VERSION 5.7 ;
BUSBITCHARS "[]" ;
DIVIDERCHAR "/" ;

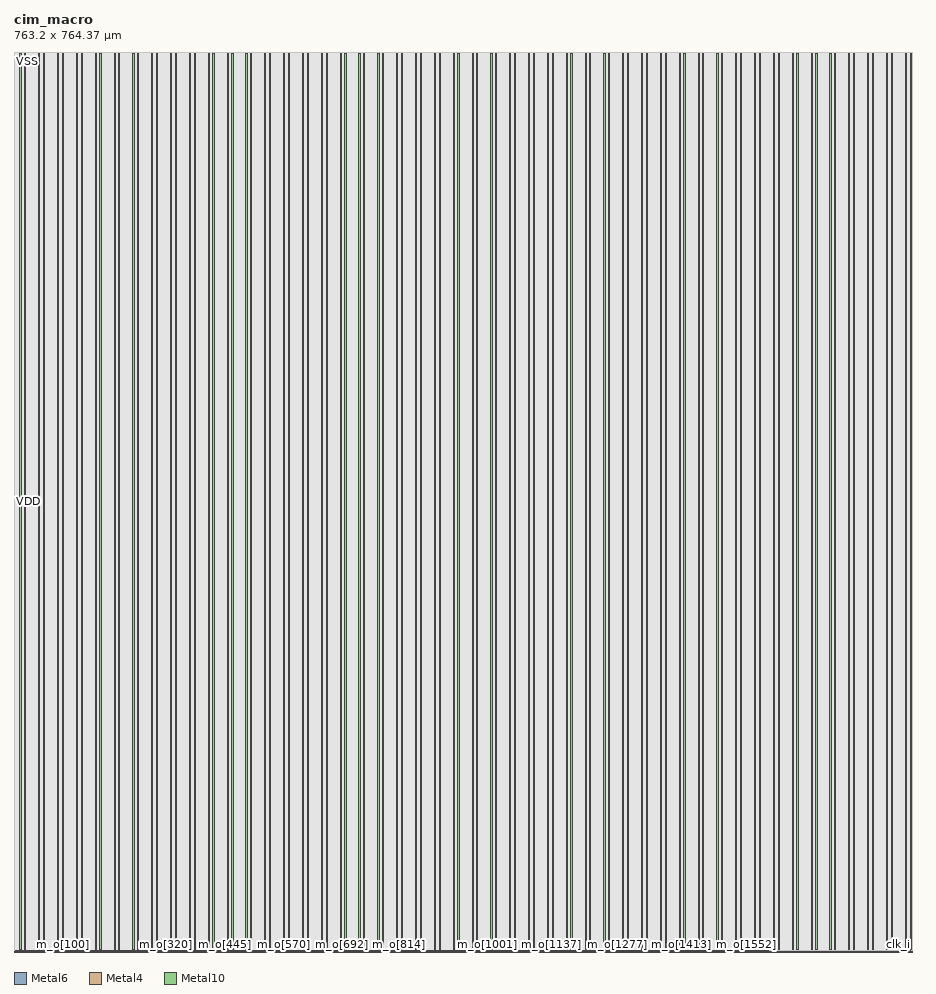
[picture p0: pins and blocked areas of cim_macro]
MACRO cim_macro
  CLASS BLOCK ;
  ORIGIN 0 0 ;
  FOREIGN cim_macro 0 0 ;
  SIZE 763.2 BY 764.37 ;
  SYMMETRY X Y R90 ;
  PIN clk_i
    DIRECTION INPUT ;
    USE CLOCK ;
    PORT
      LAYER Metal6 ;
        RECT 761.200 0 761.280 1.0 ;
    END
  END clk_i
  PIN m_valid_o
    DIRECTION OUTPUT ;
    USE SIGNAL ;
    PORT
      LAYER Metal4 ;
        RECT 1.000 0.000 1.080 1.000 ;
    END
  END m_valid_o
  PIN m_o[0]
    DIRECTION OUTPUT ;
    USE SIGNAL ;
    PORT
      LAYER Metal4 ;
        RECT 1.400 0.000 1.480 1.000 ;
    END
  END m_o[0]
  PIN m_o[1]
    DIRECTION OUTPUT ;
    USE SIGNAL ;
    PORT
      LAYER Metal4 ;
        RECT 1.800 0.000 1.880 1.000 ;
    END
  END m_o[1]
  PIN m_o[2]
    DIRECTION OUTPUT ;
    USE SIGNAL ;
    PORT
      LAYER Metal4 ;
        RECT 2.200 0.000 2.280 1.000 ;
    END
  END m_o[2]
  PIN m_o[3]
    DIRECTION OUTPUT ;
    USE SIGNAL ;
    PORT
      LAYER Metal4 ;
        RECT 2.600 0.000 2.680 1.000 ;
    END
  END m_o[3]
  PIN m_o[4]
    DIRECTION OUTPUT ;
    USE SIGNAL ;
    PORT
      LAYER Metal4 ;
        RECT 3.000 0.000 3.080 1.000 ;
    END
  END m_o[4]
  PIN m_o[5]
    DIRECTION OUTPUT ;
    USE SIGNAL ;
    PORT
      LAYER Metal4 ;
        RECT 3.400 0.000 3.480 1.000 ;
    END
  END m_o[5]
  PIN m_o[6]
    DIRECTION OUTPUT ;
    USE SIGNAL ;
    PORT
      LAYER Metal4 ;
        RECT 3.800 0.000 3.880 1.000 ;
    END
  END m_o[6]
  PIN m_o[7]
    DIRECTION OUTPUT ;
    USE SIGNAL ;
    PORT
      LAYER Metal4 ;
        RECT 4.200 0.000 4.280 1.000 ;
    END
  END m_o[7]
  PIN m_o[8]
    DIRECTION OUTPUT ;
    USE SIGNAL ;
    PORT
      LAYER Metal4 ;
        RECT 4.600 0.000 4.680 1.000 ;
    END
  END m_o[8]
  PIN m_o[9]
    DIRECTION OUTPUT ;
    USE SIGNAL ;
    PORT
      LAYER Metal4 ;
        RECT 5.000 0.000 5.080 1.000 ;
    END
  END m_o[9]
  PIN m_o[10]
    DIRECTION OUTPUT ;
    USE SIGNAL ;
    PORT
      LAYER Metal4 ;
        RECT 5.400 0.000 5.480 1.000 ;
    END
  END m_o[10]
  PIN m_o[11]
    DIRECTION OUTPUT ;
    USE SIGNAL ;
    PORT
      LAYER Metal4 ;
        RECT 5.800 0.000 5.880 1.000 ;
    END
  END m_o[11]
  PIN m_o[12]
    DIRECTION OUTPUT ;
    USE SIGNAL ;
    PORT
      LAYER Metal4 ;
        RECT 6.200 0.000 6.280 1.000 ;
    END
  END m_o[12]
  PIN m_o[13]
    DIRECTION OUTPUT ;
    USE SIGNAL ;
    PORT
      LAYER Metal4 ;
        RECT 6.600 0.000 6.680 1.000 ;
    END
  END m_o[13]
  PIN m_o[14]
    DIRECTION OUTPUT ;
    USE SIGNAL ;
    PORT
      LAYER Metal4 ;
        RECT 7.000 0.000 7.080 1.000 ;
    END
  END m_o[14]
  PIN m_o[15]
    DIRECTION OUTPUT ;
    USE SIGNAL ;
    PORT
      LAYER Metal4 ;
        RECT 7.400 0.000 7.480 1.000 ;
    END
  END m_o[15]
  PIN m_o[16]
    DIRECTION OUTPUT ;
    USE SIGNAL ;
    PORT
      LAYER Metal4 ;
        RECT 7.800 0.000 7.880 1.000 ;
    END
  END m_o[16]
  PIN m_o[17]
    DIRECTION OUTPUT ;
    USE SIGNAL ;
    PORT
      LAYER Metal4 ;
        RECT 8.200 0.000 8.280 1.000 ;
    END
  END m_o[17]
  PIN m_o[18]
    DIRECTION OUTPUT ;
    USE SIGNAL ;
    PORT
      LAYER Metal4 ;
        RECT 8.600 0.000 8.680 1.000 ;
    END
  END m_o[18]
  PIN m_o[19]
    DIRECTION OUTPUT ;
    USE SIGNAL ;
    PORT
      LAYER Metal4 ;
        RECT 9.000 0.000 9.080 1.000 ;
    END
  END m_o[19]
  PIN m_o[20]
    DIRECTION OUTPUT ;
    USE SIGNAL ;
    PORT
      LAYER Metal4 ;
        RECT 9.400 0.000 9.480 1.000 ;
    END
  END m_o[20]
  PIN m_o[21]
    DIRECTION OUTPUT ;
    USE SIGNAL ;
    PORT
      LAYER Metal4 ;
        RECT 9.800 0.000 9.880 1.000 ;
    END
  END m_o[21]
  PIN m_o[22]
    DIRECTION OUTPUT ;
    USE SIGNAL ;
    PORT
      LAYER Metal4 ;
        RECT 10.200 0.000 10.280 1.000 ;
    END
  END m_o[22]
  PIN m_o[23]
    DIRECTION OUTPUT ;
    USE SIGNAL ;
    PORT
      LAYER Metal4 ;
        RECT 10.600 0.000 10.680 1.000 ;
    END
  END m_o[23]
  PIN m_o[24]
    DIRECTION OUTPUT ;
    USE SIGNAL ;
    PORT
      LAYER Metal4 ;
        RECT 11.000 0.000 11.080 1.000 ;
    END
  END m_o[24]
  PIN m_o[25]
    DIRECTION OUTPUT ;
    USE SIGNAL ;
    PORT
      LAYER Metal4 ;
        RECT 11.400 0.000 11.480 1.000 ;
    END
  END m_o[25]
  PIN m_o[26]
    DIRECTION OUTPUT ;
    USE SIGNAL ;
    PORT
      LAYER Metal4 ;
        RECT 11.800 0.000 11.880 1.000 ;
    END
  END m_o[26]
  PIN m_o[27]
    DIRECTION OUTPUT ;
    USE SIGNAL ;
    PORT
      LAYER Metal4 ;
        RECT 12.200 0.000 12.280 1.000 ;
    END
  END m_o[27]
  PIN m_o[28]
    DIRECTION OUTPUT ;
    USE SIGNAL ;
    PORT
      LAYER Metal4 ;
        RECT 12.600 0.000 12.680 1.000 ;
    END
  END m_o[28]
  PIN m_o[29]
    DIRECTION OUTPUT ;
    USE SIGNAL ;
    PORT
      LAYER Metal4 ;
        RECT 13.000 0.000 13.080 1.000 ;
    END
  END m_o[29]
  PIN m_o[30]
    DIRECTION OUTPUT ;
    USE SIGNAL ;
    PORT
      LAYER Metal4 ;
        RECT 13.400 0.000 13.480 1.000 ;
    END
  END m_o[30]
  PIN m_o[31]
    DIRECTION OUTPUT ;
    USE SIGNAL ;
    PORT
      LAYER Metal4 ;
        RECT 13.800 0.000 13.880 1.000 ;
    END
  END m_o[31]
  PIN m_o[32]
    DIRECTION OUTPUT ;
    USE SIGNAL ;
    PORT
      LAYER Metal4 ;
        RECT 14.200 0.000 14.280 1.000 ;
    END
  END m_o[32]
  PIN m_o[33]
    DIRECTION OUTPUT ;
    USE SIGNAL ;
    PORT
      LAYER Metal4 ;
        RECT 14.600 0.000 14.680 1.000 ;
    END
  END m_o[33]
  PIN m_o[34]
    DIRECTION OUTPUT ;
    USE SIGNAL ;
    PORT
      LAYER Metal4 ;
        RECT 15.000 0.000 15.080 1.000 ;
    END
  END m_o[34]
  PIN m_o[35]
    DIRECTION OUTPUT ;
    USE SIGNAL ;
    PORT
      LAYER Metal4 ;
        RECT 15.400 0.000 15.480 1.000 ;
    END
  END m_o[35]
  PIN m_o[36]
    DIRECTION OUTPUT ;
    USE SIGNAL ;
    PORT
      LAYER Metal4 ;
        RECT 15.800 0.000 15.880 1.000 ;
    END
  END m_o[36]
  PIN m_o[37]
    DIRECTION OUTPUT ;
    USE SIGNAL ;
    PORT
      LAYER Metal4 ;
        RECT 16.200 0.000 16.280 1.000 ;
    END
  END m_o[37]
  PIN m_o[38]
    DIRECTION OUTPUT ;
    USE SIGNAL ;
    PORT
      LAYER Metal4 ;
        RECT 16.600 0.000 16.680 1.000 ;
    END
  END m_o[38]
  PIN m_o[39]
    DIRECTION OUTPUT ;
    USE SIGNAL ;
    PORT
      LAYER Metal4 ;
        RECT 17.000 0.000 17.080 1.000 ;
    END
  END m_o[39]
  PIN m_o[40]
    DIRECTION OUTPUT ;
    USE SIGNAL ;
    PORT
      LAYER Metal4 ;
        RECT 17.400 0.000 17.480 1.000 ;
    END
  END m_o[40]
  PIN m_o[41]
    DIRECTION OUTPUT ;
    USE SIGNAL ;
    PORT
      LAYER Metal4 ;
        RECT 17.800 0.000 17.880 1.000 ;
    END
  END m_o[41]
  PIN m_o[42]
    DIRECTION OUTPUT ;
    USE SIGNAL ;
    PORT
      LAYER Metal4 ;
        RECT 18.200 0.000 18.280 1.000 ;
    END
  END m_o[42]
  PIN m_o[43]
    DIRECTION OUTPUT ;
    USE SIGNAL ;
    PORT
      LAYER Metal4 ;
        RECT 18.600 0.000 18.680 1.000 ;
    END
  END m_o[43]
  PIN m_o[44]
    DIRECTION OUTPUT ;
    USE SIGNAL ;
    PORT
      LAYER Metal4 ;
        RECT 19.000 0.000 19.080 1.000 ;
    END
  END m_o[44]
  PIN m_o[45]
    DIRECTION OUTPUT ;
    USE SIGNAL ;
    PORT
      LAYER Metal4 ;
        RECT 19.400 0.000 19.480 1.000 ;
    END
  END m_o[45]
  PIN m_o[46]
    DIRECTION OUTPUT ;
    USE SIGNAL ;
    PORT
      LAYER Metal4 ;
        RECT 19.800 0.000 19.880 1.000 ;
    END
  END m_o[46]
  PIN m_o[47]
    DIRECTION OUTPUT ;
    USE SIGNAL ;
    PORT
      LAYER Metal4 ;
        RECT 20.200 0.000 20.280 1.000 ;
    END
  END m_o[47]
  PIN m_o[48]
    DIRECTION OUTPUT ;
    USE SIGNAL ;
    PORT
      LAYER Metal4 ;
        RECT 20.600 0.000 20.680 1.000 ;
    END
  END m_o[48]
  PIN m_o[49]
    DIRECTION OUTPUT ;
    USE SIGNAL ;
    PORT
      LAYER Metal4 ;
        RECT 21.000 0.000 21.080 1.000 ;
    END
  END m_o[49]
  PIN m_o[50]
    DIRECTION OUTPUT ;
    USE SIGNAL ;
    PORT
      LAYER Metal4 ;
        RECT 21.400 0.000 21.480 1.000 ;
    END
  END m_o[50]
  PIN m_o[51]
    DIRECTION OUTPUT ;
    USE SIGNAL ;
    PORT
      LAYER Metal4 ;
        RECT 21.800 0.000 21.880 1.000 ;
    END
  END m_o[51]
  PIN m_o[52]
    DIRECTION OUTPUT ;
    USE SIGNAL ;
    PORT
      LAYER Metal4 ;
        RECT 22.200 0.000 22.280 1.000 ;
    END
  END m_o[52]
  PIN m_o[53]
    DIRECTION OUTPUT ;
    USE SIGNAL ;
    PORT
      LAYER Metal4 ;
        RECT 22.600 0.000 22.680 1.000 ;
    END
  END m_o[53]
  PIN m_o[54]
    DIRECTION OUTPUT ;
    USE SIGNAL ;
    PORT
      LAYER Metal4 ;
        RECT 23.000 0.000 23.080 1.000 ;
    END
  END m_o[54]
  PIN m_o[55]
    DIRECTION OUTPUT ;
    USE SIGNAL ;
    PORT
      LAYER Metal4 ;
        RECT 23.400 0.000 23.480 1.000 ;
    END
  END m_o[55]
  PIN m_o[56]
    DIRECTION OUTPUT ;
    USE SIGNAL ;
    PORT
      LAYER Metal4 ;
        RECT 23.800 0.000 23.880 1.000 ;
    END
  END m_o[56]
  PIN m_o[57]
    DIRECTION OUTPUT ;
    USE SIGNAL ;
    PORT
      LAYER Metal4 ;
        RECT 24.200 0.000 24.280 1.000 ;
    END
  END m_o[57]
  PIN m_o[58]
    DIRECTION OUTPUT ;
    USE SIGNAL ;
    PORT
      LAYER Metal4 ;
        RECT 24.600 0.000 24.680 1.000 ;
    END
  END m_o[58]
  PIN m_o[59]
    DIRECTION OUTPUT ;
    USE SIGNAL ;
    PORT
      LAYER Metal4 ;
        RECT 25.000 0.000 25.080 1.000 ;
    END
  END m_o[59]
  PIN m_o[60]
    DIRECTION OUTPUT ;
    USE SIGNAL ;
    PORT
      LAYER Metal4 ;
        RECT 25.400 0.000 25.480 1.000 ;
    END
  END m_o[60]
  PIN m_o[61]
    DIRECTION OUTPUT ;
    USE SIGNAL ;
    PORT
      LAYER Metal4 ;
        RECT 25.800 0.000 25.880 1.000 ;
    END
  END m_o[61]
  PIN m_o[62]
    DIRECTION OUTPUT ;
    USE SIGNAL ;
    PORT
      LAYER Metal4 ;
        RECT 26.200 0.000 26.280 1.000 ;
    END
  END m_o[62]
  PIN m_o[63]
    DIRECTION OUTPUT ;
    USE SIGNAL ;
    PORT
      LAYER Metal4 ;
        RECT 26.600 0.000 26.680 1.000 ;
    END
  END m_o[63]
  PIN m_o[64]
    DIRECTION OUTPUT ;
    USE SIGNAL ;
    PORT
      LAYER Metal4 ;
        RECT 27.000 0.000 27.080 1.000 ;
    END
  END m_o[64]
  PIN m_o[65]
    DIRECTION OUTPUT ;
    USE SIGNAL ;
    PORT
      LAYER Metal4 ;
        RECT 27.400 0.000 27.480 1.000 ;
    END
  END m_o[65]
  PIN m_o[66]
    DIRECTION OUTPUT ;
    USE SIGNAL ;
    PORT
      LAYER Metal4 ;
        RECT 27.800 0.000 27.880 1.000 ;
    END
  END m_o[66]
  PIN m_o[67]
    DIRECTION OUTPUT ;
    USE SIGNAL ;
    PORT
      LAYER Metal4 ;
        RECT 28.200 0.000 28.280 1.000 ;
    END
  END m_o[67]
  PIN m_o[68]
    DIRECTION OUTPUT ;
    USE SIGNAL ;
    PORT
      LAYER Metal4 ;
        RECT 28.600 0.000 28.680 1.000 ;
    END
  END m_o[68]
  PIN m_o[69]
    DIRECTION OUTPUT ;
    USE SIGNAL ;
    PORT
      LAYER Metal4 ;
        RECT 29.000 0.000 29.080 1.000 ;
    END
  END m_o[69]
  PIN m_o[70]
    DIRECTION OUTPUT ;
    USE SIGNAL ;
    PORT
      LAYER Metal4 ;
        RECT 29.400 0.000 29.480 1.000 ;
    END
  END m_o[70]
  PIN m_o[71]
    DIRECTION OUTPUT ;
    USE SIGNAL ;
    PORT
      LAYER Metal4 ;
        RECT 29.800 0.000 29.880 1.000 ;
    END
  END m_o[71]
  PIN m_o[72]
    DIRECTION OUTPUT ;
    USE SIGNAL ;
    PORT
      LAYER Metal4 ;
        RECT 30.200 0.000 30.280 1.000 ;
    END
  END m_o[72]
  PIN m_o[73]
    DIRECTION OUTPUT ;
    USE SIGNAL ;
    PORT
      LAYER Metal4 ;
        RECT 30.600 0.000 30.680 1.000 ;
    END
  END m_o[73]
  PIN m_o[74]
    DIRECTION OUTPUT ;
    USE SIGNAL ;
    PORT
      LAYER Metal4 ;
        RECT 31.000 0.000 31.080 1.000 ;
    END
  END m_o[74]
  PIN m_o[75]
    DIRECTION OUTPUT ;
    USE SIGNAL ;
    PORT
      LAYER Metal4 ;
        RECT 31.400 0.000 31.480 1.000 ;
    END
  END m_o[75]
  PIN m_o[76]
    DIRECTION OUTPUT ;
    USE SIGNAL ;
    PORT
      LAYER Metal4 ;
        RECT 31.800 0.000 31.880 1.000 ;
    END
  END m_o[76]
  PIN m_o[77]
    DIRECTION OUTPUT ;
    USE SIGNAL ;
    PORT
      LAYER Metal4 ;
        RECT 32.200 0.000 32.280 1.000 ;
    END
  END m_o[77]
  PIN m_o[78]
    DIRECTION OUTPUT ;
    USE SIGNAL ;
    PORT
      LAYER Metal4 ;
        RECT 32.600 0.000 32.680 1.000 ;
    END
  END m_o[78]
  PIN m_o[79]
    DIRECTION OUTPUT ;
    USE SIGNAL ;
    PORT
      LAYER Metal4 ;
        RECT 33.000 0.000 33.080 1.000 ;
    END
  END m_o[79]
  PIN m_o[80]
    DIRECTION OUTPUT ;
    USE SIGNAL ;
    PORT
      LAYER Metal4 ;
        RECT 33.400 0.000 33.480 1.000 ;
    END
  END m_o[80]
  PIN m_o[81]
    DIRECTION OUTPUT ;
    USE SIGNAL ;
    PORT
      LAYER Metal4 ;
        RECT 33.800 0.000 33.880 1.000 ;
    END
  END m_o[81]
  PIN m_o[82]
    DIRECTION OUTPUT ;
    USE SIGNAL ;
    PORT
      LAYER Metal4 ;
        RECT 34.200 0.000 34.280 1.000 ;
    END
  END m_o[82]
  PIN m_o[83]
    DIRECTION OUTPUT ;
    USE SIGNAL ;
    PORT
      LAYER Metal4 ;
        RECT 34.600 0.000 34.680 1.000 ;
    END
  END m_o[83]
  PIN m_o[84]
    DIRECTION OUTPUT ;
    USE SIGNAL ;
    PORT
      LAYER Metal4 ;
        RECT 35.000 0.000 35.080 1.000 ;
    END
  END m_o[84]
  PIN m_o[85]
    DIRECTION OUTPUT ;
    USE SIGNAL ;
    PORT
      LAYER Metal4 ;
        RECT 35.400 0.000 35.480 1.000 ;
    END
  END m_o[85]
  PIN m_o[86]
    DIRECTION OUTPUT ;
    USE SIGNAL ;
    PORT
      LAYER Metal4 ;
        RECT 35.800 0.000 35.880 1.000 ;
    END
  END m_o[86]
  PIN m_o[87]
    DIRECTION OUTPUT ;
    USE SIGNAL ;
    PORT
      LAYER Metal4 ;
        RECT 36.200 0.000 36.280 1.000 ;
    END
  END m_o[87]
  PIN m_o[88]
    DIRECTION OUTPUT ;
    USE SIGNAL ;
    PORT
      LAYER Metal4 ;
        RECT 36.600 0.000 36.680 1.000 ;
    END
  END m_o[88]
  PIN m_o[89]
    DIRECTION OUTPUT ;
    USE SIGNAL ;
    PORT
      LAYER Metal4 ;
        RECT 37.000 0.000 37.080 1.000 ;
    END
  END m_o[89]
  PIN m_o[90]
    DIRECTION OUTPUT ;
    USE SIGNAL ;
    PORT
      LAYER Metal4 ;
        RECT 37.400 0.000 37.480 1.000 ;
    END
  END m_o[90]
  PIN m_o[91]
    DIRECTION OUTPUT ;
    USE SIGNAL ;
    PORT
      LAYER Metal4 ;
        RECT 37.800 0.000 37.880 1.000 ;
    END
  END m_o[91]
  PIN m_o[92]
    DIRECTION OUTPUT ;
    USE SIGNAL ;
    PORT
      LAYER Metal4 ;
        RECT 38.200 0.000 38.280 1.000 ;
    END
  END m_o[92]
  PIN m_o[93]
    DIRECTION OUTPUT ;
    USE SIGNAL ;
    PORT
      LAYER Metal4 ;
        RECT 38.600 0.000 38.680 1.000 ;
    END
  END m_o[93]
  PIN m_o[94]
    DIRECTION OUTPUT ;
    USE SIGNAL ;
    PORT
      LAYER Metal4 ;
        RECT 39.000 0.000 39.080 1.000 ;
    END
  END m_o[94]
  PIN m_o[95]
    DIRECTION OUTPUT ;
    USE SIGNAL ;
    PORT
      LAYER Metal4 ;
        RECT 39.400 0.000 39.480 1.000 ;
    END
  END m_o[95]
  PIN m_o[96]
    DIRECTION OUTPUT ;
    USE SIGNAL ;
    PORT
      LAYER Metal4 ;
        RECT 39.800 0.000 39.880 1.000 ;
    END
  END m_o[96]
  PIN m_o[97]
    DIRECTION OUTPUT ;
    USE SIGNAL ;
    PORT
      LAYER Metal4 ;
        RECT 40.200 0.000 40.280 1.000 ;
    END
  END m_o[97]
  PIN m_o[98]
    DIRECTION OUTPUT ;
    USE SIGNAL ;
    PORT
      LAYER Metal4 ;
        RECT 40.600 0.000 40.680 1.000 ;
    END
  END m_o[98]
  PIN m_o[99]
    DIRECTION OUTPUT ;
    USE SIGNAL ;
    PORT
      LAYER Metal4 ;
        RECT 41.000 0.000 41.080 1.000 ;
    END
  END m_o[99]
  PIN m_o[100]
    DIRECTION OUTPUT ;
    USE SIGNAL ;
    PORT
      LAYER Metal4 ;
        RECT 41.400 0.000 41.480 1.000 ;
    END
  END m_o[100]
  PIN m_o[101]
    DIRECTION OUTPUT ;
    USE SIGNAL ;
    PORT
      LAYER Metal4 ;
        RECT 41.800 0.000 41.880 1.000 ;
    END
  END m_o[101]
  PIN m_o[102]
    DIRECTION OUTPUT ;
    USE SIGNAL ;
    PORT
      LAYER Metal4 ;
        RECT 42.200 0.000 42.280 1.000 ;
    END
  END m_o[102]
  PIN m_o[103]
    DIRECTION OUTPUT ;
    USE SIGNAL ;
    PORT
      LAYER Metal4 ;
        RECT 42.600 0.000 42.680 1.000 ;
    END
  END m_o[103]
  PIN m_o[104]
    DIRECTION OUTPUT ;
    USE SIGNAL ;
    PORT
      LAYER Metal4 ;
        RECT 43.000 0.000 43.080 1.000 ;
    END
  END m_o[104]
  PIN m_o[105]
    DIRECTION OUTPUT ;
    USE SIGNAL ;
    PORT
      LAYER Metal4 ;
        RECT 43.400 0.000 43.480 1.000 ;
    END
  END m_o[105]
  PIN m_o[106]
    DIRECTION OUTPUT ;
    USE SIGNAL ;
    PORT
      LAYER Metal4 ;
        RECT 43.800 0.000 43.880 1.000 ;
    END
  END m_o[106]
  PIN m_o[107]
    DIRECTION OUTPUT ;
    USE SIGNAL ;
    PORT
      LAYER Metal4 ;
        RECT 44.200 0.000 44.280 1.000 ;
    END
  END m_o[107]
  PIN m_o[108]
    DIRECTION OUTPUT ;
    USE SIGNAL ;
    PORT
      LAYER Metal4 ;
        RECT 44.600 0.000 44.680 1.000 ;
    END
  END m_o[108]
  PIN m_o[109]
    DIRECTION OUTPUT ;
    USE SIGNAL ;
    PORT
      LAYER Metal4 ;
        RECT 45.000 0.000 45.080 1.000 ;
    END
  END m_o[109]
  PIN m_o[110]
    DIRECTION OUTPUT ;
    USE SIGNAL ;
    PORT
      LAYER Metal4 ;
        RECT 45.400 0.000 45.480 1.000 ;
    END
  END m_o[110]
  PIN m_o[111]
    DIRECTION OUTPUT ;
    USE SIGNAL ;
    PORT
      LAYER Metal4 ;
        RECT 45.800 0.000 45.880 1.000 ;
    END
  END m_o[111]
  PIN m_o[112]
    DIRECTION OUTPUT ;
    USE SIGNAL ;
    PORT
      LAYER Metal4 ;
        RECT 46.200 0.000 46.280 1.000 ;
    END
  END m_o[112]
  PIN m_o[113]
    DIRECTION OUTPUT ;
    USE SIGNAL ;
    PORT
      LAYER Metal4 ;
        RECT 46.600 0.000 46.680 1.000 ;
    END
  END m_o[113]
  PIN m_o[114]
    DIRECTION OUTPUT ;
    USE SIGNAL ;
    PORT
      LAYER Metal4 ;
        RECT 47.000 0.000 47.080 1.000 ;
    END
  END m_o[114]
  PIN m_o[115]
    DIRECTION OUTPUT ;
    USE SIGNAL ;
    PORT
      LAYER Metal4 ;
        RECT 47.400 0.000 47.480 1.000 ;
    END
  END m_o[115]
  PIN m_o[116]
    DIRECTION OUTPUT ;
    USE SIGNAL ;
    PORT
      LAYER Metal4 ;
        RECT 47.800 0.000 47.880 1.000 ;
    END
  END m_o[116]
  PIN m_o[117]
    DIRECTION OUTPUT ;
    USE SIGNAL ;
    PORT
      LAYER Metal4 ;
        RECT 48.200 0.000 48.280 1.000 ;
    END
  END m_o[117]
  PIN m_o[118]
    DIRECTION OUTPUT ;
    USE SIGNAL ;
    PORT
      LAYER Metal4 ;
        RECT 48.600 0.000 48.680 1.000 ;
    END
  END m_o[118]
  PIN m_o[119]
    DIRECTION OUTPUT ;
    USE SIGNAL ;
    PORT
      LAYER Metal4 ;
        RECT 49.000 0.000 49.080 1.000 ;
    END
  END m_o[119]
  PIN m_o[120]
    DIRECTION OUTPUT ;
    USE SIGNAL ;
    PORT
      LAYER Metal4 ;
        RECT 49.400 0.000 49.480 1.000 ;
    END
  END m_o[120]
  PIN m_o[121]
    DIRECTION OUTPUT ;
    USE SIGNAL ;
    PORT
      LAYER Metal4 ;
        RECT 49.800 0.000 49.880 1.000 ;
    END
  END m_o[121]
  PIN m_o[122]
    DIRECTION OUTPUT ;
    USE SIGNAL ;
    PORT
      LAYER Metal4 ;
        RECT 50.200 0.000 50.280 1.000 ;
    END
  END m_o[122]
  PIN m_o[123]
    DIRECTION OUTPUT ;
    USE SIGNAL ;
    PORT
      LAYER Metal4 ;
        RECT 50.600 0.000 50.680 1.000 ;
    END
  END m_o[123]
  PIN m_o[124]
    DIRECTION OUTPUT ;
    USE SIGNAL ;
    PORT
      LAYER Metal4 ;
        RECT 51.000 0.000 51.080 1.000 ;
    END
  END m_o[124]
  PIN m_o[125]
    DIRECTION OUTPUT ;
    USE SIGNAL ;
    PORT
      LAYER Metal4 ;
        RECT 51.400 0.000 51.480 1.000 ;
    END
  END m_o[125]
  PIN m_o[126]
    DIRECTION OUTPUT ;
    USE SIGNAL ;
    PORT
      LAYER Metal4 ;
        RECT 51.800 0.000 51.880 1.000 ;
    END
  END m_o[126]
  PIN m_o[127]
    DIRECTION OUTPUT ;
    USE SIGNAL ;
    PORT
      LAYER Metal4 ;
        RECT 52.200 0.000 52.280 1.000 ;
    END
  END m_o[127]
  PIN m_o[128]
    DIRECTION OUTPUT ;
    USE SIGNAL ;
    PORT
      LAYER Metal4 ;
        RECT 52.600 0.000 52.680 1.000 ;
    END
  END m_o[128]
  PIN m_o[129]
    DIRECTION OUTPUT ;
    USE SIGNAL ;
    PORT
      LAYER Metal4 ;
        RECT 53.000 0.000 53.080 1.000 ;
    END
  END m_o[129]
  PIN m_o[130]
    DIRECTION OUTPUT ;
    USE SIGNAL ;
    PORT
      LAYER Metal4 ;
        RECT 53.400 0.000 53.480 1.000 ;
    END
  END m_o[130]
  PIN m_o[131]
    DIRECTION OUTPUT ;
    USE SIGNAL ;
    PORT
      LAYER Metal4 ;
        RECT 53.800 0.000 53.880 1.000 ;
    END
  END m_o[131]
  PIN m_o[132]
    DIRECTION OUTPUT ;
    USE SIGNAL ;
    PORT
      LAYER Metal4 ;
        RECT 54.200 0.000 54.280 1.000 ;
    END
  END m_o[132]
  PIN m_o[133]
    DIRECTION OUTPUT ;
    USE SIGNAL ;
    PORT
      LAYER Metal4 ;
        RECT 54.600 0.000 54.680 1.000 ;
    END
  END m_o[133]
  PIN m_o[134]
    DIRECTION OUTPUT ;
    USE SIGNAL ;
    PORT
      LAYER Metal4 ;
        RECT 55.000 0.000 55.080 1.000 ;
    END
  END m_o[134]
  PIN m_o[135]
    DIRECTION OUTPUT ;
    USE SIGNAL ;
    PORT
      LAYER Metal4 ;
        RECT 55.400 0.000 55.480 1.000 ;
    END
  END m_o[135]
  PIN m_o[136]
    DIRECTION OUTPUT ;
    USE SIGNAL ;
    PORT
      LAYER Metal4 ;
        RECT 55.800 0.000 55.880 1.000 ;
    END
  END m_o[136]
  PIN m_o[137]
    DIRECTION OUTPUT ;
    USE SIGNAL ;
    PORT
      LAYER Metal4 ;
        RECT 56.200 0.000 56.280 1.000 ;
    END
  END m_o[137]
  PIN m_o[138]
    DIRECTION OUTPUT ;
    USE SIGNAL ;
    PORT
      LAYER Metal4 ;
        RECT 56.600 0.000 56.680 1.000 ;
    END
  END m_o[138]
  PIN m_o[139]
    DIRECTION OUTPUT ;
    USE SIGNAL ;
    PORT
      LAYER Metal4 ;
        RECT 57.000 0.000 57.080 1.000 ;
    END
  END m_o[139]
  PIN m_o[140]
    DIRECTION OUTPUT ;
    USE SIGNAL ;
    PORT
      LAYER Metal4 ;
        RECT 57.400 0.000 57.480 1.000 ;
    END
  END m_o[140]
  PIN m_o[141]
    DIRECTION OUTPUT ;
    USE SIGNAL ;
    PORT
      LAYER Metal4 ;
        RECT 57.800 0.000 57.880 1.000 ;
    END
  END m_o[141]
  PIN m_o[142]
    DIRECTION OUTPUT ;
    USE SIGNAL ;
    PORT
      LAYER Metal4 ;
        RECT 58.200 0.000 58.280 1.000 ;
    END
  END m_o[142]
  PIN m_o[143]
    DIRECTION OUTPUT ;
    USE SIGNAL ;
    PORT
      LAYER Metal4 ;
        RECT 58.600 0.000 58.680 1.000 ;
    END
  END m_o[143]
  PIN m_o[144]
    DIRECTION OUTPUT ;
    USE SIGNAL ;
    PORT
      LAYER Metal4 ;
        RECT 59.000 0.000 59.080 1.000 ;
    END
  END m_o[144]
  PIN m_o[145]
    DIRECTION OUTPUT ;
    USE SIGNAL ;
    PORT
      LAYER Metal4 ;
        RECT 59.400 0.000 59.480 1.000 ;
    END
  END m_o[145]
  PIN m_o[146]
    DIRECTION OUTPUT ;
    USE SIGNAL ;
    PORT
      LAYER Metal4 ;
        RECT 59.800 0.000 59.880 1.000 ;
    END
  END m_o[146]
  PIN m_o[147]
    DIRECTION OUTPUT ;
    USE SIGNAL ;
    PORT
      LAYER Metal4 ;
        RECT 60.200 0.000 60.280 1.000 ;
    END
  END m_o[147]
  PIN m_o[148]
    DIRECTION OUTPUT ;
    USE SIGNAL ;
    PORT
      LAYER Metal4 ;
        RECT 60.600 0.000 60.680 1.000 ;
    END
  END m_o[148]
  PIN m_o[149]
    DIRECTION OUTPUT ;
    USE SIGNAL ;
    PORT
      LAYER Metal4 ;
        RECT 61.000 0.000 61.080 1.000 ;
    END
  END m_o[149]
  PIN m_o[150]
    DIRECTION OUTPUT ;
    USE SIGNAL ;
    PORT
      LAYER Metal4 ;
        RECT 61.400 0.000 61.480 1.000 ;
    END
  END m_o[150]
  PIN m_o[151]
    DIRECTION OUTPUT ;
    USE SIGNAL ;
    PORT
      LAYER Metal4 ;
        RECT 61.800 0.000 61.880 1.000 ;
    END
  END m_o[151]
  PIN m_o[152]
    DIRECTION OUTPUT ;
    USE SIGNAL ;
    PORT
      LAYER Metal4 ;
        RECT 62.200 0.000 62.280 1.000 ;
    END
  END m_o[152]
  PIN m_o[153]
    DIRECTION OUTPUT ;
    USE SIGNAL ;
    PORT
      LAYER Metal4 ;
        RECT 62.600 0.000 62.680 1.000 ;
    END
  END m_o[153]
  PIN m_o[154]
    DIRECTION OUTPUT ;
    USE SIGNAL ;
    PORT
      LAYER Metal4 ;
        RECT 63.000 0.000 63.080 1.000 ;
    END
  END m_o[154]
  PIN m_o[155]
    DIRECTION OUTPUT ;
    USE SIGNAL ;
    PORT
      LAYER Metal4 ;
        RECT 63.400 0.000 63.480 1.000 ;
    END
  END m_o[155]
  PIN m_o[156]
    DIRECTION OUTPUT ;
    USE SIGNAL ;
    PORT
      LAYER Metal4 ;
        RECT 63.800 0.000 63.880 1.000 ;
    END
  END m_o[156]
  PIN m_o[157]
    DIRECTION OUTPUT ;
    USE SIGNAL ;
    PORT
      LAYER Metal4 ;
        RECT 64.200 0.000 64.280 1.000 ;
    END
  END m_o[157]
  PIN m_o[158]
    DIRECTION OUTPUT ;
    USE SIGNAL ;
    PORT
      LAYER Metal4 ;
        RECT 64.600 0.000 64.680 1.000 ;
    END
  END m_o[158]
  PIN m_o[159]
    DIRECTION OUTPUT ;
    USE SIGNAL ;
    PORT
      LAYER Metal4 ;
        RECT 65.000 0.000 65.080 1.000 ;
    END
  END m_o[159]
  PIN m_o[160]
    DIRECTION OUTPUT ;
    USE SIGNAL ;
    PORT
      LAYER Metal4 ;
        RECT 65.400 0.000 65.480 1.000 ;
    END
  END m_o[160]
  PIN m_o[161]
    DIRECTION OUTPUT ;
    USE SIGNAL ;
    PORT
      LAYER Metal4 ;
        RECT 65.800 0.000 65.880 1.000 ;
    END
  END m_o[161]
  PIN m_o[162]
    DIRECTION OUTPUT ;
    USE SIGNAL ;
    PORT
      LAYER Metal4 ;
        RECT 66.200 0.000 66.280 1.000 ;
    END
  END m_o[162]
  PIN m_o[163]
    DIRECTION OUTPUT ;
    USE SIGNAL ;
    PORT
      LAYER Metal4 ;
        RECT 66.600 0.000 66.680 1.000 ;
    END
  END m_o[163]
  PIN m_o[164]
    DIRECTION OUTPUT ;
    USE SIGNAL ;
    PORT
      LAYER Metal4 ;
        RECT 67.000 0.000 67.080 1.000 ;
    END
  END m_o[164]
  PIN m_o[165]
    DIRECTION OUTPUT ;
    USE SIGNAL ;
    PORT
      LAYER Metal4 ;
        RECT 67.400 0.000 67.480 1.000 ;
    END
  END m_o[165]
  PIN m_o[166]
    DIRECTION OUTPUT ;
    USE SIGNAL ;
    PORT
      LAYER Metal4 ;
        RECT 67.800 0.000 67.880 1.000 ;
    END
  END m_o[166]
  PIN m_o[167]
    DIRECTION OUTPUT ;
    USE SIGNAL ;
    PORT
      LAYER Metal4 ;
        RECT 68.200 0.000 68.280 1.000 ;
    END
  END m_o[167]
  PIN m_o[168]
    DIRECTION OUTPUT ;
    USE SIGNAL ;
    PORT
      LAYER Metal4 ;
        RECT 68.600 0.000 68.680 1.000 ;
    END
  END m_o[168]
  PIN m_o[169]
    DIRECTION OUTPUT ;
    USE SIGNAL ;
    PORT
      LAYER Metal4 ;
        RECT 69.000 0.000 69.080 1.000 ;
    END
  END m_o[169]
  PIN m_o[170]
    DIRECTION OUTPUT ;
    USE SIGNAL ;
    PORT
      LAYER Metal4 ;
        RECT 69.400 0.000 69.480 1.000 ;
    END
  END m_o[170]
  PIN m_o[171]
    DIRECTION OUTPUT ;
    USE SIGNAL ;
    PORT
      LAYER Metal4 ;
        RECT 69.800 0.000 69.880 1.000 ;
    END
  END m_o[171]
  PIN m_o[172]
    DIRECTION OUTPUT ;
    USE SIGNAL ;
    PORT
      LAYER Metal4 ;
        RECT 70.200 0.000 70.280 1.000 ;
    END
  END m_o[172]
  PIN m_o[173]
    DIRECTION OUTPUT ;
    USE SIGNAL ;
    PORT
      LAYER Metal4 ;
        RECT 70.600 0.000 70.680 1.000 ;
    END
  END m_o[173]
  PIN m_o[174]
    DIRECTION OUTPUT ;
    USE SIGNAL ;
    PORT
      LAYER Metal4 ;
        RECT 71.000 0.000 71.080 1.000 ;
    END
  END m_o[174]
  PIN m_o[175]
    DIRECTION OUTPUT ;
    USE SIGNAL ;
    PORT
      LAYER Metal4 ;
        RECT 71.400 0.000 71.480 1.000 ;
    END
  END m_o[175]
  PIN m_o[176]
    DIRECTION OUTPUT ;
    USE SIGNAL ;
    PORT
      LAYER Metal4 ;
        RECT 71.800 0.000 71.880 1.000 ;
    END
  END m_o[176]
  PIN m_o[177]
    DIRECTION OUTPUT ;
    USE SIGNAL ;
    PORT
      LAYER Metal4 ;
        RECT 72.200 0.000 72.280 1.000 ;
    END
  END m_o[177]
  PIN m_o[178]
    DIRECTION OUTPUT ;
    USE SIGNAL ;
    PORT
      LAYER Metal4 ;
        RECT 72.600 0.000 72.680 1.000 ;
    END
  END m_o[178]
  PIN m_o[179]
    DIRECTION OUTPUT ;
    USE SIGNAL ;
    PORT
      LAYER Metal4 ;
        RECT 73.000 0.000 73.080 1.000 ;
    END
  END m_o[179]
  PIN m_o[180]
    DIRECTION OUTPUT ;
    USE SIGNAL ;
    PORT
      LAYER Metal4 ;
        RECT 73.400 0.000 73.480 1.000 ;
    END
  END m_o[180]
  PIN m_o[181]
    DIRECTION OUTPUT ;
    USE SIGNAL ;
    PORT
      LAYER Metal4 ;
        RECT 73.800 0.000 73.880 1.000 ;
    END
  END m_o[181]
  PIN m_o[182]
    DIRECTION OUTPUT ;
    USE SIGNAL ;
    PORT
      LAYER Metal4 ;
        RECT 74.200 0.000 74.280 1.000 ;
    END
  END m_o[182]
  PIN m_o[183]
    DIRECTION OUTPUT ;
    USE SIGNAL ;
    PORT
      LAYER Metal4 ;
        RECT 74.600 0.000 74.680 1.000 ;
    END
  END m_o[183]
  PIN m_o[184]
    DIRECTION OUTPUT ;
    USE SIGNAL ;
    PORT
      LAYER Metal4 ;
        RECT 75.000 0.000 75.080 1.000 ;
    END
  END m_o[184]
  PIN m_o[185]
    DIRECTION OUTPUT ;
    USE SIGNAL ;
    PORT
      LAYER Metal4 ;
        RECT 75.400 0.000 75.480 1.000 ;
    END
  END m_o[185]
  PIN m_o[186]
    DIRECTION OUTPUT ;
    USE SIGNAL ;
    PORT
      LAYER Metal4 ;
        RECT 75.800 0.000 75.880 1.000 ;
    END
  END m_o[186]
  PIN m_o[187]
    DIRECTION OUTPUT ;
    USE SIGNAL ;
    PORT
      LAYER Metal4 ;
        RECT 76.200 0.000 76.280 1.000 ;
    END
  END m_o[187]
  PIN m_o[188]
    DIRECTION OUTPUT ;
    USE SIGNAL ;
    PORT
      LAYER Metal4 ;
        RECT 76.600 0.000 76.680 1.000 ;
    END
  END m_o[188]
  PIN m_o[189]
    DIRECTION OUTPUT ;
    USE SIGNAL ;
    PORT
      LAYER Metal4 ;
        RECT 77.000 0.000 77.080 1.000 ;
    END
  END m_o[189]
  PIN m_o[190]
    DIRECTION OUTPUT ;
    USE SIGNAL ;
    PORT
      LAYER Metal4 ;
        RECT 77.400 0.000 77.480 1.000 ;
    END
  END m_o[190]
  PIN m_o[191]
    DIRECTION OUTPUT ;
    USE SIGNAL ;
    PORT
      LAYER Metal4 ;
        RECT 77.800 0.000 77.880 1.000 ;
    END
  END m_o[191]
  PIN m_o[192]
    DIRECTION OUTPUT ;
    USE SIGNAL ;
    PORT
      LAYER Metal4 ;
        RECT 78.200 0.000 78.280 1.000 ;
    END
  END m_o[192]
  PIN m_o[193]
    DIRECTION OUTPUT ;
    USE SIGNAL ;
    PORT
      LAYER Metal4 ;
        RECT 78.600 0.000 78.680 1.000 ;
    END
  END m_o[193]
  PIN m_o[194]
    DIRECTION OUTPUT ;
    USE SIGNAL ;
    PORT
      LAYER Metal4 ;
        RECT 79.000 0.000 79.080 1.000 ;
    END
  END m_o[194]
  PIN m_o[195]
    DIRECTION OUTPUT ;
    USE SIGNAL ;
    PORT
      LAYER Metal4 ;
        RECT 79.400 0.000 79.480 1.000 ;
    END
  END m_o[195]
  PIN m_o[196]
    DIRECTION OUTPUT ;
    USE SIGNAL ;
    PORT
      LAYER Metal4 ;
        RECT 79.800 0.000 79.880 1.000 ;
    END
  END m_o[196]
  PIN m_o[197]
    DIRECTION OUTPUT ;
    USE SIGNAL ;
    PORT
      LAYER Metal4 ;
        RECT 80.200 0.000 80.280 1.000 ;
    END
  END m_o[197]
  PIN m_o[198]
    DIRECTION OUTPUT ;
    USE SIGNAL ;
    PORT
      LAYER Metal4 ;
        RECT 80.600 0.000 80.680 1.000 ;
    END
  END m_o[198]
  PIN m_o[199]
    DIRECTION OUTPUT ;
    USE SIGNAL ;
    PORT
      LAYER Metal4 ;
        RECT 81.000 0.000 81.080 1.000 ;
    END
  END m_o[199]
  PIN m_o[200]
    DIRECTION OUTPUT ;
    USE SIGNAL ;
    PORT
      LAYER Metal4 ;
        RECT 81.400 0.000 81.480 1.000 ;
    END
  END m_o[200]
  PIN m_o[201]
    DIRECTION OUTPUT ;
    USE SIGNAL ;
    PORT
      LAYER Metal4 ;
        RECT 81.800 0.000 81.880 1.000 ;
    END
  END m_o[201]
  PIN m_o[202]
    DIRECTION OUTPUT ;
    USE SIGNAL ;
    PORT
      LAYER Metal4 ;
        RECT 82.200 0.000 82.280 1.000 ;
    END
  END m_o[202]
  PIN m_o[203]
    DIRECTION OUTPUT ;
    USE SIGNAL ;
    PORT
      LAYER Metal4 ;
        RECT 82.600 0.000 82.680 1.000 ;
    END
  END m_o[203]
  PIN m_o[204]
    DIRECTION OUTPUT ;
    USE SIGNAL ;
    PORT
      LAYER Metal4 ;
        RECT 83.000 0.000 83.080 1.000 ;
    END
  END m_o[204]
  PIN m_o[205]
    DIRECTION OUTPUT ;
    USE SIGNAL ;
    PORT
      LAYER Metal4 ;
        RECT 83.400 0.000 83.480 1.000 ;
    END
  END m_o[205]
  PIN m_o[206]
    DIRECTION OUTPUT ;
    USE SIGNAL ;
    PORT
      LAYER Metal4 ;
        RECT 83.800 0.000 83.880 1.000 ;
    END
  END m_o[206]
  PIN m_o[207]
    DIRECTION OUTPUT ;
    USE SIGNAL ;
    PORT
      LAYER Metal4 ;
        RECT 84.200 0.000 84.280 1.000 ;
    END
  END m_o[207]
  PIN m_o[208]
    DIRECTION OUTPUT ;
    USE SIGNAL ;
    PORT
      LAYER Metal4 ;
        RECT 84.600 0.000 84.680 1.000 ;
    END
  END m_o[208]
  PIN m_o[209]
    DIRECTION OUTPUT ;
    USE SIGNAL ;
    PORT
      LAYER Metal4 ;
        RECT 85.000 0.000 85.080 1.000 ;
    END
  END m_o[209]
  PIN m_o[210]
    DIRECTION OUTPUT ;
    USE SIGNAL ;
    PORT
      LAYER Metal4 ;
        RECT 85.400 0.000 85.480 1.000 ;
    END
  END m_o[210]
  PIN m_o[211]
    DIRECTION OUTPUT ;
    USE SIGNAL ;
    PORT
      LAYER Metal4 ;
        RECT 85.800 0.000 85.880 1.000 ;
    END
  END m_o[211]
  PIN m_o[212]
    DIRECTION OUTPUT ;
    USE SIGNAL ;
    PORT
      LAYER Metal4 ;
        RECT 86.200 0.000 86.280 1.000 ;
    END
  END m_o[212]
  PIN m_o[213]
    DIRECTION OUTPUT ;
    USE SIGNAL ;
    PORT
      LAYER Metal4 ;
        RECT 86.600 0.000 86.680 1.000 ;
    END
  END m_o[213]
  PIN m_o[214]
    DIRECTION OUTPUT ;
    USE SIGNAL ;
    PORT
      LAYER Metal4 ;
        RECT 87.000 0.000 87.080 1.000 ;
    END
  END m_o[214]
  PIN m_o[215]
    DIRECTION OUTPUT ;
    USE SIGNAL ;
    PORT
      LAYER Metal4 ;
        RECT 87.400 0.000 87.480 1.000 ;
    END
  END m_o[215]
  PIN m_o[216]
    DIRECTION OUTPUT ;
    USE SIGNAL ;
    PORT
      LAYER Metal4 ;
        RECT 87.800 0.000 87.880 1.000 ;
    END
  END m_o[216]
  PIN m_o[217]
    DIRECTION OUTPUT ;
    USE SIGNAL ;
    PORT
      LAYER Metal4 ;
        RECT 88.200 0.000 88.280 1.000 ;
    END
  END m_o[217]
  PIN m_o[218]
    DIRECTION OUTPUT ;
    USE SIGNAL ;
    PORT
      LAYER Metal4 ;
        RECT 88.600 0.000 88.680 1.000 ;
    END
  END m_o[218]
  PIN m_o[219]
    DIRECTION OUTPUT ;
    USE SIGNAL ;
    PORT
      LAYER Metal4 ;
        RECT 89.000 0.000 89.080 1.000 ;
    END
  END m_o[219]
  PIN m_o[220]
    DIRECTION OUTPUT ;
    USE SIGNAL ;
    PORT
      LAYER Metal4 ;
        RECT 89.400 0.000 89.480 1.000 ;
    END
  END m_o[220]
  PIN m_o[221]
    DIRECTION OUTPUT ;
    USE SIGNAL ;
    PORT
      LAYER Metal4 ;
        RECT 89.800 0.000 89.880 1.000 ;
    END
  END m_o[221]
  PIN m_o[222]
    DIRECTION OUTPUT ;
    USE SIGNAL ;
    PORT
      LAYER Metal4 ;
        RECT 90.200 0.000 90.280 1.000 ;
    END
  END m_o[222]
  PIN m_o[223]
    DIRECTION OUTPUT ;
    USE SIGNAL ;
    PORT
      LAYER Metal4 ;
        RECT 90.600 0.000 90.680 1.000 ;
    END
  END m_o[223]
  PIN m_o[224]
    DIRECTION OUTPUT ;
    USE SIGNAL ;
    PORT
      LAYER Metal4 ;
        RECT 91.000 0.000 91.080 1.000 ;
    END
  END m_o[224]
  PIN m_o[225]
    DIRECTION OUTPUT ;
    USE SIGNAL ;
    PORT
      LAYER Metal4 ;
        RECT 91.400 0.000 91.480 1.000 ;
    END
  END m_o[225]
  PIN m_o[226]
    DIRECTION OUTPUT ;
    USE SIGNAL ;
    PORT
      LAYER Metal4 ;
        RECT 91.800 0.000 91.880 1.000 ;
    END
  END m_o[226]
  PIN m_o[227]
    DIRECTION OUTPUT ;
    USE SIGNAL ;
    PORT
      LAYER Metal4 ;
        RECT 92.200 0.000 92.280 1.000 ;
    END
  END m_o[227]
  PIN m_o[228]
    DIRECTION OUTPUT ;
    USE SIGNAL ;
    PORT
      LAYER Metal4 ;
        RECT 92.600 0.000 92.680 1.000 ;
    END
  END m_o[228]
  PIN m_o[229]
    DIRECTION OUTPUT ;
    USE SIGNAL ;
    PORT
      LAYER Metal4 ;
        RECT 93.000 0.000 93.080 1.000 ;
    END
  END m_o[229]
  PIN m_o[230]
    DIRECTION OUTPUT ;
    USE SIGNAL ;
    PORT
      LAYER Metal4 ;
        RECT 93.400 0.000 93.480 1.000 ;
    END
  END m_o[230]
  PIN m_o[231]
    DIRECTION OUTPUT ;
    USE SIGNAL ;
    PORT
      LAYER Metal4 ;
        RECT 93.800 0.000 93.880 1.000 ;
    END
  END m_o[231]
  PIN m_o[232]
    DIRECTION OUTPUT ;
    USE SIGNAL ;
    PORT
      LAYER Metal4 ;
        RECT 94.200 0.000 94.280 1.000 ;
    END
  END m_o[232]
  PIN m_o[233]
    DIRECTION OUTPUT ;
    USE SIGNAL ;
    PORT
      LAYER Metal4 ;
        RECT 94.600 0.000 94.680 1.000 ;
    END
  END m_o[233]
  PIN m_o[234]
    DIRECTION OUTPUT ;
    USE SIGNAL ;
    PORT
      LAYER Metal4 ;
        RECT 95.000 0.000 95.080 1.000 ;
    END
  END m_o[234]
  PIN m_o[235]
    DIRECTION OUTPUT ;
    USE SIGNAL ;
    PORT
      LAYER Metal4 ;
        RECT 95.400 0.000 95.480 1.000 ;
    END
  END m_o[235]
  PIN m_o[236]
    DIRECTION OUTPUT ;
    USE SIGNAL ;
    PORT
      LAYER Metal4 ;
        RECT 95.800 0.000 95.880 1.000 ;
    END
  END m_o[236]
  PIN m_o[237]
    DIRECTION OUTPUT ;
    USE SIGNAL ;
    PORT
      LAYER Metal4 ;
        RECT 96.200 0.000 96.280 1.000 ;
    END
  END m_o[237]
  PIN m_o[238]
    DIRECTION OUTPUT ;
    USE SIGNAL ;
    PORT
      LAYER Metal4 ;
        RECT 96.600 0.000 96.680 1.000 ;
    END
  END m_o[238]
  PIN m_o[239]
    DIRECTION OUTPUT ;
    USE SIGNAL ;
    PORT
      LAYER Metal4 ;
        RECT 97.000 0.000 97.080 1.000 ;
    END
  END m_o[239]
  PIN m_o[240]
    DIRECTION OUTPUT ;
    USE SIGNAL ;
    PORT
      LAYER Metal4 ;
        RECT 97.400 0.000 97.480 1.000 ;
    END
  END m_o[240]
  PIN m_o[241]
    DIRECTION OUTPUT ;
    USE SIGNAL ;
    PORT
      LAYER Metal4 ;
        RECT 97.800 0.000 97.880 1.000 ;
    END
  END m_o[241]
  PIN m_o[242]
    DIRECTION OUTPUT ;
    USE SIGNAL ;
    PORT
      LAYER Metal4 ;
        RECT 98.200 0.000 98.280 1.000 ;
    END
  END m_o[242]
  PIN m_o[243]
    DIRECTION OUTPUT ;
    USE SIGNAL ;
    PORT
      LAYER Metal4 ;
        RECT 98.600 0.000 98.680 1.000 ;
    END
  END m_o[243]
  PIN m_o[244]
    DIRECTION OUTPUT ;
    USE SIGNAL ;
    PORT
      LAYER Metal4 ;
        RECT 99.000 0.000 99.080 1.000 ;
    END
  END m_o[244]
  PIN m_o[245]
    DIRECTION OUTPUT ;
    USE SIGNAL ;
    PORT
      LAYER Metal4 ;
        RECT 99.400 0.000 99.480 1.000 ;
    END
  END m_o[245]
  PIN m_o[246]
    DIRECTION OUTPUT ;
    USE SIGNAL ;
    PORT
      LAYER Metal4 ;
        RECT 99.800 0.000 99.880 1.000 ;
    END
  END m_o[246]
  PIN m_o[247]
    DIRECTION OUTPUT ;
    USE SIGNAL ;
    PORT
      LAYER Metal4 ;
        RECT 100.200 0.000 100.280 1.000 ;
    END
  END m_o[247]
  PIN m_o[248]
    DIRECTION OUTPUT ;
    USE SIGNAL ;
    PORT
      LAYER Metal4 ;
        RECT 100.600 0.000 100.680 1.000 ;
    END
  END m_o[248]
  PIN m_o[249]
    DIRECTION OUTPUT ;
    USE SIGNAL ;
    PORT
      LAYER Metal4 ;
        RECT 101.000 0.000 101.080 1.000 ;
    END
  END m_o[249]
  PIN m_o[250]
    DIRECTION OUTPUT ;
    USE SIGNAL ;
    PORT
      LAYER Metal4 ;
        RECT 101.400 0.000 101.480 1.000 ;
    END
  END m_o[250]
  PIN m_o[251]
    DIRECTION OUTPUT ;
    USE SIGNAL ;
    PORT
      LAYER Metal4 ;
        RECT 101.800 0.000 101.880 1.000 ;
    END
  END m_o[251]
  PIN m_o[252]
    DIRECTION OUTPUT ;
    USE SIGNAL ;
    PORT
      LAYER Metal4 ;
        RECT 102.200 0.000 102.280 1.000 ;
    END
  END m_o[252]
  PIN m_o[253]
    DIRECTION OUTPUT ;
    USE SIGNAL ;
    PORT
      LAYER Metal4 ;
        RECT 102.600 0.000 102.680 1.000 ;
    END
  END m_o[253]
  PIN m_o[254]
    DIRECTION OUTPUT ;
    USE SIGNAL ;
    PORT
      LAYER Metal4 ;
        RECT 103.000 0.000 103.080 1.000 ;
    END
  END m_o[254]
  PIN m_o[255]
    DIRECTION OUTPUT ;
    USE SIGNAL ;
    PORT
      LAYER Metal4 ;
        RECT 103.400 0.000 103.480 1.000 ;
    END
  END m_o[255]
  PIN m_o[256]
    DIRECTION OUTPUT ;
    USE SIGNAL ;
    PORT
      LAYER Metal4 ;
        RECT 103.800 0.000 103.880 1.000 ;
    END
  END m_o[256]
  PIN m_o[257]
    DIRECTION OUTPUT ;
    USE SIGNAL ;
    PORT
      LAYER Metal4 ;
        RECT 104.200 0.000 104.280 1.000 ;
    END
  END m_o[257]
  PIN m_o[258]
    DIRECTION OUTPUT ;
    USE SIGNAL ;
    PORT
      LAYER Metal4 ;
        RECT 104.600 0.000 104.680 1.000 ;
    END
  END m_o[258]
  PIN m_o[259]
    DIRECTION OUTPUT ;
    USE SIGNAL ;
    PORT
      LAYER Metal4 ;
        RECT 105.000 0.000 105.080 1.000 ;
    END
  END m_o[259]
  PIN m_o[260]
    DIRECTION OUTPUT ;
    USE SIGNAL ;
    PORT
      LAYER Metal4 ;
        RECT 105.400 0.000 105.480 1.000 ;
    END
  END m_o[260]
  PIN m_o[261]
    DIRECTION OUTPUT ;
    USE SIGNAL ;
    PORT
      LAYER Metal4 ;
        RECT 105.800 0.000 105.880 1.000 ;
    END
  END m_o[261]
  PIN m_o[262]
    DIRECTION OUTPUT ;
    USE SIGNAL ;
    PORT
      LAYER Metal4 ;
        RECT 106.200 0.000 106.280 1.000 ;
    END
  END m_o[262]
  PIN m_o[263]
    DIRECTION OUTPUT ;
    USE SIGNAL ;
    PORT
      LAYER Metal4 ;
        RECT 106.600 0.000 106.680 1.000 ;
    END
  END m_o[263]
  PIN m_o[264]
    DIRECTION OUTPUT ;
    USE SIGNAL ;
    PORT
      LAYER Metal4 ;
        RECT 107.000 0.000 107.080 1.000 ;
    END
  END m_o[264]
  PIN m_o[265]
    DIRECTION OUTPUT ;
    USE SIGNAL ;
    PORT
      LAYER Metal4 ;
        RECT 107.400 0.000 107.480 1.000 ;
    END
  END m_o[265]
  PIN m_o[266]
    DIRECTION OUTPUT ;
    USE SIGNAL ;
    PORT
      LAYER Metal4 ;
        RECT 107.800 0.000 107.880 1.000 ;
    END
  END m_o[266]
  PIN m_o[267]
    DIRECTION OUTPUT ;
    USE SIGNAL ;
    PORT
      LAYER Metal4 ;
        RECT 108.200 0.000 108.280 1.000 ;
    END
  END m_o[267]
  PIN m_o[268]
    DIRECTION OUTPUT ;
    USE SIGNAL ;
    PORT
      LAYER Metal4 ;
        RECT 108.600 0.000 108.680 1.000 ;
    END
  END m_o[268]
  PIN m_o[269]
    DIRECTION OUTPUT ;
    USE SIGNAL ;
    PORT
      LAYER Metal4 ;
        RECT 109.000 0.000 109.080 1.000 ;
    END
  END m_o[269]
  PIN m_o[270]
    DIRECTION OUTPUT ;
    USE SIGNAL ;
    PORT
      LAYER Metal4 ;
        RECT 109.400 0.000 109.480 1.000 ;
    END
  END m_o[270]
  PIN m_o[271]
    DIRECTION OUTPUT ;
    USE SIGNAL ;
    PORT
      LAYER Metal4 ;
        RECT 109.800 0.000 109.880 1.000 ;
    END
  END m_o[271]
  PIN m_o[272]
    DIRECTION OUTPUT ;
    USE SIGNAL ;
    PORT
      LAYER Metal4 ;
        RECT 110.200 0.000 110.280 1.000 ;
    END
  END m_o[272]
  PIN m_o[273]
    DIRECTION OUTPUT ;
    USE SIGNAL ;
    PORT
      LAYER Metal4 ;
        RECT 110.600 0.000 110.680 1.000 ;
    END
  END m_o[273]
  PIN m_o[274]
    DIRECTION OUTPUT ;
    USE SIGNAL ;
    PORT
      LAYER Metal4 ;
        RECT 111.000 0.000 111.080 1.000 ;
    END
  END m_o[274]
  PIN m_o[275]
    DIRECTION OUTPUT ;
    USE SIGNAL ;
    PORT
      LAYER Metal4 ;
        RECT 111.400 0.000 111.480 1.000 ;
    END
  END m_o[275]
  PIN m_o[276]
    DIRECTION OUTPUT ;
    USE SIGNAL ;
    PORT
      LAYER Metal4 ;
        RECT 111.800 0.000 111.880 1.000 ;
    END
  END m_o[276]
  PIN m_o[277]
    DIRECTION OUTPUT ;
    USE SIGNAL ;
    PORT
      LAYER Metal4 ;
        RECT 112.200 0.000 112.280 1.000 ;
    END
  END m_o[277]
  PIN m_o[278]
    DIRECTION OUTPUT ;
    USE SIGNAL ;
    PORT
      LAYER Metal4 ;
        RECT 112.600 0.000 112.680 1.000 ;
    END
  END m_o[278]
  PIN m_o[279]
    DIRECTION OUTPUT ;
    USE SIGNAL ;
    PORT
      LAYER Metal4 ;
        RECT 113.000 0.000 113.080 1.000 ;
    END
  END m_o[279]
  PIN m_o[280]
    DIRECTION OUTPUT ;
    USE SIGNAL ;
    PORT
      LAYER Metal4 ;
        RECT 113.400 0.000 113.480 1.000 ;
    END
  END m_o[280]
  PIN m_o[281]
    DIRECTION OUTPUT ;
    USE SIGNAL ;
    PORT
      LAYER Metal4 ;
        RECT 113.800 0.000 113.880 1.000 ;
    END
  END m_o[281]
  PIN m_o[282]
    DIRECTION OUTPUT ;
    USE SIGNAL ;
    PORT
      LAYER Metal4 ;
        RECT 114.200 0.000 114.280 1.000 ;
    END
  END m_o[282]
  PIN m_o[283]
    DIRECTION OUTPUT ;
    USE SIGNAL ;
    PORT
      LAYER Metal4 ;
        RECT 114.600 0.000 114.680 1.000 ;
    END
  END m_o[283]
  PIN m_o[284]
    DIRECTION OUTPUT ;
    USE SIGNAL ;
    PORT
      LAYER Metal4 ;
        RECT 115.000 0.000 115.080 1.000 ;
    END
  END m_o[284]
  PIN m_o[285]
    DIRECTION OUTPUT ;
    USE SIGNAL ;
    PORT
      LAYER Metal4 ;
        RECT 115.400 0.000 115.480 1.000 ;
    END
  END m_o[285]
  PIN m_o[286]
    DIRECTION OUTPUT ;
    USE SIGNAL ;
    PORT
      LAYER Metal4 ;
        RECT 115.800 0.000 115.880 1.000 ;
    END
  END m_o[286]
  PIN m_o[287]
    DIRECTION OUTPUT ;
    USE SIGNAL ;
    PORT
      LAYER Metal4 ;
        RECT 116.200 0.000 116.280 1.000 ;
    END
  END m_o[287]
  PIN m_o[288]
    DIRECTION OUTPUT ;
    USE SIGNAL ;
    PORT
      LAYER Metal4 ;
        RECT 116.600 0.000 116.680 1.000 ;
    END
  END m_o[288]
  PIN m_o[289]
    DIRECTION OUTPUT ;
    USE SIGNAL ;
    PORT
      LAYER Metal4 ;
        RECT 117.000 0.000 117.080 1.000 ;
    END
  END m_o[289]
  PIN m_o[290]
    DIRECTION OUTPUT ;
    USE SIGNAL ;
    PORT
      LAYER Metal4 ;
        RECT 117.400 0.000 117.480 1.000 ;
    END
  END m_o[290]
  PIN m_o[291]
    DIRECTION OUTPUT ;
    USE SIGNAL ;
    PORT
      LAYER Metal4 ;
        RECT 117.800 0.000 117.880 1.000 ;
    END
  END m_o[291]
  PIN m_o[292]
    DIRECTION OUTPUT ;
    USE SIGNAL ;
    PORT
      LAYER Metal4 ;
        RECT 118.200 0.000 118.280 1.000 ;
    END
  END m_o[292]
  PIN m_o[293]
    DIRECTION OUTPUT ;
    USE SIGNAL ;
    PORT
      LAYER Metal4 ;
        RECT 118.600 0.000 118.680 1.000 ;
    END
  END m_o[293]
  PIN m_o[294]
    DIRECTION OUTPUT ;
    USE SIGNAL ;
    PORT
      LAYER Metal4 ;
        RECT 119.000 0.000 119.080 1.000 ;
    END
  END m_o[294]
  PIN m_o[295]
    DIRECTION OUTPUT ;
    USE SIGNAL ;
    PORT
      LAYER Metal4 ;
        RECT 119.400 0.000 119.480 1.000 ;
    END
  END m_o[295]
  PIN m_o[296]
    DIRECTION OUTPUT ;
    USE SIGNAL ;
    PORT
      LAYER Metal4 ;
        RECT 119.800 0.000 119.880 1.000 ;
    END
  END m_o[296]
  PIN m_o[297]
    DIRECTION OUTPUT ;
    USE SIGNAL ;
    PORT
      LAYER Metal4 ;
        RECT 120.200 0.000 120.280 1.000 ;
    END
  END m_o[297]
  PIN m_o[298]
    DIRECTION OUTPUT ;
    USE SIGNAL ;
    PORT
      LAYER Metal4 ;
        RECT 120.600 0.000 120.680 1.000 ;
    END
  END m_o[298]
  PIN m_o[299]
    DIRECTION OUTPUT ;
    USE SIGNAL ;
    PORT
      LAYER Metal4 ;
        RECT 121.000 0.000 121.080 1.000 ;
    END
  END m_o[299]
  PIN m_o[300]
    DIRECTION OUTPUT ;
    USE SIGNAL ;
    PORT
      LAYER Metal4 ;
        RECT 121.400 0.000 121.480 1.000 ;
    END
  END m_o[300]
  PIN m_o[301]
    DIRECTION OUTPUT ;
    USE SIGNAL ;
    PORT
      LAYER Metal4 ;
        RECT 121.800 0.000 121.880 1.000 ;
    END
  END m_o[301]
  PIN m_o[302]
    DIRECTION OUTPUT ;
    USE SIGNAL ;
    PORT
      LAYER Metal4 ;
        RECT 122.200 0.000 122.280 1.000 ;
    END
  END m_o[302]
  PIN m_o[303]
    DIRECTION OUTPUT ;
    USE SIGNAL ;
    PORT
      LAYER Metal4 ;
        RECT 122.600 0.000 122.680 1.000 ;
    END
  END m_o[303]
  PIN m_o[304]
    DIRECTION OUTPUT ;
    USE SIGNAL ;
    PORT
      LAYER Metal4 ;
        RECT 123.000 0.000 123.080 1.000 ;
    END
  END m_o[304]
  PIN m_o[305]
    DIRECTION OUTPUT ;
    USE SIGNAL ;
    PORT
      LAYER Metal4 ;
        RECT 123.400 0.000 123.480 1.000 ;
    END
  END m_o[305]
  PIN m_o[306]
    DIRECTION OUTPUT ;
    USE SIGNAL ;
    PORT
      LAYER Metal4 ;
        RECT 123.800 0.000 123.880 1.000 ;
    END
  END m_o[306]
  PIN m_o[307]
    DIRECTION OUTPUT ;
    USE SIGNAL ;
    PORT
      LAYER Metal4 ;
        RECT 124.200 0.000 124.280 1.000 ;
    END
  END m_o[307]
  PIN m_o[308]
    DIRECTION OUTPUT ;
    USE SIGNAL ;
    PORT
      LAYER Metal4 ;
        RECT 124.600 0.000 124.680 1.000 ;
    END
  END m_o[308]
  PIN m_o[309]
    DIRECTION OUTPUT ;
    USE SIGNAL ;
    PORT
      LAYER Metal4 ;
        RECT 125.000 0.000 125.080 1.000 ;
    END
  END m_o[309]
  PIN m_o[310]
    DIRECTION OUTPUT ;
    USE SIGNAL ;
    PORT
      LAYER Metal4 ;
        RECT 125.400 0.000 125.480 1.000 ;
    END
  END m_o[310]
  PIN m_o[311]
    DIRECTION OUTPUT ;
    USE SIGNAL ;
    PORT
      LAYER Metal4 ;
        RECT 125.800 0.000 125.880 1.000 ;
    END
  END m_o[311]
  PIN m_o[312]
    DIRECTION OUTPUT ;
    USE SIGNAL ;
    PORT
      LAYER Metal4 ;
        RECT 126.200 0.000 126.280 1.000 ;
    END
  END m_o[312]
  PIN m_o[313]
    DIRECTION OUTPUT ;
    USE SIGNAL ;
    PORT
      LAYER Metal4 ;
        RECT 126.600 0.000 126.680 1.000 ;
    END
  END m_o[313]
  PIN m_o[314]
    DIRECTION OUTPUT ;
    USE SIGNAL ;
    PORT
      LAYER Metal4 ;
        RECT 127.000 0.000 127.080 1.000 ;
    END
  END m_o[314]
  PIN m_o[315]
    DIRECTION OUTPUT ;
    USE SIGNAL ;
    PORT
      LAYER Metal4 ;
        RECT 127.400 0.000 127.480 1.000 ;
    END
  END m_o[315]
  PIN m_o[316]
    DIRECTION OUTPUT ;
    USE SIGNAL ;
    PORT
      LAYER Metal4 ;
        RECT 127.800 0.000 127.880 1.000 ;
    END
  END m_o[316]
  PIN m_o[317]
    DIRECTION OUTPUT ;
    USE SIGNAL ;
    PORT
      LAYER Metal4 ;
        RECT 128.200 0.000 128.280 1.000 ;
    END
  END m_o[317]
  PIN m_o[318]
    DIRECTION OUTPUT ;
    USE SIGNAL ;
    PORT
      LAYER Metal4 ;
        RECT 128.600 0.000 128.680 1.000 ;
    END
  END m_o[318]
  PIN m_o[319]
    DIRECTION OUTPUT ;
    USE SIGNAL ;
    PORT
      LAYER Metal4 ;
        RECT 129.000 0.000 129.080 1.000 ;
    END
  END m_o[319]
  PIN m_o[320]
    DIRECTION OUTPUT ;
    USE SIGNAL ;
    PORT
      LAYER Metal4 ;
        RECT 129.400 0.000 129.480 1.000 ;
    END
  END m_o[320]
  PIN m_o[321]
    DIRECTION OUTPUT ;
    USE SIGNAL ;
    PORT
      LAYER Metal4 ;
        RECT 129.800 0.000 129.880 1.000 ;
    END
  END m_o[321]
  PIN m_o[322]
    DIRECTION OUTPUT ;
    USE SIGNAL ;
    PORT
      LAYER Metal4 ;
        RECT 130.200 0.000 130.280 1.000 ;
    END
  END m_o[322]
  PIN m_o[323]
    DIRECTION OUTPUT ;
    USE SIGNAL ;
    PORT
      LAYER Metal4 ;
        RECT 130.600 0.000 130.680 1.000 ;
    END
  END m_o[323]
  PIN m_o[324]
    DIRECTION OUTPUT ;
    USE SIGNAL ;
    PORT
      LAYER Metal4 ;
        RECT 131.000 0.000 131.080 1.000 ;
    END
  END m_o[324]
  PIN m_o[325]
    DIRECTION OUTPUT ;
    USE SIGNAL ;
    PORT
      LAYER Metal4 ;
        RECT 131.400 0.000 131.480 1.000 ;
    END
  END m_o[325]
  PIN m_o[326]
    DIRECTION OUTPUT ;
    USE SIGNAL ;
    PORT
      LAYER Metal4 ;
        RECT 131.800 0.000 131.880 1.000 ;
    END
  END m_o[326]
  PIN m_o[327]
    DIRECTION OUTPUT ;
    USE SIGNAL ;
    PORT
      LAYER Metal4 ;
        RECT 132.200 0.000 132.280 1.000 ;
    END
  END m_o[327]
  PIN m_o[328]
    DIRECTION OUTPUT ;
    USE SIGNAL ;
    PORT
      LAYER Metal4 ;
        RECT 132.600 0.000 132.680 1.000 ;
    END
  END m_o[328]
  PIN m_o[329]
    DIRECTION OUTPUT ;
    USE SIGNAL ;
    PORT
      LAYER Metal4 ;
        RECT 133.000 0.000 133.080 1.000 ;
    END
  END m_o[329]
  PIN m_o[330]
    DIRECTION OUTPUT ;
    USE SIGNAL ;
    PORT
      LAYER Metal4 ;
        RECT 133.400 0.000 133.480 1.000 ;
    END
  END m_o[330]
  PIN m_o[331]
    DIRECTION OUTPUT ;
    USE SIGNAL ;
    PORT
      LAYER Metal4 ;
        RECT 133.800 0.000 133.880 1.000 ;
    END
  END m_o[331]
  PIN m_o[332]
    DIRECTION OUTPUT ;
    USE SIGNAL ;
    PORT
      LAYER Metal4 ;
        RECT 134.200 0.000 134.280 1.000 ;
    END
  END m_o[332]
  PIN m_o[333]
    DIRECTION OUTPUT ;
    USE SIGNAL ;
    PORT
      LAYER Metal4 ;
        RECT 134.600 0.000 134.680 1.000 ;
    END
  END m_o[333]
  PIN m_o[334]
    DIRECTION OUTPUT ;
    USE SIGNAL ;
    PORT
      LAYER Metal4 ;
        RECT 135.000 0.000 135.080 1.000 ;
    END
  END m_o[334]
  PIN m_o[335]
    DIRECTION OUTPUT ;
    USE SIGNAL ;
    PORT
      LAYER Metal4 ;
        RECT 135.400 0.000 135.480 1.000 ;
    END
  END m_o[335]
  PIN m_o[336]
    DIRECTION OUTPUT ;
    USE SIGNAL ;
    PORT
      LAYER Metal4 ;
        RECT 135.800 0.000 135.880 1.000 ;
    END
  END m_o[336]
  PIN m_o[337]
    DIRECTION OUTPUT ;
    USE SIGNAL ;
    PORT
      LAYER Metal4 ;
        RECT 136.200 0.000 136.280 1.000 ;
    END
  END m_o[337]
  PIN m_o[338]
    DIRECTION OUTPUT ;
    USE SIGNAL ;
    PORT
      LAYER Metal4 ;
        RECT 136.600 0.000 136.680 1.000 ;
    END
  END m_o[338]
  PIN m_o[339]
    DIRECTION OUTPUT ;
    USE SIGNAL ;
    PORT
      LAYER Metal4 ;
        RECT 137.000 0.000 137.080 1.000 ;
    END
  END m_o[339]
  PIN m_o[340]
    DIRECTION OUTPUT ;
    USE SIGNAL ;
    PORT
      LAYER Metal4 ;
        RECT 137.400 0.000 137.480 1.000 ;
    END
  END m_o[340]
  PIN m_o[341]
    DIRECTION OUTPUT ;
    USE SIGNAL ;
    PORT
      LAYER Metal4 ;
        RECT 137.800 0.000 137.880 1.000 ;
    END
  END m_o[341]
  PIN m_o[342]
    DIRECTION OUTPUT ;
    USE SIGNAL ;
    PORT
      LAYER Metal4 ;
        RECT 138.200 0.000 138.280 1.000 ;
    END
  END m_o[342]
  PIN m_o[343]
    DIRECTION OUTPUT ;
    USE SIGNAL ;
    PORT
      LAYER Metal4 ;
        RECT 138.600 0.000 138.680 1.000 ;
    END
  END m_o[343]
  PIN m_o[344]
    DIRECTION OUTPUT ;
    USE SIGNAL ;
    PORT
      LAYER Metal4 ;
        RECT 139.000 0.000 139.080 1.000 ;
    END
  END m_o[344]
  PIN m_o[345]
    DIRECTION OUTPUT ;
    USE SIGNAL ;
    PORT
      LAYER Metal4 ;
        RECT 139.400 0.000 139.480 1.000 ;
    END
  END m_o[345]
  PIN m_o[346]
    DIRECTION OUTPUT ;
    USE SIGNAL ;
    PORT
      LAYER Metal4 ;
        RECT 139.800 0.000 139.880 1.000 ;
    END
  END m_o[346]
  PIN m_o[347]
    DIRECTION OUTPUT ;
    USE SIGNAL ;
    PORT
      LAYER Metal4 ;
        RECT 140.200 0.000 140.280 1.000 ;
    END
  END m_o[347]
  PIN m_o[348]
    DIRECTION OUTPUT ;
    USE SIGNAL ;
    PORT
      LAYER Metal4 ;
        RECT 140.600 0.000 140.680 1.000 ;
    END
  END m_o[348]
  PIN m_o[349]
    DIRECTION OUTPUT ;
    USE SIGNAL ;
    PORT
      LAYER Metal4 ;
        RECT 141.000 0.000 141.080 1.000 ;
    END
  END m_o[349]
  PIN m_o[350]
    DIRECTION OUTPUT ;
    USE SIGNAL ;
    PORT
      LAYER Metal4 ;
        RECT 141.400 0.000 141.480 1.000 ;
    END
  END m_o[350]
  PIN m_o[351]
    DIRECTION OUTPUT ;
    USE SIGNAL ;
    PORT
      LAYER Metal4 ;
        RECT 141.800 0.000 141.880 1.000 ;
    END
  END m_o[351]
  PIN m_o[352]
    DIRECTION OUTPUT ;
    USE SIGNAL ;
    PORT
      LAYER Metal4 ;
        RECT 142.200 0.000 142.280 1.000 ;
    END
  END m_o[352]
  PIN m_o[353]
    DIRECTION OUTPUT ;
    USE SIGNAL ;
    PORT
      LAYER Metal4 ;
        RECT 142.600 0.000 142.680 1.000 ;
    END
  END m_o[353]
  PIN m_o[354]
    DIRECTION OUTPUT ;
    USE SIGNAL ;
    PORT
      LAYER Metal4 ;
        RECT 143.000 0.000 143.080 1.000 ;
    END
  END m_o[354]
  PIN m_o[355]
    DIRECTION OUTPUT ;
    USE SIGNAL ;
    PORT
      LAYER Metal4 ;
        RECT 143.400 0.000 143.480 1.000 ;
    END
  END m_o[355]
  PIN m_o[356]
    DIRECTION OUTPUT ;
    USE SIGNAL ;
    PORT
      LAYER Metal4 ;
        RECT 143.800 0.000 143.880 1.000 ;
    END
  END m_o[356]
  PIN m_o[357]
    DIRECTION OUTPUT ;
    USE SIGNAL ;
    PORT
      LAYER Metal4 ;
        RECT 144.200 0.000 144.280 1.000 ;
    END
  END m_o[357]
  PIN m_o[358]
    DIRECTION OUTPUT ;
    USE SIGNAL ;
    PORT
      LAYER Metal4 ;
        RECT 144.600 0.000 144.680 1.000 ;
    END
  END m_o[358]
  PIN m_o[359]
    DIRECTION OUTPUT ;
    USE SIGNAL ;
    PORT
      LAYER Metal4 ;
        RECT 145.000 0.000 145.080 1.000 ;
    END
  END m_o[359]
  PIN m_o[360]
    DIRECTION OUTPUT ;
    USE SIGNAL ;
    PORT
      LAYER Metal4 ;
        RECT 145.400 0.000 145.480 1.000 ;
    END
  END m_o[360]
  PIN m_o[361]
    DIRECTION OUTPUT ;
    USE SIGNAL ;
    PORT
      LAYER Metal4 ;
        RECT 145.800 0.000 145.880 1.000 ;
    END
  END m_o[361]
  PIN m_o[362]
    DIRECTION OUTPUT ;
    USE SIGNAL ;
    PORT
      LAYER Metal4 ;
        RECT 146.200 0.000 146.280 1.000 ;
    END
  END m_o[362]
  PIN m_o[363]
    DIRECTION OUTPUT ;
    USE SIGNAL ;
    PORT
      LAYER Metal4 ;
        RECT 146.600 0.000 146.680 1.000 ;
    END
  END m_o[363]
  PIN m_o[364]
    DIRECTION OUTPUT ;
    USE SIGNAL ;
    PORT
      LAYER Metal4 ;
        RECT 147.000 0.000 147.080 1.000 ;
    END
  END m_o[364]
  PIN m_o[365]
    DIRECTION OUTPUT ;
    USE SIGNAL ;
    PORT
      LAYER Metal4 ;
        RECT 147.400 0.000 147.480 1.000 ;
    END
  END m_o[365]
  PIN m_o[366]
    DIRECTION OUTPUT ;
    USE SIGNAL ;
    PORT
      LAYER Metal4 ;
        RECT 147.800 0.000 147.880 1.000 ;
    END
  END m_o[366]
  PIN m_o[367]
    DIRECTION OUTPUT ;
    USE SIGNAL ;
    PORT
      LAYER Metal4 ;
        RECT 148.200 0.000 148.280 1.000 ;
    END
  END m_o[367]
  PIN m_o[368]
    DIRECTION OUTPUT ;
    USE SIGNAL ;
    PORT
      LAYER Metal4 ;
        RECT 148.600 0.000 148.680 1.000 ;
    END
  END m_o[368]
  PIN m_o[369]
    DIRECTION OUTPUT ;
    USE SIGNAL ;
    PORT
      LAYER Metal4 ;
        RECT 149.000 0.000 149.080 1.000 ;
    END
  END m_o[369]
  PIN m_o[370]
    DIRECTION OUTPUT ;
    USE SIGNAL ;
    PORT
      LAYER Metal4 ;
        RECT 149.400 0.000 149.480 1.000 ;
    END
  END m_o[370]
  PIN m_o[371]
    DIRECTION OUTPUT ;
    USE SIGNAL ;
    PORT
      LAYER Metal4 ;
        RECT 149.800 0.000 149.880 1.000 ;
    END
  END m_o[371]
  PIN m_o[372]
    DIRECTION OUTPUT ;
    USE SIGNAL ;
    PORT
      LAYER Metal4 ;
        RECT 150.200 0.000 150.280 1.000 ;
    END
  END m_o[372]
  PIN m_o[373]
    DIRECTION OUTPUT ;
    USE SIGNAL ;
    PORT
      LAYER Metal4 ;
        RECT 150.600 0.000 150.680 1.000 ;
    END
  END m_o[373]
  PIN m_o[374]
    DIRECTION OUTPUT ;
    USE SIGNAL ;
    PORT
      LAYER Metal4 ;
        RECT 151.000 0.000 151.080 1.000 ;
    END
  END m_o[374]
  PIN m_o[375]
    DIRECTION OUTPUT ;
    USE SIGNAL ;
    PORT
      LAYER Metal4 ;
        RECT 151.400 0.000 151.480 1.000 ;
    END
  END m_o[375]
  PIN m_o[376]
    DIRECTION OUTPUT ;
    USE SIGNAL ;
    PORT
      LAYER Metal4 ;
        RECT 151.800 0.000 151.880 1.000 ;
    END
  END m_o[376]
  PIN m_o[377]
    DIRECTION OUTPUT ;
    USE SIGNAL ;
    PORT
      LAYER Metal4 ;
        RECT 152.200 0.000 152.280 1.000 ;
    END
  END m_o[377]
  PIN m_o[378]
    DIRECTION OUTPUT ;
    USE SIGNAL ;
    PORT
      LAYER Metal4 ;
        RECT 152.600 0.000 152.680 1.000 ;
    END
  END m_o[378]
  PIN m_o[379]
    DIRECTION OUTPUT ;
    USE SIGNAL ;
    PORT
      LAYER Metal4 ;
        RECT 153.000 0.000 153.080 1.000 ;
    END
  END m_o[379]
  PIN m_o[380]
    DIRECTION OUTPUT ;
    USE SIGNAL ;
    PORT
      LAYER Metal4 ;
        RECT 153.400 0.000 153.480 1.000 ;
    END
  END m_o[380]
  PIN m_o[381]
    DIRECTION OUTPUT ;
    USE SIGNAL ;
    PORT
      LAYER Metal4 ;
        RECT 153.800 0.000 153.880 1.000 ;
    END
  END m_o[381]
  PIN m_o[382]
    DIRECTION OUTPUT ;
    USE SIGNAL ;
    PORT
      LAYER Metal4 ;
        RECT 154.200 0.000 154.280 1.000 ;
    END
  END m_o[382]
  PIN m_o[383]
    DIRECTION OUTPUT ;
    USE SIGNAL ;
    PORT
      LAYER Metal4 ;
        RECT 154.600 0.000 154.680 1.000 ;
    END
  END m_o[383]
  PIN m_o[384]
    DIRECTION OUTPUT ;
    USE SIGNAL ;
    PORT
      LAYER Metal4 ;
        RECT 155.000 0.000 155.080 1.000 ;
    END
  END m_o[384]
  PIN m_o[385]
    DIRECTION OUTPUT ;
    USE SIGNAL ;
    PORT
      LAYER Metal4 ;
        RECT 155.400 0.000 155.480 1.000 ;
    END
  END m_o[385]
  PIN m_o[386]
    DIRECTION OUTPUT ;
    USE SIGNAL ;
    PORT
      LAYER Metal4 ;
        RECT 155.800 0.000 155.880 1.000 ;
    END
  END m_o[386]
  PIN m_o[387]
    DIRECTION OUTPUT ;
    USE SIGNAL ;
    PORT
      LAYER Metal4 ;
        RECT 156.200 0.000 156.280 1.000 ;
    END
  END m_o[387]
  PIN m_o[388]
    DIRECTION OUTPUT ;
    USE SIGNAL ;
    PORT
      LAYER Metal4 ;
        RECT 156.600 0.000 156.680 1.000 ;
    END
  END m_o[388]
  PIN m_o[389]
    DIRECTION OUTPUT ;
    USE SIGNAL ;
    PORT
      LAYER Metal4 ;
        RECT 157.000 0.000 157.080 1.000 ;
    END
  END m_o[389]
  PIN m_o[390]
    DIRECTION OUTPUT ;
    USE SIGNAL ;
    PORT
      LAYER Metal4 ;
        RECT 157.400 0.000 157.480 1.000 ;
    END
  END m_o[390]
  PIN m_o[391]
    DIRECTION OUTPUT ;
    USE SIGNAL ;
    PORT
      LAYER Metal4 ;
        RECT 157.800 0.000 157.880 1.000 ;
    END
  END m_o[391]
  PIN m_o[392]
    DIRECTION OUTPUT ;
    USE SIGNAL ;
    PORT
      LAYER Metal4 ;
        RECT 158.200 0.000 158.280 1.000 ;
    END
  END m_o[392]
  PIN m_o[393]
    DIRECTION OUTPUT ;
    USE SIGNAL ;
    PORT
      LAYER Metal4 ;
        RECT 158.600 0.000 158.680 1.000 ;
    END
  END m_o[393]
  PIN m_o[394]
    DIRECTION OUTPUT ;
    USE SIGNAL ;
    PORT
      LAYER Metal4 ;
        RECT 159.000 0.000 159.080 1.000 ;
    END
  END m_o[394]
  PIN m_o[395]
    DIRECTION OUTPUT ;
    USE SIGNAL ;
    PORT
      LAYER Metal4 ;
        RECT 159.400 0.000 159.480 1.000 ;
    END
  END m_o[395]
  PIN m_o[396]
    DIRECTION OUTPUT ;
    USE SIGNAL ;
    PORT
      LAYER Metal4 ;
        RECT 159.800 0.000 159.880 1.000 ;
    END
  END m_o[396]
  PIN m_o[397]
    DIRECTION OUTPUT ;
    USE SIGNAL ;
    PORT
      LAYER Metal4 ;
        RECT 160.200 0.000 160.280 1.000 ;
    END
  END m_o[397]
  PIN m_o[398]
    DIRECTION OUTPUT ;
    USE SIGNAL ;
    PORT
      LAYER Metal4 ;
        RECT 160.600 0.000 160.680 1.000 ;
    END
  END m_o[398]
  PIN m_o[399]
    DIRECTION OUTPUT ;
    USE SIGNAL ;
    PORT
      LAYER Metal4 ;
        RECT 161.000 0.000 161.080 1.000 ;
    END
  END m_o[399]
  PIN m_o[400]
    DIRECTION OUTPUT ;
    USE SIGNAL ;
    PORT
      LAYER Metal4 ;
        RECT 161.400 0.000 161.480 1.000 ;
    END
  END m_o[400]
  PIN m_o[401]
    DIRECTION OUTPUT ;
    USE SIGNAL ;
    PORT
      LAYER Metal4 ;
        RECT 161.800 0.000 161.880 1.000 ;
    END
  END m_o[401]
  PIN m_o[402]
    DIRECTION OUTPUT ;
    USE SIGNAL ;
    PORT
      LAYER Metal4 ;
        RECT 162.200 0.000 162.280 1.000 ;
    END
  END m_o[402]
  PIN m_o[403]
    DIRECTION OUTPUT ;
    USE SIGNAL ;
    PORT
      LAYER Metal4 ;
        RECT 162.600 0.000 162.680 1.000 ;
    END
  END m_o[403]
  PIN m_o[404]
    DIRECTION OUTPUT ;
    USE SIGNAL ;
    PORT
      LAYER Metal4 ;
        RECT 163.000 0.000 163.080 1.000 ;
    END
  END m_o[404]
  PIN m_o[405]
    DIRECTION OUTPUT ;
    USE SIGNAL ;
    PORT
      LAYER Metal4 ;
        RECT 163.400 0.000 163.480 1.000 ;
    END
  END m_o[405]
  PIN m_o[406]
    DIRECTION OUTPUT ;
    USE SIGNAL ;
    PORT
      LAYER Metal4 ;
        RECT 163.800 0.000 163.880 1.000 ;
    END
  END m_o[406]
  PIN m_o[407]
    DIRECTION OUTPUT ;
    USE SIGNAL ;
    PORT
      LAYER Metal4 ;
        RECT 164.200 0.000 164.280 1.000 ;
    END
  END m_o[407]
  PIN m_o[408]
    DIRECTION OUTPUT ;
    USE SIGNAL ;
    PORT
      LAYER Metal4 ;
        RECT 164.600 0.000 164.680 1.000 ;
    END
  END m_o[408]
  PIN m_o[409]
    DIRECTION OUTPUT ;
    USE SIGNAL ;
    PORT
      LAYER Metal4 ;
        RECT 165.000 0.000 165.080 1.000 ;
    END
  END m_o[409]
  PIN m_o[410]
    DIRECTION OUTPUT ;
    USE SIGNAL ;
    PORT
      LAYER Metal4 ;
        RECT 165.400 0.000 165.480 1.000 ;
    END
  END m_o[410]
  PIN m_o[411]
    DIRECTION OUTPUT ;
    USE SIGNAL ;
    PORT
      LAYER Metal4 ;
        RECT 165.800 0.000 165.880 1.000 ;
    END
  END m_o[411]
  PIN m_o[412]
    DIRECTION OUTPUT ;
    USE SIGNAL ;
    PORT
      LAYER Metal4 ;
        RECT 166.200 0.000 166.280 1.000 ;
    END
  END m_o[412]
  PIN m_o[413]
    DIRECTION OUTPUT ;
    USE SIGNAL ;
    PORT
      LAYER Metal4 ;
        RECT 166.600 0.000 166.680 1.000 ;
    END
  END m_o[413]
  PIN m_o[414]
    DIRECTION OUTPUT ;
    USE SIGNAL ;
    PORT
      LAYER Metal4 ;
        RECT 167.000 0.000 167.080 1.000 ;
    END
  END m_o[414]
  PIN m_o[415]
    DIRECTION OUTPUT ;
    USE SIGNAL ;
    PORT
      LAYER Metal4 ;
        RECT 167.400 0.000 167.480 1.000 ;
    END
  END m_o[415]
  PIN m_o[416]
    DIRECTION OUTPUT ;
    USE SIGNAL ;
    PORT
      LAYER Metal4 ;
        RECT 167.800 0.000 167.880 1.000 ;
    END
  END m_o[416]
  PIN m_o[417]
    DIRECTION OUTPUT ;
    USE SIGNAL ;
    PORT
      LAYER Metal4 ;
        RECT 168.200 0.000 168.280 1.000 ;
    END
  END m_o[417]
  PIN m_o[418]
    DIRECTION OUTPUT ;
    USE SIGNAL ;
    PORT
      LAYER Metal4 ;
        RECT 168.600 0.000 168.680 1.000 ;
    END
  END m_o[418]
  PIN m_o[419]
    DIRECTION OUTPUT ;
    USE SIGNAL ;
    PORT
      LAYER Metal4 ;
        RECT 169.000 0.000 169.080 1.000 ;
    END
  END m_o[419]
  PIN m_o[420]
    DIRECTION OUTPUT ;
    USE SIGNAL ;
    PORT
      LAYER Metal4 ;
        RECT 169.400 0.000 169.480 1.000 ;
    END
  END m_o[420]
  PIN m_o[421]
    DIRECTION OUTPUT ;
    USE SIGNAL ;
    PORT
      LAYER Metal4 ;
        RECT 169.800 0.000 169.880 1.000 ;
    END
  END m_o[421]
  PIN m_o[422]
    DIRECTION OUTPUT ;
    USE SIGNAL ;
    PORT
      LAYER Metal4 ;
        RECT 170.200 0.000 170.280 1.000 ;
    END
  END m_o[422]
  PIN m_o[423]
    DIRECTION OUTPUT ;
    USE SIGNAL ;
    PORT
      LAYER Metal4 ;
        RECT 170.600 0.000 170.680 1.000 ;
    END
  END m_o[423]
  PIN m_o[424]
    DIRECTION OUTPUT ;
    USE SIGNAL ;
    PORT
      LAYER Metal4 ;
        RECT 171.000 0.000 171.080 1.000 ;
    END
  END m_o[424]
  PIN m_o[425]
    DIRECTION OUTPUT ;
    USE SIGNAL ;
    PORT
      LAYER Metal4 ;
        RECT 171.400 0.000 171.480 1.000 ;
    END
  END m_o[425]
  PIN m_o[426]
    DIRECTION OUTPUT ;
    USE SIGNAL ;
    PORT
      LAYER Metal4 ;
        RECT 171.800 0.000 171.880 1.000 ;
    END
  END m_o[426]
  PIN m_o[427]
    DIRECTION OUTPUT ;
    USE SIGNAL ;
    PORT
      LAYER Metal4 ;
        RECT 172.200 0.000 172.280 1.000 ;
    END
  END m_o[427]
  PIN m_o[428]
    DIRECTION OUTPUT ;
    USE SIGNAL ;
    PORT
      LAYER Metal4 ;
        RECT 172.600 0.000 172.680 1.000 ;
    END
  END m_o[428]
  PIN m_o[429]
    DIRECTION OUTPUT ;
    USE SIGNAL ;
    PORT
      LAYER Metal4 ;
        RECT 173.000 0.000 173.080 1.000 ;
    END
  END m_o[429]
  PIN m_o[430]
    DIRECTION OUTPUT ;
    USE SIGNAL ;
    PORT
      LAYER Metal4 ;
        RECT 173.400 0.000 173.480 1.000 ;
    END
  END m_o[430]
  PIN m_o[431]
    DIRECTION OUTPUT ;
    USE SIGNAL ;
    PORT
      LAYER Metal4 ;
        RECT 173.800 0.000 173.880 1.000 ;
    END
  END m_o[431]
  PIN m_o[432]
    DIRECTION OUTPUT ;
    USE SIGNAL ;
    PORT
      LAYER Metal4 ;
        RECT 174.200 0.000 174.280 1.000 ;
    END
  END m_o[432]
  PIN m_o[433]
    DIRECTION OUTPUT ;
    USE SIGNAL ;
    PORT
      LAYER Metal4 ;
        RECT 174.600 0.000 174.680 1.000 ;
    END
  END m_o[433]
  PIN m_o[434]
    DIRECTION OUTPUT ;
    USE SIGNAL ;
    PORT
      LAYER Metal4 ;
        RECT 175.000 0.000 175.080 1.000 ;
    END
  END m_o[434]
  PIN m_o[435]
    DIRECTION OUTPUT ;
    USE SIGNAL ;
    PORT
      LAYER Metal4 ;
        RECT 175.400 0.000 175.480 1.000 ;
    END
  END m_o[435]
  PIN m_o[436]
    DIRECTION OUTPUT ;
    USE SIGNAL ;
    PORT
      LAYER Metal4 ;
        RECT 175.800 0.000 175.880 1.000 ;
    END
  END m_o[436]
  PIN m_o[437]
    DIRECTION OUTPUT ;
    USE SIGNAL ;
    PORT
      LAYER Metal4 ;
        RECT 176.200 0.000 176.280 1.000 ;
    END
  END m_o[437]
  PIN m_o[438]
    DIRECTION OUTPUT ;
    USE SIGNAL ;
    PORT
      LAYER Metal4 ;
        RECT 176.600 0.000 176.680 1.000 ;
    END
  END m_o[438]
  PIN m_o[439]
    DIRECTION OUTPUT ;
    USE SIGNAL ;
    PORT
      LAYER Metal4 ;
        RECT 177.000 0.000 177.080 1.000 ;
    END
  END m_o[439]
  PIN m_o[440]
    DIRECTION OUTPUT ;
    USE SIGNAL ;
    PORT
      LAYER Metal4 ;
        RECT 177.400 0.000 177.480 1.000 ;
    END
  END m_o[440]
  PIN m_o[441]
    DIRECTION OUTPUT ;
    USE SIGNAL ;
    PORT
      LAYER Metal4 ;
        RECT 177.800 0.000 177.880 1.000 ;
    END
  END m_o[441]
  PIN m_o[442]
    DIRECTION OUTPUT ;
    USE SIGNAL ;
    PORT
      LAYER Metal4 ;
        RECT 178.200 0.000 178.280 1.000 ;
    END
  END m_o[442]
  PIN m_o[443]
    DIRECTION OUTPUT ;
    USE SIGNAL ;
    PORT
      LAYER Metal4 ;
        RECT 178.600 0.000 178.680 1.000 ;
    END
  END m_o[443]
  PIN m_o[444]
    DIRECTION OUTPUT ;
    USE SIGNAL ;
    PORT
      LAYER Metal4 ;
        RECT 179.000 0.000 179.080 1.000 ;
    END
  END m_o[444]
  PIN m_o[445]
    DIRECTION OUTPUT ;
    USE SIGNAL ;
    PORT
      LAYER Metal4 ;
        RECT 179.400 0.000 179.480 1.000 ;
    END
  END m_o[445]
  PIN m_o[446]
    DIRECTION OUTPUT ;
    USE SIGNAL ;
    PORT
      LAYER Metal4 ;
        RECT 179.800 0.000 179.880 1.000 ;
    END
  END m_o[446]
  PIN m_o[447]
    DIRECTION OUTPUT ;
    USE SIGNAL ;
    PORT
      LAYER Metal4 ;
        RECT 180.200 0.000 180.280 1.000 ;
    END
  END m_o[447]
  PIN m_o[448]
    DIRECTION OUTPUT ;
    USE SIGNAL ;
    PORT
      LAYER Metal4 ;
        RECT 180.600 0.000 180.680 1.000 ;
    END
  END m_o[448]
  PIN m_o[449]
    DIRECTION OUTPUT ;
    USE SIGNAL ;
    PORT
      LAYER Metal4 ;
        RECT 181.000 0.000 181.080 1.000 ;
    END
  END m_o[449]
  PIN m_o[450]
    DIRECTION OUTPUT ;
    USE SIGNAL ;
    PORT
      LAYER Metal4 ;
        RECT 181.400 0.000 181.480 1.000 ;
    END
  END m_o[450]
  PIN m_o[451]
    DIRECTION OUTPUT ;
    USE SIGNAL ;
    PORT
      LAYER Metal4 ;
        RECT 181.800 0.000 181.880 1.000 ;
    END
  END m_o[451]
  PIN m_o[452]
    DIRECTION OUTPUT ;
    USE SIGNAL ;
    PORT
      LAYER Metal4 ;
        RECT 182.200 0.000 182.280 1.000 ;
    END
  END m_o[452]
  PIN m_o[453]
    DIRECTION OUTPUT ;
    USE SIGNAL ;
    PORT
      LAYER Metal4 ;
        RECT 182.600 0.000 182.680 1.000 ;
    END
  END m_o[453]
  PIN m_o[454]
    DIRECTION OUTPUT ;
    USE SIGNAL ;
    PORT
      LAYER Metal4 ;
        RECT 183.000 0.000 183.080 1.000 ;
    END
  END m_o[454]
  PIN m_o[455]
    DIRECTION OUTPUT ;
    USE SIGNAL ;
    PORT
      LAYER Metal4 ;
        RECT 183.400 0.000 183.480 1.000 ;
    END
  END m_o[455]
  PIN m_o[456]
    DIRECTION OUTPUT ;
    USE SIGNAL ;
    PORT
      LAYER Metal4 ;
        RECT 183.800 0.000 183.880 1.000 ;
    END
  END m_o[456]
  PIN m_o[457]
    DIRECTION OUTPUT ;
    USE SIGNAL ;
    PORT
      LAYER Metal4 ;
        RECT 184.200 0.000 184.280 1.000 ;
    END
  END m_o[457]
  PIN m_o[458]
    DIRECTION OUTPUT ;
    USE SIGNAL ;
    PORT
      LAYER Metal4 ;
        RECT 184.600 0.000 184.680 1.000 ;
    END
  END m_o[458]
  PIN m_o[459]
    DIRECTION OUTPUT ;
    USE SIGNAL ;
    PORT
      LAYER Metal4 ;
        RECT 185.000 0.000 185.080 1.000 ;
    END
  END m_o[459]
  PIN m_o[460]
    DIRECTION OUTPUT ;
    USE SIGNAL ;
    PORT
      LAYER Metal4 ;
        RECT 185.400 0.000 185.480 1.000 ;
    END
  END m_o[460]
  PIN m_o[461]
    DIRECTION OUTPUT ;
    USE SIGNAL ;
    PORT
      LAYER Metal4 ;
        RECT 185.800 0.000 185.880 1.000 ;
    END
  END m_o[461]
  PIN m_o[462]
    DIRECTION OUTPUT ;
    USE SIGNAL ;
    PORT
      LAYER Metal4 ;
        RECT 186.200 0.000 186.280 1.000 ;
    END
  END m_o[462]
  PIN m_o[463]
    DIRECTION OUTPUT ;
    USE SIGNAL ;
    PORT
      LAYER Metal4 ;
        RECT 186.600 0.000 186.680 1.000 ;
    END
  END m_o[463]
  PIN m_o[464]
    DIRECTION OUTPUT ;
    USE SIGNAL ;
    PORT
      LAYER Metal4 ;
        RECT 187.000 0.000 187.080 1.000 ;
    END
  END m_o[464]
  PIN m_o[465]
    DIRECTION OUTPUT ;
    USE SIGNAL ;
    PORT
      LAYER Metal4 ;
        RECT 187.400 0.000 187.480 1.000 ;
    END
  END m_o[465]
  PIN m_o[466]
    DIRECTION OUTPUT ;
    USE SIGNAL ;
    PORT
      LAYER Metal4 ;
        RECT 187.800 0.000 187.880 1.000 ;
    END
  END m_o[466]
  PIN m_o[467]
    DIRECTION OUTPUT ;
    USE SIGNAL ;
    PORT
      LAYER Metal4 ;
        RECT 188.200 0.000 188.280 1.000 ;
    END
  END m_o[467]
  PIN m_o[468]
    DIRECTION OUTPUT ;
    USE SIGNAL ;
    PORT
      LAYER Metal4 ;
        RECT 188.600 0.000 188.680 1.000 ;
    END
  END m_o[468]
  PIN m_o[469]
    DIRECTION OUTPUT ;
    USE SIGNAL ;
    PORT
      LAYER Metal4 ;
        RECT 189.000 0.000 189.080 1.000 ;
    END
  END m_o[469]
  PIN m_o[470]
    DIRECTION OUTPUT ;
    USE SIGNAL ;
    PORT
      LAYER Metal4 ;
        RECT 189.400 0.000 189.480 1.000 ;
    END
  END m_o[470]
  PIN m_o[471]
    DIRECTION OUTPUT ;
    USE SIGNAL ;
    PORT
      LAYER Metal4 ;
        RECT 189.800 0.000 189.880 1.000 ;
    END
  END m_o[471]
  PIN m_o[472]
    DIRECTION OUTPUT ;
    USE SIGNAL ;
    PORT
      LAYER Metal4 ;
        RECT 190.200 0.000 190.280 1.000 ;
    END
  END m_o[472]
  PIN m_o[473]
    DIRECTION OUTPUT ;
    USE SIGNAL ;
    PORT
      LAYER Metal4 ;
        RECT 190.600 0.000 190.680 1.000 ;
    END
  END m_o[473]
  PIN m_o[474]
    DIRECTION OUTPUT ;
    USE SIGNAL ;
    PORT
      LAYER Metal4 ;
        RECT 191.000 0.000 191.080 1.000 ;
    END
  END m_o[474]
  PIN m_o[475]
    DIRECTION OUTPUT ;
    USE SIGNAL ;
    PORT
      LAYER Metal4 ;
        RECT 191.400 0.000 191.480 1.000 ;
    END
  END m_o[475]
  PIN m_o[476]
    DIRECTION OUTPUT ;
    USE SIGNAL ;
    PORT
      LAYER Metal4 ;
        RECT 191.800 0.000 191.880 1.000 ;
    END
  END m_o[476]
  PIN m_o[477]
    DIRECTION OUTPUT ;
    USE SIGNAL ;
    PORT
      LAYER Metal4 ;
        RECT 192.200 0.000 192.280 1.000 ;
    END
  END m_o[477]
  PIN m_o[478]
    DIRECTION OUTPUT ;
    USE SIGNAL ;
    PORT
      LAYER Metal4 ;
        RECT 192.600 0.000 192.680 1.000 ;
    END
  END m_o[478]
  PIN m_o[479]
    DIRECTION OUTPUT ;
    USE SIGNAL ;
    PORT
      LAYER Metal4 ;
        RECT 193.000 0.000 193.080 1.000 ;
    END
  END m_o[479]
  PIN m_o[480]
    DIRECTION OUTPUT ;
    USE SIGNAL ;
    PORT
      LAYER Metal4 ;
        RECT 193.400 0.000 193.480 1.000 ;
    END
  END m_o[480]
  PIN m_o[481]
    DIRECTION OUTPUT ;
    USE SIGNAL ;
    PORT
      LAYER Metal4 ;
        RECT 193.800 0.000 193.880 1.000 ;
    END
  END m_o[481]
  PIN m_o[482]
    DIRECTION OUTPUT ;
    USE SIGNAL ;
    PORT
      LAYER Metal4 ;
        RECT 194.200 0.000 194.280 1.000 ;
    END
  END m_o[482]
  PIN m_o[483]
    DIRECTION OUTPUT ;
    USE SIGNAL ;
    PORT
      LAYER Metal4 ;
        RECT 194.600 0.000 194.680 1.000 ;
    END
  END m_o[483]
  PIN m_o[484]
    DIRECTION OUTPUT ;
    USE SIGNAL ;
    PORT
      LAYER Metal4 ;
        RECT 195.000 0.000 195.080 1.000 ;
    END
  END m_o[484]
  PIN m_o[485]
    DIRECTION OUTPUT ;
    USE SIGNAL ;
    PORT
      LAYER Metal4 ;
        RECT 195.400 0.000 195.480 1.000 ;
    END
  END m_o[485]
  PIN m_o[486]
    DIRECTION OUTPUT ;
    USE SIGNAL ;
    PORT
      LAYER Metal4 ;
        RECT 195.800 0.000 195.880 1.000 ;
    END
  END m_o[486]
  PIN m_o[487]
    DIRECTION OUTPUT ;
    USE SIGNAL ;
    PORT
      LAYER Metal4 ;
        RECT 196.200 0.000 196.280 1.000 ;
    END
  END m_o[487]
  PIN m_o[488]
    DIRECTION OUTPUT ;
    USE SIGNAL ;
    PORT
      LAYER Metal4 ;
        RECT 196.600 0.000 196.680 1.000 ;
    END
  END m_o[488]
  PIN m_o[489]
    DIRECTION OUTPUT ;
    USE SIGNAL ;
    PORT
      LAYER Metal4 ;
        RECT 197.000 0.000 197.080 1.000 ;
    END
  END m_o[489]
  PIN m_o[490]
    DIRECTION OUTPUT ;
    USE SIGNAL ;
    PORT
      LAYER Metal4 ;
        RECT 197.400 0.000 197.480 1.000 ;
    END
  END m_o[490]
  PIN m_o[491]
    DIRECTION OUTPUT ;
    USE SIGNAL ;
    PORT
      LAYER Metal4 ;
        RECT 197.800 0.000 197.880 1.000 ;
    END
  END m_o[491]
  PIN m_o[492]
    DIRECTION OUTPUT ;
    USE SIGNAL ;
    PORT
      LAYER Metal4 ;
        RECT 198.200 0.000 198.280 1.000 ;
    END
  END m_o[492]
  PIN m_o[493]
    DIRECTION OUTPUT ;
    USE SIGNAL ;
    PORT
      LAYER Metal4 ;
        RECT 198.600 0.000 198.680 1.000 ;
    END
  END m_o[493]
  PIN m_o[494]
    DIRECTION OUTPUT ;
    USE SIGNAL ;
    PORT
      LAYER Metal4 ;
        RECT 199.000 0.000 199.080 1.000 ;
    END
  END m_o[494]
  PIN m_o[495]
    DIRECTION OUTPUT ;
    USE SIGNAL ;
    PORT
      LAYER Metal4 ;
        RECT 199.400 0.000 199.480 1.000 ;
    END
  END m_o[495]
  PIN m_o[496]
    DIRECTION OUTPUT ;
    USE SIGNAL ;
    PORT
      LAYER Metal4 ;
        RECT 199.800 0.000 199.880 1.000 ;
    END
  END m_o[496]
  PIN m_o[497]
    DIRECTION OUTPUT ;
    USE SIGNAL ;
    PORT
      LAYER Metal4 ;
        RECT 200.200 0.000 200.280 1.000 ;
    END
  END m_o[497]
  PIN m_o[498]
    DIRECTION OUTPUT ;
    USE SIGNAL ;
    PORT
      LAYER Metal4 ;
        RECT 200.600 0.000 200.680 1.000 ;
    END
  END m_o[498]
  PIN m_o[499]
    DIRECTION OUTPUT ;
    USE SIGNAL ;
    PORT
      LAYER Metal4 ;
        RECT 201.000 0.000 201.080 1.000 ;
    END
  END m_o[499]
  PIN m_o[500]
    DIRECTION OUTPUT ;
    USE SIGNAL ;
    PORT
      LAYER Metal4 ;
        RECT 201.400 0.000 201.480 1.000 ;
    END
  END m_o[500]
  PIN m_o[501]
    DIRECTION OUTPUT ;
    USE SIGNAL ;
    PORT
      LAYER Metal4 ;
        RECT 201.800 0.000 201.880 1.000 ;
    END
  END m_o[501]
  PIN m_o[502]
    DIRECTION OUTPUT ;
    USE SIGNAL ;
    PORT
      LAYER Metal4 ;
        RECT 202.200 0.000 202.280 1.000 ;
    END
  END m_o[502]
  PIN m_o[503]
    DIRECTION OUTPUT ;
    USE SIGNAL ;
    PORT
      LAYER Metal4 ;
        RECT 202.600 0.000 202.680 1.000 ;
    END
  END m_o[503]
  PIN m_o[504]
    DIRECTION OUTPUT ;
    USE SIGNAL ;
    PORT
      LAYER Metal4 ;
        RECT 203.000 0.000 203.080 1.000 ;
    END
  END m_o[504]
  PIN m_o[505]
    DIRECTION OUTPUT ;
    USE SIGNAL ;
    PORT
      LAYER Metal4 ;
        RECT 203.400 0.000 203.480 1.000 ;
    END
  END m_o[505]
  PIN m_o[506]
    DIRECTION OUTPUT ;
    USE SIGNAL ;
    PORT
      LAYER Metal4 ;
        RECT 203.800 0.000 203.880 1.000 ;
    END
  END m_o[506]
  PIN m_o[507]
    DIRECTION OUTPUT ;
    USE SIGNAL ;
    PORT
      LAYER Metal4 ;
        RECT 204.200 0.000 204.280 1.000 ;
    END
  END m_o[507]
  PIN m_o[508]
    DIRECTION OUTPUT ;
    USE SIGNAL ;
    PORT
      LAYER Metal4 ;
        RECT 204.600 0.000 204.680 1.000 ;
    END
  END m_o[508]
  PIN m_o[509]
    DIRECTION OUTPUT ;
    USE SIGNAL ;
    PORT
      LAYER Metal4 ;
        RECT 205.000 0.000 205.080 1.000 ;
    END
  END m_o[509]
  PIN m_o[510]
    DIRECTION OUTPUT ;
    USE SIGNAL ;
    PORT
      LAYER Metal4 ;
        RECT 205.400 0.000 205.480 1.000 ;
    END
  END m_o[510]
  PIN m_o[511]
    DIRECTION OUTPUT ;
    USE SIGNAL ;
    PORT
      LAYER Metal4 ;
        RECT 205.800 0.000 205.880 1.000 ;
    END
  END m_o[511]
  PIN m_o[512]
    DIRECTION OUTPUT ;
    USE SIGNAL ;
    PORT
      LAYER Metal4 ;
        RECT 206.200 0.000 206.280 1.000 ;
    END
  END m_o[512]
  PIN m_o[513]
    DIRECTION OUTPUT ;
    USE SIGNAL ;
    PORT
      LAYER Metal4 ;
        RECT 206.600 0.000 206.680 1.000 ;
    END
  END m_o[513]
  PIN m_o[514]
    DIRECTION OUTPUT ;
    USE SIGNAL ;
    PORT
      LAYER Metal4 ;
        RECT 207.000 0.000 207.080 1.000 ;
    END
  END m_o[514]
  PIN m_o[515]
    DIRECTION OUTPUT ;
    USE SIGNAL ;
    PORT
      LAYER Metal4 ;
        RECT 207.400 0.000 207.480 1.000 ;
    END
  END m_o[515]
  PIN m_o[516]
    DIRECTION OUTPUT ;
    USE SIGNAL ;
    PORT
      LAYER Metal4 ;
        RECT 207.800 0.000 207.880 1.000 ;
    END
  END m_o[516]
  PIN m_o[517]
    DIRECTION OUTPUT ;
    USE SIGNAL ;
    PORT
      LAYER Metal4 ;
        RECT 208.200 0.000 208.280 1.000 ;
    END
  END m_o[517]
  PIN m_o[518]
    DIRECTION OUTPUT ;
    USE SIGNAL ;
    PORT
      LAYER Metal4 ;
        RECT 208.600 0.000 208.680 1.000 ;
    END
  END m_o[518]
  PIN m_o[519]
    DIRECTION OUTPUT ;
    USE SIGNAL ;
    PORT
      LAYER Metal4 ;
        RECT 209.000 0.000 209.080 1.000 ;
    END
  END m_o[519]
  PIN m_o[520]
    DIRECTION OUTPUT ;
    USE SIGNAL ;
    PORT
      LAYER Metal4 ;
        RECT 209.400 0.000 209.480 1.000 ;
    END
  END m_o[520]
  PIN m_o[521]
    DIRECTION OUTPUT ;
    USE SIGNAL ;
    PORT
      LAYER Metal4 ;
        RECT 209.800 0.000 209.880 1.000 ;
    END
  END m_o[521]
  PIN m_o[522]
    DIRECTION OUTPUT ;
    USE SIGNAL ;
    PORT
      LAYER Metal4 ;
        RECT 210.200 0.000 210.280 1.000 ;
    END
  END m_o[522]
  PIN m_o[523]
    DIRECTION OUTPUT ;
    USE SIGNAL ;
    PORT
      LAYER Metal4 ;
        RECT 210.600 0.000 210.680 1.000 ;
    END
  END m_o[523]
  PIN m_o[524]
    DIRECTION OUTPUT ;
    USE SIGNAL ;
    PORT
      LAYER Metal4 ;
        RECT 211.000 0.000 211.080 1.000 ;
    END
  END m_o[524]
  PIN m_o[525]
    DIRECTION OUTPUT ;
    USE SIGNAL ;
    PORT
      LAYER Metal4 ;
        RECT 211.400 0.000 211.480 1.000 ;
    END
  END m_o[525]
  PIN m_o[526]
    DIRECTION OUTPUT ;
    USE SIGNAL ;
    PORT
      LAYER Metal4 ;
        RECT 211.800 0.000 211.880 1.000 ;
    END
  END m_o[526]
  PIN m_o[527]
    DIRECTION OUTPUT ;
    USE SIGNAL ;
    PORT
      LAYER Metal4 ;
        RECT 212.200 0.000 212.280 1.000 ;
    END
  END m_o[527]
  PIN m_o[528]
    DIRECTION OUTPUT ;
    USE SIGNAL ;
    PORT
      LAYER Metal4 ;
        RECT 212.600 0.000 212.680 1.000 ;
    END
  END m_o[528]
  PIN m_o[529]
    DIRECTION OUTPUT ;
    USE SIGNAL ;
    PORT
      LAYER Metal4 ;
        RECT 213.000 0.000 213.080 1.000 ;
    END
  END m_o[529]
  PIN m_o[530]
    DIRECTION OUTPUT ;
    USE SIGNAL ;
    PORT
      LAYER Metal4 ;
        RECT 213.400 0.000 213.480 1.000 ;
    END
  END m_o[530]
  PIN m_o[531]
    DIRECTION OUTPUT ;
    USE SIGNAL ;
    PORT
      LAYER Metal4 ;
        RECT 213.800 0.000 213.880 1.000 ;
    END
  END m_o[531]
  PIN m_o[532]
    DIRECTION OUTPUT ;
    USE SIGNAL ;
    PORT
      LAYER Metal4 ;
        RECT 214.200 0.000 214.280 1.000 ;
    END
  END m_o[532]
  PIN m_o[533]
    DIRECTION OUTPUT ;
    USE SIGNAL ;
    PORT
      LAYER Metal4 ;
        RECT 214.600 0.000 214.680 1.000 ;
    END
  END m_o[533]
  PIN m_o[534]
    DIRECTION OUTPUT ;
    USE SIGNAL ;
    PORT
      LAYER Metal4 ;
        RECT 215.000 0.000 215.080 1.000 ;
    END
  END m_o[534]
  PIN m_o[535]
    DIRECTION OUTPUT ;
    USE SIGNAL ;
    PORT
      LAYER Metal4 ;
        RECT 215.400 0.000 215.480 1.000 ;
    END
  END m_o[535]
  PIN m_o[536]
    DIRECTION OUTPUT ;
    USE SIGNAL ;
    PORT
      LAYER Metal4 ;
        RECT 215.800 0.000 215.880 1.000 ;
    END
  END m_o[536]
  PIN m_o[537]
    DIRECTION OUTPUT ;
    USE SIGNAL ;
    PORT
      LAYER Metal4 ;
        RECT 216.200 0.000 216.280 1.000 ;
    END
  END m_o[537]
  PIN m_o[538]
    DIRECTION OUTPUT ;
    USE SIGNAL ;
    PORT
      LAYER Metal4 ;
        RECT 216.600 0.000 216.680 1.000 ;
    END
  END m_o[538]
  PIN m_o[539]
    DIRECTION OUTPUT ;
    USE SIGNAL ;
    PORT
      LAYER Metal4 ;
        RECT 217.000 0.000 217.080 1.000 ;
    END
  END m_o[539]
  PIN m_o[540]
    DIRECTION OUTPUT ;
    USE SIGNAL ;
    PORT
      LAYER Metal4 ;
        RECT 217.400 0.000 217.480 1.000 ;
    END
  END m_o[540]
  PIN m_o[541]
    DIRECTION OUTPUT ;
    USE SIGNAL ;
    PORT
      LAYER Metal4 ;
        RECT 217.800 0.000 217.880 1.000 ;
    END
  END m_o[541]
  PIN m_o[542]
    DIRECTION OUTPUT ;
    USE SIGNAL ;
    PORT
      LAYER Metal4 ;
        RECT 218.200 0.000 218.280 1.000 ;
    END
  END m_o[542]
  PIN m_o[543]
    DIRECTION OUTPUT ;
    USE SIGNAL ;
    PORT
      LAYER Metal4 ;
        RECT 218.600 0.000 218.680 1.000 ;
    END
  END m_o[543]
  PIN m_o[544]
    DIRECTION OUTPUT ;
    USE SIGNAL ;
    PORT
      LAYER Metal4 ;
        RECT 219.000 0.000 219.080 1.000 ;
    END
  END m_o[544]
  PIN m_o[545]
    DIRECTION OUTPUT ;
    USE SIGNAL ;
    PORT
      LAYER Metal4 ;
        RECT 219.400 0.000 219.480 1.000 ;
    END
  END m_o[545]
  PIN m_o[546]
    DIRECTION OUTPUT ;
    USE SIGNAL ;
    PORT
      LAYER Metal4 ;
        RECT 219.800 0.000 219.880 1.000 ;
    END
  END m_o[546]
  PIN m_o[547]
    DIRECTION OUTPUT ;
    USE SIGNAL ;
    PORT
      LAYER Metal4 ;
        RECT 220.200 0.000 220.280 1.000 ;
    END
  END m_o[547]
  PIN m_o[548]
    DIRECTION OUTPUT ;
    USE SIGNAL ;
    PORT
      LAYER Metal4 ;
        RECT 220.600 0.000 220.680 1.000 ;
    END
  END m_o[548]
  PIN m_o[549]
    DIRECTION OUTPUT ;
    USE SIGNAL ;
    PORT
      LAYER Metal4 ;
        RECT 221.000 0.000 221.080 1.000 ;
    END
  END m_o[549]
  PIN m_o[550]
    DIRECTION OUTPUT ;
    USE SIGNAL ;
    PORT
      LAYER Metal4 ;
        RECT 221.400 0.000 221.480 1.000 ;
    END
  END m_o[550]
  PIN m_o[551]
    DIRECTION OUTPUT ;
    USE SIGNAL ;
    PORT
      LAYER Metal4 ;
        RECT 221.800 0.000 221.880 1.000 ;
    END
  END m_o[551]
  PIN m_o[552]
    DIRECTION OUTPUT ;
    USE SIGNAL ;
    PORT
      LAYER Metal4 ;
        RECT 222.200 0.000 222.280 1.000 ;
    END
  END m_o[552]
  PIN m_o[553]
    DIRECTION OUTPUT ;
    USE SIGNAL ;
    PORT
      LAYER Metal4 ;
        RECT 222.600 0.000 222.680 1.000 ;
    END
  END m_o[553]
  PIN m_o[554]
    DIRECTION OUTPUT ;
    USE SIGNAL ;
    PORT
      LAYER Metal4 ;
        RECT 223.000 0.000 223.080 1.000 ;
    END
  END m_o[554]
  PIN m_o[555]
    DIRECTION OUTPUT ;
    USE SIGNAL ;
    PORT
      LAYER Metal4 ;
        RECT 223.400 0.000 223.480 1.000 ;
    END
  END m_o[555]
  PIN m_o[556]
    DIRECTION OUTPUT ;
    USE SIGNAL ;
    PORT
      LAYER Metal4 ;
        RECT 223.800 0.000 223.880 1.000 ;
    END
  END m_o[556]
  PIN m_o[557]
    DIRECTION OUTPUT ;
    USE SIGNAL ;
    PORT
      LAYER Metal4 ;
        RECT 224.200 0.000 224.280 1.000 ;
    END
  END m_o[557]
  PIN m_o[558]
    DIRECTION OUTPUT ;
    USE SIGNAL ;
    PORT
      LAYER Metal4 ;
        RECT 224.600 0.000 224.680 1.000 ;
    END
  END m_o[558]
  PIN m_o[559]
    DIRECTION OUTPUT ;
    USE SIGNAL ;
    PORT
      LAYER Metal4 ;
        RECT 225.000 0.000 225.080 1.000 ;
    END
  END m_o[559]
  PIN m_o[560]
    DIRECTION OUTPUT ;
    USE SIGNAL ;
    PORT
      LAYER Metal4 ;
        RECT 225.400 0.000 225.480 1.000 ;
    END
  END m_o[560]
  PIN m_o[561]
    DIRECTION OUTPUT ;
    USE SIGNAL ;
    PORT
      LAYER Metal4 ;
        RECT 225.800 0.000 225.880 1.000 ;
    END
  END m_o[561]
  PIN m_o[562]
    DIRECTION OUTPUT ;
    USE SIGNAL ;
    PORT
      LAYER Metal4 ;
        RECT 226.200 0.000 226.280 1.000 ;
    END
  END m_o[562]
  PIN m_o[563]
    DIRECTION OUTPUT ;
    USE SIGNAL ;
    PORT
      LAYER Metal4 ;
        RECT 226.600 0.000 226.680 1.000 ;
    END
  END m_o[563]
  PIN m_o[564]
    DIRECTION OUTPUT ;
    USE SIGNAL ;
    PORT
      LAYER Metal4 ;
        RECT 227.000 0.000 227.080 1.000 ;
    END
  END m_o[564]
  PIN m_o[565]
    DIRECTION OUTPUT ;
    USE SIGNAL ;
    PORT
      LAYER Metal4 ;
        RECT 227.400 0.000 227.480 1.000 ;
    END
  END m_o[565]
  PIN m_o[566]
    DIRECTION OUTPUT ;
    USE SIGNAL ;
    PORT
      LAYER Metal4 ;
        RECT 227.800 0.000 227.880 1.000 ;
    END
  END m_o[566]
  PIN m_o[567]
    DIRECTION OUTPUT ;
    USE SIGNAL ;
    PORT
      LAYER Metal4 ;
        RECT 228.200 0.000 228.280 1.000 ;
    END
  END m_o[567]
  PIN m_o[568]
    DIRECTION OUTPUT ;
    USE SIGNAL ;
    PORT
      LAYER Metal4 ;
        RECT 228.600 0.000 228.680 1.000 ;
    END
  END m_o[568]
  PIN m_o[569]
    DIRECTION OUTPUT ;
    USE SIGNAL ;
    PORT
      LAYER Metal4 ;
        RECT 229.000 0.000 229.080 1.000 ;
    END
  END m_o[569]
  PIN m_o[570]
    DIRECTION OUTPUT ;
    USE SIGNAL ;
    PORT
      LAYER Metal4 ;
        RECT 229.400 0.000 229.480 1.000 ;
    END
  END m_o[570]
  PIN m_o[571]
    DIRECTION OUTPUT ;
    USE SIGNAL ;
    PORT
      LAYER Metal4 ;
        RECT 229.800 0.000 229.880 1.000 ;
    END
  END m_o[571]
  PIN m_o[572]
    DIRECTION OUTPUT ;
    USE SIGNAL ;
    PORT
      LAYER Metal4 ;
        RECT 230.200 0.000 230.280 1.000 ;
    END
  END m_o[572]
  PIN m_o[573]
    DIRECTION OUTPUT ;
    USE SIGNAL ;
    PORT
      LAYER Metal4 ;
        RECT 230.600 0.000 230.680 1.000 ;
    END
  END m_o[573]
  PIN m_o[574]
    DIRECTION OUTPUT ;
    USE SIGNAL ;
    PORT
      LAYER Metal4 ;
        RECT 231.000 0.000 231.080 1.000 ;
    END
  END m_o[574]
  PIN m_o[575]
    DIRECTION OUTPUT ;
    USE SIGNAL ;
    PORT
      LAYER Metal4 ;
        RECT 231.400 0.000 231.480 1.000 ;
    END
  END m_o[575]
  PIN m_o[576]
    DIRECTION OUTPUT ;
    USE SIGNAL ;
    PORT
      LAYER Metal4 ;
        RECT 231.800 0.000 231.880 1.000 ;
    END
  END m_o[576]
  PIN m_o[577]
    DIRECTION OUTPUT ;
    USE SIGNAL ;
    PORT
      LAYER Metal4 ;
        RECT 232.200 0.000 232.280 1.000 ;
    END
  END m_o[577]
  PIN m_o[578]
    DIRECTION OUTPUT ;
    USE SIGNAL ;
    PORT
      LAYER Metal4 ;
        RECT 232.600 0.000 232.680 1.000 ;
    END
  END m_o[578]
  PIN m_o[579]
    DIRECTION OUTPUT ;
    USE SIGNAL ;
    PORT
      LAYER Metal4 ;
        RECT 233.000 0.000 233.080 1.000 ;
    END
  END m_o[579]
  PIN m_o[580]
    DIRECTION OUTPUT ;
    USE SIGNAL ;
    PORT
      LAYER Metal4 ;
        RECT 233.400 0.000 233.480 1.000 ;
    END
  END m_o[580]
  PIN m_o[581]
    DIRECTION OUTPUT ;
    USE SIGNAL ;
    PORT
      LAYER Metal4 ;
        RECT 233.800 0.000 233.880 1.000 ;
    END
  END m_o[581]
  PIN m_o[582]
    DIRECTION OUTPUT ;
    USE SIGNAL ;
    PORT
      LAYER Metal4 ;
        RECT 234.200 0.000 234.280 1.000 ;
    END
  END m_o[582]
  PIN m_o[583]
    DIRECTION OUTPUT ;
    USE SIGNAL ;
    PORT
      LAYER Metal4 ;
        RECT 234.600 0.000 234.680 1.000 ;
    END
  END m_o[583]
  PIN m_o[584]
    DIRECTION OUTPUT ;
    USE SIGNAL ;
    PORT
      LAYER Metal4 ;
        RECT 235.000 0.000 235.080 1.000 ;
    END
  END m_o[584]
  PIN m_o[585]
    DIRECTION OUTPUT ;
    USE SIGNAL ;
    PORT
      LAYER Metal4 ;
        RECT 235.400 0.000 235.480 1.000 ;
    END
  END m_o[585]
  PIN m_o[586]
    DIRECTION OUTPUT ;
    USE SIGNAL ;
    PORT
      LAYER Metal4 ;
        RECT 235.800 0.000 235.880 1.000 ;
    END
  END m_o[586]
  PIN m_o[587]
    DIRECTION OUTPUT ;
    USE SIGNAL ;
    PORT
      LAYER Metal4 ;
        RECT 236.200 0.000 236.280 1.000 ;
    END
  END m_o[587]
  PIN m_o[588]
    DIRECTION OUTPUT ;
    USE SIGNAL ;
    PORT
      LAYER Metal4 ;
        RECT 236.600 0.000 236.680 1.000 ;
    END
  END m_o[588]
  PIN m_o[589]
    DIRECTION OUTPUT ;
    USE SIGNAL ;
    PORT
      LAYER Metal4 ;
        RECT 237.000 0.000 237.080 1.000 ;
    END
  END m_o[589]
  PIN m_o[590]
    DIRECTION OUTPUT ;
    USE SIGNAL ;
    PORT
      LAYER Metal4 ;
        RECT 237.400 0.000 237.480 1.000 ;
    END
  END m_o[590]
  PIN m_o[591]
    DIRECTION OUTPUT ;
    USE SIGNAL ;
    PORT
      LAYER Metal4 ;
        RECT 237.800 0.000 237.880 1.000 ;
    END
  END m_o[591]
  PIN m_o[592]
    DIRECTION OUTPUT ;
    USE SIGNAL ;
    PORT
      LAYER Metal4 ;
        RECT 238.200 0.000 238.280 1.000 ;
    END
  END m_o[592]
  PIN m_o[593]
    DIRECTION OUTPUT ;
    USE SIGNAL ;
    PORT
      LAYER Metal4 ;
        RECT 238.600 0.000 238.680 1.000 ;
    END
  END m_o[593]
  PIN m_o[594]
    DIRECTION OUTPUT ;
    USE SIGNAL ;
    PORT
      LAYER Metal4 ;
        RECT 239.000 0.000 239.080 1.000 ;
    END
  END m_o[594]
  PIN m_o[595]
    DIRECTION OUTPUT ;
    USE SIGNAL ;
    PORT
      LAYER Metal4 ;
        RECT 239.400 0.000 239.480 1.000 ;
    END
  END m_o[595]
  PIN m_o[596]
    DIRECTION OUTPUT ;
    USE SIGNAL ;
    PORT
      LAYER Metal4 ;
        RECT 239.800 0.000 239.880 1.000 ;
    END
  END m_o[596]
  PIN m_o[597]
    DIRECTION OUTPUT ;
    USE SIGNAL ;
    PORT
      LAYER Metal4 ;
        RECT 240.200 0.000 240.280 1.000 ;
    END
  END m_o[597]
  PIN m_o[598]
    DIRECTION OUTPUT ;
    USE SIGNAL ;
    PORT
      LAYER Metal4 ;
        RECT 240.600 0.000 240.680 1.000 ;
    END
  END m_o[598]
  PIN m_o[599]
    DIRECTION OUTPUT ;
    USE SIGNAL ;
    PORT
      LAYER Metal4 ;
        RECT 241.000 0.000 241.080 1.000 ;
    END
  END m_o[599]
  PIN m_o[600]
    DIRECTION OUTPUT ;
    USE SIGNAL ;
    PORT
      LAYER Metal4 ;
        RECT 241.400 0.000 241.480 1.000 ;
    END
  END m_o[600]
  PIN m_o[601]
    DIRECTION OUTPUT ;
    USE SIGNAL ;
    PORT
      LAYER Metal4 ;
        RECT 241.800 0.000 241.880 1.000 ;
    END
  END m_o[601]
  PIN m_o[602]
    DIRECTION OUTPUT ;
    USE SIGNAL ;
    PORT
      LAYER Metal4 ;
        RECT 242.200 0.000 242.280 1.000 ;
    END
  END m_o[602]
  PIN m_o[603]
    DIRECTION OUTPUT ;
    USE SIGNAL ;
    PORT
      LAYER Metal4 ;
        RECT 242.600 0.000 242.680 1.000 ;
    END
  END m_o[603]
  PIN m_o[604]
    DIRECTION OUTPUT ;
    USE SIGNAL ;
    PORT
      LAYER Metal4 ;
        RECT 243.000 0.000 243.080 1.000 ;
    END
  END m_o[604]
  PIN m_o[605]
    DIRECTION OUTPUT ;
    USE SIGNAL ;
    PORT
      LAYER Metal4 ;
        RECT 243.400 0.000 243.480 1.000 ;
    END
  END m_o[605]
  PIN m_o[606]
    DIRECTION OUTPUT ;
    USE SIGNAL ;
    PORT
      LAYER Metal4 ;
        RECT 243.800 0.000 243.880 1.000 ;
    END
  END m_o[606]
  PIN m_o[607]
    DIRECTION OUTPUT ;
    USE SIGNAL ;
    PORT
      LAYER Metal4 ;
        RECT 244.200 0.000 244.280 1.000 ;
    END
  END m_o[607]
  PIN m_o[608]
    DIRECTION OUTPUT ;
    USE SIGNAL ;
    PORT
      LAYER Metal4 ;
        RECT 244.600 0.000 244.680 1.000 ;
    END
  END m_o[608]
  PIN m_o[609]
    DIRECTION OUTPUT ;
    USE SIGNAL ;
    PORT
      LAYER Metal4 ;
        RECT 245.000 0.000 245.080 1.000 ;
    END
  END m_o[609]
  PIN m_o[610]
    DIRECTION OUTPUT ;
    USE SIGNAL ;
    PORT
      LAYER Metal4 ;
        RECT 245.400 0.000 245.480 1.000 ;
    END
  END m_o[610]
  PIN m_o[611]
    DIRECTION OUTPUT ;
    USE SIGNAL ;
    PORT
      LAYER Metal4 ;
        RECT 245.800 0.000 245.880 1.000 ;
    END
  END m_o[611]
  PIN m_o[612]
    DIRECTION OUTPUT ;
    USE SIGNAL ;
    PORT
      LAYER Metal4 ;
        RECT 246.200 0.000 246.280 1.000 ;
    END
  END m_o[612]
  PIN m_o[613]
    DIRECTION OUTPUT ;
    USE SIGNAL ;
    PORT
      LAYER Metal4 ;
        RECT 246.600 0.000 246.680 1.000 ;
    END
  END m_o[613]
  PIN m_o[614]
    DIRECTION OUTPUT ;
    USE SIGNAL ;
    PORT
      LAYER Metal4 ;
        RECT 247.000 0.000 247.080 1.000 ;
    END
  END m_o[614]
  PIN m_o[615]
    DIRECTION OUTPUT ;
    USE SIGNAL ;
    PORT
      LAYER Metal4 ;
        RECT 247.400 0.000 247.480 1.000 ;
    END
  END m_o[615]
  PIN m_o[616]
    DIRECTION OUTPUT ;
    USE SIGNAL ;
    PORT
      LAYER Metal4 ;
        RECT 247.800 0.000 247.880 1.000 ;
    END
  END m_o[616]
  PIN m_o[617]
    DIRECTION OUTPUT ;
    USE SIGNAL ;
    PORT
      LAYER Metal4 ;
        RECT 248.200 0.000 248.280 1.000 ;
    END
  END m_o[617]
  PIN m_o[618]
    DIRECTION OUTPUT ;
    USE SIGNAL ;
    PORT
      LAYER Metal4 ;
        RECT 248.600 0.000 248.680 1.000 ;
    END
  END m_o[618]
  PIN m_o[619]
    DIRECTION OUTPUT ;
    USE SIGNAL ;
    PORT
      LAYER Metal4 ;
        RECT 249.000 0.000 249.080 1.000 ;
    END
  END m_o[619]
  PIN m_o[620]
    DIRECTION OUTPUT ;
    USE SIGNAL ;
    PORT
      LAYER Metal4 ;
        RECT 249.400 0.000 249.480 1.000 ;
    END
  END m_o[620]
  PIN m_o[621]
    DIRECTION OUTPUT ;
    USE SIGNAL ;
    PORT
      LAYER Metal4 ;
        RECT 249.800 0.000 249.880 1.000 ;
    END
  END m_o[621]
  PIN m_o[622]
    DIRECTION OUTPUT ;
    USE SIGNAL ;
    PORT
      LAYER Metal4 ;
        RECT 250.200 0.000 250.280 1.000 ;
    END
  END m_o[622]
  PIN m_o[623]
    DIRECTION OUTPUT ;
    USE SIGNAL ;
    PORT
      LAYER Metal4 ;
        RECT 250.600 0.000 250.680 1.000 ;
    END
  END m_o[623]
  PIN m_o[624]
    DIRECTION OUTPUT ;
    USE SIGNAL ;
    PORT
      LAYER Metal4 ;
        RECT 251.000 0.000 251.080 1.000 ;
    END
  END m_o[624]
  PIN m_o[625]
    DIRECTION OUTPUT ;
    USE SIGNAL ;
    PORT
      LAYER Metal4 ;
        RECT 251.400 0.000 251.480 1.000 ;
    END
  END m_o[625]
  PIN m_o[626]
    DIRECTION OUTPUT ;
    USE SIGNAL ;
    PORT
      LAYER Metal4 ;
        RECT 251.800 0.000 251.880 1.000 ;
    END
  END m_o[626]
  PIN m_o[627]
    DIRECTION OUTPUT ;
    USE SIGNAL ;
    PORT
      LAYER Metal4 ;
        RECT 252.200 0.000 252.280 1.000 ;
    END
  END m_o[627]
  PIN m_o[628]
    DIRECTION OUTPUT ;
    USE SIGNAL ;
    PORT
      LAYER Metal4 ;
        RECT 252.600 0.000 252.680 1.000 ;
    END
  END m_o[628]
  PIN m_o[629]
    DIRECTION OUTPUT ;
    USE SIGNAL ;
    PORT
      LAYER Metal4 ;
        RECT 253.000 0.000 253.080 1.000 ;
    END
  END m_o[629]
  PIN m_o[630]
    DIRECTION OUTPUT ;
    USE SIGNAL ;
    PORT
      LAYER Metal4 ;
        RECT 253.400 0.000 253.480 1.000 ;
    END
  END m_o[630]
  PIN m_o[631]
    DIRECTION OUTPUT ;
    USE SIGNAL ;
    PORT
      LAYER Metal4 ;
        RECT 253.800 0.000 253.880 1.000 ;
    END
  END m_o[631]
  PIN m_o[632]
    DIRECTION OUTPUT ;
    USE SIGNAL ;
    PORT
      LAYER Metal4 ;
        RECT 254.200 0.000 254.280 1.000 ;
    END
  END m_o[632]
  PIN m_o[633]
    DIRECTION OUTPUT ;
    USE SIGNAL ;
    PORT
      LAYER Metal4 ;
        RECT 254.600 0.000 254.680 1.000 ;
    END
  END m_o[633]
  PIN m_o[634]
    DIRECTION OUTPUT ;
    USE SIGNAL ;
    PORT
      LAYER Metal4 ;
        RECT 255.000 0.000 255.080 1.000 ;
    END
  END m_o[634]
  PIN m_o[635]
    DIRECTION OUTPUT ;
    USE SIGNAL ;
    PORT
      LAYER Metal4 ;
        RECT 255.400 0.000 255.480 1.000 ;
    END
  END m_o[635]
  PIN m_o[636]
    DIRECTION OUTPUT ;
    USE SIGNAL ;
    PORT
      LAYER Metal4 ;
        RECT 255.800 0.000 255.880 1.000 ;
    END
  END m_o[636]
  PIN m_o[637]
    DIRECTION OUTPUT ;
    USE SIGNAL ;
    PORT
      LAYER Metal4 ;
        RECT 256.200 0.000 256.280 1.000 ;
    END
  END m_o[637]
  PIN m_o[638]
    DIRECTION OUTPUT ;
    USE SIGNAL ;
    PORT
      LAYER Metal4 ;
        RECT 256.600 0.000 256.680 1.000 ;
    END
  END m_o[638]
  PIN m_o[639]
    DIRECTION OUTPUT ;
    USE SIGNAL ;
    PORT
      LAYER Metal4 ;
        RECT 257.000 0.000 257.080 1.000 ;
    END
  END m_o[639]
  PIN m_o[640]
    DIRECTION OUTPUT ;
    USE SIGNAL ;
    PORT
      LAYER Metal4 ;
        RECT 257.400 0.000 257.480 1.000 ;
    END
  END m_o[640]
  PIN m_o[641]
    DIRECTION OUTPUT ;
    USE SIGNAL ;
    PORT
      LAYER Metal4 ;
        RECT 257.800 0.000 257.880 1.000 ;
    END
  END m_o[641]
  PIN m_o[642]
    DIRECTION OUTPUT ;
    USE SIGNAL ;
    PORT
      LAYER Metal4 ;
        RECT 258.200 0.000 258.280 1.000 ;
    END
  END m_o[642]
  PIN m_o[643]
    DIRECTION OUTPUT ;
    USE SIGNAL ;
    PORT
      LAYER Metal4 ;
        RECT 258.600 0.000 258.680 1.000 ;
    END
  END m_o[643]
  PIN m_o[644]
    DIRECTION OUTPUT ;
    USE SIGNAL ;
    PORT
      LAYER Metal4 ;
        RECT 259.000 0.000 259.080 1.000 ;
    END
  END m_o[644]
  PIN m_o[645]
    DIRECTION OUTPUT ;
    USE SIGNAL ;
    PORT
      LAYER Metal4 ;
        RECT 259.400 0.000 259.480 1.000 ;
    END
  END m_o[645]
  PIN m_o[646]
    DIRECTION OUTPUT ;
    USE SIGNAL ;
    PORT
      LAYER Metal4 ;
        RECT 259.800 0.000 259.880 1.000 ;
    END
  END m_o[646]
  PIN m_o[647]
    DIRECTION OUTPUT ;
    USE SIGNAL ;
    PORT
      LAYER Metal4 ;
        RECT 260.200 0.000 260.280 1.000 ;
    END
  END m_o[647]
  PIN m_o[648]
    DIRECTION OUTPUT ;
    USE SIGNAL ;
    PORT
      LAYER Metal4 ;
        RECT 260.600 0.000 260.680 1.000 ;
    END
  END m_o[648]
  PIN m_o[649]
    DIRECTION OUTPUT ;
    USE SIGNAL ;
    PORT
      LAYER Metal4 ;
        RECT 261.000 0.000 261.080 1.000 ;
    END
  END m_o[649]
  PIN m_o[650]
    DIRECTION OUTPUT ;
    USE SIGNAL ;
    PORT
      LAYER Metal4 ;
        RECT 261.400 0.000 261.480 1.000 ;
    END
  END m_o[650]
  PIN m_o[651]
    DIRECTION OUTPUT ;
    USE SIGNAL ;
    PORT
      LAYER Metal4 ;
        RECT 261.800 0.000 261.880 1.000 ;
    END
  END m_o[651]
  PIN m_o[652]
    DIRECTION OUTPUT ;
    USE SIGNAL ;
    PORT
      LAYER Metal4 ;
        RECT 262.200 0.000 262.280 1.000 ;
    END
  END m_o[652]
  PIN m_o[653]
    DIRECTION OUTPUT ;
    USE SIGNAL ;
    PORT
      LAYER Metal4 ;
        RECT 262.600 0.000 262.680 1.000 ;
    END
  END m_o[653]
  PIN m_o[654]
    DIRECTION OUTPUT ;
    USE SIGNAL ;
    PORT
      LAYER Metal4 ;
        RECT 263.000 0.000 263.080 1.000 ;
    END
  END m_o[654]
  PIN m_o[655]
    DIRECTION OUTPUT ;
    USE SIGNAL ;
    PORT
      LAYER Metal4 ;
        RECT 263.400 0.000 263.480 1.000 ;
    END
  END m_o[655]
  PIN m_o[656]
    DIRECTION OUTPUT ;
    USE SIGNAL ;
    PORT
      LAYER Metal4 ;
        RECT 263.800 0.000 263.880 1.000 ;
    END
  END m_o[656]
  PIN m_o[657]
    DIRECTION OUTPUT ;
    USE SIGNAL ;
    PORT
      LAYER Metal4 ;
        RECT 264.200 0.000 264.280 1.000 ;
    END
  END m_o[657]
  PIN m_o[658]
    DIRECTION OUTPUT ;
    USE SIGNAL ;
    PORT
      LAYER Metal4 ;
        RECT 264.600 0.000 264.680 1.000 ;
    END
  END m_o[658]
  PIN m_o[659]
    DIRECTION OUTPUT ;
    USE SIGNAL ;
    PORT
      LAYER Metal4 ;
        RECT 265.000 0.000 265.080 1.000 ;
    END
  END m_o[659]
  PIN m_o[660]
    DIRECTION OUTPUT ;
    USE SIGNAL ;
    PORT
      LAYER Metal4 ;
        RECT 265.400 0.000 265.480 1.000 ;
    END
  END m_o[660]
  PIN m_o[661]
    DIRECTION OUTPUT ;
    USE SIGNAL ;
    PORT
      LAYER Metal4 ;
        RECT 265.800 0.000 265.880 1.000 ;
    END
  END m_o[661]
  PIN m_o[662]
    DIRECTION OUTPUT ;
    USE SIGNAL ;
    PORT
      LAYER Metal4 ;
        RECT 266.200 0.000 266.280 1.000 ;
    END
  END m_o[662]
  PIN m_o[663]
    DIRECTION OUTPUT ;
    USE SIGNAL ;
    PORT
      LAYER Metal4 ;
        RECT 266.600 0.000 266.680 1.000 ;
    END
  END m_o[663]
  PIN m_o[664]
    DIRECTION OUTPUT ;
    USE SIGNAL ;
    PORT
      LAYER Metal4 ;
        RECT 267.000 0.000 267.080 1.000 ;
    END
  END m_o[664]
  PIN m_o[665]
    DIRECTION OUTPUT ;
    USE SIGNAL ;
    PORT
      LAYER Metal4 ;
        RECT 267.400 0.000 267.480 1.000 ;
    END
  END m_o[665]
  PIN m_o[666]
    DIRECTION OUTPUT ;
    USE SIGNAL ;
    PORT
      LAYER Metal4 ;
        RECT 267.800 0.000 267.880 1.000 ;
    END
  END m_o[666]
  PIN m_o[667]
    DIRECTION OUTPUT ;
    USE SIGNAL ;
    PORT
      LAYER Metal4 ;
        RECT 268.200 0.000 268.280 1.000 ;
    END
  END m_o[667]
  PIN m_o[668]
    DIRECTION OUTPUT ;
    USE SIGNAL ;
    PORT
      LAYER Metal4 ;
        RECT 268.600 0.000 268.680 1.000 ;
    END
  END m_o[668]
  PIN m_o[669]
    DIRECTION OUTPUT ;
    USE SIGNAL ;
    PORT
      LAYER Metal4 ;
        RECT 269.000 0.000 269.080 1.000 ;
    END
  END m_o[669]
  PIN m_o[670]
    DIRECTION OUTPUT ;
    USE SIGNAL ;
    PORT
      LAYER Metal4 ;
        RECT 269.400 0.000 269.480 1.000 ;
    END
  END m_o[670]
  PIN m_o[671]
    DIRECTION OUTPUT ;
    USE SIGNAL ;
    PORT
      LAYER Metal4 ;
        RECT 269.800 0.000 269.880 1.000 ;
    END
  END m_o[671]
  PIN m_o[672]
    DIRECTION OUTPUT ;
    USE SIGNAL ;
    PORT
      LAYER Metal4 ;
        RECT 270.200 0.000 270.280 1.000 ;
    END
  END m_o[672]
  PIN m_o[673]
    DIRECTION OUTPUT ;
    USE SIGNAL ;
    PORT
      LAYER Metal4 ;
        RECT 270.600 0.000 270.680 1.000 ;
    END
  END m_o[673]
  PIN m_o[674]
    DIRECTION OUTPUT ;
    USE SIGNAL ;
    PORT
      LAYER Metal4 ;
        RECT 271.000 0.000 271.080 1.000 ;
    END
  END m_o[674]
  PIN m_o[675]
    DIRECTION OUTPUT ;
    USE SIGNAL ;
    PORT
      LAYER Metal4 ;
        RECT 271.400 0.000 271.480 1.000 ;
    END
  END m_o[675]
  PIN m_o[676]
    DIRECTION OUTPUT ;
    USE SIGNAL ;
    PORT
      LAYER Metal4 ;
        RECT 271.800 0.000 271.880 1.000 ;
    END
  END m_o[676]
  PIN m_o[677]
    DIRECTION OUTPUT ;
    USE SIGNAL ;
    PORT
      LAYER Metal4 ;
        RECT 272.200 0.000 272.280 1.000 ;
    END
  END m_o[677]
  PIN m_o[678]
    DIRECTION OUTPUT ;
    USE SIGNAL ;
    PORT
      LAYER Metal4 ;
        RECT 272.600 0.000 272.680 1.000 ;
    END
  END m_o[678]
  PIN m_o[679]
    DIRECTION OUTPUT ;
    USE SIGNAL ;
    PORT
      LAYER Metal4 ;
        RECT 273.000 0.000 273.080 1.000 ;
    END
  END m_o[679]
  PIN m_o[680]
    DIRECTION OUTPUT ;
    USE SIGNAL ;
    PORT
      LAYER Metal4 ;
        RECT 273.400 0.000 273.480 1.000 ;
    END
  END m_o[680]
  PIN m_o[681]
    DIRECTION OUTPUT ;
    USE SIGNAL ;
    PORT
      LAYER Metal4 ;
        RECT 273.800 0.000 273.880 1.000 ;
    END
  END m_o[681]
  PIN m_o[682]
    DIRECTION OUTPUT ;
    USE SIGNAL ;
    PORT
      LAYER Metal4 ;
        RECT 274.200 0.000 274.280 1.000 ;
    END
  END m_o[682]
  PIN m_o[683]
    DIRECTION OUTPUT ;
    USE SIGNAL ;
    PORT
      LAYER Metal4 ;
        RECT 274.600 0.000 274.680 1.000 ;
    END
  END m_o[683]
  PIN m_o[684]
    DIRECTION OUTPUT ;
    USE SIGNAL ;
    PORT
      LAYER Metal4 ;
        RECT 275.000 0.000 275.080 1.000 ;
    END
  END m_o[684]
  PIN m_o[685]
    DIRECTION OUTPUT ;
    USE SIGNAL ;
    PORT
      LAYER Metal4 ;
        RECT 275.400 0.000 275.480 1.000 ;
    END
  END m_o[685]
  PIN m_o[686]
    DIRECTION OUTPUT ;
    USE SIGNAL ;
    PORT
      LAYER Metal4 ;
        RECT 275.800 0.000 275.880 1.000 ;
    END
  END m_o[686]
  PIN m_o[687]
    DIRECTION OUTPUT ;
    USE SIGNAL ;
    PORT
      LAYER Metal4 ;
        RECT 276.200 0.000 276.280 1.000 ;
    END
  END m_o[687]
  PIN m_o[688]
    DIRECTION OUTPUT ;
    USE SIGNAL ;
    PORT
      LAYER Metal4 ;
        RECT 276.600 0.000 276.680 1.000 ;
    END
  END m_o[688]
  PIN m_o[689]
    DIRECTION OUTPUT ;
    USE SIGNAL ;
    PORT
      LAYER Metal4 ;
        RECT 277.000 0.000 277.080 1.000 ;
    END
  END m_o[689]
  PIN m_o[690]
    DIRECTION OUTPUT ;
    USE SIGNAL ;
    PORT
      LAYER Metal4 ;
        RECT 277.400 0.000 277.480 1.000 ;
    END
  END m_o[690]
  PIN m_o[691]
    DIRECTION OUTPUT ;
    USE SIGNAL ;
    PORT
      LAYER Metal4 ;
        RECT 277.800 0.000 277.880 1.000 ;
    END
  END m_o[691]
  PIN m_o[692]
    DIRECTION OUTPUT ;
    USE SIGNAL ;
    PORT
      LAYER Metal4 ;
        RECT 278.200 0.000 278.280 1.000 ;
    END
  END m_o[692]
  PIN m_o[693]
    DIRECTION OUTPUT ;
    USE SIGNAL ;
    PORT
      LAYER Metal4 ;
        RECT 278.600 0.000 278.680 1.000 ;
    END
  END m_o[693]
  PIN m_o[694]
    DIRECTION OUTPUT ;
    USE SIGNAL ;
    PORT
      LAYER Metal4 ;
        RECT 279.000 0.000 279.080 1.000 ;
    END
  END m_o[694]
  PIN m_o[695]
    DIRECTION OUTPUT ;
    USE SIGNAL ;
    PORT
      LAYER Metal4 ;
        RECT 279.400 0.000 279.480 1.000 ;
    END
  END m_o[695]
  PIN m_o[696]
    DIRECTION OUTPUT ;
    USE SIGNAL ;
    PORT
      LAYER Metal4 ;
        RECT 279.800 0.000 279.880 1.000 ;
    END
  END m_o[696]
  PIN m_o[697]
    DIRECTION OUTPUT ;
    USE SIGNAL ;
    PORT
      LAYER Metal4 ;
        RECT 280.200 0.000 280.280 1.000 ;
    END
  END m_o[697]
  PIN m_o[698]
    DIRECTION OUTPUT ;
    USE SIGNAL ;
    PORT
      LAYER Metal4 ;
        RECT 280.600 0.000 280.680 1.000 ;
    END
  END m_o[698]
  PIN m_o[699]
    DIRECTION OUTPUT ;
    USE SIGNAL ;
    PORT
      LAYER Metal4 ;
        RECT 281.000 0.000 281.080 1.000 ;
    END
  END m_o[699]
  PIN m_o[700]
    DIRECTION OUTPUT ;
    USE SIGNAL ;
    PORT
      LAYER Metal4 ;
        RECT 281.400 0.000 281.480 1.000 ;
    END
  END m_o[700]
  PIN m_o[701]
    DIRECTION OUTPUT ;
    USE SIGNAL ;
    PORT
      LAYER Metal4 ;
        RECT 281.800 0.000 281.880 1.000 ;
    END
  END m_o[701]
  PIN m_o[702]
    DIRECTION OUTPUT ;
    USE SIGNAL ;
    PORT
      LAYER Metal4 ;
        RECT 282.200 0.000 282.280 1.000 ;
    END
  END m_o[702]
  PIN m_o[703]
    DIRECTION OUTPUT ;
    USE SIGNAL ;
    PORT
      LAYER Metal4 ;
        RECT 282.600 0.000 282.680 1.000 ;
    END
  END m_o[703]
  PIN m_o[704]
    DIRECTION OUTPUT ;
    USE SIGNAL ;
    PORT
      LAYER Metal4 ;
        RECT 283.000 0.000 283.080 1.000 ;
    END
  END m_o[704]
  PIN m_o[705]
    DIRECTION OUTPUT ;
    USE SIGNAL ;
    PORT
      LAYER Metal4 ;
        RECT 283.400 0.000 283.480 1.000 ;
    END
  END m_o[705]
  PIN m_o[706]
    DIRECTION OUTPUT ;
    USE SIGNAL ;
    PORT
      LAYER Metal4 ;
        RECT 283.800 0.000 283.880 1.000 ;
    END
  END m_o[706]
  PIN m_o[707]
    DIRECTION OUTPUT ;
    USE SIGNAL ;
    PORT
      LAYER Metal4 ;
        RECT 284.200 0.000 284.280 1.000 ;
    END
  END m_o[707]
  PIN m_o[708]
    DIRECTION OUTPUT ;
    USE SIGNAL ;
    PORT
      LAYER Metal4 ;
        RECT 284.600 0.000 284.680 1.000 ;
    END
  END m_o[708]
  PIN m_o[709]
    DIRECTION OUTPUT ;
    USE SIGNAL ;
    PORT
      LAYER Metal4 ;
        RECT 285.000 0.000 285.080 1.000 ;
    END
  END m_o[709]
  PIN m_o[710]
    DIRECTION OUTPUT ;
    USE SIGNAL ;
    PORT
      LAYER Metal4 ;
        RECT 285.400 0.000 285.480 1.000 ;
    END
  END m_o[710]
  PIN m_o[711]
    DIRECTION OUTPUT ;
    USE SIGNAL ;
    PORT
      LAYER Metal4 ;
        RECT 285.800 0.000 285.880 1.000 ;
    END
  END m_o[711]
  PIN m_o[712]
    DIRECTION OUTPUT ;
    USE SIGNAL ;
    PORT
      LAYER Metal4 ;
        RECT 286.200 0.000 286.280 1.000 ;
    END
  END m_o[712]
  PIN m_o[713]
    DIRECTION OUTPUT ;
    USE SIGNAL ;
    PORT
      LAYER Metal4 ;
        RECT 286.600 0.000 286.680 1.000 ;
    END
  END m_o[713]
  PIN m_o[714]
    DIRECTION OUTPUT ;
    USE SIGNAL ;
    PORT
      LAYER Metal4 ;
        RECT 287.000 0.000 287.080 1.000 ;
    END
  END m_o[714]
  PIN m_o[715]
    DIRECTION OUTPUT ;
    USE SIGNAL ;
    PORT
      LAYER Metal4 ;
        RECT 287.400 0.000 287.480 1.000 ;
    END
  END m_o[715]
  PIN m_o[716]
    DIRECTION OUTPUT ;
    USE SIGNAL ;
    PORT
      LAYER Metal4 ;
        RECT 287.800 0.000 287.880 1.000 ;
    END
  END m_o[716]
  PIN m_o[717]
    DIRECTION OUTPUT ;
    USE SIGNAL ;
    PORT
      LAYER Metal4 ;
        RECT 288.200 0.000 288.280 1.000 ;
    END
  END m_o[717]
  PIN m_o[718]
    DIRECTION OUTPUT ;
    USE SIGNAL ;
    PORT
      LAYER Metal4 ;
        RECT 288.600 0.000 288.680 1.000 ;
    END
  END m_o[718]
  PIN m_o[719]
    DIRECTION OUTPUT ;
    USE SIGNAL ;
    PORT
      LAYER Metal4 ;
        RECT 289.000 0.000 289.080 1.000 ;
    END
  END m_o[719]
  PIN m_o[720]
    DIRECTION OUTPUT ;
    USE SIGNAL ;
    PORT
      LAYER Metal4 ;
        RECT 289.400 0.000 289.480 1.000 ;
    END
  END m_o[720]
  PIN m_o[721]
    DIRECTION OUTPUT ;
    USE SIGNAL ;
    PORT
      LAYER Metal4 ;
        RECT 289.800 0.000 289.880 1.000 ;
    END
  END m_o[721]
  PIN m_o[722]
    DIRECTION OUTPUT ;
    USE SIGNAL ;
    PORT
      LAYER Metal4 ;
        RECT 290.200 0.000 290.280 1.000 ;
    END
  END m_o[722]
  PIN m_o[723]
    DIRECTION OUTPUT ;
    USE SIGNAL ;
    PORT
      LAYER Metal4 ;
        RECT 290.600 0.000 290.680 1.000 ;
    END
  END m_o[723]
  PIN m_o[724]
    DIRECTION OUTPUT ;
    USE SIGNAL ;
    PORT
      LAYER Metal4 ;
        RECT 291.000 0.000 291.080 1.000 ;
    END
  END m_o[724]
  PIN m_o[725]
    DIRECTION OUTPUT ;
    USE SIGNAL ;
    PORT
      LAYER Metal4 ;
        RECT 291.400 0.000 291.480 1.000 ;
    END
  END m_o[725]
  PIN m_o[726]
    DIRECTION OUTPUT ;
    USE SIGNAL ;
    PORT
      LAYER Metal4 ;
        RECT 291.800 0.000 291.880 1.000 ;
    END
  END m_o[726]
  PIN m_o[727]
    DIRECTION OUTPUT ;
    USE SIGNAL ;
    PORT
      LAYER Metal4 ;
        RECT 292.200 0.000 292.280 1.000 ;
    END
  END m_o[727]
  PIN m_o[728]
    DIRECTION OUTPUT ;
    USE SIGNAL ;
    PORT
      LAYER Metal4 ;
        RECT 292.600 0.000 292.680 1.000 ;
    END
  END m_o[728]
  PIN m_o[729]
    DIRECTION OUTPUT ;
    USE SIGNAL ;
    PORT
      LAYER Metal4 ;
        RECT 293.000 0.000 293.080 1.000 ;
    END
  END m_o[729]
  PIN m_o[730]
    DIRECTION OUTPUT ;
    USE SIGNAL ;
    PORT
      LAYER Metal4 ;
        RECT 293.400 0.000 293.480 1.000 ;
    END
  END m_o[730]
  PIN m_o[731]
    DIRECTION OUTPUT ;
    USE SIGNAL ;
    PORT
      LAYER Metal4 ;
        RECT 293.800 0.000 293.880 1.000 ;
    END
  END m_o[731]
  PIN m_o[732]
    DIRECTION OUTPUT ;
    USE SIGNAL ;
    PORT
      LAYER Metal4 ;
        RECT 294.200 0.000 294.280 1.000 ;
    END
  END m_o[732]
  PIN m_o[733]
    DIRECTION OUTPUT ;
    USE SIGNAL ;
    PORT
      LAYER Metal4 ;
        RECT 294.600 0.000 294.680 1.000 ;
    END
  END m_o[733]
  PIN m_o[734]
    DIRECTION OUTPUT ;
    USE SIGNAL ;
    PORT
      LAYER Metal4 ;
        RECT 295.000 0.000 295.080 1.000 ;
    END
  END m_o[734]
  PIN m_o[735]
    DIRECTION OUTPUT ;
    USE SIGNAL ;
    PORT
      LAYER Metal4 ;
        RECT 295.400 0.000 295.480 1.000 ;
    END
  END m_o[735]
  PIN m_o[736]
    DIRECTION OUTPUT ;
    USE SIGNAL ;
    PORT
      LAYER Metal4 ;
        RECT 295.800 0.000 295.880 1.000 ;
    END
  END m_o[736]
  PIN m_o[737]
    DIRECTION OUTPUT ;
    USE SIGNAL ;
    PORT
      LAYER Metal4 ;
        RECT 296.200 0.000 296.280 1.000 ;
    END
  END m_o[737]
  PIN m_o[738]
    DIRECTION OUTPUT ;
    USE SIGNAL ;
    PORT
      LAYER Metal4 ;
        RECT 296.600 0.000 296.680 1.000 ;
    END
  END m_o[738]
  PIN m_o[739]
    DIRECTION OUTPUT ;
    USE SIGNAL ;
    PORT
      LAYER Metal4 ;
        RECT 297.000 0.000 297.080 1.000 ;
    END
  END m_o[739]
  PIN m_o[740]
    DIRECTION OUTPUT ;
    USE SIGNAL ;
    PORT
      LAYER Metal4 ;
        RECT 297.400 0.000 297.480 1.000 ;
    END
  END m_o[740]
  PIN m_o[741]
    DIRECTION OUTPUT ;
    USE SIGNAL ;
    PORT
      LAYER Metal4 ;
        RECT 297.800 0.000 297.880 1.000 ;
    END
  END m_o[741]
  PIN m_o[742]
    DIRECTION OUTPUT ;
    USE SIGNAL ;
    PORT
      LAYER Metal4 ;
        RECT 298.200 0.000 298.280 1.000 ;
    END
  END m_o[742]
  PIN m_o[743]
    DIRECTION OUTPUT ;
    USE SIGNAL ;
    PORT
      LAYER Metal4 ;
        RECT 298.600 0.000 298.680 1.000 ;
    END
  END m_o[743]
  PIN m_o[744]
    DIRECTION OUTPUT ;
    USE SIGNAL ;
    PORT
      LAYER Metal4 ;
        RECT 299.000 0.000 299.080 1.000 ;
    END
  END m_o[744]
  PIN m_o[745]
    DIRECTION OUTPUT ;
    USE SIGNAL ;
    PORT
      LAYER Metal4 ;
        RECT 299.400 0.000 299.480 1.000 ;
    END
  END m_o[745]
  PIN m_o[746]
    DIRECTION OUTPUT ;
    USE SIGNAL ;
    PORT
      LAYER Metal4 ;
        RECT 299.800 0.000 299.880 1.000 ;
    END
  END m_o[746]
  PIN m_o[747]
    DIRECTION OUTPUT ;
    USE SIGNAL ;
    PORT
      LAYER Metal4 ;
        RECT 300.200 0.000 300.280 1.000 ;
    END
  END m_o[747]
  PIN m_o[748]
    DIRECTION OUTPUT ;
    USE SIGNAL ;
    PORT
      LAYER Metal4 ;
        RECT 300.600 0.000 300.680 1.000 ;
    END
  END m_o[748]
  PIN m_o[749]
    DIRECTION OUTPUT ;
    USE SIGNAL ;
    PORT
      LAYER Metal4 ;
        RECT 301.000 0.000 301.080 1.000 ;
    END
  END m_o[749]
  PIN m_o[750]
    DIRECTION OUTPUT ;
    USE SIGNAL ;
    PORT
      LAYER Metal4 ;
        RECT 301.400 0.000 301.480 1.000 ;
    END
  END m_o[750]
  PIN m_o[751]
    DIRECTION OUTPUT ;
    USE SIGNAL ;
    PORT
      LAYER Metal4 ;
        RECT 301.800 0.000 301.880 1.000 ;
    END
  END m_o[751]
  PIN m_o[752]
    DIRECTION OUTPUT ;
    USE SIGNAL ;
    PORT
      LAYER Metal4 ;
        RECT 302.200 0.000 302.280 1.000 ;
    END
  END m_o[752]
  PIN m_o[753]
    DIRECTION OUTPUT ;
    USE SIGNAL ;
    PORT
      LAYER Metal4 ;
        RECT 302.600 0.000 302.680 1.000 ;
    END
  END m_o[753]
  PIN m_o[754]
    DIRECTION OUTPUT ;
    USE SIGNAL ;
    PORT
      LAYER Metal4 ;
        RECT 303.000 0.000 303.080 1.000 ;
    END
  END m_o[754]
  PIN m_o[755]
    DIRECTION OUTPUT ;
    USE SIGNAL ;
    PORT
      LAYER Metal4 ;
        RECT 303.400 0.000 303.480 1.000 ;
    END
  END m_o[755]
  PIN m_o[756]
    DIRECTION OUTPUT ;
    USE SIGNAL ;
    PORT
      LAYER Metal4 ;
        RECT 303.800 0.000 303.880 1.000 ;
    END
  END m_o[756]
  PIN m_o[757]
    DIRECTION OUTPUT ;
    USE SIGNAL ;
    PORT
      LAYER Metal4 ;
        RECT 304.200 0.000 304.280 1.000 ;
    END
  END m_o[757]
  PIN m_o[758]
    DIRECTION OUTPUT ;
    USE SIGNAL ;
    PORT
      LAYER Metal4 ;
        RECT 304.600 0.000 304.680 1.000 ;
    END
  END m_o[758]
  PIN m_o[759]
    DIRECTION OUTPUT ;
    USE SIGNAL ;
    PORT
      LAYER Metal4 ;
        RECT 305.000 0.000 305.080 1.000 ;
    END
  END m_o[759]
  PIN m_o[760]
    DIRECTION OUTPUT ;
    USE SIGNAL ;
    PORT
      LAYER Metal4 ;
        RECT 305.400 0.000 305.480 1.000 ;
    END
  END m_o[760]
  PIN m_o[761]
    DIRECTION OUTPUT ;
    USE SIGNAL ;
    PORT
      LAYER Metal4 ;
        RECT 305.800 0.000 305.880 1.000 ;
    END
  END m_o[761]
  PIN m_o[762]
    DIRECTION OUTPUT ;
    USE SIGNAL ;
    PORT
      LAYER Metal4 ;
        RECT 306.200 0.000 306.280 1.000 ;
    END
  END m_o[762]
  PIN m_o[763]
    DIRECTION OUTPUT ;
    USE SIGNAL ;
    PORT
      LAYER Metal4 ;
        RECT 306.600 0.000 306.680 1.000 ;
    END
  END m_o[763]
  PIN m_o[764]
    DIRECTION OUTPUT ;
    USE SIGNAL ;
    PORT
      LAYER Metal4 ;
        RECT 307.000 0.000 307.080 1.000 ;
    END
  END m_o[764]
  PIN m_o[765]
    DIRECTION OUTPUT ;
    USE SIGNAL ;
    PORT
      LAYER Metal4 ;
        RECT 307.400 0.000 307.480 1.000 ;
    END
  END m_o[765]
  PIN m_o[766]
    DIRECTION OUTPUT ;
    USE SIGNAL ;
    PORT
      LAYER Metal4 ;
        RECT 307.800 0.000 307.880 1.000 ;
    END
  END m_o[766]
  PIN m_o[767]
    DIRECTION OUTPUT ;
    USE SIGNAL ;
    PORT
      LAYER Metal4 ;
        RECT 308.200 0.000 308.280 1.000 ;
    END
  END m_o[767]
  PIN m_o[768]
    DIRECTION OUTPUT ;
    USE SIGNAL ;
    PORT
      LAYER Metal4 ;
        RECT 308.600 0.000 308.680 1.000 ;
    END
  END m_o[768]
  PIN m_o[769]
    DIRECTION OUTPUT ;
    USE SIGNAL ;
    PORT
      LAYER Metal4 ;
        RECT 309.000 0.000 309.080 1.000 ;
    END
  END m_o[769]
  PIN m_o[770]
    DIRECTION OUTPUT ;
    USE SIGNAL ;
    PORT
      LAYER Metal4 ;
        RECT 309.400 0.000 309.480 1.000 ;
    END
  END m_o[770]
  PIN m_o[771]
    DIRECTION OUTPUT ;
    USE SIGNAL ;
    PORT
      LAYER Metal4 ;
        RECT 309.800 0.000 309.880 1.000 ;
    END
  END m_o[771]
  PIN m_o[772]
    DIRECTION OUTPUT ;
    USE SIGNAL ;
    PORT
      LAYER Metal4 ;
        RECT 310.200 0.000 310.280 1.000 ;
    END
  END m_o[772]
  PIN m_o[773]
    DIRECTION OUTPUT ;
    USE SIGNAL ;
    PORT
      LAYER Metal4 ;
        RECT 310.600 0.000 310.680 1.000 ;
    END
  END m_o[773]
  PIN m_o[774]
    DIRECTION OUTPUT ;
    USE SIGNAL ;
    PORT
      LAYER Metal4 ;
        RECT 311.000 0.000 311.080 1.000 ;
    END
  END m_o[774]
  PIN m_o[775]
    DIRECTION OUTPUT ;
    USE SIGNAL ;
    PORT
      LAYER Metal4 ;
        RECT 311.400 0.000 311.480 1.000 ;
    END
  END m_o[775]
  PIN m_o[776]
    DIRECTION OUTPUT ;
    USE SIGNAL ;
    PORT
      LAYER Metal4 ;
        RECT 311.800 0.000 311.880 1.000 ;
    END
  END m_o[776]
  PIN m_o[777]
    DIRECTION OUTPUT ;
    USE SIGNAL ;
    PORT
      LAYER Metal4 ;
        RECT 312.200 0.000 312.280 1.000 ;
    END
  END m_o[777]
  PIN m_o[778]
    DIRECTION OUTPUT ;
    USE SIGNAL ;
    PORT
      LAYER Metal4 ;
        RECT 312.600 0.000 312.680 1.000 ;
    END
  END m_o[778]
  PIN m_o[779]
    DIRECTION OUTPUT ;
    USE SIGNAL ;
    PORT
      LAYER Metal4 ;
        RECT 313.000 0.000 313.080 1.000 ;
    END
  END m_o[779]
  PIN m_o[780]
    DIRECTION OUTPUT ;
    USE SIGNAL ;
    PORT
      LAYER Metal4 ;
        RECT 313.400 0.000 313.480 1.000 ;
    END
  END m_o[780]
  PIN m_o[781]
    DIRECTION OUTPUT ;
    USE SIGNAL ;
    PORT
      LAYER Metal4 ;
        RECT 313.800 0.000 313.880 1.000 ;
    END
  END m_o[781]
  PIN m_o[782]
    DIRECTION OUTPUT ;
    USE SIGNAL ;
    PORT
      LAYER Metal4 ;
        RECT 314.200 0.000 314.280 1.000 ;
    END
  END m_o[782]
  PIN m_o[783]
    DIRECTION OUTPUT ;
    USE SIGNAL ;
    PORT
      LAYER Metal4 ;
        RECT 314.600 0.000 314.680 1.000 ;
    END
  END m_o[783]
  PIN m_o[784]
    DIRECTION OUTPUT ;
    USE SIGNAL ;
    PORT
      LAYER Metal4 ;
        RECT 315.000 0.000 315.080 1.000 ;
    END
  END m_o[784]
  PIN m_o[785]
    DIRECTION OUTPUT ;
    USE SIGNAL ;
    PORT
      LAYER Metal4 ;
        RECT 315.400 0.000 315.480 1.000 ;
    END
  END m_o[785]
  PIN m_o[786]
    DIRECTION OUTPUT ;
    USE SIGNAL ;
    PORT
      LAYER Metal4 ;
        RECT 315.800 0.000 315.880 1.000 ;
    END
  END m_o[786]
  PIN m_o[787]
    DIRECTION OUTPUT ;
    USE SIGNAL ;
    PORT
      LAYER Metal4 ;
        RECT 316.200 0.000 316.280 1.000 ;
    END
  END m_o[787]
  PIN m_o[788]
    DIRECTION OUTPUT ;
    USE SIGNAL ;
    PORT
      LAYER Metal4 ;
        RECT 316.600 0.000 316.680 1.000 ;
    END
  END m_o[788]
  PIN m_o[789]
    DIRECTION OUTPUT ;
    USE SIGNAL ;
    PORT
      LAYER Metal4 ;
        RECT 317.000 0.000 317.080 1.000 ;
    END
  END m_o[789]
  PIN m_o[790]
    DIRECTION OUTPUT ;
    USE SIGNAL ;
    PORT
      LAYER Metal4 ;
        RECT 317.400 0.000 317.480 1.000 ;
    END
  END m_o[790]
  PIN m_o[791]
    DIRECTION OUTPUT ;
    USE SIGNAL ;
    PORT
      LAYER Metal4 ;
        RECT 317.800 0.000 317.880 1.000 ;
    END
  END m_o[791]
  PIN m_o[792]
    DIRECTION OUTPUT ;
    USE SIGNAL ;
    PORT
      LAYER Metal4 ;
        RECT 318.200 0.000 318.280 1.000 ;
    END
  END m_o[792]
  PIN m_o[793]
    DIRECTION OUTPUT ;
    USE SIGNAL ;
    PORT
      LAYER Metal4 ;
        RECT 318.600 0.000 318.680 1.000 ;
    END
  END m_o[793]
  PIN m_o[794]
    DIRECTION OUTPUT ;
    USE SIGNAL ;
    PORT
      LAYER Metal4 ;
        RECT 319.000 0.000 319.080 1.000 ;
    END
  END m_o[794]
  PIN m_o[795]
    DIRECTION OUTPUT ;
    USE SIGNAL ;
    PORT
      LAYER Metal4 ;
        RECT 319.400 0.000 319.480 1.000 ;
    END
  END m_o[795]
  PIN m_o[796]
    DIRECTION OUTPUT ;
    USE SIGNAL ;
    PORT
      LAYER Metal4 ;
        RECT 319.800 0.000 319.880 1.000 ;
    END
  END m_o[796]
  PIN m_o[797]
    DIRECTION OUTPUT ;
    USE SIGNAL ;
    PORT
      LAYER Metal4 ;
        RECT 320.200 0.000 320.280 1.000 ;
    END
  END m_o[797]
  PIN m_o[798]
    DIRECTION OUTPUT ;
    USE SIGNAL ;
    PORT
      LAYER Metal4 ;
        RECT 320.600 0.000 320.680 1.000 ;
    END
  END m_o[798]
  PIN m_o[799]
    DIRECTION OUTPUT ;
    USE SIGNAL ;
    PORT
      LAYER Metal4 ;
        RECT 321.000 0.000 321.080 1.000 ;
    END
  END m_o[799]
  PIN m_o[800]
    DIRECTION OUTPUT ;
    USE SIGNAL ;
    PORT
      LAYER Metal4 ;
        RECT 321.400 0.000 321.480 1.000 ;
    END
  END m_o[800]
  PIN m_o[801]
    DIRECTION OUTPUT ;
    USE SIGNAL ;
    PORT
      LAYER Metal4 ;
        RECT 321.800 0.000 321.880 1.000 ;
    END
  END m_o[801]
  PIN m_o[802]
    DIRECTION OUTPUT ;
    USE SIGNAL ;
    PORT
      LAYER Metal4 ;
        RECT 322.200 0.000 322.280 1.000 ;
    END
  END m_o[802]
  PIN m_o[803]
    DIRECTION OUTPUT ;
    USE SIGNAL ;
    PORT
      LAYER Metal4 ;
        RECT 322.600 0.000 322.680 1.000 ;
    END
  END m_o[803]
  PIN m_o[804]
    DIRECTION OUTPUT ;
    USE SIGNAL ;
    PORT
      LAYER Metal4 ;
        RECT 323.000 0.000 323.080 1.000 ;
    END
  END m_o[804]
  PIN m_o[805]
    DIRECTION OUTPUT ;
    USE SIGNAL ;
    PORT
      LAYER Metal4 ;
        RECT 323.400 0.000 323.480 1.000 ;
    END
  END m_o[805]
  PIN m_o[806]
    DIRECTION OUTPUT ;
    USE SIGNAL ;
    PORT
      LAYER Metal4 ;
        RECT 323.800 0.000 323.880 1.000 ;
    END
  END m_o[806]
  PIN m_o[807]
    DIRECTION OUTPUT ;
    USE SIGNAL ;
    PORT
      LAYER Metal4 ;
        RECT 324.200 0.000 324.280 1.000 ;
    END
  END m_o[807]
  PIN m_o[808]
    DIRECTION OUTPUT ;
    USE SIGNAL ;
    PORT
      LAYER Metal4 ;
        RECT 324.600 0.000 324.680 1.000 ;
    END
  END m_o[808]
  PIN m_o[809]
    DIRECTION OUTPUT ;
    USE SIGNAL ;
    PORT
      LAYER Metal4 ;
        RECT 325.000 0.000 325.080 1.000 ;
    END
  END m_o[809]
  PIN m_o[810]
    DIRECTION OUTPUT ;
    USE SIGNAL ;
    PORT
      LAYER Metal4 ;
        RECT 325.400 0.000 325.480 1.000 ;
    END
  END m_o[810]
  PIN m_o[811]
    DIRECTION OUTPUT ;
    USE SIGNAL ;
    PORT
      LAYER Metal4 ;
        RECT 325.800 0.000 325.880 1.000 ;
    END
  END m_o[811]
  PIN m_o[812]
    DIRECTION OUTPUT ;
    USE SIGNAL ;
    PORT
      LAYER Metal4 ;
        RECT 326.200 0.000 326.280 1.000 ;
    END
  END m_o[812]
  PIN m_o[813]
    DIRECTION OUTPUT ;
    USE SIGNAL ;
    PORT
      LAYER Metal4 ;
        RECT 326.600 0.000 326.680 1.000 ;
    END
  END m_o[813]
  PIN m_o[814]
    DIRECTION OUTPUT ;
    USE SIGNAL ;
    PORT
      LAYER Metal4 ;
        RECT 327.000 0.000 327.080 1.000 ;
    END
  END m_o[814]
  PIN m_o[815]
    DIRECTION OUTPUT ;
    USE SIGNAL ;
    PORT
      LAYER Metal4 ;
        RECT 327.400 0.000 327.480 1.000 ;
    END
  END m_o[815]
  PIN m_o[816]
    DIRECTION OUTPUT ;
    USE SIGNAL ;
    PORT
      LAYER Metal4 ;
        RECT 327.800 0.000 327.880 1.000 ;
    END
  END m_o[816]
  PIN m_o[817]
    DIRECTION OUTPUT ;
    USE SIGNAL ;
    PORT
      LAYER Metal4 ;
        RECT 328.200 0.000 328.280 1.000 ;
    END
  END m_o[817]
  PIN m_o[818]
    DIRECTION OUTPUT ;
    USE SIGNAL ;
    PORT
      LAYER Metal4 ;
        RECT 328.600 0.000 328.680 1.000 ;
    END
  END m_o[818]
  PIN m_o[819]
    DIRECTION OUTPUT ;
    USE SIGNAL ;
    PORT
      LAYER Metal4 ;
        RECT 329.000 0.000 329.080 1.000 ;
    END
  END m_o[819]
  PIN m_o[820]
    DIRECTION OUTPUT ;
    USE SIGNAL ;
    PORT
      LAYER Metal4 ;
        RECT 329.400 0.000 329.480 1.000 ;
    END
  END m_o[820]
  PIN m_o[821]
    DIRECTION OUTPUT ;
    USE SIGNAL ;
    PORT
      LAYER Metal4 ;
        RECT 329.800 0.000 329.880 1.000 ;
    END
  END m_o[821]
  PIN m_o[822]
    DIRECTION OUTPUT ;
    USE SIGNAL ;
    PORT
      LAYER Metal4 ;
        RECT 330.200 0.000 330.280 1.000 ;
    END
  END m_o[822]
  PIN m_o[823]
    DIRECTION OUTPUT ;
    USE SIGNAL ;
    PORT
      LAYER Metal4 ;
        RECT 330.600 0.000 330.680 1.000 ;
    END
  END m_o[823]
  PIN m_o[824]
    DIRECTION OUTPUT ;
    USE SIGNAL ;
    PORT
      LAYER Metal4 ;
        RECT 331.000 0.000 331.080 1.000 ;
    END
  END m_o[824]
  PIN m_o[825]
    DIRECTION OUTPUT ;
    USE SIGNAL ;
    PORT
      LAYER Metal4 ;
        RECT 331.400 0.000 331.480 1.000 ;
    END
  END m_o[825]
  PIN m_o[826]
    DIRECTION OUTPUT ;
    USE SIGNAL ;
    PORT
      LAYER Metal4 ;
        RECT 331.800 0.000 331.880 1.000 ;
    END
  END m_o[826]
  PIN m_o[827]
    DIRECTION OUTPUT ;
    USE SIGNAL ;
    PORT
      LAYER Metal4 ;
        RECT 332.200 0.000 332.280 1.000 ;
    END
  END m_o[827]
  PIN m_o[828]
    DIRECTION OUTPUT ;
    USE SIGNAL ;
    PORT
      LAYER Metal4 ;
        RECT 332.600 0.000 332.680 1.000 ;
    END
  END m_o[828]
  PIN m_o[829]
    DIRECTION OUTPUT ;
    USE SIGNAL ;
    PORT
      LAYER Metal4 ;
        RECT 333.000 0.000 333.080 1.000 ;
    END
  END m_o[829]
  PIN m_o[830]
    DIRECTION OUTPUT ;
    USE SIGNAL ;
    PORT
      LAYER Metal4 ;
        RECT 333.400 0.000 333.480 1.000 ;
    END
  END m_o[830]
  PIN m_o[831]
    DIRECTION OUTPUT ;
    USE SIGNAL ;
    PORT
      LAYER Metal4 ;
        RECT 333.800 0.000 333.880 1.000 ;
    END
  END m_o[831]
  PIN m_o[832]
    DIRECTION OUTPUT ;
    USE SIGNAL ;
    PORT
      LAYER Metal4 ;
        RECT 334.200 0.000 334.280 1.000 ;
    END
  END m_o[832]
  PIN m_o[833]
    DIRECTION OUTPUT ;
    USE SIGNAL ;
    PORT
      LAYER Metal4 ;
        RECT 334.600 0.000 334.680 1.000 ;
    END
  END m_o[833]
  PIN m_o[834]
    DIRECTION OUTPUT ;
    USE SIGNAL ;
    PORT
      LAYER Metal4 ;
        RECT 335.000 0.000 335.080 1.000 ;
    END
  END m_o[834]
  PIN m_o[835]
    DIRECTION OUTPUT ;
    USE SIGNAL ;
    PORT
      LAYER Metal4 ;
        RECT 335.400 0.000 335.480 1.000 ;
    END
  END m_o[835]
  PIN m_o[836]
    DIRECTION OUTPUT ;
    USE SIGNAL ;
    PORT
      LAYER Metal4 ;
        RECT 335.800 0.000 335.880 1.000 ;
    END
  END m_o[836]
  PIN m_o[837]
    DIRECTION OUTPUT ;
    USE SIGNAL ;
    PORT
      LAYER Metal4 ;
        RECT 336.200 0.000 336.280 1.000 ;
    END
  END m_o[837]
  PIN m_o[838]
    DIRECTION OUTPUT ;
    USE SIGNAL ;
    PORT
      LAYER Metal4 ;
        RECT 336.600 0.000 336.680 1.000 ;
    END
  END m_o[838]
  PIN m_o[839]
    DIRECTION OUTPUT ;
    USE SIGNAL ;
    PORT
      LAYER Metal4 ;
        RECT 337.000 0.000 337.080 1.000 ;
    END
  END m_o[839]
  PIN m_o[840]
    DIRECTION OUTPUT ;
    USE SIGNAL ;
    PORT
      LAYER Metal4 ;
        RECT 337.400 0.000 337.480 1.000 ;
    END
  END m_o[840]
  PIN m_o[841]
    DIRECTION OUTPUT ;
    USE SIGNAL ;
    PORT
      LAYER Metal4 ;
        RECT 337.800 0.000 337.880 1.000 ;
    END
  END m_o[841]
  PIN m_o[842]
    DIRECTION OUTPUT ;
    USE SIGNAL ;
    PORT
      LAYER Metal4 ;
        RECT 338.200 0.000 338.280 1.000 ;
    END
  END m_o[842]
  PIN m_o[843]
    DIRECTION OUTPUT ;
    USE SIGNAL ;
    PORT
      LAYER Metal4 ;
        RECT 338.600 0.000 338.680 1.000 ;
    END
  END m_o[843]
  PIN m_o[844]
    DIRECTION OUTPUT ;
    USE SIGNAL ;
    PORT
      LAYER Metal4 ;
        RECT 339.000 0.000 339.080 1.000 ;
    END
  END m_o[844]
  PIN m_o[845]
    DIRECTION OUTPUT ;
    USE SIGNAL ;
    PORT
      LAYER Metal4 ;
        RECT 339.400 0.000 339.480 1.000 ;
    END
  END m_o[845]
  PIN m_o[846]
    DIRECTION OUTPUT ;
    USE SIGNAL ;
    PORT
      LAYER Metal4 ;
        RECT 339.800 0.000 339.880 1.000 ;
    END
  END m_o[846]
  PIN m_o[847]
    DIRECTION OUTPUT ;
    USE SIGNAL ;
    PORT
      LAYER Metal4 ;
        RECT 340.200 0.000 340.280 1.000 ;
    END
  END m_o[847]
  PIN m_o[848]
    DIRECTION OUTPUT ;
    USE SIGNAL ;
    PORT
      LAYER Metal4 ;
        RECT 340.600 0.000 340.680 1.000 ;
    END
  END m_o[848]
  PIN m_o[849]
    DIRECTION OUTPUT ;
    USE SIGNAL ;
    PORT
      LAYER Metal4 ;
        RECT 341.000 0.000 341.080 1.000 ;
    END
  END m_o[849]
  PIN m_o[850]
    DIRECTION OUTPUT ;
    USE SIGNAL ;
    PORT
      LAYER Metal4 ;
        RECT 341.400 0.000 341.480 1.000 ;
    END
  END m_o[850]
  PIN m_o[851]
    DIRECTION OUTPUT ;
    USE SIGNAL ;
    PORT
      LAYER Metal4 ;
        RECT 341.800 0.000 341.880 1.000 ;
    END
  END m_o[851]
  PIN m_o[852]
    DIRECTION OUTPUT ;
    USE SIGNAL ;
    PORT
      LAYER Metal4 ;
        RECT 342.200 0.000 342.280 1.000 ;
    END
  END m_o[852]
  PIN m_o[853]
    DIRECTION OUTPUT ;
    USE SIGNAL ;
    PORT
      LAYER Metal4 ;
        RECT 342.600 0.000 342.680 1.000 ;
    END
  END m_o[853]
  PIN m_o[854]
    DIRECTION OUTPUT ;
    USE SIGNAL ;
    PORT
      LAYER Metal4 ;
        RECT 343.000 0.000 343.080 1.000 ;
    END
  END m_o[854]
  PIN m_o[855]
    DIRECTION OUTPUT ;
    USE SIGNAL ;
    PORT
      LAYER Metal4 ;
        RECT 343.400 0.000 343.480 1.000 ;
    END
  END m_o[855]
  PIN m_o[856]
    DIRECTION OUTPUT ;
    USE SIGNAL ;
    PORT
      LAYER Metal4 ;
        RECT 343.800 0.000 343.880 1.000 ;
    END
  END m_o[856]
  PIN m_o[857]
    DIRECTION OUTPUT ;
    USE SIGNAL ;
    PORT
      LAYER Metal4 ;
        RECT 344.200 0.000 344.280 1.000 ;
    END
  END m_o[857]
  PIN m_o[858]
    DIRECTION OUTPUT ;
    USE SIGNAL ;
    PORT
      LAYER Metal4 ;
        RECT 344.600 0.000 344.680 1.000 ;
    END
  END m_o[858]
  PIN m_o[859]
    DIRECTION OUTPUT ;
    USE SIGNAL ;
    PORT
      LAYER Metal4 ;
        RECT 345.000 0.000 345.080 1.000 ;
    END
  END m_o[859]
  PIN m_o[860]
    DIRECTION OUTPUT ;
    USE SIGNAL ;
    PORT
      LAYER Metal4 ;
        RECT 345.400 0.000 345.480 1.000 ;
    END
  END m_o[860]
  PIN m_o[861]
    DIRECTION OUTPUT ;
    USE SIGNAL ;
    PORT
      LAYER Metal4 ;
        RECT 345.800 0.000 345.880 1.000 ;
    END
  END m_o[861]
  PIN m_o[862]
    DIRECTION OUTPUT ;
    USE SIGNAL ;
    PORT
      LAYER Metal4 ;
        RECT 346.200 0.000 346.280 1.000 ;
    END
  END m_o[862]
  PIN m_o[863]
    DIRECTION OUTPUT ;
    USE SIGNAL ;
    PORT
      LAYER Metal4 ;
        RECT 346.600 0.000 346.680 1.000 ;
    END
  END m_o[863]
  PIN m_o[864]
    DIRECTION OUTPUT ;
    USE SIGNAL ;
    PORT
      LAYER Metal4 ;
        RECT 347.000 0.000 347.080 1.000 ;
    END
  END m_o[864]
  PIN m_o[865]
    DIRECTION OUTPUT ;
    USE SIGNAL ;
    PORT
      LAYER Metal4 ;
        RECT 347.400 0.000 347.480 1.000 ;
    END
  END m_o[865]
  PIN m_o[866]
    DIRECTION OUTPUT ;
    USE SIGNAL ;
    PORT
      LAYER Metal4 ;
        RECT 347.800 0.000 347.880 1.000 ;
    END
  END m_o[866]
  PIN m_o[867]
    DIRECTION OUTPUT ;
    USE SIGNAL ;
    PORT
      LAYER Metal4 ;
        RECT 348.200 0.000 348.280 1.000 ;
    END
  END m_o[867]
  PIN m_o[868]
    DIRECTION OUTPUT ;
    USE SIGNAL ;
    PORT
      LAYER Metal4 ;
        RECT 348.600 0.000 348.680 1.000 ;
    END
  END m_o[868]
  PIN m_o[869]
    DIRECTION OUTPUT ;
    USE SIGNAL ;
    PORT
      LAYER Metal4 ;
        RECT 349.000 0.000 349.080 1.000 ;
    END
  END m_o[869]
  PIN m_o[870]
    DIRECTION OUTPUT ;
    USE SIGNAL ;
    PORT
      LAYER Metal4 ;
        RECT 349.400 0.000 349.480 1.000 ;
    END
  END m_o[870]
  PIN m_o[871]
    DIRECTION OUTPUT ;
    USE SIGNAL ;
    PORT
      LAYER Metal4 ;
        RECT 349.800 0.000 349.880 1.000 ;
    END
  END m_o[871]
  PIN m_o[872]
    DIRECTION OUTPUT ;
    USE SIGNAL ;
    PORT
      LAYER Metal4 ;
        RECT 350.200 0.000 350.280 1.000 ;
    END
  END m_o[872]
  PIN m_o[873]
    DIRECTION OUTPUT ;
    USE SIGNAL ;
    PORT
      LAYER Metal4 ;
        RECT 350.600 0.000 350.680 1.000 ;
    END
  END m_o[873]
  PIN m_o[874]
    DIRECTION OUTPUT ;
    USE SIGNAL ;
    PORT
      LAYER Metal4 ;
        RECT 351.000 0.000 351.080 1.000 ;
    END
  END m_o[874]
  PIN m_o[875]
    DIRECTION OUTPUT ;
    USE SIGNAL ;
    PORT
      LAYER Metal4 ;
        RECT 351.400 0.000 351.480 1.000 ;
    END
  END m_o[875]
  PIN m_o[876]
    DIRECTION OUTPUT ;
    USE SIGNAL ;
    PORT
      LAYER Metal4 ;
        RECT 351.800 0.000 351.880 1.000 ;
    END
  END m_o[876]
  PIN m_o[877]
    DIRECTION OUTPUT ;
    USE SIGNAL ;
    PORT
      LAYER Metal4 ;
        RECT 352.200 0.000 352.280 1.000 ;
    END
  END m_o[877]
  PIN m_o[878]
    DIRECTION OUTPUT ;
    USE SIGNAL ;
    PORT
      LAYER Metal4 ;
        RECT 352.600 0.000 352.680 1.000 ;
    END
  END m_o[878]
  PIN m_o[879]
    DIRECTION OUTPUT ;
    USE SIGNAL ;
    PORT
      LAYER Metal4 ;
        RECT 353.000 0.000 353.080 1.000 ;
    END
  END m_o[879]
  PIN m_o[880]
    DIRECTION OUTPUT ;
    USE SIGNAL ;
    PORT
      LAYER Metal4 ;
        RECT 353.400 0.000 353.480 1.000 ;
    END
  END m_o[880]
  PIN m_o[881]
    DIRECTION OUTPUT ;
    USE SIGNAL ;
    PORT
      LAYER Metal4 ;
        RECT 353.800 0.000 353.880 1.000 ;
    END
  END m_o[881]
  PIN m_o[882]
    DIRECTION OUTPUT ;
    USE SIGNAL ;
    PORT
      LAYER Metal4 ;
        RECT 354.200 0.000 354.280 1.000 ;
    END
  END m_o[882]
  PIN m_o[883]
    DIRECTION OUTPUT ;
    USE SIGNAL ;
    PORT
      LAYER Metal4 ;
        RECT 354.600 0.000 354.680 1.000 ;
    END
  END m_o[883]
  PIN m_o[884]
    DIRECTION OUTPUT ;
    USE SIGNAL ;
    PORT
      LAYER Metal4 ;
        RECT 355.000 0.000 355.080 1.000 ;
    END
  END m_o[884]
  PIN m_o[885]
    DIRECTION OUTPUT ;
    USE SIGNAL ;
    PORT
      LAYER Metal4 ;
        RECT 355.400 0.000 355.480 1.000 ;
    END
  END m_o[885]
  PIN m_o[886]
    DIRECTION OUTPUT ;
    USE SIGNAL ;
    PORT
      LAYER Metal4 ;
        RECT 355.800 0.000 355.880 1.000 ;
    END
  END m_o[886]
  PIN m_o[887]
    DIRECTION OUTPUT ;
    USE SIGNAL ;
    PORT
      LAYER Metal4 ;
        RECT 356.200 0.000 356.280 1.000 ;
    END
  END m_o[887]
  PIN m_o[888]
    DIRECTION OUTPUT ;
    USE SIGNAL ;
    PORT
      LAYER Metal4 ;
        RECT 356.600 0.000 356.680 1.000 ;
    END
  END m_o[888]
  PIN m_o[889]
    DIRECTION OUTPUT ;
    USE SIGNAL ;
    PORT
      LAYER Metal4 ;
        RECT 357.000 0.000 357.080 1.000 ;
    END
  END m_o[889]
  PIN m_o[890]
    DIRECTION OUTPUT ;
    USE SIGNAL ;
    PORT
      LAYER Metal4 ;
        RECT 357.400 0.000 357.480 1.000 ;
    END
  END m_o[890]
  PIN m_o[891]
    DIRECTION OUTPUT ;
    USE SIGNAL ;
    PORT
      LAYER Metal4 ;
        RECT 357.800 0.000 357.880 1.000 ;
    END
  END m_o[891]
  PIN m_o[892]
    DIRECTION OUTPUT ;
    USE SIGNAL ;
    PORT
      LAYER Metal4 ;
        RECT 358.200 0.000 358.280 1.000 ;
    END
  END m_o[892]
  PIN m_o[893]
    DIRECTION OUTPUT ;
    USE SIGNAL ;
    PORT
      LAYER Metal4 ;
        RECT 358.600 0.000 358.680 1.000 ;
    END
  END m_o[893]
  PIN m_o[894]
    DIRECTION OUTPUT ;
    USE SIGNAL ;
    PORT
      LAYER Metal4 ;
        RECT 359.000 0.000 359.080 1.000 ;
    END
  END m_o[894]
  PIN m_o[895]
    DIRECTION OUTPUT ;
    USE SIGNAL ;
    PORT
      LAYER Metal4 ;
        RECT 359.400 0.000 359.480 1.000 ;
    END
  END m_o[895]
  PIN m_o[896]
    DIRECTION OUTPUT ;
    USE SIGNAL ;
    PORT
      LAYER Metal4 ;
        RECT 359.800 0.000 359.880 1.000 ;
    END
  END m_o[896]
  PIN m_o[897]
    DIRECTION OUTPUT ;
    USE SIGNAL ;
    PORT
      LAYER Metal4 ;
        RECT 360.200 0.000 360.280 1.000 ;
    END
  END m_o[897]
  PIN m_o[898]
    DIRECTION OUTPUT ;
    USE SIGNAL ;
    PORT
      LAYER Metal4 ;
        RECT 360.600 0.000 360.680 1.000 ;
    END
  END m_o[898]
  PIN m_o[899]
    DIRECTION OUTPUT ;
    USE SIGNAL ;
    PORT
      LAYER Metal4 ;
        RECT 361.000 0.000 361.080 1.000 ;
    END
  END m_o[899]
  PIN m_o[900]
    DIRECTION OUTPUT ;
    USE SIGNAL ;
    PORT
      LAYER Metal4 ;
        RECT 361.400 0.000 361.480 1.000 ;
    END
  END m_o[900]
  PIN m_o[901]
    DIRECTION OUTPUT ;
    USE SIGNAL ;
    PORT
      LAYER Metal4 ;
        RECT 361.800 0.000 361.880 1.000 ;
    END
  END m_o[901]
  PIN m_o[902]
    DIRECTION OUTPUT ;
    USE SIGNAL ;
    PORT
      LAYER Metal4 ;
        RECT 362.200 0.000 362.280 1.000 ;
    END
  END m_o[902]
  PIN m_o[903]
    DIRECTION OUTPUT ;
    USE SIGNAL ;
    PORT
      LAYER Metal4 ;
        RECT 362.600 0.000 362.680 1.000 ;
    END
  END m_o[903]
  PIN m_o[904]
    DIRECTION OUTPUT ;
    USE SIGNAL ;
    PORT
      LAYER Metal4 ;
        RECT 363.000 0.000 363.080 1.000 ;
    END
  END m_o[904]
  PIN m_o[905]
    DIRECTION OUTPUT ;
    USE SIGNAL ;
    PORT
      LAYER Metal4 ;
        RECT 363.400 0.000 363.480 1.000 ;
    END
  END m_o[905]
  PIN m_o[906]
    DIRECTION OUTPUT ;
    USE SIGNAL ;
    PORT
      LAYER Metal4 ;
        RECT 363.800 0.000 363.880 1.000 ;
    END
  END m_o[906]
  PIN m_o[907]
    DIRECTION OUTPUT ;
    USE SIGNAL ;
    PORT
      LAYER Metal4 ;
        RECT 364.200 0.000 364.280 1.000 ;
    END
  END m_o[907]
  PIN m_o[908]
    DIRECTION OUTPUT ;
    USE SIGNAL ;
    PORT
      LAYER Metal4 ;
        RECT 364.600 0.000 364.680 1.000 ;
    END
  END m_o[908]
  PIN m_o[909]
    DIRECTION OUTPUT ;
    USE SIGNAL ;
    PORT
      LAYER Metal4 ;
        RECT 365.000 0.000 365.080 1.000 ;
    END
  END m_o[909]
  PIN m_o[910]
    DIRECTION OUTPUT ;
    USE SIGNAL ;
    PORT
      LAYER Metal4 ;
        RECT 365.400 0.000 365.480 1.000 ;
    END
  END m_o[910]
  PIN m_o[911]
    DIRECTION OUTPUT ;
    USE SIGNAL ;
    PORT
      LAYER Metal4 ;
        RECT 365.800 0.000 365.880 1.000 ;
    END
  END m_o[911]
  PIN m_o[912]
    DIRECTION OUTPUT ;
    USE SIGNAL ;
    PORT
      LAYER Metal4 ;
        RECT 366.200 0.000 366.280 1.000 ;
    END
  END m_o[912]
  PIN m_o[913]
    DIRECTION OUTPUT ;
    USE SIGNAL ;
    PORT
      LAYER Metal4 ;
        RECT 366.600 0.000 366.680 1.000 ;
    END
  END m_o[913]
  PIN m_o[914]
    DIRECTION OUTPUT ;
    USE SIGNAL ;
    PORT
      LAYER Metal4 ;
        RECT 367.000 0.000 367.080 1.000 ;
    END
  END m_o[914]
  PIN m_o[915]
    DIRECTION OUTPUT ;
    USE SIGNAL ;
    PORT
      LAYER Metal4 ;
        RECT 367.400 0.000 367.480 1.000 ;
    END
  END m_o[915]
  PIN m_o[916]
    DIRECTION OUTPUT ;
    USE SIGNAL ;
    PORT
      LAYER Metal4 ;
        RECT 367.800 0.000 367.880 1.000 ;
    END
  END m_o[916]
  PIN m_o[917]
    DIRECTION OUTPUT ;
    USE SIGNAL ;
    PORT
      LAYER Metal4 ;
        RECT 368.200 0.000 368.280 1.000 ;
    END
  END m_o[917]
  PIN m_o[918]
    DIRECTION OUTPUT ;
    USE SIGNAL ;
    PORT
      LAYER Metal4 ;
        RECT 368.600 0.000 368.680 1.000 ;
    END
  END m_o[918]
  PIN m_o[919]
    DIRECTION OUTPUT ;
    USE SIGNAL ;
    PORT
      LAYER Metal4 ;
        RECT 369.000 0.000 369.080 1.000 ;
    END
  END m_o[919]
  PIN m_o[920]
    DIRECTION OUTPUT ;
    USE SIGNAL ;
    PORT
      LAYER Metal4 ;
        RECT 369.400 0.000 369.480 1.000 ;
    END
  END m_o[920]
  PIN m_o[921]
    DIRECTION OUTPUT ;
    USE SIGNAL ;
    PORT
      LAYER Metal4 ;
        RECT 369.800 0.000 369.880 1.000 ;
    END
  END m_o[921]
  PIN m_o[922]
    DIRECTION OUTPUT ;
    USE SIGNAL ;
    PORT
      LAYER Metal4 ;
        RECT 370.200 0.000 370.280 1.000 ;
    END
  END m_o[922]
  PIN m_o[923]
    DIRECTION OUTPUT ;
    USE SIGNAL ;
    PORT
      LAYER Metal4 ;
        RECT 370.600 0.000 370.680 1.000 ;
    END
  END m_o[923]
  PIN m_o[924]
    DIRECTION OUTPUT ;
    USE SIGNAL ;
    PORT
      LAYER Metal4 ;
        RECT 371.000 0.000 371.080 1.000 ;
    END
  END m_o[924]
  PIN m_o[925]
    DIRECTION OUTPUT ;
    USE SIGNAL ;
    PORT
      LAYER Metal4 ;
        RECT 371.400 0.000 371.480 1.000 ;
    END
  END m_o[925]
  PIN m_o[926]
    DIRECTION OUTPUT ;
    USE SIGNAL ;
    PORT
      LAYER Metal4 ;
        RECT 371.800 0.000 371.880 1.000 ;
    END
  END m_o[926]
  PIN m_o[927]
    DIRECTION OUTPUT ;
    USE SIGNAL ;
    PORT
      LAYER Metal4 ;
        RECT 372.200 0.000 372.280 1.000 ;
    END
  END m_o[927]
  PIN m_o[928]
    DIRECTION OUTPUT ;
    USE SIGNAL ;
    PORT
      LAYER Metal4 ;
        RECT 372.600 0.000 372.680 1.000 ;
    END
  END m_o[928]
  PIN m_o[929]
    DIRECTION OUTPUT ;
    USE SIGNAL ;
    PORT
      LAYER Metal4 ;
        RECT 373.000 0.000 373.080 1.000 ;
    END
  END m_o[929]
  PIN m_o[930]
    DIRECTION OUTPUT ;
    USE SIGNAL ;
    PORT
      LAYER Metal4 ;
        RECT 373.400 0.000 373.480 1.000 ;
    END
  END m_o[930]
  PIN m_o[931]
    DIRECTION OUTPUT ;
    USE SIGNAL ;
    PORT
      LAYER Metal4 ;
        RECT 373.800 0.000 373.880 1.000 ;
    END
  END m_o[931]
  PIN m_o[932]
    DIRECTION OUTPUT ;
    USE SIGNAL ;
    PORT
      LAYER Metal4 ;
        RECT 374.200 0.000 374.280 1.000 ;
    END
  END m_o[932]
  PIN m_o[933]
    DIRECTION OUTPUT ;
    USE SIGNAL ;
    PORT
      LAYER Metal4 ;
        RECT 374.600 0.000 374.680 1.000 ;
    END
  END m_o[933]
  PIN m_o[934]
    DIRECTION OUTPUT ;
    USE SIGNAL ;
    PORT
      LAYER Metal4 ;
        RECT 375.000 0.000 375.080 1.000 ;
    END
  END m_o[934]
  PIN m_o[935]
    DIRECTION OUTPUT ;
    USE SIGNAL ;
    PORT
      LAYER Metal4 ;
        RECT 375.400 0.000 375.480 1.000 ;
    END
  END m_o[935]
  PIN m_o[936]
    DIRECTION OUTPUT ;
    USE SIGNAL ;
    PORT
      LAYER Metal4 ;
        RECT 375.800 0.000 375.880 1.000 ;
    END
  END m_o[936]
  PIN m_o[937]
    DIRECTION OUTPUT ;
    USE SIGNAL ;
    PORT
      LAYER Metal4 ;
        RECT 376.200 0.000 376.280 1.000 ;
    END
  END m_o[937]
  PIN m_o[938]
    DIRECTION OUTPUT ;
    USE SIGNAL ;
    PORT
      LAYER Metal4 ;
        RECT 376.600 0.000 376.680 1.000 ;
    END
  END m_o[938]
  PIN m_o[939]
    DIRECTION OUTPUT ;
    USE SIGNAL ;
    PORT
      LAYER Metal4 ;
        RECT 377.000 0.000 377.080 1.000 ;
    END
  END m_o[939]
  PIN m_o[940]
    DIRECTION OUTPUT ;
    USE SIGNAL ;
    PORT
      LAYER Metal4 ;
        RECT 377.400 0.000 377.480 1.000 ;
    END
  END m_o[940]
  PIN m_o[941]
    DIRECTION OUTPUT ;
    USE SIGNAL ;
    PORT
      LAYER Metal4 ;
        RECT 377.800 0.000 377.880 1.000 ;
    END
  END m_o[941]
  PIN m_o[942]
    DIRECTION OUTPUT ;
    USE SIGNAL ;
    PORT
      LAYER Metal4 ;
        RECT 378.200 0.000 378.280 1.000 ;
    END
  END m_o[942]
  PIN m_o[943]
    DIRECTION OUTPUT ;
    USE SIGNAL ;
    PORT
      LAYER Metal4 ;
        RECT 378.600 0.000 378.680 1.000 ;
    END
  END m_o[943]
  PIN m_o[944]
    DIRECTION OUTPUT ;
    USE SIGNAL ;
    PORT
      LAYER Metal4 ;
        RECT 379.000 0.000 379.080 1.000 ;
    END
  END m_o[944]
  PIN m_o[945]
    DIRECTION OUTPUT ;
    USE SIGNAL ;
    PORT
      LAYER Metal4 ;
        RECT 379.400 0.000 379.480 1.000 ;
    END
  END m_o[945]
  PIN m_o[946]
    DIRECTION OUTPUT ;
    USE SIGNAL ;
    PORT
      LAYER Metal4 ;
        RECT 379.800 0.000 379.880 1.000 ;
    END
  END m_o[946]
  PIN m_o[947]
    DIRECTION OUTPUT ;
    USE SIGNAL ;
    PORT
      LAYER Metal4 ;
        RECT 380.200 0.000 380.280 1.000 ;
    END
  END m_o[947]
  PIN m_o[948]
    DIRECTION OUTPUT ;
    USE SIGNAL ;
    PORT
      LAYER Metal4 ;
        RECT 380.600 0.000 380.680 1.000 ;
    END
  END m_o[948]
  PIN m_o[949]
    DIRECTION OUTPUT ;
    USE SIGNAL ;
    PORT
      LAYER Metal4 ;
        RECT 381.000 0.000 381.080 1.000 ;
    END
  END m_o[949]
  PIN m_o[950]
    DIRECTION OUTPUT ;
    USE SIGNAL ;
    PORT
      LAYER Metal4 ;
        RECT 381.400 0.000 381.480 1.000 ;
    END
  END m_o[950]
  PIN m_o[951]
    DIRECTION OUTPUT ;
    USE SIGNAL ;
    PORT
      LAYER Metal4 ;
        RECT 381.800 0.000 381.880 1.000 ;
    END
  END m_o[951]
  PIN m_o[952]
    DIRECTION OUTPUT ;
    USE SIGNAL ;
    PORT
      LAYER Metal4 ;
        RECT 382.200 0.000 382.280 1.000 ;
    END
  END m_o[952]
  PIN m_o[953]
    DIRECTION OUTPUT ;
    USE SIGNAL ;
    PORT
      LAYER Metal4 ;
        RECT 382.600 0.000 382.680 1.000 ;
    END
  END m_o[953]
  PIN m_o[954]
    DIRECTION OUTPUT ;
    USE SIGNAL ;
    PORT
      LAYER Metal4 ;
        RECT 383.000 0.000 383.080 1.000 ;
    END
  END m_o[954]
  PIN m_o[955]
    DIRECTION OUTPUT ;
    USE SIGNAL ;
    PORT
      LAYER Metal4 ;
        RECT 383.400 0.000 383.480 1.000 ;
    END
  END m_o[955]
  PIN m_o[956]
    DIRECTION OUTPUT ;
    USE SIGNAL ;
    PORT
      LAYER Metal4 ;
        RECT 383.800 0.000 383.880 1.000 ;
    END
  END m_o[956]
  PIN m_o[957]
    DIRECTION OUTPUT ;
    USE SIGNAL ;
    PORT
      LAYER Metal4 ;
        RECT 384.200 0.000 384.280 1.000 ;
    END
  END m_o[957]
  PIN m_o[958]
    DIRECTION OUTPUT ;
    USE SIGNAL ;
    PORT
      LAYER Metal4 ;
        RECT 384.600 0.000 384.680 1.000 ;
    END
  END m_o[958]
  PIN m_o[959]
    DIRECTION OUTPUT ;
    USE SIGNAL ;
    PORT
      LAYER Metal4 ;
        RECT 385.000 0.000 385.080 1.000 ;
    END
  END m_o[959]
  PIN m_o[960]
    DIRECTION OUTPUT ;
    USE SIGNAL ;
    PORT
      LAYER Metal4 ;
        RECT 385.400 0.000 385.480 1.000 ;
    END
  END m_o[960]
  PIN m_o[961]
    DIRECTION OUTPUT ;
    USE SIGNAL ;
    PORT
      LAYER Metal4 ;
        RECT 385.800 0.000 385.880 1.000 ;
    END
  END m_o[961]
  PIN m_o[962]
    DIRECTION OUTPUT ;
    USE SIGNAL ;
    PORT
      LAYER Metal4 ;
        RECT 386.200 0.000 386.280 1.000 ;
    END
  END m_o[962]
  PIN m_o[963]
    DIRECTION OUTPUT ;
    USE SIGNAL ;
    PORT
      LAYER Metal4 ;
        RECT 386.600 0.000 386.680 1.000 ;
    END
  END m_o[963]
  PIN m_o[964]
    DIRECTION OUTPUT ;
    USE SIGNAL ;
    PORT
      LAYER Metal4 ;
        RECT 387.000 0.000 387.080 1.000 ;
    END
  END m_o[964]
  PIN m_o[965]
    DIRECTION OUTPUT ;
    USE SIGNAL ;
    PORT
      LAYER Metal4 ;
        RECT 387.400 0.000 387.480 1.000 ;
    END
  END m_o[965]
  PIN m_o[966]
    DIRECTION OUTPUT ;
    USE SIGNAL ;
    PORT
      LAYER Metal4 ;
        RECT 387.800 0.000 387.880 1.000 ;
    END
  END m_o[966]
  PIN m_o[967]
    DIRECTION OUTPUT ;
    USE SIGNAL ;
    PORT
      LAYER Metal4 ;
        RECT 388.200 0.000 388.280 1.000 ;
    END
  END m_o[967]
  PIN m_o[968]
    DIRECTION OUTPUT ;
    USE SIGNAL ;
    PORT
      LAYER Metal4 ;
        RECT 388.600 0.000 388.680 1.000 ;
    END
  END m_o[968]
  PIN m_o[969]
    DIRECTION OUTPUT ;
    USE SIGNAL ;
    PORT
      LAYER Metal4 ;
        RECT 389.000 0.000 389.080 1.000 ;
    END
  END m_o[969]
  PIN m_o[970]
    DIRECTION OUTPUT ;
    USE SIGNAL ;
    PORT
      LAYER Metal4 ;
        RECT 389.400 0.000 389.480 1.000 ;
    END
  END m_o[970]
  PIN m_o[971]
    DIRECTION OUTPUT ;
    USE SIGNAL ;
    PORT
      LAYER Metal4 ;
        RECT 389.800 0.000 389.880 1.000 ;
    END
  END m_o[971]
  PIN m_o[972]
    DIRECTION OUTPUT ;
    USE SIGNAL ;
    PORT
      LAYER Metal4 ;
        RECT 390.200 0.000 390.280 1.000 ;
    END
  END m_o[972]
  PIN m_o[973]
    DIRECTION OUTPUT ;
    USE SIGNAL ;
    PORT
      LAYER Metal4 ;
        RECT 390.600 0.000 390.680 1.000 ;
    END
  END m_o[973]
  PIN m_o[974]
    DIRECTION OUTPUT ;
    USE SIGNAL ;
    PORT
      LAYER Metal4 ;
        RECT 391.000 0.000 391.080 1.000 ;
    END
  END m_o[974]
  PIN m_o[975]
    DIRECTION OUTPUT ;
    USE SIGNAL ;
    PORT
      LAYER Metal4 ;
        RECT 391.400 0.000 391.480 1.000 ;
    END
  END m_o[975]
  PIN m_o[976]
    DIRECTION OUTPUT ;
    USE SIGNAL ;
    PORT
      LAYER Metal4 ;
        RECT 391.800 0.000 391.880 1.000 ;
    END
  END m_o[976]
  PIN m_o[977]
    DIRECTION OUTPUT ;
    USE SIGNAL ;
    PORT
      LAYER Metal4 ;
        RECT 392.200 0.000 392.280 1.000 ;
    END
  END m_o[977]
  PIN m_o[978]
    DIRECTION OUTPUT ;
    USE SIGNAL ;
    PORT
      LAYER Metal4 ;
        RECT 392.600 0.000 392.680 1.000 ;
    END
  END m_o[978]
  PIN m_o[979]
    DIRECTION OUTPUT ;
    USE SIGNAL ;
    PORT
      LAYER Metal4 ;
        RECT 393.000 0.000 393.080 1.000 ;
    END
  END m_o[979]
  PIN m_o[980]
    DIRECTION OUTPUT ;
    USE SIGNAL ;
    PORT
      LAYER Metal4 ;
        RECT 393.400 0.000 393.480 1.000 ;
    END
  END m_o[980]
  PIN m_o[981]
    DIRECTION OUTPUT ;
    USE SIGNAL ;
    PORT
      LAYER Metal4 ;
        RECT 393.800 0.000 393.880 1.000 ;
    END
  END m_o[981]
  PIN m_o[982]
    DIRECTION OUTPUT ;
    USE SIGNAL ;
    PORT
      LAYER Metal4 ;
        RECT 394.200 0.000 394.280 1.000 ;
    END
  END m_o[982]
  PIN m_o[983]
    DIRECTION OUTPUT ;
    USE SIGNAL ;
    PORT
      LAYER Metal4 ;
        RECT 394.600 0.000 394.680 1.000 ;
    END
  END m_o[983]
  PIN m_o[984]
    DIRECTION OUTPUT ;
    USE SIGNAL ;
    PORT
      LAYER Metal4 ;
        RECT 395.000 0.000 395.080 1.000 ;
    END
  END m_o[984]
  PIN m_o[985]
    DIRECTION OUTPUT ;
    USE SIGNAL ;
    PORT
      LAYER Metal4 ;
        RECT 395.400 0.000 395.480 1.000 ;
    END
  END m_o[985]
  PIN m_o[986]
    DIRECTION OUTPUT ;
    USE SIGNAL ;
    PORT
      LAYER Metal4 ;
        RECT 395.800 0.000 395.880 1.000 ;
    END
  END m_o[986]
  PIN m_o[987]
    DIRECTION OUTPUT ;
    USE SIGNAL ;
    PORT
      LAYER Metal4 ;
        RECT 396.200 0.000 396.280 1.000 ;
    END
  END m_o[987]
  PIN m_o[988]
    DIRECTION OUTPUT ;
    USE SIGNAL ;
    PORT
      LAYER Metal4 ;
        RECT 396.600 0.000 396.680 1.000 ;
    END
  END m_o[988]
  PIN m_o[989]
    DIRECTION OUTPUT ;
    USE SIGNAL ;
    PORT
      LAYER Metal4 ;
        RECT 397.000 0.000 397.080 1.000 ;
    END
  END m_o[989]
  PIN m_o[990]
    DIRECTION OUTPUT ;
    USE SIGNAL ;
    PORT
      LAYER Metal4 ;
        RECT 397.400 0.000 397.480 1.000 ;
    END
  END m_o[990]
  PIN m_o[991]
    DIRECTION OUTPUT ;
    USE SIGNAL ;
    PORT
      LAYER Metal4 ;
        RECT 397.800 0.000 397.880 1.000 ;
    END
  END m_o[991]
  PIN m_o[992]
    DIRECTION OUTPUT ;
    USE SIGNAL ;
    PORT
      LAYER Metal4 ;
        RECT 398.200 0.000 398.280 1.000 ;
    END
  END m_o[992]
  PIN m_o[993]
    DIRECTION OUTPUT ;
    USE SIGNAL ;
    PORT
      LAYER Metal4 ;
        RECT 398.600 0.000 398.680 1.000 ;
    END
  END m_o[993]
  PIN m_o[994]
    DIRECTION OUTPUT ;
    USE SIGNAL ;
    PORT
      LAYER Metal4 ;
        RECT 399.000 0.000 399.080 1.000 ;
    END
  END m_o[994]
  PIN m_o[995]
    DIRECTION OUTPUT ;
    USE SIGNAL ;
    PORT
      LAYER Metal4 ;
        RECT 399.400 0.000 399.480 1.000 ;
    END
  END m_o[995]
  PIN m_o[996]
    DIRECTION OUTPUT ;
    USE SIGNAL ;
    PORT
      LAYER Metal4 ;
        RECT 399.800 0.000 399.880 1.000 ;
    END
  END m_o[996]
  PIN m_o[997]
    DIRECTION OUTPUT ;
    USE SIGNAL ;
    PORT
      LAYER Metal4 ;
        RECT 400.200 0.000 400.280 1.000 ;
    END
  END m_o[997]
  PIN m_o[998]
    DIRECTION OUTPUT ;
    USE SIGNAL ;
    PORT
      LAYER Metal4 ;
        RECT 400.600 0.000 400.680 1.000 ;
    END
  END m_o[998]
  PIN m_o[999]
    DIRECTION OUTPUT ;
    USE SIGNAL ;
    PORT
      LAYER Metal4 ;
        RECT 401.000 0.000 401.080 1.000 ;
    END
  END m_o[999]
  PIN m_o[1000]
    DIRECTION OUTPUT ;
    USE SIGNAL ;
    PORT
      LAYER Metal4 ;
        RECT 401.400 0.000 401.480 1.000 ;
    END
  END m_o[1000]
  PIN m_o[1001]
    DIRECTION OUTPUT ;
    USE SIGNAL ;
    PORT
      LAYER Metal4 ;
        RECT 401.800 0.000 401.880 1.000 ;
    END
  END m_o[1001]
  PIN m_o[1002]
    DIRECTION OUTPUT ;
    USE SIGNAL ;
    PORT
      LAYER Metal4 ;
        RECT 402.200 0.000 402.280 1.000 ;
    END
  END m_o[1002]
  PIN m_o[1003]
    DIRECTION OUTPUT ;
    USE SIGNAL ;
    PORT
      LAYER Metal4 ;
        RECT 402.600 0.000 402.680 1.000 ;
    END
  END m_o[1003]
  PIN m_o[1004]
    DIRECTION OUTPUT ;
    USE SIGNAL ;
    PORT
      LAYER Metal4 ;
        RECT 403.000 0.000 403.080 1.000 ;
    END
  END m_o[1004]
  PIN m_o[1005]
    DIRECTION OUTPUT ;
    USE SIGNAL ;
    PORT
      LAYER Metal4 ;
        RECT 403.400 0.000 403.480 1.000 ;
    END
  END m_o[1005]
  PIN m_o[1006]
    DIRECTION OUTPUT ;
    USE SIGNAL ;
    PORT
      LAYER Metal4 ;
        RECT 403.800 0.000 403.880 1.000 ;
    END
  END m_o[1006]
  PIN m_o[1007]
    DIRECTION OUTPUT ;
    USE SIGNAL ;
    PORT
      LAYER Metal4 ;
        RECT 404.200 0.000 404.280 1.000 ;
    END
  END m_o[1007]
  PIN m_o[1008]
    DIRECTION OUTPUT ;
    USE SIGNAL ;
    PORT
      LAYER Metal4 ;
        RECT 404.600 0.000 404.680 1.000 ;
    END
  END m_o[1008]
  PIN m_o[1009]
    DIRECTION OUTPUT ;
    USE SIGNAL ;
    PORT
      LAYER Metal4 ;
        RECT 405.000 0.000 405.080 1.000 ;
    END
  END m_o[1009]
  PIN m_o[1010]
    DIRECTION OUTPUT ;
    USE SIGNAL ;
    PORT
      LAYER Metal4 ;
        RECT 405.400 0.000 405.480 1.000 ;
    END
  END m_o[1010]
  PIN m_o[1011]
    DIRECTION OUTPUT ;
    USE SIGNAL ;
    PORT
      LAYER Metal4 ;
        RECT 405.800 0.000 405.880 1.000 ;
    END
  END m_o[1011]
  PIN m_o[1012]
    DIRECTION OUTPUT ;
    USE SIGNAL ;
    PORT
      LAYER Metal4 ;
        RECT 406.200 0.000 406.280 1.000 ;
    END
  END m_o[1012]
  PIN m_o[1013]
    DIRECTION OUTPUT ;
    USE SIGNAL ;
    PORT
      LAYER Metal4 ;
        RECT 406.600 0.000 406.680 1.000 ;
    END
  END m_o[1013]
  PIN m_o[1014]
    DIRECTION OUTPUT ;
    USE SIGNAL ;
    PORT
      LAYER Metal4 ;
        RECT 407.000 0.000 407.080 1.000 ;
    END
  END m_o[1014]
  PIN m_o[1015]
    DIRECTION OUTPUT ;
    USE SIGNAL ;
    PORT
      LAYER Metal4 ;
        RECT 407.400 0.000 407.480 1.000 ;
    END
  END m_o[1015]
  PIN m_o[1016]
    DIRECTION OUTPUT ;
    USE SIGNAL ;
    PORT
      LAYER Metal4 ;
        RECT 407.800 0.000 407.880 1.000 ;
    END
  END m_o[1016]
  PIN m_o[1017]
    DIRECTION OUTPUT ;
    USE SIGNAL ;
    PORT
      LAYER Metal4 ;
        RECT 408.200 0.000 408.280 1.000 ;
    END
  END m_o[1017]
  PIN m_o[1018]
    DIRECTION OUTPUT ;
    USE SIGNAL ;
    PORT
      LAYER Metal4 ;
        RECT 408.600 0.000 408.680 1.000 ;
    END
  END m_o[1018]
  PIN m_o[1019]
    DIRECTION OUTPUT ;
    USE SIGNAL ;
    PORT
      LAYER Metal4 ;
        RECT 409.000 0.000 409.080 1.000 ;
    END
  END m_o[1019]
  PIN m_o[1020]
    DIRECTION OUTPUT ;
    USE SIGNAL ;
    PORT
      LAYER Metal4 ;
        RECT 409.400 0.000 409.480 1.000 ;
    END
  END m_o[1020]
  PIN m_o[1021]
    DIRECTION OUTPUT ;
    USE SIGNAL ;
    PORT
      LAYER Metal4 ;
        RECT 409.800 0.000 409.880 1.000 ;
    END
  END m_o[1021]
  PIN m_o[1022]
    DIRECTION OUTPUT ;
    USE SIGNAL ;
    PORT
      LAYER Metal4 ;
        RECT 410.200 0.000 410.280 1.000 ;
    END
  END m_o[1022]
  PIN m_o[1023]
    DIRECTION OUTPUT ;
    USE SIGNAL ;
    PORT
      LAYER Metal4 ;
        RECT 410.600 0.000 410.680 1.000 ;
    END
  END m_o[1023]
  PIN m_o[1024]
    DIRECTION OUTPUT ;
    USE SIGNAL ;
    PORT
      LAYER Metal4 ;
        RECT 411.000 0.000 411.080 1.000 ;
    END
  END m_o[1024]
  PIN m_o[1025]
    DIRECTION OUTPUT ;
    USE SIGNAL ;
    PORT
      LAYER Metal4 ;
        RECT 411.400 0.000 411.480 1.000 ;
    END
  END m_o[1025]
  PIN m_o[1026]
    DIRECTION OUTPUT ;
    USE SIGNAL ;
    PORT
      LAYER Metal4 ;
        RECT 411.800 0.000 411.880 1.000 ;
    END
  END m_o[1026]
  PIN m_o[1027]
    DIRECTION OUTPUT ;
    USE SIGNAL ;
    PORT
      LAYER Metal4 ;
        RECT 412.200 0.000 412.280 1.000 ;
    END
  END m_o[1027]
  PIN m_o[1028]
    DIRECTION OUTPUT ;
    USE SIGNAL ;
    PORT
      LAYER Metal4 ;
        RECT 412.600 0.000 412.680 1.000 ;
    END
  END m_o[1028]
  PIN m_o[1029]
    DIRECTION OUTPUT ;
    USE SIGNAL ;
    PORT
      LAYER Metal4 ;
        RECT 413.000 0.000 413.080 1.000 ;
    END
  END m_o[1029]
  PIN m_o[1030]
    DIRECTION OUTPUT ;
    USE SIGNAL ;
    PORT
      LAYER Metal4 ;
        RECT 413.400 0.000 413.480 1.000 ;
    END
  END m_o[1030]
  PIN m_o[1031]
    DIRECTION OUTPUT ;
    USE SIGNAL ;
    PORT
      LAYER Metal4 ;
        RECT 413.800 0.000 413.880 1.000 ;
    END
  END m_o[1031]
  PIN m_o[1032]
    DIRECTION OUTPUT ;
    USE SIGNAL ;
    PORT
      LAYER Metal4 ;
        RECT 414.200 0.000 414.280 1.000 ;
    END
  END m_o[1032]
  PIN m_o[1033]
    DIRECTION OUTPUT ;
    USE SIGNAL ;
    PORT
      LAYER Metal4 ;
        RECT 414.600 0.000 414.680 1.000 ;
    END
  END m_o[1033]
  PIN m_o[1034]
    DIRECTION OUTPUT ;
    USE SIGNAL ;
    PORT
      LAYER Metal4 ;
        RECT 415.000 0.000 415.080 1.000 ;
    END
  END m_o[1034]
  PIN m_o[1035]
    DIRECTION OUTPUT ;
    USE SIGNAL ;
    PORT
      LAYER Metal4 ;
        RECT 415.400 0.000 415.480 1.000 ;
    END
  END m_o[1035]
  PIN m_o[1036]
    DIRECTION OUTPUT ;
    USE SIGNAL ;
    PORT
      LAYER Metal4 ;
        RECT 415.800 0.000 415.880 1.000 ;
    END
  END m_o[1036]
  PIN m_o[1037]
    DIRECTION OUTPUT ;
    USE SIGNAL ;
    PORT
      LAYER Metal4 ;
        RECT 416.200 0.000 416.280 1.000 ;
    END
  END m_o[1037]
  PIN m_o[1038]
    DIRECTION OUTPUT ;
    USE SIGNAL ;
    PORT
      LAYER Metal4 ;
        RECT 416.600 0.000 416.680 1.000 ;
    END
  END m_o[1038]
  PIN m_o[1039]
    DIRECTION OUTPUT ;
    USE SIGNAL ;
    PORT
      LAYER Metal4 ;
        RECT 417.000 0.000 417.080 1.000 ;
    END
  END m_o[1039]
  PIN m_o[1040]
    DIRECTION OUTPUT ;
    USE SIGNAL ;
    PORT
      LAYER Metal4 ;
        RECT 417.400 0.000 417.480 1.000 ;
    END
  END m_o[1040]
  PIN m_o[1041]
    DIRECTION OUTPUT ;
    USE SIGNAL ;
    PORT
      LAYER Metal4 ;
        RECT 417.800 0.000 417.880 1.000 ;
    END
  END m_o[1041]
  PIN m_o[1042]
    DIRECTION OUTPUT ;
    USE SIGNAL ;
    PORT
      LAYER Metal4 ;
        RECT 418.200 0.000 418.280 1.000 ;
    END
  END m_o[1042]
  PIN m_o[1043]
    DIRECTION OUTPUT ;
    USE SIGNAL ;
    PORT
      LAYER Metal4 ;
        RECT 418.600 0.000 418.680 1.000 ;
    END
  END m_o[1043]
  PIN m_o[1044]
    DIRECTION OUTPUT ;
    USE SIGNAL ;
    PORT
      LAYER Metal4 ;
        RECT 419.000 0.000 419.080 1.000 ;
    END
  END m_o[1044]
  PIN m_o[1045]
    DIRECTION OUTPUT ;
    USE SIGNAL ;
    PORT
      LAYER Metal4 ;
        RECT 419.400 0.000 419.480 1.000 ;
    END
  END m_o[1045]
  PIN m_o[1046]
    DIRECTION OUTPUT ;
    USE SIGNAL ;
    PORT
      LAYER Metal4 ;
        RECT 419.800 0.000 419.880 1.000 ;
    END
  END m_o[1046]
  PIN m_o[1047]
    DIRECTION OUTPUT ;
    USE SIGNAL ;
    PORT
      LAYER Metal4 ;
        RECT 420.200 0.000 420.280 1.000 ;
    END
  END m_o[1047]
  PIN m_o[1048]
    DIRECTION OUTPUT ;
    USE SIGNAL ;
    PORT
      LAYER Metal4 ;
        RECT 420.600 0.000 420.680 1.000 ;
    END
  END m_o[1048]
  PIN m_o[1049]
    DIRECTION OUTPUT ;
    USE SIGNAL ;
    PORT
      LAYER Metal4 ;
        RECT 421.000 0.000 421.080 1.000 ;
    END
  END m_o[1049]
  PIN m_o[1050]
    DIRECTION OUTPUT ;
    USE SIGNAL ;
    PORT
      LAYER Metal4 ;
        RECT 421.400 0.000 421.480 1.000 ;
    END
  END m_o[1050]
  PIN m_o[1051]
    DIRECTION OUTPUT ;
    USE SIGNAL ;
    PORT
      LAYER Metal4 ;
        RECT 421.800 0.000 421.880 1.000 ;
    END
  END m_o[1051]
  PIN m_o[1052]
    DIRECTION OUTPUT ;
    USE SIGNAL ;
    PORT
      LAYER Metal4 ;
        RECT 422.200 0.000 422.280 1.000 ;
    END
  END m_o[1052]
  PIN m_o[1053]
    DIRECTION OUTPUT ;
    USE SIGNAL ;
    PORT
      LAYER Metal4 ;
        RECT 422.600 0.000 422.680 1.000 ;
    END
  END m_o[1053]
  PIN m_o[1054]
    DIRECTION OUTPUT ;
    USE SIGNAL ;
    PORT
      LAYER Metal4 ;
        RECT 423.000 0.000 423.080 1.000 ;
    END
  END m_o[1054]
  PIN m_o[1055]
    DIRECTION OUTPUT ;
    USE SIGNAL ;
    PORT
      LAYER Metal4 ;
        RECT 423.400 0.000 423.480 1.000 ;
    END
  END m_o[1055]
  PIN m_o[1056]
    DIRECTION OUTPUT ;
    USE SIGNAL ;
    PORT
      LAYER Metal4 ;
        RECT 423.800 0.000 423.880 1.000 ;
    END
  END m_o[1056]
  PIN m_o[1057]
    DIRECTION OUTPUT ;
    USE SIGNAL ;
    PORT
      LAYER Metal4 ;
        RECT 424.200 0.000 424.280 1.000 ;
    END
  END m_o[1057]
  PIN m_o[1058]
    DIRECTION OUTPUT ;
    USE SIGNAL ;
    PORT
      LAYER Metal4 ;
        RECT 424.600 0.000 424.680 1.000 ;
    END
  END m_o[1058]
  PIN m_o[1059]
    DIRECTION OUTPUT ;
    USE SIGNAL ;
    PORT
      LAYER Metal4 ;
        RECT 425.000 0.000 425.080 1.000 ;
    END
  END m_o[1059]
  PIN m_o[1060]
    DIRECTION OUTPUT ;
    USE SIGNAL ;
    PORT
      LAYER Metal4 ;
        RECT 425.400 0.000 425.480 1.000 ;
    END
  END m_o[1060]
  PIN m_o[1061]
    DIRECTION OUTPUT ;
    USE SIGNAL ;
    PORT
      LAYER Metal4 ;
        RECT 425.800 0.000 425.880 1.000 ;
    END
  END m_o[1061]
  PIN m_o[1062]
    DIRECTION OUTPUT ;
    USE SIGNAL ;
    PORT
      LAYER Metal4 ;
        RECT 426.200 0.000 426.280 1.000 ;
    END
  END m_o[1062]
  PIN m_o[1063]
    DIRECTION OUTPUT ;
    USE SIGNAL ;
    PORT
      LAYER Metal4 ;
        RECT 426.600 0.000 426.680 1.000 ;
    END
  END m_o[1063]
  PIN m_o[1064]
    DIRECTION OUTPUT ;
    USE SIGNAL ;
    PORT
      LAYER Metal4 ;
        RECT 427.000 0.000 427.080 1.000 ;
    END
  END m_o[1064]
  PIN m_o[1065]
    DIRECTION OUTPUT ;
    USE SIGNAL ;
    PORT
      LAYER Metal4 ;
        RECT 427.400 0.000 427.480 1.000 ;
    END
  END m_o[1065]
  PIN m_o[1066]
    DIRECTION OUTPUT ;
    USE SIGNAL ;
    PORT
      LAYER Metal4 ;
        RECT 427.800 0.000 427.880 1.000 ;
    END
  END m_o[1066]
  PIN m_o[1067]
    DIRECTION OUTPUT ;
    USE SIGNAL ;
    PORT
      LAYER Metal4 ;
        RECT 428.200 0.000 428.280 1.000 ;
    END
  END m_o[1067]
  PIN m_o[1068]
    DIRECTION OUTPUT ;
    USE SIGNAL ;
    PORT
      LAYER Metal4 ;
        RECT 428.600 0.000 428.680 1.000 ;
    END
  END m_o[1068]
  PIN m_o[1069]
    DIRECTION OUTPUT ;
    USE SIGNAL ;
    PORT
      LAYER Metal4 ;
        RECT 429.000 0.000 429.080 1.000 ;
    END
  END m_o[1069]
  PIN m_o[1070]
    DIRECTION OUTPUT ;
    USE SIGNAL ;
    PORT
      LAYER Metal4 ;
        RECT 429.400 0.000 429.480 1.000 ;
    END
  END m_o[1070]
  PIN m_o[1071]
    DIRECTION OUTPUT ;
    USE SIGNAL ;
    PORT
      LAYER Metal4 ;
        RECT 429.800 0.000 429.880 1.000 ;
    END
  END m_o[1071]
  PIN m_o[1072]
    DIRECTION OUTPUT ;
    USE SIGNAL ;
    PORT
      LAYER Metal4 ;
        RECT 430.200 0.000 430.280 1.000 ;
    END
  END m_o[1072]
  PIN m_o[1073]
    DIRECTION OUTPUT ;
    USE SIGNAL ;
    PORT
      LAYER Metal4 ;
        RECT 430.600 0.000 430.680 1.000 ;
    END
  END m_o[1073]
  PIN m_o[1074]
    DIRECTION OUTPUT ;
    USE SIGNAL ;
    PORT
      LAYER Metal4 ;
        RECT 431.000 0.000 431.080 1.000 ;
    END
  END m_o[1074]
  PIN m_o[1075]
    DIRECTION OUTPUT ;
    USE SIGNAL ;
    PORT
      LAYER Metal4 ;
        RECT 431.400 0.000 431.480 1.000 ;
    END
  END m_o[1075]
  PIN m_o[1076]
    DIRECTION OUTPUT ;
    USE SIGNAL ;
    PORT
      LAYER Metal4 ;
        RECT 431.800 0.000 431.880 1.000 ;
    END
  END m_o[1076]
  PIN m_o[1077]
    DIRECTION OUTPUT ;
    USE SIGNAL ;
    PORT
      LAYER Metal4 ;
        RECT 432.200 0.000 432.280 1.000 ;
    END
  END m_o[1077]
  PIN m_o[1078]
    DIRECTION OUTPUT ;
    USE SIGNAL ;
    PORT
      LAYER Metal4 ;
        RECT 432.600 0.000 432.680 1.000 ;
    END
  END m_o[1078]
  PIN m_o[1079]
    DIRECTION OUTPUT ;
    USE SIGNAL ;
    PORT
      LAYER Metal4 ;
        RECT 433.000 0.000 433.080 1.000 ;
    END
  END m_o[1079]
  PIN m_o[1080]
    DIRECTION OUTPUT ;
    USE SIGNAL ;
    PORT
      LAYER Metal4 ;
        RECT 433.400 0.000 433.480 1.000 ;
    END
  END m_o[1080]
  PIN m_o[1081]
    DIRECTION OUTPUT ;
    USE SIGNAL ;
    PORT
      LAYER Metal4 ;
        RECT 433.800 0.000 433.880 1.000 ;
    END
  END m_o[1081]
  PIN m_o[1082]
    DIRECTION OUTPUT ;
    USE SIGNAL ;
    PORT
      LAYER Metal4 ;
        RECT 434.200 0.000 434.280 1.000 ;
    END
  END m_o[1082]
  PIN m_o[1083]
    DIRECTION OUTPUT ;
    USE SIGNAL ;
    PORT
      LAYER Metal4 ;
        RECT 434.600 0.000 434.680 1.000 ;
    END
  END m_o[1083]
  PIN m_o[1084]
    DIRECTION OUTPUT ;
    USE SIGNAL ;
    PORT
      LAYER Metal4 ;
        RECT 435.000 0.000 435.080 1.000 ;
    END
  END m_o[1084]
  PIN m_o[1085]
    DIRECTION OUTPUT ;
    USE SIGNAL ;
    PORT
      LAYER Metal4 ;
        RECT 435.400 0.000 435.480 1.000 ;
    END
  END m_o[1085]
  PIN m_o[1086]
    DIRECTION OUTPUT ;
    USE SIGNAL ;
    PORT
      LAYER Metal4 ;
        RECT 435.800 0.000 435.880 1.000 ;
    END
  END m_o[1086]
  PIN m_o[1087]
    DIRECTION OUTPUT ;
    USE SIGNAL ;
    PORT
      LAYER Metal4 ;
        RECT 436.200 0.000 436.280 1.000 ;
    END
  END m_o[1087]
  PIN m_o[1088]
    DIRECTION OUTPUT ;
    USE SIGNAL ;
    PORT
      LAYER Metal4 ;
        RECT 436.600 0.000 436.680 1.000 ;
    END
  END m_o[1088]
  PIN m_o[1089]
    DIRECTION OUTPUT ;
    USE SIGNAL ;
    PORT
      LAYER Metal4 ;
        RECT 437.000 0.000 437.080 1.000 ;
    END
  END m_o[1089]
  PIN m_o[1090]
    DIRECTION OUTPUT ;
    USE SIGNAL ;
    PORT
      LAYER Metal4 ;
        RECT 437.400 0.000 437.480 1.000 ;
    END
  END m_o[1090]
  PIN m_o[1091]
    DIRECTION OUTPUT ;
    USE SIGNAL ;
    PORT
      LAYER Metal4 ;
        RECT 437.800 0.000 437.880 1.000 ;
    END
  END m_o[1091]
  PIN m_o[1092]
    DIRECTION OUTPUT ;
    USE SIGNAL ;
    PORT
      LAYER Metal4 ;
        RECT 438.200 0.000 438.280 1.000 ;
    END
  END m_o[1092]
  PIN m_o[1093]
    DIRECTION OUTPUT ;
    USE SIGNAL ;
    PORT
      LAYER Metal4 ;
        RECT 438.600 0.000 438.680 1.000 ;
    END
  END m_o[1093]
  PIN m_o[1094]
    DIRECTION OUTPUT ;
    USE SIGNAL ;
    PORT
      LAYER Metal4 ;
        RECT 439.000 0.000 439.080 1.000 ;
    END
  END m_o[1094]
  PIN m_o[1095]
    DIRECTION OUTPUT ;
    USE SIGNAL ;
    PORT
      LAYER Metal4 ;
        RECT 439.400 0.000 439.480 1.000 ;
    END
  END m_o[1095]
  PIN m_o[1096]
    DIRECTION OUTPUT ;
    USE SIGNAL ;
    PORT
      LAYER Metal4 ;
        RECT 439.800 0.000 439.880 1.000 ;
    END
  END m_o[1096]
  PIN m_o[1097]
    DIRECTION OUTPUT ;
    USE SIGNAL ;
    PORT
      LAYER Metal4 ;
        RECT 440.200 0.000 440.280 1.000 ;
    END
  END m_o[1097]
  PIN m_o[1098]
    DIRECTION OUTPUT ;
    USE SIGNAL ;
    PORT
      LAYER Metal4 ;
        RECT 440.600 0.000 440.680 1.000 ;
    END
  END m_o[1098]
  PIN m_o[1099]
    DIRECTION OUTPUT ;
    USE SIGNAL ;
    PORT
      LAYER Metal4 ;
        RECT 441.000 0.000 441.080 1.000 ;
    END
  END m_o[1099]
  PIN m_o[1100]
    DIRECTION OUTPUT ;
    USE SIGNAL ;
    PORT
      LAYER Metal4 ;
        RECT 441.400 0.000 441.480 1.000 ;
    END
  END m_o[1100]
  PIN m_o[1101]
    DIRECTION OUTPUT ;
    USE SIGNAL ;
    PORT
      LAYER Metal4 ;
        RECT 441.800 0.000 441.880 1.000 ;
    END
  END m_o[1101]
  PIN m_o[1102]
    DIRECTION OUTPUT ;
    USE SIGNAL ;
    PORT
      LAYER Metal4 ;
        RECT 442.200 0.000 442.280 1.000 ;
    END
  END m_o[1102]
  PIN m_o[1103]
    DIRECTION OUTPUT ;
    USE SIGNAL ;
    PORT
      LAYER Metal4 ;
        RECT 442.600 0.000 442.680 1.000 ;
    END
  END m_o[1103]
  PIN m_o[1104]
    DIRECTION OUTPUT ;
    USE SIGNAL ;
    PORT
      LAYER Metal4 ;
        RECT 443.000 0.000 443.080 1.000 ;
    END
  END m_o[1104]
  PIN m_o[1105]
    DIRECTION OUTPUT ;
    USE SIGNAL ;
    PORT
      LAYER Metal4 ;
        RECT 443.400 0.000 443.480 1.000 ;
    END
  END m_o[1105]
  PIN m_o[1106]
    DIRECTION OUTPUT ;
    USE SIGNAL ;
    PORT
      LAYER Metal4 ;
        RECT 443.800 0.000 443.880 1.000 ;
    END
  END m_o[1106]
  PIN m_o[1107]
    DIRECTION OUTPUT ;
    USE SIGNAL ;
    PORT
      LAYER Metal4 ;
        RECT 444.200 0.000 444.280 1.000 ;
    END
  END m_o[1107]
  PIN m_o[1108]
    DIRECTION OUTPUT ;
    USE SIGNAL ;
    PORT
      LAYER Metal4 ;
        RECT 444.600 0.000 444.680 1.000 ;
    END
  END m_o[1108]
  PIN m_o[1109]
    DIRECTION OUTPUT ;
    USE SIGNAL ;
    PORT
      LAYER Metal4 ;
        RECT 445.000 0.000 445.080 1.000 ;
    END
  END m_o[1109]
  PIN m_o[1110]
    DIRECTION OUTPUT ;
    USE SIGNAL ;
    PORT
      LAYER Metal4 ;
        RECT 445.400 0.000 445.480 1.000 ;
    END
  END m_o[1110]
  PIN m_o[1111]
    DIRECTION OUTPUT ;
    USE SIGNAL ;
    PORT
      LAYER Metal4 ;
        RECT 445.800 0.000 445.880 1.000 ;
    END
  END m_o[1111]
  PIN m_o[1112]
    DIRECTION OUTPUT ;
    USE SIGNAL ;
    PORT
      LAYER Metal4 ;
        RECT 446.200 0.000 446.280 1.000 ;
    END
  END m_o[1112]
  PIN m_o[1113]
    DIRECTION OUTPUT ;
    USE SIGNAL ;
    PORT
      LAYER Metal4 ;
        RECT 446.600 0.000 446.680 1.000 ;
    END
  END m_o[1113]
  PIN m_o[1114]
    DIRECTION OUTPUT ;
    USE SIGNAL ;
    PORT
      LAYER Metal4 ;
        RECT 447.000 0.000 447.080 1.000 ;
    END
  END m_o[1114]
  PIN m_o[1115]
    DIRECTION OUTPUT ;
    USE SIGNAL ;
    PORT
      LAYER Metal4 ;
        RECT 447.400 0.000 447.480 1.000 ;
    END
  END m_o[1115]
  PIN m_o[1116]
    DIRECTION OUTPUT ;
    USE SIGNAL ;
    PORT
      LAYER Metal4 ;
        RECT 447.800 0.000 447.880 1.000 ;
    END
  END m_o[1116]
  PIN m_o[1117]
    DIRECTION OUTPUT ;
    USE SIGNAL ;
    PORT
      LAYER Metal4 ;
        RECT 448.200 0.000 448.280 1.000 ;
    END
  END m_o[1117]
  PIN m_o[1118]
    DIRECTION OUTPUT ;
    USE SIGNAL ;
    PORT
      LAYER Metal4 ;
        RECT 448.600 0.000 448.680 1.000 ;
    END
  END m_o[1118]
  PIN m_o[1119]
    DIRECTION OUTPUT ;
    USE SIGNAL ;
    PORT
      LAYER Metal4 ;
        RECT 449.000 0.000 449.080 1.000 ;
    END
  END m_o[1119]
  PIN m_o[1120]
    DIRECTION OUTPUT ;
    USE SIGNAL ;
    PORT
      LAYER Metal4 ;
        RECT 449.400 0.000 449.480 1.000 ;
    END
  END m_o[1120]
  PIN m_o[1121]
    DIRECTION OUTPUT ;
    USE SIGNAL ;
    PORT
      LAYER Metal4 ;
        RECT 449.800 0.000 449.880 1.000 ;
    END
  END m_o[1121]
  PIN m_o[1122]
    DIRECTION OUTPUT ;
    USE SIGNAL ;
    PORT
      LAYER Metal4 ;
        RECT 450.200 0.000 450.280 1.000 ;
    END
  END m_o[1122]
  PIN m_o[1123]
    DIRECTION OUTPUT ;
    USE SIGNAL ;
    PORT
      LAYER Metal4 ;
        RECT 450.600 0.000 450.680 1.000 ;
    END
  END m_o[1123]
  PIN m_o[1124]
    DIRECTION OUTPUT ;
    USE SIGNAL ;
    PORT
      LAYER Metal4 ;
        RECT 451.000 0.000 451.080 1.000 ;
    END
  END m_o[1124]
  PIN m_o[1125]
    DIRECTION OUTPUT ;
    USE SIGNAL ;
    PORT
      LAYER Metal4 ;
        RECT 451.400 0.000 451.480 1.000 ;
    END
  END m_o[1125]
  PIN m_o[1126]
    DIRECTION OUTPUT ;
    USE SIGNAL ;
    PORT
      LAYER Metal4 ;
        RECT 451.800 0.000 451.880 1.000 ;
    END
  END m_o[1126]
  PIN m_o[1127]
    DIRECTION OUTPUT ;
    USE SIGNAL ;
    PORT
      LAYER Metal4 ;
        RECT 452.200 0.000 452.280 1.000 ;
    END
  END m_o[1127]
  PIN m_o[1128]
    DIRECTION OUTPUT ;
    USE SIGNAL ;
    PORT
      LAYER Metal4 ;
        RECT 452.600 0.000 452.680 1.000 ;
    END
  END m_o[1128]
  PIN m_o[1129]
    DIRECTION OUTPUT ;
    USE SIGNAL ;
    PORT
      LAYER Metal4 ;
        RECT 453.000 0.000 453.080 1.000 ;
    END
  END m_o[1129]
  PIN m_o[1130]
    DIRECTION OUTPUT ;
    USE SIGNAL ;
    PORT
      LAYER Metal4 ;
        RECT 453.400 0.000 453.480 1.000 ;
    END
  END m_o[1130]
  PIN m_o[1131]
    DIRECTION OUTPUT ;
    USE SIGNAL ;
    PORT
      LAYER Metal4 ;
        RECT 453.800 0.000 453.880 1.000 ;
    END
  END m_o[1131]
  PIN m_o[1132]
    DIRECTION OUTPUT ;
    USE SIGNAL ;
    PORT
      LAYER Metal4 ;
        RECT 454.200 0.000 454.280 1.000 ;
    END
  END m_o[1132]
  PIN m_o[1133]
    DIRECTION OUTPUT ;
    USE SIGNAL ;
    PORT
      LAYER Metal4 ;
        RECT 454.600 0.000 454.680 1.000 ;
    END
  END m_o[1133]
  PIN m_o[1134]
    DIRECTION OUTPUT ;
    USE SIGNAL ;
    PORT
      LAYER Metal4 ;
        RECT 455.000 0.000 455.080 1.000 ;
    END
  END m_o[1134]
  PIN m_o[1135]
    DIRECTION OUTPUT ;
    USE SIGNAL ;
    PORT
      LAYER Metal4 ;
        RECT 455.400 0.000 455.480 1.000 ;
    END
  END m_o[1135]
  PIN m_o[1136]
    DIRECTION OUTPUT ;
    USE SIGNAL ;
    PORT
      LAYER Metal4 ;
        RECT 455.800 0.000 455.880 1.000 ;
    END
  END m_o[1136]
  PIN m_o[1137]
    DIRECTION OUTPUT ;
    USE SIGNAL ;
    PORT
      LAYER Metal4 ;
        RECT 456.200 0.000 456.280 1.000 ;
    END
  END m_o[1137]
  PIN m_o[1138]
    DIRECTION OUTPUT ;
    USE SIGNAL ;
    PORT
      LAYER Metal4 ;
        RECT 456.600 0.000 456.680 1.000 ;
    END
  END m_o[1138]
  PIN m_o[1139]
    DIRECTION OUTPUT ;
    USE SIGNAL ;
    PORT
      LAYER Metal4 ;
        RECT 457.000 0.000 457.080 1.000 ;
    END
  END m_o[1139]
  PIN m_o[1140]
    DIRECTION OUTPUT ;
    USE SIGNAL ;
    PORT
      LAYER Metal4 ;
        RECT 457.400 0.000 457.480 1.000 ;
    END
  END m_o[1140]
  PIN m_o[1141]
    DIRECTION OUTPUT ;
    USE SIGNAL ;
    PORT
      LAYER Metal4 ;
        RECT 457.800 0.000 457.880 1.000 ;
    END
  END m_o[1141]
  PIN m_o[1142]
    DIRECTION OUTPUT ;
    USE SIGNAL ;
    PORT
      LAYER Metal4 ;
        RECT 458.200 0.000 458.280 1.000 ;
    END
  END m_o[1142]
  PIN m_o[1143]
    DIRECTION OUTPUT ;
    USE SIGNAL ;
    PORT
      LAYER Metal4 ;
        RECT 458.600 0.000 458.680 1.000 ;
    END
  END m_o[1143]
  PIN m_o[1144]
    DIRECTION OUTPUT ;
    USE SIGNAL ;
    PORT
      LAYER Metal4 ;
        RECT 459.000 0.000 459.080 1.000 ;
    END
  END m_o[1144]
  PIN m_o[1145]
    DIRECTION OUTPUT ;
    USE SIGNAL ;
    PORT
      LAYER Metal4 ;
        RECT 459.400 0.000 459.480 1.000 ;
    END
  END m_o[1145]
  PIN m_o[1146]
    DIRECTION OUTPUT ;
    USE SIGNAL ;
    PORT
      LAYER Metal4 ;
        RECT 459.800 0.000 459.880 1.000 ;
    END
  END m_o[1146]
  PIN m_o[1147]
    DIRECTION OUTPUT ;
    USE SIGNAL ;
    PORT
      LAYER Metal4 ;
        RECT 460.200 0.000 460.280 1.000 ;
    END
  END m_o[1147]
  PIN m_o[1148]
    DIRECTION OUTPUT ;
    USE SIGNAL ;
    PORT
      LAYER Metal4 ;
        RECT 460.600 0.000 460.680 1.000 ;
    END
  END m_o[1148]
  PIN m_o[1149]
    DIRECTION OUTPUT ;
    USE SIGNAL ;
    PORT
      LAYER Metal4 ;
        RECT 461.000 0.000 461.080 1.000 ;
    END
  END m_o[1149]
  PIN m_o[1150]
    DIRECTION OUTPUT ;
    USE SIGNAL ;
    PORT
      LAYER Metal4 ;
        RECT 461.400 0.000 461.480 1.000 ;
    END
  END m_o[1150]
  PIN m_o[1151]
    DIRECTION OUTPUT ;
    USE SIGNAL ;
    PORT
      LAYER Metal4 ;
        RECT 461.800 0.000 461.880 1.000 ;
    END
  END m_o[1151]
  PIN m_o[1152]
    DIRECTION OUTPUT ;
    USE SIGNAL ;
    PORT
      LAYER Metal4 ;
        RECT 462.200 0.000 462.280 1.000 ;
    END
  END m_o[1152]
  PIN m_o[1153]
    DIRECTION OUTPUT ;
    USE SIGNAL ;
    PORT
      LAYER Metal4 ;
        RECT 462.600 0.000 462.680 1.000 ;
    END
  END m_o[1153]
  PIN m_o[1154]
    DIRECTION OUTPUT ;
    USE SIGNAL ;
    PORT
      LAYER Metal4 ;
        RECT 463.000 0.000 463.080 1.000 ;
    END
  END m_o[1154]
  PIN m_o[1155]
    DIRECTION OUTPUT ;
    USE SIGNAL ;
    PORT
      LAYER Metal4 ;
        RECT 463.400 0.000 463.480 1.000 ;
    END
  END m_o[1155]
  PIN m_o[1156]
    DIRECTION OUTPUT ;
    USE SIGNAL ;
    PORT
      LAYER Metal4 ;
        RECT 463.800 0.000 463.880 1.000 ;
    END
  END m_o[1156]
  PIN m_o[1157]
    DIRECTION OUTPUT ;
    USE SIGNAL ;
    PORT
      LAYER Metal4 ;
        RECT 464.200 0.000 464.280 1.000 ;
    END
  END m_o[1157]
  PIN m_o[1158]
    DIRECTION OUTPUT ;
    USE SIGNAL ;
    PORT
      LAYER Metal4 ;
        RECT 464.600 0.000 464.680 1.000 ;
    END
  END m_o[1158]
  PIN m_o[1159]
    DIRECTION OUTPUT ;
    USE SIGNAL ;
    PORT
      LAYER Metal4 ;
        RECT 465.000 0.000 465.080 1.000 ;
    END
  END m_o[1159]
  PIN m_o[1160]
    DIRECTION OUTPUT ;
    USE SIGNAL ;
    PORT
      LAYER Metal4 ;
        RECT 465.400 0.000 465.480 1.000 ;
    END
  END m_o[1160]
  PIN m_o[1161]
    DIRECTION OUTPUT ;
    USE SIGNAL ;
    PORT
      LAYER Metal4 ;
        RECT 465.800 0.000 465.880 1.000 ;
    END
  END m_o[1161]
  PIN m_o[1162]
    DIRECTION OUTPUT ;
    USE SIGNAL ;
    PORT
      LAYER Metal4 ;
        RECT 466.200 0.000 466.280 1.000 ;
    END
  END m_o[1162]
  PIN m_o[1163]
    DIRECTION OUTPUT ;
    USE SIGNAL ;
    PORT
      LAYER Metal4 ;
        RECT 466.600 0.000 466.680 1.000 ;
    END
  END m_o[1163]
  PIN m_o[1164]
    DIRECTION OUTPUT ;
    USE SIGNAL ;
    PORT
      LAYER Metal4 ;
        RECT 467.000 0.000 467.080 1.000 ;
    END
  END m_o[1164]
  PIN m_o[1165]
    DIRECTION OUTPUT ;
    USE SIGNAL ;
    PORT
      LAYER Metal4 ;
        RECT 467.400 0.000 467.480 1.000 ;
    END
  END m_o[1165]
  PIN m_o[1166]
    DIRECTION OUTPUT ;
    USE SIGNAL ;
    PORT
      LAYER Metal4 ;
        RECT 467.800 0.000 467.880 1.000 ;
    END
  END m_o[1166]
  PIN m_o[1167]
    DIRECTION OUTPUT ;
    USE SIGNAL ;
    PORT
      LAYER Metal4 ;
        RECT 468.200 0.000 468.280 1.000 ;
    END
  END m_o[1167]
  PIN m_o[1168]
    DIRECTION OUTPUT ;
    USE SIGNAL ;
    PORT
      LAYER Metal4 ;
        RECT 468.600 0.000 468.680 1.000 ;
    END
  END m_o[1168]
  PIN m_o[1169]
    DIRECTION OUTPUT ;
    USE SIGNAL ;
    PORT
      LAYER Metal4 ;
        RECT 469.000 0.000 469.080 1.000 ;
    END
  END m_o[1169]
  PIN m_o[1170]
    DIRECTION OUTPUT ;
    USE SIGNAL ;
    PORT
      LAYER Metal4 ;
        RECT 469.400 0.000 469.480 1.000 ;
    END
  END m_o[1170]
  PIN m_o[1171]
    DIRECTION OUTPUT ;
    USE SIGNAL ;
    PORT
      LAYER Metal4 ;
        RECT 469.800 0.000 469.880 1.000 ;
    END
  END m_o[1171]
  PIN m_o[1172]
    DIRECTION OUTPUT ;
    USE SIGNAL ;
    PORT
      LAYER Metal4 ;
        RECT 470.200 0.000 470.280 1.000 ;
    END
  END m_o[1172]
  PIN m_o[1173]
    DIRECTION OUTPUT ;
    USE SIGNAL ;
    PORT
      LAYER Metal4 ;
        RECT 470.600 0.000 470.680 1.000 ;
    END
  END m_o[1173]
  PIN m_o[1174]
    DIRECTION OUTPUT ;
    USE SIGNAL ;
    PORT
      LAYER Metal4 ;
        RECT 471.000 0.000 471.080 1.000 ;
    END
  END m_o[1174]
  PIN m_o[1175]
    DIRECTION OUTPUT ;
    USE SIGNAL ;
    PORT
      LAYER Metal4 ;
        RECT 471.400 0.000 471.480 1.000 ;
    END
  END m_o[1175]
  PIN m_o[1176]
    DIRECTION OUTPUT ;
    USE SIGNAL ;
    PORT
      LAYER Metal4 ;
        RECT 471.800 0.000 471.880 1.000 ;
    END
  END m_o[1176]
  PIN m_o[1177]
    DIRECTION OUTPUT ;
    USE SIGNAL ;
    PORT
      LAYER Metal4 ;
        RECT 472.200 0.000 472.280 1.000 ;
    END
  END m_o[1177]
  PIN m_o[1178]
    DIRECTION OUTPUT ;
    USE SIGNAL ;
    PORT
      LAYER Metal4 ;
        RECT 472.600 0.000 472.680 1.000 ;
    END
  END m_o[1178]
  PIN m_o[1179]
    DIRECTION OUTPUT ;
    USE SIGNAL ;
    PORT
      LAYER Metal4 ;
        RECT 473.000 0.000 473.080 1.000 ;
    END
  END m_o[1179]
  PIN m_o[1180]
    DIRECTION OUTPUT ;
    USE SIGNAL ;
    PORT
      LAYER Metal4 ;
        RECT 473.400 0.000 473.480 1.000 ;
    END
  END m_o[1180]
  PIN m_o[1181]
    DIRECTION OUTPUT ;
    USE SIGNAL ;
    PORT
      LAYER Metal4 ;
        RECT 473.800 0.000 473.880 1.000 ;
    END
  END m_o[1181]
  PIN m_o[1182]
    DIRECTION OUTPUT ;
    USE SIGNAL ;
    PORT
      LAYER Metal4 ;
        RECT 474.200 0.000 474.280 1.000 ;
    END
  END m_o[1182]
  PIN m_o[1183]
    DIRECTION OUTPUT ;
    USE SIGNAL ;
    PORT
      LAYER Metal4 ;
        RECT 474.600 0.000 474.680 1.000 ;
    END
  END m_o[1183]
  PIN m_o[1184]
    DIRECTION OUTPUT ;
    USE SIGNAL ;
    PORT
      LAYER Metal4 ;
        RECT 475.000 0.000 475.080 1.000 ;
    END
  END m_o[1184]
  PIN m_o[1185]
    DIRECTION OUTPUT ;
    USE SIGNAL ;
    PORT
      LAYER Metal4 ;
        RECT 475.400 0.000 475.480 1.000 ;
    END
  END m_o[1185]
  PIN m_o[1186]
    DIRECTION OUTPUT ;
    USE SIGNAL ;
    PORT
      LAYER Metal4 ;
        RECT 475.800 0.000 475.880 1.000 ;
    END
  END m_o[1186]
  PIN m_o[1187]
    DIRECTION OUTPUT ;
    USE SIGNAL ;
    PORT
      LAYER Metal4 ;
        RECT 476.200 0.000 476.280 1.000 ;
    END
  END m_o[1187]
  PIN m_o[1188]
    DIRECTION OUTPUT ;
    USE SIGNAL ;
    PORT
      LAYER Metal4 ;
        RECT 476.600 0.000 476.680 1.000 ;
    END
  END m_o[1188]
  PIN m_o[1189]
    DIRECTION OUTPUT ;
    USE SIGNAL ;
    PORT
      LAYER Metal4 ;
        RECT 477.000 0.000 477.080 1.000 ;
    END
  END m_o[1189]
  PIN m_o[1190]
    DIRECTION OUTPUT ;
    USE SIGNAL ;
    PORT
      LAYER Metal4 ;
        RECT 477.400 0.000 477.480 1.000 ;
    END
  END m_o[1190]
  PIN m_o[1191]
    DIRECTION OUTPUT ;
    USE SIGNAL ;
    PORT
      LAYER Metal4 ;
        RECT 477.800 0.000 477.880 1.000 ;
    END
  END m_o[1191]
  PIN m_o[1192]
    DIRECTION OUTPUT ;
    USE SIGNAL ;
    PORT
      LAYER Metal4 ;
        RECT 478.200 0.000 478.280 1.000 ;
    END
  END m_o[1192]
  PIN m_o[1193]
    DIRECTION OUTPUT ;
    USE SIGNAL ;
    PORT
      LAYER Metal4 ;
        RECT 478.600 0.000 478.680 1.000 ;
    END
  END m_o[1193]
  PIN m_o[1194]
    DIRECTION OUTPUT ;
    USE SIGNAL ;
    PORT
      LAYER Metal4 ;
        RECT 479.000 0.000 479.080 1.000 ;
    END
  END m_o[1194]
  PIN m_o[1195]
    DIRECTION OUTPUT ;
    USE SIGNAL ;
    PORT
      LAYER Metal4 ;
        RECT 479.400 0.000 479.480 1.000 ;
    END
  END m_o[1195]
  PIN m_o[1196]
    DIRECTION OUTPUT ;
    USE SIGNAL ;
    PORT
      LAYER Metal4 ;
        RECT 479.800 0.000 479.880 1.000 ;
    END
  END m_o[1196]
  PIN m_o[1197]
    DIRECTION OUTPUT ;
    USE SIGNAL ;
    PORT
      LAYER Metal4 ;
        RECT 480.200 0.000 480.280 1.000 ;
    END
  END m_o[1197]
  PIN m_o[1198]
    DIRECTION OUTPUT ;
    USE SIGNAL ;
    PORT
      LAYER Metal4 ;
        RECT 480.600 0.000 480.680 1.000 ;
    END
  END m_o[1198]
  PIN m_o[1199]
    DIRECTION OUTPUT ;
    USE SIGNAL ;
    PORT
      LAYER Metal4 ;
        RECT 481.000 0.000 481.080 1.000 ;
    END
  END m_o[1199]
  PIN m_o[1200]
    DIRECTION OUTPUT ;
    USE SIGNAL ;
    PORT
      LAYER Metal4 ;
        RECT 481.400 0.000 481.480 1.000 ;
    END
  END m_o[1200]
  PIN m_o[1201]
    DIRECTION OUTPUT ;
    USE SIGNAL ;
    PORT
      LAYER Metal4 ;
        RECT 481.800 0.000 481.880 1.000 ;
    END
  END m_o[1201]
  PIN m_o[1202]
    DIRECTION OUTPUT ;
    USE SIGNAL ;
    PORT
      LAYER Metal4 ;
        RECT 482.200 0.000 482.280 1.000 ;
    END
  END m_o[1202]
  PIN m_o[1203]
    DIRECTION OUTPUT ;
    USE SIGNAL ;
    PORT
      LAYER Metal4 ;
        RECT 482.600 0.000 482.680 1.000 ;
    END
  END m_o[1203]
  PIN m_o[1204]
    DIRECTION OUTPUT ;
    USE SIGNAL ;
    PORT
      LAYER Metal4 ;
        RECT 483.000 0.000 483.080 1.000 ;
    END
  END m_o[1204]
  PIN m_o[1205]
    DIRECTION OUTPUT ;
    USE SIGNAL ;
    PORT
      LAYER Metal4 ;
        RECT 483.400 0.000 483.480 1.000 ;
    END
  END m_o[1205]
  PIN m_o[1206]
    DIRECTION OUTPUT ;
    USE SIGNAL ;
    PORT
      LAYER Metal4 ;
        RECT 483.800 0.000 483.880 1.000 ;
    END
  END m_o[1206]
  PIN m_o[1207]
    DIRECTION OUTPUT ;
    USE SIGNAL ;
    PORT
      LAYER Metal4 ;
        RECT 484.200 0.000 484.280 1.000 ;
    END
  END m_o[1207]
  PIN m_o[1208]
    DIRECTION OUTPUT ;
    USE SIGNAL ;
    PORT
      LAYER Metal4 ;
        RECT 484.600 0.000 484.680 1.000 ;
    END
  END m_o[1208]
  PIN m_o[1209]
    DIRECTION OUTPUT ;
    USE SIGNAL ;
    PORT
      LAYER Metal4 ;
        RECT 485.000 0.000 485.080 1.000 ;
    END
  END m_o[1209]
  PIN m_o[1210]
    DIRECTION OUTPUT ;
    USE SIGNAL ;
    PORT
      LAYER Metal4 ;
        RECT 485.400 0.000 485.480 1.000 ;
    END
  END m_o[1210]
  PIN m_o[1211]
    DIRECTION OUTPUT ;
    USE SIGNAL ;
    PORT
      LAYER Metal4 ;
        RECT 485.800 0.000 485.880 1.000 ;
    END
  END m_o[1211]
  PIN m_o[1212]
    DIRECTION OUTPUT ;
    USE SIGNAL ;
    PORT
      LAYER Metal4 ;
        RECT 486.200 0.000 486.280 1.000 ;
    END
  END m_o[1212]
  PIN m_o[1213]
    DIRECTION OUTPUT ;
    USE SIGNAL ;
    PORT
      LAYER Metal4 ;
        RECT 486.600 0.000 486.680 1.000 ;
    END
  END m_o[1213]
  PIN m_o[1214]
    DIRECTION OUTPUT ;
    USE SIGNAL ;
    PORT
      LAYER Metal4 ;
        RECT 487.000 0.000 487.080 1.000 ;
    END
  END m_o[1214]
  PIN m_o[1215]
    DIRECTION OUTPUT ;
    USE SIGNAL ;
    PORT
      LAYER Metal4 ;
        RECT 487.400 0.000 487.480 1.000 ;
    END
  END m_o[1215]
  PIN m_o[1216]
    DIRECTION OUTPUT ;
    USE SIGNAL ;
    PORT
      LAYER Metal4 ;
        RECT 487.800 0.000 487.880 1.000 ;
    END
  END m_o[1216]
  PIN m_o[1217]
    DIRECTION OUTPUT ;
    USE SIGNAL ;
    PORT
      LAYER Metal4 ;
        RECT 488.200 0.000 488.280 1.000 ;
    END
  END m_o[1217]
  PIN m_o[1218]
    DIRECTION OUTPUT ;
    USE SIGNAL ;
    PORT
      LAYER Metal4 ;
        RECT 488.600 0.000 488.680 1.000 ;
    END
  END m_o[1218]
  PIN m_o[1219]
    DIRECTION OUTPUT ;
    USE SIGNAL ;
    PORT
      LAYER Metal4 ;
        RECT 489.000 0.000 489.080 1.000 ;
    END
  END m_o[1219]
  PIN m_o[1220]
    DIRECTION OUTPUT ;
    USE SIGNAL ;
    PORT
      LAYER Metal4 ;
        RECT 489.400 0.000 489.480 1.000 ;
    END
  END m_o[1220]
  PIN m_o[1221]
    DIRECTION OUTPUT ;
    USE SIGNAL ;
    PORT
      LAYER Metal4 ;
        RECT 489.800 0.000 489.880 1.000 ;
    END
  END m_o[1221]
  PIN m_o[1222]
    DIRECTION OUTPUT ;
    USE SIGNAL ;
    PORT
      LAYER Metal4 ;
        RECT 490.200 0.000 490.280 1.000 ;
    END
  END m_o[1222]
  PIN m_o[1223]
    DIRECTION OUTPUT ;
    USE SIGNAL ;
    PORT
      LAYER Metal4 ;
        RECT 490.600 0.000 490.680 1.000 ;
    END
  END m_o[1223]
  PIN m_o[1224]
    DIRECTION OUTPUT ;
    USE SIGNAL ;
    PORT
      LAYER Metal4 ;
        RECT 491.000 0.000 491.080 1.000 ;
    END
  END m_o[1224]
  PIN m_o[1225]
    DIRECTION OUTPUT ;
    USE SIGNAL ;
    PORT
      LAYER Metal4 ;
        RECT 491.400 0.000 491.480 1.000 ;
    END
  END m_o[1225]
  PIN m_o[1226]
    DIRECTION OUTPUT ;
    USE SIGNAL ;
    PORT
      LAYER Metal4 ;
        RECT 491.800 0.000 491.880 1.000 ;
    END
  END m_o[1226]
  PIN m_o[1227]
    DIRECTION OUTPUT ;
    USE SIGNAL ;
    PORT
      LAYER Metal4 ;
        RECT 492.200 0.000 492.280 1.000 ;
    END
  END m_o[1227]
  PIN m_o[1228]
    DIRECTION OUTPUT ;
    USE SIGNAL ;
    PORT
      LAYER Metal4 ;
        RECT 492.600 0.000 492.680 1.000 ;
    END
  END m_o[1228]
  PIN m_o[1229]
    DIRECTION OUTPUT ;
    USE SIGNAL ;
    PORT
      LAYER Metal4 ;
        RECT 493.000 0.000 493.080 1.000 ;
    END
  END m_o[1229]
  PIN m_o[1230]
    DIRECTION OUTPUT ;
    USE SIGNAL ;
    PORT
      LAYER Metal4 ;
        RECT 493.400 0.000 493.480 1.000 ;
    END
  END m_o[1230]
  PIN m_o[1231]
    DIRECTION OUTPUT ;
    USE SIGNAL ;
    PORT
      LAYER Metal4 ;
        RECT 493.800 0.000 493.880 1.000 ;
    END
  END m_o[1231]
  PIN m_o[1232]
    DIRECTION OUTPUT ;
    USE SIGNAL ;
    PORT
      LAYER Metal4 ;
        RECT 494.200 0.000 494.280 1.000 ;
    END
  END m_o[1232]
  PIN m_o[1233]
    DIRECTION OUTPUT ;
    USE SIGNAL ;
    PORT
      LAYER Metal4 ;
        RECT 494.600 0.000 494.680 1.000 ;
    END
  END m_o[1233]
  PIN m_o[1234]
    DIRECTION OUTPUT ;
    USE SIGNAL ;
    PORT
      LAYER Metal4 ;
        RECT 495.000 0.000 495.080 1.000 ;
    END
  END m_o[1234]
  PIN m_o[1235]
    DIRECTION OUTPUT ;
    USE SIGNAL ;
    PORT
      LAYER Metal4 ;
        RECT 495.400 0.000 495.480 1.000 ;
    END
  END m_o[1235]
  PIN m_o[1236]
    DIRECTION OUTPUT ;
    USE SIGNAL ;
    PORT
      LAYER Metal4 ;
        RECT 495.800 0.000 495.880 1.000 ;
    END
  END m_o[1236]
  PIN m_o[1237]
    DIRECTION OUTPUT ;
    USE SIGNAL ;
    PORT
      LAYER Metal4 ;
        RECT 496.200 0.000 496.280 1.000 ;
    END
  END m_o[1237]
  PIN m_o[1238]
    DIRECTION OUTPUT ;
    USE SIGNAL ;
    PORT
      LAYER Metal4 ;
        RECT 496.600 0.000 496.680 1.000 ;
    END
  END m_o[1238]
  PIN m_o[1239]
    DIRECTION OUTPUT ;
    USE SIGNAL ;
    PORT
      LAYER Metal4 ;
        RECT 497.000 0.000 497.080 1.000 ;
    END
  END m_o[1239]
  PIN m_o[1240]
    DIRECTION OUTPUT ;
    USE SIGNAL ;
    PORT
      LAYER Metal4 ;
        RECT 497.400 0.000 497.480 1.000 ;
    END
  END m_o[1240]
  PIN m_o[1241]
    DIRECTION OUTPUT ;
    USE SIGNAL ;
    PORT
      LAYER Metal4 ;
        RECT 497.800 0.000 497.880 1.000 ;
    END
  END m_o[1241]
  PIN m_o[1242]
    DIRECTION OUTPUT ;
    USE SIGNAL ;
    PORT
      LAYER Metal4 ;
        RECT 498.200 0.000 498.280 1.000 ;
    END
  END m_o[1242]
  PIN m_o[1243]
    DIRECTION OUTPUT ;
    USE SIGNAL ;
    PORT
      LAYER Metal4 ;
        RECT 498.600 0.000 498.680 1.000 ;
    END
  END m_o[1243]
  PIN m_o[1244]
    DIRECTION OUTPUT ;
    USE SIGNAL ;
    PORT
      LAYER Metal4 ;
        RECT 499.000 0.000 499.080 1.000 ;
    END
  END m_o[1244]
  PIN m_o[1245]
    DIRECTION OUTPUT ;
    USE SIGNAL ;
    PORT
      LAYER Metal4 ;
        RECT 499.400 0.000 499.480 1.000 ;
    END
  END m_o[1245]
  PIN m_o[1246]
    DIRECTION OUTPUT ;
    USE SIGNAL ;
    PORT
      LAYER Metal4 ;
        RECT 499.800 0.000 499.880 1.000 ;
    END
  END m_o[1246]
  PIN m_o[1247]
    DIRECTION OUTPUT ;
    USE SIGNAL ;
    PORT
      LAYER Metal4 ;
        RECT 500.200 0.000 500.280 1.000 ;
    END
  END m_o[1247]
  PIN m_o[1248]
    DIRECTION OUTPUT ;
    USE SIGNAL ;
    PORT
      LAYER Metal4 ;
        RECT 500.600 0.000 500.680 1.000 ;
    END
  END m_o[1248]
  PIN m_o[1249]
    DIRECTION OUTPUT ;
    USE SIGNAL ;
    PORT
      LAYER Metal4 ;
        RECT 501.000 0.000 501.080 1.000 ;
    END
  END m_o[1249]
  PIN m_o[1250]
    DIRECTION OUTPUT ;
    USE SIGNAL ;
    PORT
      LAYER Metal4 ;
        RECT 501.400 0.000 501.480 1.000 ;
    END
  END m_o[1250]
  PIN m_o[1251]
    DIRECTION OUTPUT ;
    USE SIGNAL ;
    PORT
      LAYER Metal4 ;
        RECT 501.800 0.000 501.880 1.000 ;
    END
  END m_o[1251]
  PIN m_o[1252]
    DIRECTION OUTPUT ;
    USE SIGNAL ;
    PORT
      LAYER Metal4 ;
        RECT 502.200 0.000 502.280 1.000 ;
    END
  END m_o[1252]
  PIN m_o[1253]
    DIRECTION OUTPUT ;
    USE SIGNAL ;
    PORT
      LAYER Metal4 ;
        RECT 502.600 0.000 502.680 1.000 ;
    END
  END m_o[1253]
  PIN m_o[1254]
    DIRECTION OUTPUT ;
    USE SIGNAL ;
    PORT
      LAYER Metal4 ;
        RECT 503.000 0.000 503.080 1.000 ;
    END
  END m_o[1254]
  PIN m_o[1255]
    DIRECTION OUTPUT ;
    USE SIGNAL ;
    PORT
      LAYER Metal4 ;
        RECT 503.400 0.000 503.480 1.000 ;
    END
  END m_o[1255]
  PIN m_o[1256]
    DIRECTION OUTPUT ;
    USE SIGNAL ;
    PORT
      LAYER Metal4 ;
        RECT 503.800 0.000 503.880 1.000 ;
    END
  END m_o[1256]
  PIN m_o[1257]
    DIRECTION OUTPUT ;
    USE SIGNAL ;
    PORT
      LAYER Metal4 ;
        RECT 504.200 0.000 504.280 1.000 ;
    END
  END m_o[1257]
  PIN m_o[1258]
    DIRECTION OUTPUT ;
    USE SIGNAL ;
    PORT
      LAYER Metal4 ;
        RECT 504.600 0.000 504.680 1.000 ;
    END
  END m_o[1258]
  PIN m_o[1259]
    DIRECTION OUTPUT ;
    USE SIGNAL ;
    PORT
      LAYER Metal4 ;
        RECT 505.000 0.000 505.080 1.000 ;
    END
  END m_o[1259]
  PIN m_o[1260]
    DIRECTION OUTPUT ;
    USE SIGNAL ;
    PORT
      LAYER Metal4 ;
        RECT 505.400 0.000 505.480 1.000 ;
    END
  END m_o[1260]
  PIN m_o[1261]
    DIRECTION OUTPUT ;
    USE SIGNAL ;
    PORT
      LAYER Metal4 ;
        RECT 505.800 0.000 505.880 1.000 ;
    END
  END m_o[1261]
  PIN m_o[1262]
    DIRECTION OUTPUT ;
    USE SIGNAL ;
    PORT
      LAYER Metal4 ;
        RECT 506.200 0.000 506.280 1.000 ;
    END
  END m_o[1262]
  PIN m_o[1263]
    DIRECTION OUTPUT ;
    USE SIGNAL ;
    PORT
      LAYER Metal4 ;
        RECT 506.600 0.000 506.680 1.000 ;
    END
  END m_o[1263]
  PIN m_o[1264]
    DIRECTION OUTPUT ;
    USE SIGNAL ;
    PORT
      LAYER Metal4 ;
        RECT 507.000 0.000 507.080 1.000 ;
    END
  END m_o[1264]
  PIN m_o[1265]
    DIRECTION OUTPUT ;
    USE SIGNAL ;
    PORT
      LAYER Metal4 ;
        RECT 507.400 0.000 507.480 1.000 ;
    END
  END m_o[1265]
  PIN m_o[1266]
    DIRECTION OUTPUT ;
    USE SIGNAL ;
    PORT
      LAYER Metal4 ;
        RECT 507.800 0.000 507.880 1.000 ;
    END
  END m_o[1266]
  PIN m_o[1267]
    DIRECTION OUTPUT ;
    USE SIGNAL ;
    PORT
      LAYER Metal4 ;
        RECT 508.200 0.000 508.280 1.000 ;
    END
  END m_o[1267]
  PIN m_o[1268]
    DIRECTION OUTPUT ;
    USE SIGNAL ;
    PORT
      LAYER Metal4 ;
        RECT 508.600 0.000 508.680 1.000 ;
    END
  END m_o[1268]
  PIN m_o[1269]
    DIRECTION OUTPUT ;
    USE SIGNAL ;
    PORT
      LAYER Metal4 ;
        RECT 509.000 0.000 509.080 1.000 ;
    END
  END m_o[1269]
  PIN m_o[1270]
    DIRECTION OUTPUT ;
    USE SIGNAL ;
    PORT
      LAYER Metal4 ;
        RECT 509.400 0.000 509.480 1.000 ;
    END
  END m_o[1270]
  PIN m_o[1271]
    DIRECTION OUTPUT ;
    USE SIGNAL ;
    PORT
      LAYER Metal4 ;
        RECT 509.800 0.000 509.880 1.000 ;
    END
  END m_o[1271]
  PIN m_o[1272]
    DIRECTION OUTPUT ;
    USE SIGNAL ;
    PORT
      LAYER Metal4 ;
        RECT 510.200 0.000 510.280 1.000 ;
    END
  END m_o[1272]
  PIN m_o[1273]
    DIRECTION OUTPUT ;
    USE SIGNAL ;
    PORT
      LAYER Metal4 ;
        RECT 510.600 0.000 510.680 1.000 ;
    END
  END m_o[1273]
  PIN m_o[1274]
    DIRECTION OUTPUT ;
    USE SIGNAL ;
    PORT
      LAYER Metal4 ;
        RECT 511.000 0.000 511.080 1.000 ;
    END
  END m_o[1274]
  PIN m_o[1275]
    DIRECTION OUTPUT ;
    USE SIGNAL ;
    PORT
      LAYER Metal4 ;
        RECT 511.400 0.000 511.480 1.000 ;
    END
  END m_o[1275]
  PIN m_o[1276]
    DIRECTION OUTPUT ;
    USE SIGNAL ;
    PORT
      LAYER Metal4 ;
        RECT 511.800 0.000 511.880 1.000 ;
    END
  END m_o[1276]
  PIN m_o[1277]
    DIRECTION OUTPUT ;
    USE SIGNAL ;
    PORT
      LAYER Metal4 ;
        RECT 512.200 0.000 512.280 1.000 ;
    END
  END m_o[1277]
  PIN m_o[1278]
    DIRECTION OUTPUT ;
    USE SIGNAL ;
    PORT
      LAYER Metal4 ;
        RECT 512.600 0.000 512.680 1.000 ;
    END
  END m_o[1278]
  PIN m_o[1279]
    DIRECTION OUTPUT ;
    USE SIGNAL ;
    PORT
      LAYER Metal4 ;
        RECT 513.000 0.000 513.080 1.000 ;
    END
  END m_o[1279]
  PIN m_o[1280]
    DIRECTION OUTPUT ;
    USE SIGNAL ;
    PORT
      LAYER Metal4 ;
        RECT 513.400 0.000 513.480 1.000 ;
    END
  END m_o[1280]
  PIN m_o[1281]
    DIRECTION OUTPUT ;
    USE SIGNAL ;
    PORT
      LAYER Metal4 ;
        RECT 513.800 0.000 513.880 1.000 ;
    END
  END m_o[1281]
  PIN m_o[1282]
    DIRECTION OUTPUT ;
    USE SIGNAL ;
    PORT
      LAYER Metal4 ;
        RECT 514.200 0.000 514.280 1.000 ;
    END
  END m_o[1282]
  PIN m_o[1283]
    DIRECTION OUTPUT ;
    USE SIGNAL ;
    PORT
      LAYER Metal4 ;
        RECT 514.600 0.000 514.680 1.000 ;
    END
  END m_o[1283]
  PIN m_o[1284]
    DIRECTION OUTPUT ;
    USE SIGNAL ;
    PORT
      LAYER Metal4 ;
        RECT 515.000 0.000 515.080 1.000 ;
    END
  END m_o[1284]
  PIN m_o[1285]
    DIRECTION OUTPUT ;
    USE SIGNAL ;
    PORT
      LAYER Metal4 ;
        RECT 515.400 0.000 515.480 1.000 ;
    END
  END m_o[1285]
  PIN m_o[1286]
    DIRECTION OUTPUT ;
    USE SIGNAL ;
    PORT
      LAYER Metal4 ;
        RECT 515.800 0.000 515.880 1.000 ;
    END
  END m_o[1286]
  PIN m_o[1287]
    DIRECTION OUTPUT ;
    USE SIGNAL ;
    PORT
      LAYER Metal4 ;
        RECT 516.200 0.000 516.280 1.000 ;
    END
  END m_o[1287]
  PIN m_o[1288]
    DIRECTION OUTPUT ;
    USE SIGNAL ;
    PORT
      LAYER Metal4 ;
        RECT 516.600 0.000 516.680 1.000 ;
    END
  END m_o[1288]
  PIN m_o[1289]
    DIRECTION OUTPUT ;
    USE SIGNAL ;
    PORT
      LAYER Metal4 ;
        RECT 517.000 0.000 517.080 1.000 ;
    END
  END m_o[1289]
  PIN m_o[1290]
    DIRECTION OUTPUT ;
    USE SIGNAL ;
    PORT
      LAYER Metal4 ;
        RECT 517.400 0.000 517.480 1.000 ;
    END
  END m_o[1290]
  PIN m_o[1291]
    DIRECTION OUTPUT ;
    USE SIGNAL ;
    PORT
      LAYER Metal4 ;
        RECT 517.800 0.000 517.880 1.000 ;
    END
  END m_o[1291]
  PIN m_o[1292]
    DIRECTION OUTPUT ;
    USE SIGNAL ;
    PORT
      LAYER Metal4 ;
        RECT 518.200 0.000 518.280 1.000 ;
    END
  END m_o[1292]
  PIN m_o[1293]
    DIRECTION OUTPUT ;
    USE SIGNAL ;
    PORT
      LAYER Metal4 ;
        RECT 518.600 0.000 518.680 1.000 ;
    END
  END m_o[1293]
  PIN m_o[1294]
    DIRECTION OUTPUT ;
    USE SIGNAL ;
    PORT
      LAYER Metal4 ;
        RECT 519.000 0.000 519.080 1.000 ;
    END
  END m_o[1294]
  PIN m_o[1295]
    DIRECTION OUTPUT ;
    USE SIGNAL ;
    PORT
      LAYER Metal4 ;
        RECT 519.400 0.000 519.480 1.000 ;
    END
  END m_o[1295]
  PIN m_o[1296]
    DIRECTION OUTPUT ;
    USE SIGNAL ;
    PORT
      LAYER Metal4 ;
        RECT 519.800 0.000 519.880 1.000 ;
    END
  END m_o[1296]
  PIN m_o[1297]
    DIRECTION OUTPUT ;
    USE SIGNAL ;
    PORT
      LAYER Metal4 ;
        RECT 520.200 0.000 520.280 1.000 ;
    END
  END m_o[1297]
  PIN m_o[1298]
    DIRECTION OUTPUT ;
    USE SIGNAL ;
    PORT
      LAYER Metal4 ;
        RECT 520.600 0.000 520.680 1.000 ;
    END
  END m_o[1298]
  PIN m_o[1299]
    DIRECTION OUTPUT ;
    USE SIGNAL ;
    PORT
      LAYER Metal4 ;
        RECT 521.000 0.000 521.080 1.000 ;
    END
  END m_o[1299]
  PIN m_o[1300]
    DIRECTION OUTPUT ;
    USE SIGNAL ;
    PORT
      LAYER Metal4 ;
        RECT 521.400 0.000 521.480 1.000 ;
    END
  END m_o[1300]
  PIN m_o[1301]
    DIRECTION OUTPUT ;
    USE SIGNAL ;
    PORT
      LAYER Metal4 ;
        RECT 521.800 0.000 521.880 1.000 ;
    END
  END m_o[1301]
  PIN m_o[1302]
    DIRECTION OUTPUT ;
    USE SIGNAL ;
    PORT
      LAYER Metal4 ;
        RECT 522.200 0.000 522.280 1.000 ;
    END
  END m_o[1302]
  PIN m_o[1303]
    DIRECTION OUTPUT ;
    USE SIGNAL ;
    PORT
      LAYER Metal4 ;
        RECT 522.600 0.000 522.680 1.000 ;
    END
  END m_o[1303]
  PIN m_o[1304]
    DIRECTION OUTPUT ;
    USE SIGNAL ;
    PORT
      LAYER Metal4 ;
        RECT 523.000 0.000 523.080 1.000 ;
    END
  END m_o[1304]
  PIN m_o[1305]
    DIRECTION OUTPUT ;
    USE SIGNAL ;
    PORT
      LAYER Metal4 ;
        RECT 523.400 0.000 523.480 1.000 ;
    END
  END m_o[1305]
  PIN m_o[1306]
    DIRECTION OUTPUT ;
    USE SIGNAL ;
    PORT
      LAYER Metal4 ;
        RECT 523.800 0.000 523.880 1.000 ;
    END
  END m_o[1306]
  PIN m_o[1307]
    DIRECTION OUTPUT ;
    USE SIGNAL ;
    PORT
      LAYER Metal4 ;
        RECT 524.200 0.000 524.280 1.000 ;
    END
  END m_o[1307]
  PIN m_o[1308]
    DIRECTION OUTPUT ;
    USE SIGNAL ;
    PORT
      LAYER Metal4 ;
        RECT 524.600 0.000 524.680 1.000 ;
    END
  END m_o[1308]
  PIN m_o[1309]
    DIRECTION OUTPUT ;
    USE SIGNAL ;
    PORT
      LAYER Metal4 ;
        RECT 525.000 0.000 525.080 1.000 ;
    END
  END m_o[1309]
  PIN m_o[1310]
    DIRECTION OUTPUT ;
    USE SIGNAL ;
    PORT
      LAYER Metal4 ;
        RECT 525.400 0.000 525.480 1.000 ;
    END
  END m_o[1310]
  PIN m_o[1311]
    DIRECTION OUTPUT ;
    USE SIGNAL ;
    PORT
      LAYER Metal4 ;
        RECT 525.800 0.000 525.880 1.000 ;
    END
  END m_o[1311]
  PIN m_o[1312]
    DIRECTION OUTPUT ;
    USE SIGNAL ;
    PORT
      LAYER Metal4 ;
        RECT 526.200 0.000 526.280 1.000 ;
    END
  END m_o[1312]
  PIN m_o[1313]
    DIRECTION OUTPUT ;
    USE SIGNAL ;
    PORT
      LAYER Metal4 ;
        RECT 526.600 0.000 526.680 1.000 ;
    END
  END m_o[1313]
  PIN m_o[1314]
    DIRECTION OUTPUT ;
    USE SIGNAL ;
    PORT
      LAYER Metal4 ;
        RECT 527.000 0.000 527.080 1.000 ;
    END
  END m_o[1314]
  PIN m_o[1315]
    DIRECTION OUTPUT ;
    USE SIGNAL ;
    PORT
      LAYER Metal4 ;
        RECT 527.400 0.000 527.480 1.000 ;
    END
  END m_o[1315]
  PIN m_o[1316]
    DIRECTION OUTPUT ;
    USE SIGNAL ;
    PORT
      LAYER Metal4 ;
        RECT 527.800 0.000 527.880 1.000 ;
    END
  END m_o[1316]
  PIN m_o[1317]
    DIRECTION OUTPUT ;
    USE SIGNAL ;
    PORT
      LAYER Metal4 ;
        RECT 528.200 0.000 528.280 1.000 ;
    END
  END m_o[1317]
  PIN m_o[1318]
    DIRECTION OUTPUT ;
    USE SIGNAL ;
    PORT
      LAYER Metal4 ;
        RECT 528.600 0.000 528.680 1.000 ;
    END
  END m_o[1318]
  PIN m_o[1319]
    DIRECTION OUTPUT ;
    USE SIGNAL ;
    PORT
      LAYER Metal4 ;
        RECT 529.000 0.000 529.080 1.000 ;
    END
  END m_o[1319]
  PIN m_o[1320]
    DIRECTION OUTPUT ;
    USE SIGNAL ;
    PORT
      LAYER Metal4 ;
        RECT 529.400 0.000 529.480 1.000 ;
    END
  END m_o[1320]
  PIN m_o[1321]
    DIRECTION OUTPUT ;
    USE SIGNAL ;
    PORT
      LAYER Metal4 ;
        RECT 529.800 0.000 529.880 1.000 ;
    END
  END m_o[1321]
  PIN m_o[1322]
    DIRECTION OUTPUT ;
    USE SIGNAL ;
    PORT
      LAYER Metal4 ;
        RECT 530.200 0.000 530.280 1.000 ;
    END
  END m_o[1322]
  PIN m_o[1323]
    DIRECTION OUTPUT ;
    USE SIGNAL ;
    PORT
      LAYER Metal4 ;
        RECT 530.600 0.000 530.680 1.000 ;
    END
  END m_o[1323]
  PIN m_o[1324]
    DIRECTION OUTPUT ;
    USE SIGNAL ;
    PORT
      LAYER Metal4 ;
        RECT 531.000 0.000 531.080 1.000 ;
    END
  END m_o[1324]
  PIN m_o[1325]
    DIRECTION OUTPUT ;
    USE SIGNAL ;
    PORT
      LAYER Metal4 ;
        RECT 531.400 0.000 531.480 1.000 ;
    END
  END m_o[1325]
  PIN m_o[1326]
    DIRECTION OUTPUT ;
    USE SIGNAL ;
    PORT
      LAYER Metal4 ;
        RECT 531.800 0.000 531.880 1.000 ;
    END
  END m_o[1326]
  PIN m_o[1327]
    DIRECTION OUTPUT ;
    USE SIGNAL ;
    PORT
      LAYER Metal4 ;
        RECT 532.200 0.000 532.280 1.000 ;
    END
  END m_o[1327]
  PIN m_o[1328]
    DIRECTION OUTPUT ;
    USE SIGNAL ;
    PORT
      LAYER Metal4 ;
        RECT 532.600 0.000 532.680 1.000 ;
    END
  END m_o[1328]
  PIN m_o[1329]
    DIRECTION OUTPUT ;
    USE SIGNAL ;
    PORT
      LAYER Metal4 ;
        RECT 533.000 0.000 533.080 1.000 ;
    END
  END m_o[1329]
  PIN m_o[1330]
    DIRECTION OUTPUT ;
    USE SIGNAL ;
    PORT
      LAYER Metal4 ;
        RECT 533.400 0.000 533.480 1.000 ;
    END
  END m_o[1330]
  PIN m_o[1331]
    DIRECTION OUTPUT ;
    USE SIGNAL ;
    PORT
      LAYER Metal4 ;
        RECT 533.800 0.000 533.880 1.000 ;
    END
  END m_o[1331]
  PIN m_o[1332]
    DIRECTION OUTPUT ;
    USE SIGNAL ;
    PORT
      LAYER Metal4 ;
        RECT 534.200 0.000 534.280 1.000 ;
    END
  END m_o[1332]
  PIN m_o[1333]
    DIRECTION OUTPUT ;
    USE SIGNAL ;
    PORT
      LAYER Metal4 ;
        RECT 534.600 0.000 534.680 1.000 ;
    END
  END m_o[1333]
  PIN m_o[1334]
    DIRECTION OUTPUT ;
    USE SIGNAL ;
    PORT
      LAYER Metal4 ;
        RECT 535.000 0.000 535.080 1.000 ;
    END
  END m_o[1334]
  PIN m_o[1335]
    DIRECTION OUTPUT ;
    USE SIGNAL ;
    PORT
      LAYER Metal4 ;
        RECT 535.400 0.000 535.480 1.000 ;
    END
  END m_o[1335]
  PIN m_o[1336]
    DIRECTION OUTPUT ;
    USE SIGNAL ;
    PORT
      LAYER Metal4 ;
        RECT 535.800 0.000 535.880 1.000 ;
    END
  END m_o[1336]
  PIN m_o[1337]
    DIRECTION OUTPUT ;
    USE SIGNAL ;
    PORT
      LAYER Metal4 ;
        RECT 536.200 0.000 536.280 1.000 ;
    END
  END m_o[1337]
  PIN m_o[1338]
    DIRECTION OUTPUT ;
    USE SIGNAL ;
    PORT
      LAYER Metal4 ;
        RECT 536.600 0.000 536.680 1.000 ;
    END
  END m_o[1338]
  PIN m_o[1339]
    DIRECTION OUTPUT ;
    USE SIGNAL ;
    PORT
      LAYER Metal4 ;
        RECT 537.000 0.000 537.080 1.000 ;
    END
  END m_o[1339]
  PIN m_o[1340]
    DIRECTION OUTPUT ;
    USE SIGNAL ;
    PORT
      LAYER Metal4 ;
        RECT 537.400 0.000 537.480 1.000 ;
    END
  END m_o[1340]
  PIN m_o[1341]
    DIRECTION OUTPUT ;
    USE SIGNAL ;
    PORT
      LAYER Metal4 ;
        RECT 537.800 0.000 537.880 1.000 ;
    END
  END m_o[1341]
  PIN m_o[1342]
    DIRECTION OUTPUT ;
    USE SIGNAL ;
    PORT
      LAYER Metal4 ;
        RECT 538.200 0.000 538.280 1.000 ;
    END
  END m_o[1342]
  PIN m_o[1343]
    DIRECTION OUTPUT ;
    USE SIGNAL ;
    PORT
      LAYER Metal4 ;
        RECT 538.600 0.000 538.680 1.000 ;
    END
  END m_o[1343]
  PIN m_o[1344]
    DIRECTION OUTPUT ;
    USE SIGNAL ;
    PORT
      LAYER Metal4 ;
        RECT 539.000 0.000 539.080 1.000 ;
    END
  END m_o[1344]
  PIN m_o[1345]
    DIRECTION OUTPUT ;
    USE SIGNAL ;
    PORT
      LAYER Metal4 ;
        RECT 539.400 0.000 539.480 1.000 ;
    END
  END m_o[1345]
  PIN m_o[1346]
    DIRECTION OUTPUT ;
    USE SIGNAL ;
    PORT
      LAYER Metal4 ;
        RECT 539.800 0.000 539.880 1.000 ;
    END
  END m_o[1346]
  PIN m_o[1347]
    DIRECTION OUTPUT ;
    USE SIGNAL ;
    PORT
      LAYER Metal4 ;
        RECT 540.200 0.000 540.280 1.000 ;
    END
  END m_o[1347]
  PIN m_o[1348]
    DIRECTION OUTPUT ;
    USE SIGNAL ;
    PORT
      LAYER Metal4 ;
        RECT 540.600 0.000 540.680 1.000 ;
    END
  END m_o[1348]
  PIN m_o[1349]
    DIRECTION OUTPUT ;
    USE SIGNAL ;
    PORT
      LAYER Metal4 ;
        RECT 541.000 0.000 541.080 1.000 ;
    END
  END m_o[1349]
  PIN m_o[1350]
    DIRECTION OUTPUT ;
    USE SIGNAL ;
    PORT
      LAYER Metal4 ;
        RECT 541.400 0.000 541.480 1.000 ;
    END
  END m_o[1350]
  PIN m_o[1351]
    DIRECTION OUTPUT ;
    USE SIGNAL ;
    PORT
      LAYER Metal4 ;
        RECT 541.800 0.000 541.880 1.000 ;
    END
  END m_o[1351]
  PIN m_o[1352]
    DIRECTION OUTPUT ;
    USE SIGNAL ;
    PORT
      LAYER Metal4 ;
        RECT 542.200 0.000 542.280 1.000 ;
    END
  END m_o[1352]
  PIN m_o[1353]
    DIRECTION OUTPUT ;
    USE SIGNAL ;
    PORT
      LAYER Metal4 ;
        RECT 542.600 0.000 542.680 1.000 ;
    END
  END m_o[1353]
  PIN m_o[1354]
    DIRECTION OUTPUT ;
    USE SIGNAL ;
    PORT
      LAYER Metal4 ;
        RECT 543.000 0.000 543.080 1.000 ;
    END
  END m_o[1354]
  PIN m_o[1355]
    DIRECTION OUTPUT ;
    USE SIGNAL ;
    PORT
      LAYER Metal4 ;
        RECT 543.400 0.000 543.480 1.000 ;
    END
  END m_o[1355]
  PIN m_o[1356]
    DIRECTION OUTPUT ;
    USE SIGNAL ;
    PORT
      LAYER Metal4 ;
        RECT 543.800 0.000 543.880 1.000 ;
    END
  END m_o[1356]
  PIN m_o[1357]
    DIRECTION OUTPUT ;
    USE SIGNAL ;
    PORT
      LAYER Metal4 ;
        RECT 544.200 0.000 544.280 1.000 ;
    END
  END m_o[1357]
  PIN m_o[1358]
    DIRECTION OUTPUT ;
    USE SIGNAL ;
    PORT
      LAYER Metal4 ;
        RECT 544.600 0.000 544.680 1.000 ;
    END
  END m_o[1358]
  PIN m_o[1359]
    DIRECTION OUTPUT ;
    USE SIGNAL ;
    PORT
      LAYER Metal4 ;
        RECT 545.000 0.000 545.080 1.000 ;
    END
  END m_o[1359]
  PIN m_o[1360]
    DIRECTION OUTPUT ;
    USE SIGNAL ;
    PORT
      LAYER Metal4 ;
        RECT 545.400 0.000 545.480 1.000 ;
    END
  END m_o[1360]
  PIN m_o[1361]
    DIRECTION OUTPUT ;
    USE SIGNAL ;
    PORT
      LAYER Metal4 ;
        RECT 545.800 0.000 545.880 1.000 ;
    END
  END m_o[1361]
  PIN m_o[1362]
    DIRECTION OUTPUT ;
    USE SIGNAL ;
    PORT
      LAYER Metal4 ;
        RECT 546.200 0.000 546.280 1.000 ;
    END
  END m_o[1362]
  PIN m_o[1363]
    DIRECTION OUTPUT ;
    USE SIGNAL ;
    PORT
      LAYER Metal4 ;
        RECT 546.600 0.000 546.680 1.000 ;
    END
  END m_o[1363]
  PIN m_o[1364]
    DIRECTION OUTPUT ;
    USE SIGNAL ;
    PORT
      LAYER Metal4 ;
        RECT 547.000 0.000 547.080 1.000 ;
    END
  END m_o[1364]
  PIN m_o[1365]
    DIRECTION OUTPUT ;
    USE SIGNAL ;
    PORT
      LAYER Metal4 ;
        RECT 547.400 0.000 547.480 1.000 ;
    END
  END m_o[1365]
  PIN m_o[1366]
    DIRECTION OUTPUT ;
    USE SIGNAL ;
    PORT
      LAYER Metal4 ;
        RECT 547.800 0.000 547.880 1.000 ;
    END
  END m_o[1366]
  PIN m_o[1367]
    DIRECTION OUTPUT ;
    USE SIGNAL ;
    PORT
      LAYER Metal4 ;
        RECT 548.200 0.000 548.280 1.000 ;
    END
  END m_o[1367]
  PIN m_o[1368]
    DIRECTION OUTPUT ;
    USE SIGNAL ;
    PORT
      LAYER Metal4 ;
        RECT 548.600 0.000 548.680 1.000 ;
    END
  END m_o[1368]
  PIN m_o[1369]
    DIRECTION OUTPUT ;
    USE SIGNAL ;
    PORT
      LAYER Metal4 ;
        RECT 549.000 0.000 549.080 1.000 ;
    END
  END m_o[1369]
  PIN m_o[1370]
    DIRECTION OUTPUT ;
    USE SIGNAL ;
    PORT
      LAYER Metal4 ;
        RECT 549.400 0.000 549.480 1.000 ;
    END
  END m_o[1370]
  PIN m_o[1371]
    DIRECTION OUTPUT ;
    USE SIGNAL ;
    PORT
      LAYER Metal4 ;
        RECT 549.800 0.000 549.880 1.000 ;
    END
  END m_o[1371]
  PIN m_o[1372]
    DIRECTION OUTPUT ;
    USE SIGNAL ;
    PORT
      LAYER Metal4 ;
        RECT 550.200 0.000 550.280 1.000 ;
    END
  END m_o[1372]
  PIN m_o[1373]
    DIRECTION OUTPUT ;
    USE SIGNAL ;
    PORT
      LAYER Metal4 ;
        RECT 550.600 0.000 550.680 1.000 ;
    END
  END m_o[1373]
  PIN m_o[1374]
    DIRECTION OUTPUT ;
    USE SIGNAL ;
    PORT
      LAYER Metal4 ;
        RECT 551.000 0.000 551.080 1.000 ;
    END
  END m_o[1374]
  PIN m_o[1375]
    DIRECTION OUTPUT ;
    USE SIGNAL ;
    PORT
      LAYER Metal4 ;
        RECT 551.400 0.000 551.480 1.000 ;
    END
  END m_o[1375]
  PIN m_o[1376]
    DIRECTION OUTPUT ;
    USE SIGNAL ;
    PORT
      LAYER Metal4 ;
        RECT 551.800 0.000 551.880 1.000 ;
    END
  END m_o[1376]
  PIN m_o[1377]
    DIRECTION OUTPUT ;
    USE SIGNAL ;
    PORT
      LAYER Metal4 ;
        RECT 552.200 0.000 552.280 1.000 ;
    END
  END m_o[1377]
  PIN m_o[1378]
    DIRECTION OUTPUT ;
    USE SIGNAL ;
    PORT
      LAYER Metal4 ;
        RECT 552.600 0.000 552.680 1.000 ;
    END
  END m_o[1378]
  PIN m_o[1379]
    DIRECTION OUTPUT ;
    USE SIGNAL ;
    PORT
      LAYER Metal4 ;
        RECT 553.000 0.000 553.080 1.000 ;
    END
  END m_o[1379]
  PIN m_o[1380]
    DIRECTION OUTPUT ;
    USE SIGNAL ;
    PORT
      LAYER Metal4 ;
        RECT 553.400 0.000 553.480 1.000 ;
    END
  END m_o[1380]
  PIN m_o[1381]
    DIRECTION OUTPUT ;
    USE SIGNAL ;
    PORT
      LAYER Metal4 ;
        RECT 553.800 0.000 553.880 1.000 ;
    END
  END m_o[1381]
  PIN m_o[1382]
    DIRECTION OUTPUT ;
    USE SIGNAL ;
    PORT
      LAYER Metal4 ;
        RECT 554.200 0.000 554.280 1.000 ;
    END
  END m_o[1382]
  PIN m_o[1383]
    DIRECTION OUTPUT ;
    USE SIGNAL ;
    PORT
      LAYER Metal4 ;
        RECT 554.600 0.000 554.680 1.000 ;
    END
  END m_o[1383]
  PIN m_o[1384]
    DIRECTION OUTPUT ;
    USE SIGNAL ;
    PORT
      LAYER Metal4 ;
        RECT 555.000 0.000 555.080 1.000 ;
    END
  END m_o[1384]
  PIN m_o[1385]
    DIRECTION OUTPUT ;
    USE SIGNAL ;
    PORT
      LAYER Metal4 ;
        RECT 555.400 0.000 555.480 1.000 ;
    END
  END m_o[1385]
  PIN m_o[1386]
    DIRECTION OUTPUT ;
    USE SIGNAL ;
    PORT
      LAYER Metal4 ;
        RECT 555.800 0.000 555.880 1.000 ;
    END
  END m_o[1386]
  PIN m_o[1387]
    DIRECTION OUTPUT ;
    USE SIGNAL ;
    PORT
      LAYER Metal4 ;
        RECT 556.200 0.000 556.280 1.000 ;
    END
  END m_o[1387]
  PIN m_o[1388]
    DIRECTION OUTPUT ;
    USE SIGNAL ;
    PORT
      LAYER Metal4 ;
        RECT 556.600 0.000 556.680 1.000 ;
    END
  END m_o[1388]
  PIN m_o[1389]
    DIRECTION OUTPUT ;
    USE SIGNAL ;
    PORT
      LAYER Metal4 ;
        RECT 557.000 0.000 557.080 1.000 ;
    END
  END m_o[1389]
  PIN m_o[1390]
    DIRECTION OUTPUT ;
    USE SIGNAL ;
    PORT
      LAYER Metal4 ;
        RECT 557.400 0.000 557.480 1.000 ;
    END
  END m_o[1390]
  PIN m_o[1391]
    DIRECTION OUTPUT ;
    USE SIGNAL ;
    PORT
      LAYER Metal4 ;
        RECT 557.800 0.000 557.880 1.000 ;
    END
  END m_o[1391]
  PIN m_o[1392]
    DIRECTION OUTPUT ;
    USE SIGNAL ;
    PORT
      LAYER Metal4 ;
        RECT 558.200 0.000 558.280 1.000 ;
    END
  END m_o[1392]
  PIN m_o[1393]
    DIRECTION OUTPUT ;
    USE SIGNAL ;
    PORT
      LAYER Metal4 ;
        RECT 558.600 0.000 558.680 1.000 ;
    END
  END m_o[1393]
  PIN m_o[1394]
    DIRECTION OUTPUT ;
    USE SIGNAL ;
    PORT
      LAYER Metal4 ;
        RECT 559.000 0.000 559.080 1.000 ;
    END
  END m_o[1394]
  PIN m_o[1395]
    DIRECTION OUTPUT ;
    USE SIGNAL ;
    PORT
      LAYER Metal4 ;
        RECT 559.400 0.000 559.480 1.000 ;
    END
  END m_o[1395]
  PIN m_o[1396]
    DIRECTION OUTPUT ;
    USE SIGNAL ;
    PORT
      LAYER Metal4 ;
        RECT 559.800 0.000 559.880 1.000 ;
    END
  END m_o[1396]
  PIN m_o[1397]
    DIRECTION OUTPUT ;
    USE SIGNAL ;
    PORT
      LAYER Metal4 ;
        RECT 560.200 0.000 560.280 1.000 ;
    END
  END m_o[1397]
  PIN m_o[1398]
    DIRECTION OUTPUT ;
    USE SIGNAL ;
    PORT
      LAYER Metal4 ;
        RECT 560.600 0.000 560.680 1.000 ;
    END
  END m_o[1398]
  PIN m_o[1399]
    DIRECTION OUTPUT ;
    USE SIGNAL ;
    PORT
      LAYER Metal4 ;
        RECT 561.000 0.000 561.080 1.000 ;
    END
  END m_o[1399]
  PIN m_o[1400]
    DIRECTION OUTPUT ;
    USE SIGNAL ;
    PORT
      LAYER Metal4 ;
        RECT 561.400 0.000 561.480 1.000 ;
    END
  END m_o[1400]
  PIN m_o[1401]
    DIRECTION OUTPUT ;
    USE SIGNAL ;
    PORT
      LAYER Metal4 ;
        RECT 561.800 0.000 561.880 1.000 ;
    END
  END m_o[1401]
  PIN m_o[1402]
    DIRECTION OUTPUT ;
    USE SIGNAL ;
    PORT
      LAYER Metal4 ;
        RECT 562.200 0.000 562.280 1.000 ;
    END
  END m_o[1402]
  PIN m_o[1403]
    DIRECTION OUTPUT ;
    USE SIGNAL ;
    PORT
      LAYER Metal4 ;
        RECT 562.600 0.000 562.680 1.000 ;
    END
  END m_o[1403]
  PIN m_o[1404]
    DIRECTION OUTPUT ;
    USE SIGNAL ;
    PORT
      LAYER Metal4 ;
        RECT 563.000 0.000 563.080 1.000 ;
    END
  END m_o[1404]
  PIN m_o[1405]
    DIRECTION OUTPUT ;
    USE SIGNAL ;
    PORT
      LAYER Metal4 ;
        RECT 563.400 0.000 563.480 1.000 ;
    END
  END m_o[1405]
  PIN m_o[1406]
    DIRECTION OUTPUT ;
    USE SIGNAL ;
    PORT
      LAYER Metal4 ;
        RECT 563.800 0.000 563.880 1.000 ;
    END
  END m_o[1406]
  PIN m_o[1407]
    DIRECTION OUTPUT ;
    USE SIGNAL ;
    PORT
      LAYER Metal4 ;
        RECT 564.200 0.000 564.280 1.000 ;
    END
  END m_o[1407]
  PIN m_o[1408]
    DIRECTION OUTPUT ;
    USE SIGNAL ;
    PORT
      LAYER Metal4 ;
        RECT 564.600 0.000 564.680 1.000 ;
    END
  END m_o[1408]
  PIN m_o[1409]
    DIRECTION OUTPUT ;
    USE SIGNAL ;
    PORT
      LAYER Metal4 ;
        RECT 565.000 0.000 565.080 1.000 ;
    END
  END m_o[1409]
  PIN m_o[1410]
    DIRECTION OUTPUT ;
    USE SIGNAL ;
    PORT
      LAYER Metal4 ;
        RECT 565.400 0.000 565.480 1.000 ;
    END
  END m_o[1410]
  PIN m_o[1411]
    DIRECTION OUTPUT ;
    USE SIGNAL ;
    PORT
      LAYER Metal4 ;
        RECT 565.800 0.000 565.880 1.000 ;
    END
  END m_o[1411]
  PIN m_o[1412]
    DIRECTION OUTPUT ;
    USE SIGNAL ;
    PORT
      LAYER Metal4 ;
        RECT 566.200 0.000 566.280 1.000 ;
    END
  END m_o[1412]
  PIN m_o[1413]
    DIRECTION OUTPUT ;
    USE SIGNAL ;
    PORT
      LAYER Metal4 ;
        RECT 566.600 0.000 566.680 1.000 ;
    END
  END m_o[1413]
  PIN m_o[1414]
    DIRECTION OUTPUT ;
    USE SIGNAL ;
    PORT
      LAYER Metal4 ;
        RECT 567.000 0.000 567.080 1.000 ;
    END
  END m_o[1414]
  PIN m_o[1415]
    DIRECTION OUTPUT ;
    USE SIGNAL ;
    PORT
      LAYER Metal4 ;
        RECT 567.400 0.000 567.480 1.000 ;
    END
  END m_o[1415]
  PIN m_o[1416]
    DIRECTION OUTPUT ;
    USE SIGNAL ;
    PORT
      LAYER Metal4 ;
        RECT 567.800 0.000 567.880 1.000 ;
    END
  END m_o[1416]
  PIN m_o[1417]
    DIRECTION OUTPUT ;
    USE SIGNAL ;
    PORT
      LAYER Metal4 ;
        RECT 568.200 0.000 568.280 1.000 ;
    END
  END m_o[1417]
  PIN m_o[1418]
    DIRECTION OUTPUT ;
    USE SIGNAL ;
    PORT
      LAYER Metal4 ;
        RECT 568.600 0.000 568.680 1.000 ;
    END
  END m_o[1418]
  PIN m_o[1419]
    DIRECTION OUTPUT ;
    USE SIGNAL ;
    PORT
      LAYER Metal4 ;
        RECT 569.000 0.000 569.080 1.000 ;
    END
  END m_o[1419]
  PIN m_o[1420]
    DIRECTION OUTPUT ;
    USE SIGNAL ;
    PORT
      LAYER Metal4 ;
        RECT 569.400 0.000 569.480 1.000 ;
    END
  END m_o[1420]
  PIN m_o[1421]
    DIRECTION OUTPUT ;
    USE SIGNAL ;
    PORT
      LAYER Metal4 ;
        RECT 569.800 0.000 569.880 1.000 ;
    END
  END m_o[1421]
  PIN m_o[1422]
    DIRECTION OUTPUT ;
    USE SIGNAL ;
    PORT
      LAYER Metal4 ;
        RECT 570.200 0.000 570.280 1.000 ;
    END
  END m_o[1422]
  PIN m_o[1423]
    DIRECTION OUTPUT ;
    USE SIGNAL ;
    PORT
      LAYER Metal4 ;
        RECT 570.600 0.000 570.680 1.000 ;
    END
  END m_o[1423]
  PIN m_o[1424]
    DIRECTION OUTPUT ;
    USE SIGNAL ;
    PORT
      LAYER Metal4 ;
        RECT 571.000 0.000 571.080 1.000 ;
    END
  END m_o[1424]
  PIN m_o[1425]
    DIRECTION OUTPUT ;
    USE SIGNAL ;
    PORT
      LAYER Metal4 ;
        RECT 571.400 0.000 571.480 1.000 ;
    END
  END m_o[1425]
  PIN m_o[1426]
    DIRECTION OUTPUT ;
    USE SIGNAL ;
    PORT
      LAYER Metal4 ;
        RECT 571.800 0.000 571.880 1.000 ;
    END
  END m_o[1426]
  PIN m_o[1427]
    DIRECTION OUTPUT ;
    USE SIGNAL ;
    PORT
      LAYER Metal4 ;
        RECT 572.200 0.000 572.280 1.000 ;
    END
  END m_o[1427]
  PIN m_o[1428]
    DIRECTION OUTPUT ;
    USE SIGNAL ;
    PORT
      LAYER Metal4 ;
        RECT 572.600 0.000 572.680 1.000 ;
    END
  END m_o[1428]
  PIN m_o[1429]
    DIRECTION OUTPUT ;
    USE SIGNAL ;
    PORT
      LAYER Metal4 ;
        RECT 573.000 0.000 573.080 1.000 ;
    END
  END m_o[1429]
  PIN m_o[1430]
    DIRECTION OUTPUT ;
    USE SIGNAL ;
    PORT
      LAYER Metal4 ;
        RECT 573.400 0.000 573.480 1.000 ;
    END
  END m_o[1430]
  PIN m_o[1431]
    DIRECTION OUTPUT ;
    USE SIGNAL ;
    PORT
      LAYER Metal4 ;
        RECT 573.800 0.000 573.880 1.000 ;
    END
  END m_o[1431]
  PIN m_o[1432]
    DIRECTION OUTPUT ;
    USE SIGNAL ;
    PORT
      LAYER Metal4 ;
        RECT 574.200 0.000 574.280 1.000 ;
    END
  END m_o[1432]
  PIN m_o[1433]
    DIRECTION OUTPUT ;
    USE SIGNAL ;
    PORT
      LAYER Metal4 ;
        RECT 574.600 0.000 574.680 1.000 ;
    END
  END m_o[1433]
  PIN m_o[1434]
    DIRECTION OUTPUT ;
    USE SIGNAL ;
    PORT
      LAYER Metal4 ;
        RECT 575.000 0.000 575.080 1.000 ;
    END
  END m_o[1434]
  PIN m_o[1435]
    DIRECTION OUTPUT ;
    USE SIGNAL ;
    PORT
      LAYER Metal4 ;
        RECT 575.400 0.000 575.480 1.000 ;
    END
  END m_o[1435]
  PIN m_o[1436]
    DIRECTION OUTPUT ;
    USE SIGNAL ;
    PORT
      LAYER Metal4 ;
        RECT 575.800 0.000 575.880 1.000 ;
    END
  END m_o[1436]
  PIN m_o[1437]
    DIRECTION OUTPUT ;
    USE SIGNAL ;
    PORT
      LAYER Metal4 ;
        RECT 576.200 0.000 576.280 1.000 ;
    END
  END m_o[1437]
  PIN m_o[1438]
    DIRECTION OUTPUT ;
    USE SIGNAL ;
    PORT
      LAYER Metal4 ;
        RECT 576.600 0.000 576.680 1.000 ;
    END
  END m_o[1438]
  PIN m_o[1439]
    DIRECTION OUTPUT ;
    USE SIGNAL ;
    PORT
      LAYER Metal4 ;
        RECT 577.000 0.000 577.080 1.000 ;
    END
  END m_o[1439]
  PIN m_o[1440]
    DIRECTION OUTPUT ;
    USE SIGNAL ;
    PORT
      LAYER Metal4 ;
        RECT 577.400 0.000 577.480 1.000 ;
    END
  END m_o[1440]
  PIN m_o[1441]
    DIRECTION OUTPUT ;
    USE SIGNAL ;
    PORT
      LAYER Metal4 ;
        RECT 577.800 0.000 577.880 1.000 ;
    END
  END m_o[1441]
  PIN m_o[1442]
    DIRECTION OUTPUT ;
    USE SIGNAL ;
    PORT
      LAYER Metal4 ;
        RECT 578.200 0.000 578.280 1.000 ;
    END
  END m_o[1442]
  PIN m_o[1443]
    DIRECTION OUTPUT ;
    USE SIGNAL ;
    PORT
      LAYER Metal4 ;
        RECT 578.600 0.000 578.680 1.000 ;
    END
  END m_o[1443]
  PIN m_o[1444]
    DIRECTION OUTPUT ;
    USE SIGNAL ;
    PORT
      LAYER Metal4 ;
        RECT 579.000 0.000 579.080 1.000 ;
    END
  END m_o[1444]
  PIN m_o[1445]
    DIRECTION OUTPUT ;
    USE SIGNAL ;
    PORT
      LAYER Metal4 ;
        RECT 579.400 0.000 579.480 1.000 ;
    END
  END m_o[1445]
  PIN m_o[1446]
    DIRECTION OUTPUT ;
    USE SIGNAL ;
    PORT
      LAYER Metal4 ;
        RECT 579.800 0.000 579.880 1.000 ;
    END
  END m_o[1446]
  PIN m_o[1447]
    DIRECTION OUTPUT ;
    USE SIGNAL ;
    PORT
      LAYER Metal4 ;
        RECT 580.200 0.000 580.280 1.000 ;
    END
  END m_o[1447]
  PIN m_o[1448]
    DIRECTION OUTPUT ;
    USE SIGNAL ;
    PORT
      LAYER Metal4 ;
        RECT 580.600 0.000 580.680 1.000 ;
    END
  END m_o[1448]
  PIN m_o[1449]
    DIRECTION OUTPUT ;
    USE SIGNAL ;
    PORT
      LAYER Metal4 ;
        RECT 581.000 0.000 581.080 1.000 ;
    END
  END m_o[1449]
  PIN m_o[1450]
    DIRECTION OUTPUT ;
    USE SIGNAL ;
    PORT
      LAYER Metal4 ;
        RECT 581.400 0.000 581.480 1.000 ;
    END
  END m_o[1450]
  PIN m_o[1451]
    DIRECTION OUTPUT ;
    USE SIGNAL ;
    PORT
      LAYER Metal4 ;
        RECT 581.800 0.000 581.880 1.000 ;
    END
  END m_o[1451]
  PIN m_o[1452]
    DIRECTION OUTPUT ;
    USE SIGNAL ;
    PORT
      LAYER Metal4 ;
        RECT 582.200 0.000 582.280 1.000 ;
    END
  END m_o[1452]
  PIN m_o[1453]
    DIRECTION OUTPUT ;
    USE SIGNAL ;
    PORT
      LAYER Metal4 ;
        RECT 582.600 0.000 582.680 1.000 ;
    END
  END m_o[1453]
  PIN m_o[1454]
    DIRECTION OUTPUT ;
    USE SIGNAL ;
    PORT
      LAYER Metal4 ;
        RECT 583.000 0.000 583.080 1.000 ;
    END
  END m_o[1454]
  PIN m_o[1455]
    DIRECTION OUTPUT ;
    USE SIGNAL ;
    PORT
      LAYER Metal4 ;
        RECT 583.400 0.000 583.480 1.000 ;
    END
  END m_o[1455]
  PIN m_o[1456]
    DIRECTION OUTPUT ;
    USE SIGNAL ;
    PORT
      LAYER Metal4 ;
        RECT 583.800 0.000 583.880 1.000 ;
    END
  END m_o[1456]
  PIN m_o[1457]
    DIRECTION OUTPUT ;
    USE SIGNAL ;
    PORT
      LAYER Metal4 ;
        RECT 584.200 0.000 584.280 1.000 ;
    END
  END m_o[1457]
  PIN m_o[1458]
    DIRECTION OUTPUT ;
    USE SIGNAL ;
    PORT
      LAYER Metal4 ;
        RECT 584.600 0.000 584.680 1.000 ;
    END
  END m_o[1458]
  PIN m_o[1459]
    DIRECTION OUTPUT ;
    USE SIGNAL ;
    PORT
      LAYER Metal4 ;
        RECT 585.000 0.000 585.080 1.000 ;
    END
  END m_o[1459]
  PIN m_o[1460]
    DIRECTION OUTPUT ;
    USE SIGNAL ;
    PORT
      LAYER Metal4 ;
        RECT 585.400 0.000 585.480 1.000 ;
    END
  END m_o[1460]
  PIN m_o[1461]
    DIRECTION OUTPUT ;
    USE SIGNAL ;
    PORT
      LAYER Metal4 ;
        RECT 585.800 0.000 585.880 1.000 ;
    END
  END m_o[1461]
  PIN m_o[1462]
    DIRECTION OUTPUT ;
    USE SIGNAL ;
    PORT
      LAYER Metal4 ;
        RECT 586.200 0.000 586.280 1.000 ;
    END
  END m_o[1462]
  PIN m_o[1463]
    DIRECTION OUTPUT ;
    USE SIGNAL ;
    PORT
      LAYER Metal4 ;
        RECT 586.600 0.000 586.680 1.000 ;
    END
  END m_o[1463]
  PIN m_o[1464]
    DIRECTION OUTPUT ;
    USE SIGNAL ;
    PORT
      LAYER Metal4 ;
        RECT 587.000 0.000 587.080 1.000 ;
    END
  END m_o[1464]
  PIN m_o[1465]
    DIRECTION OUTPUT ;
    USE SIGNAL ;
    PORT
      LAYER Metal4 ;
        RECT 587.400 0.000 587.480 1.000 ;
    END
  END m_o[1465]
  PIN m_o[1466]
    DIRECTION OUTPUT ;
    USE SIGNAL ;
    PORT
      LAYER Metal4 ;
        RECT 587.800 0.000 587.880 1.000 ;
    END
  END m_o[1466]
  PIN m_o[1467]
    DIRECTION OUTPUT ;
    USE SIGNAL ;
    PORT
      LAYER Metal4 ;
        RECT 588.200 0.000 588.280 1.000 ;
    END
  END m_o[1467]
  PIN m_o[1468]
    DIRECTION OUTPUT ;
    USE SIGNAL ;
    PORT
      LAYER Metal4 ;
        RECT 588.600 0.000 588.680 1.000 ;
    END
  END m_o[1468]
  PIN m_o[1469]
    DIRECTION OUTPUT ;
    USE SIGNAL ;
    PORT
      LAYER Metal4 ;
        RECT 589.000 0.000 589.080 1.000 ;
    END
  END m_o[1469]
  PIN m_o[1470]
    DIRECTION OUTPUT ;
    USE SIGNAL ;
    PORT
      LAYER Metal4 ;
        RECT 589.400 0.000 589.480 1.000 ;
    END
  END m_o[1470]
  PIN m_o[1471]
    DIRECTION OUTPUT ;
    USE SIGNAL ;
    PORT
      LAYER Metal4 ;
        RECT 589.800 0.000 589.880 1.000 ;
    END
  END m_o[1471]
  PIN m_o[1472]
    DIRECTION OUTPUT ;
    USE SIGNAL ;
    PORT
      LAYER Metal4 ;
        RECT 590.200 0.000 590.280 1.000 ;
    END
  END m_o[1472]
  PIN m_o[1473]
    DIRECTION OUTPUT ;
    USE SIGNAL ;
    PORT
      LAYER Metal4 ;
        RECT 590.600 0.000 590.680 1.000 ;
    END
  END m_o[1473]
  PIN m_o[1474]
    DIRECTION OUTPUT ;
    USE SIGNAL ;
    PORT
      LAYER Metal4 ;
        RECT 591.000 0.000 591.080 1.000 ;
    END
  END m_o[1474]
  PIN m_o[1475]
    DIRECTION OUTPUT ;
    USE SIGNAL ;
    PORT
      LAYER Metal4 ;
        RECT 591.400 0.000 591.480 1.000 ;
    END
  END m_o[1475]
  PIN m_o[1476]
    DIRECTION OUTPUT ;
    USE SIGNAL ;
    PORT
      LAYER Metal4 ;
        RECT 591.800 0.000 591.880 1.000 ;
    END
  END m_o[1476]
  PIN m_o[1477]
    DIRECTION OUTPUT ;
    USE SIGNAL ;
    PORT
      LAYER Metal4 ;
        RECT 592.200 0.000 592.280 1.000 ;
    END
  END m_o[1477]
  PIN m_o[1478]
    DIRECTION OUTPUT ;
    USE SIGNAL ;
    PORT
      LAYER Metal4 ;
        RECT 592.600 0.000 592.680 1.000 ;
    END
  END m_o[1478]
  PIN m_o[1479]
    DIRECTION OUTPUT ;
    USE SIGNAL ;
    PORT
      LAYER Metal4 ;
        RECT 593.000 0.000 593.080 1.000 ;
    END
  END m_o[1479]
  PIN m_o[1480]
    DIRECTION OUTPUT ;
    USE SIGNAL ;
    PORT
      LAYER Metal4 ;
        RECT 593.400 0.000 593.480 1.000 ;
    END
  END m_o[1480]
  PIN m_o[1481]
    DIRECTION OUTPUT ;
    USE SIGNAL ;
    PORT
      LAYER Metal4 ;
        RECT 593.800 0.000 593.880 1.000 ;
    END
  END m_o[1481]
  PIN m_o[1482]
    DIRECTION OUTPUT ;
    USE SIGNAL ;
    PORT
      LAYER Metal4 ;
        RECT 594.200 0.000 594.280 1.000 ;
    END
  END m_o[1482]
  PIN m_o[1483]
    DIRECTION OUTPUT ;
    USE SIGNAL ;
    PORT
      LAYER Metal4 ;
        RECT 594.600 0.000 594.680 1.000 ;
    END
  END m_o[1483]
  PIN m_o[1484]
    DIRECTION OUTPUT ;
    USE SIGNAL ;
    PORT
      LAYER Metal4 ;
        RECT 595.000 0.000 595.080 1.000 ;
    END
  END m_o[1484]
  PIN m_o[1485]
    DIRECTION OUTPUT ;
    USE SIGNAL ;
    PORT
      LAYER Metal4 ;
        RECT 595.400 0.000 595.480 1.000 ;
    END
  END m_o[1485]
  PIN m_o[1486]
    DIRECTION OUTPUT ;
    USE SIGNAL ;
    PORT
      LAYER Metal4 ;
        RECT 595.800 0.000 595.880 1.000 ;
    END
  END m_o[1486]
  PIN m_o[1487]
    DIRECTION OUTPUT ;
    USE SIGNAL ;
    PORT
      LAYER Metal4 ;
        RECT 596.200 0.000 596.280 1.000 ;
    END
  END m_o[1487]
  PIN m_o[1488]
    DIRECTION OUTPUT ;
    USE SIGNAL ;
    PORT
      LAYER Metal4 ;
        RECT 596.600 0.000 596.680 1.000 ;
    END
  END m_o[1488]
  PIN m_o[1489]
    DIRECTION OUTPUT ;
    USE SIGNAL ;
    PORT
      LAYER Metal4 ;
        RECT 597.000 0.000 597.080 1.000 ;
    END
  END m_o[1489]
  PIN m_o[1490]
    DIRECTION OUTPUT ;
    USE SIGNAL ;
    PORT
      LAYER Metal4 ;
        RECT 597.400 0.000 597.480 1.000 ;
    END
  END m_o[1490]
  PIN m_o[1491]
    DIRECTION OUTPUT ;
    USE SIGNAL ;
    PORT
      LAYER Metal4 ;
        RECT 597.800 0.000 597.880 1.000 ;
    END
  END m_o[1491]
  PIN m_o[1492]
    DIRECTION OUTPUT ;
    USE SIGNAL ;
    PORT
      LAYER Metal4 ;
        RECT 598.200 0.000 598.280 1.000 ;
    END
  END m_o[1492]
  PIN m_o[1493]
    DIRECTION OUTPUT ;
    USE SIGNAL ;
    PORT
      LAYER Metal4 ;
        RECT 598.600 0.000 598.680 1.000 ;
    END
  END m_o[1493]
  PIN m_o[1494]
    DIRECTION OUTPUT ;
    USE SIGNAL ;
    PORT
      LAYER Metal4 ;
        RECT 599.000 0.000 599.080 1.000 ;
    END
  END m_o[1494]
  PIN m_o[1495]
    DIRECTION OUTPUT ;
    USE SIGNAL ;
    PORT
      LAYER Metal4 ;
        RECT 599.400 0.000 599.480 1.000 ;
    END
  END m_o[1495]
  PIN m_o[1496]
    DIRECTION OUTPUT ;
    USE SIGNAL ;
    PORT
      LAYER Metal4 ;
        RECT 599.800 0.000 599.880 1.000 ;
    END
  END m_o[1496]
  PIN m_o[1497]
    DIRECTION OUTPUT ;
    USE SIGNAL ;
    PORT
      LAYER Metal4 ;
        RECT 600.200 0.000 600.280 1.000 ;
    END
  END m_o[1497]
  PIN m_o[1498]
    DIRECTION OUTPUT ;
    USE SIGNAL ;
    PORT
      LAYER Metal4 ;
        RECT 600.600 0.000 600.680 1.000 ;
    END
  END m_o[1498]
  PIN m_o[1499]
    DIRECTION OUTPUT ;
    USE SIGNAL ;
    PORT
      LAYER Metal4 ;
        RECT 601.000 0.000 601.080 1.000 ;
    END
  END m_o[1499]
  PIN m_o[1500]
    DIRECTION OUTPUT ;
    USE SIGNAL ;
    PORT
      LAYER Metal4 ;
        RECT 601.400 0.000 601.480 1.000 ;
    END
  END m_o[1500]
  PIN m_o[1501]
    DIRECTION OUTPUT ;
    USE SIGNAL ;
    PORT
      LAYER Metal4 ;
        RECT 601.800 0.000 601.880 1.000 ;
    END
  END m_o[1501]
  PIN m_o[1502]
    DIRECTION OUTPUT ;
    USE SIGNAL ;
    PORT
      LAYER Metal4 ;
        RECT 602.200 0.000 602.280 1.000 ;
    END
  END m_o[1502]
  PIN m_o[1503]
    DIRECTION OUTPUT ;
    USE SIGNAL ;
    PORT
      LAYER Metal4 ;
        RECT 602.600 0.000 602.680 1.000 ;
    END
  END m_o[1503]
  PIN m_o[1504]
    DIRECTION OUTPUT ;
    USE SIGNAL ;
    PORT
      LAYER Metal4 ;
        RECT 603.000 0.000 603.080 1.000 ;
    END
  END m_o[1504]
  PIN m_o[1505]
    DIRECTION OUTPUT ;
    USE SIGNAL ;
    PORT
      LAYER Metal4 ;
        RECT 603.400 0.000 603.480 1.000 ;
    END
  END m_o[1505]
  PIN m_o[1506]
    DIRECTION OUTPUT ;
    USE SIGNAL ;
    PORT
      LAYER Metal4 ;
        RECT 603.800 0.000 603.880 1.000 ;
    END
  END m_o[1506]
  PIN m_o[1507]
    DIRECTION OUTPUT ;
    USE SIGNAL ;
    PORT
      LAYER Metal4 ;
        RECT 604.200 0.000 604.280 1.000 ;
    END
  END m_o[1507]
  PIN m_o[1508]
    DIRECTION OUTPUT ;
    USE SIGNAL ;
    PORT
      LAYER Metal4 ;
        RECT 604.600 0.000 604.680 1.000 ;
    END
  END m_o[1508]
  PIN m_o[1509]
    DIRECTION OUTPUT ;
    USE SIGNAL ;
    PORT
      LAYER Metal4 ;
        RECT 605.000 0.000 605.080 1.000 ;
    END
  END m_o[1509]
  PIN m_o[1510]
    DIRECTION OUTPUT ;
    USE SIGNAL ;
    PORT
      LAYER Metal4 ;
        RECT 605.400 0.000 605.480 1.000 ;
    END
  END m_o[1510]
  PIN m_o[1511]
    DIRECTION OUTPUT ;
    USE SIGNAL ;
    PORT
      LAYER Metal4 ;
        RECT 605.800 0.000 605.880 1.000 ;
    END
  END m_o[1511]
  PIN m_o[1512]
    DIRECTION OUTPUT ;
    USE SIGNAL ;
    PORT
      LAYER Metal4 ;
        RECT 606.200 0.000 606.280 1.000 ;
    END
  END m_o[1512]
  PIN m_o[1513]
    DIRECTION OUTPUT ;
    USE SIGNAL ;
    PORT
      LAYER Metal4 ;
        RECT 606.600 0.000 606.680 1.000 ;
    END
  END m_o[1513]
  PIN m_o[1514]
    DIRECTION OUTPUT ;
    USE SIGNAL ;
    PORT
      LAYER Metal4 ;
        RECT 607.000 0.000 607.080 1.000 ;
    END
  END m_o[1514]
  PIN m_o[1515]
    DIRECTION OUTPUT ;
    USE SIGNAL ;
    PORT
      LAYER Metal4 ;
        RECT 607.400 0.000 607.480 1.000 ;
    END
  END m_o[1515]
  PIN m_o[1516]
    DIRECTION OUTPUT ;
    USE SIGNAL ;
    PORT
      LAYER Metal4 ;
        RECT 607.800 0.000 607.880 1.000 ;
    END
  END m_o[1516]
  PIN m_o[1517]
    DIRECTION OUTPUT ;
    USE SIGNAL ;
    PORT
      LAYER Metal4 ;
        RECT 608.200 0.000 608.280 1.000 ;
    END
  END m_o[1517]
  PIN m_o[1518]
    DIRECTION OUTPUT ;
    USE SIGNAL ;
    PORT
      LAYER Metal4 ;
        RECT 608.600 0.000 608.680 1.000 ;
    END
  END m_o[1518]
  PIN m_o[1519]
    DIRECTION OUTPUT ;
    USE SIGNAL ;
    PORT
      LAYER Metal4 ;
        RECT 609.000 0.000 609.080 1.000 ;
    END
  END m_o[1519]
  PIN m_o[1520]
    DIRECTION OUTPUT ;
    USE SIGNAL ;
    PORT
      LAYER Metal4 ;
        RECT 609.400 0.000 609.480 1.000 ;
    END
  END m_o[1520]
  PIN m_o[1521]
    DIRECTION OUTPUT ;
    USE SIGNAL ;
    PORT
      LAYER Metal4 ;
        RECT 609.800 0.000 609.880 1.000 ;
    END
  END m_o[1521]
  PIN m_o[1522]
    DIRECTION OUTPUT ;
    USE SIGNAL ;
    PORT
      LAYER Metal4 ;
        RECT 610.200 0.000 610.280 1.000 ;
    END
  END m_o[1522]
  PIN m_o[1523]
    DIRECTION OUTPUT ;
    USE SIGNAL ;
    PORT
      LAYER Metal4 ;
        RECT 610.600 0.000 610.680 1.000 ;
    END
  END m_o[1523]
  PIN m_o[1524]
    DIRECTION OUTPUT ;
    USE SIGNAL ;
    PORT
      LAYER Metal4 ;
        RECT 611.000 0.000 611.080 1.000 ;
    END
  END m_o[1524]
  PIN m_o[1525]
    DIRECTION OUTPUT ;
    USE SIGNAL ;
    PORT
      LAYER Metal4 ;
        RECT 611.400 0.000 611.480 1.000 ;
    END
  END m_o[1525]
  PIN m_o[1526]
    DIRECTION OUTPUT ;
    USE SIGNAL ;
    PORT
      LAYER Metal4 ;
        RECT 611.800 0.000 611.880 1.000 ;
    END
  END m_o[1526]
  PIN m_o[1527]
    DIRECTION OUTPUT ;
    USE SIGNAL ;
    PORT
      LAYER Metal4 ;
        RECT 612.200 0.000 612.280 1.000 ;
    END
  END m_o[1527]
  PIN m_o[1528]
    DIRECTION OUTPUT ;
    USE SIGNAL ;
    PORT
      LAYER Metal4 ;
        RECT 612.600 0.000 612.680 1.000 ;
    END
  END m_o[1528]
  PIN m_o[1529]
    DIRECTION OUTPUT ;
    USE SIGNAL ;
    PORT
      LAYER Metal4 ;
        RECT 613.000 0.000 613.080 1.000 ;
    END
  END m_o[1529]
  PIN m_o[1530]
    DIRECTION OUTPUT ;
    USE SIGNAL ;
    PORT
      LAYER Metal4 ;
        RECT 613.400 0.000 613.480 1.000 ;
    END
  END m_o[1530]
  PIN m_o[1531]
    DIRECTION OUTPUT ;
    USE SIGNAL ;
    PORT
      LAYER Metal4 ;
        RECT 613.800 0.000 613.880 1.000 ;
    END
  END m_o[1531]
  PIN m_o[1532]
    DIRECTION OUTPUT ;
    USE SIGNAL ;
    PORT
      LAYER Metal4 ;
        RECT 614.200 0.000 614.280 1.000 ;
    END
  END m_o[1532]
  PIN m_o[1533]
    DIRECTION OUTPUT ;
    USE SIGNAL ;
    PORT
      LAYER Metal4 ;
        RECT 614.600 0.000 614.680 1.000 ;
    END
  END m_o[1533]
  PIN m_o[1534]
    DIRECTION OUTPUT ;
    USE SIGNAL ;
    PORT
      LAYER Metal4 ;
        RECT 615.000 0.000 615.080 1.000 ;
    END
  END m_o[1534]
  PIN m_o[1535]
    DIRECTION OUTPUT ;
    USE SIGNAL ;
    PORT
      LAYER Metal4 ;
        RECT 615.400 0.000 615.480 1.000 ;
    END
  END m_o[1535]
  PIN m_o[1536]
    DIRECTION OUTPUT ;
    USE SIGNAL ;
    PORT
      LAYER Metal4 ;
        RECT 615.800 0.000 615.880 1.000 ;
    END
  END m_o[1536]
  PIN m_o[1537]
    DIRECTION OUTPUT ;
    USE SIGNAL ;
    PORT
      LAYER Metal4 ;
        RECT 616.200 0.000 616.280 1.000 ;
    END
  END m_o[1537]
  PIN m_o[1538]
    DIRECTION OUTPUT ;
    USE SIGNAL ;
    PORT
      LAYER Metal4 ;
        RECT 616.600 0.000 616.680 1.000 ;
    END
  END m_o[1538]
  PIN m_o[1539]
    DIRECTION OUTPUT ;
    USE SIGNAL ;
    PORT
      LAYER Metal4 ;
        RECT 617.000 0.000 617.080 1.000 ;
    END
  END m_o[1539]
  PIN m_o[1540]
    DIRECTION OUTPUT ;
    USE SIGNAL ;
    PORT
      LAYER Metal4 ;
        RECT 617.400 0.000 617.480 1.000 ;
    END
  END m_o[1540]
  PIN m_o[1541]
    DIRECTION OUTPUT ;
    USE SIGNAL ;
    PORT
      LAYER Metal4 ;
        RECT 617.800 0.000 617.880 1.000 ;
    END
  END m_o[1541]
  PIN m_o[1542]
    DIRECTION OUTPUT ;
    USE SIGNAL ;
    PORT
      LAYER Metal4 ;
        RECT 618.200 0.000 618.280 1.000 ;
    END
  END m_o[1542]
  PIN m_o[1543]
    DIRECTION OUTPUT ;
    USE SIGNAL ;
    PORT
      LAYER Metal4 ;
        RECT 618.600 0.000 618.680 1.000 ;
    END
  END m_o[1543]
  PIN m_o[1544]
    DIRECTION OUTPUT ;
    USE SIGNAL ;
    PORT
      LAYER Metal4 ;
        RECT 619.000 0.000 619.080 1.000 ;
    END
  END m_o[1544]
  PIN m_o[1545]
    DIRECTION OUTPUT ;
    USE SIGNAL ;
    PORT
      LAYER Metal4 ;
        RECT 619.400 0.000 619.480 1.000 ;
    END
  END m_o[1545]
  PIN m_o[1546]
    DIRECTION OUTPUT ;
    USE SIGNAL ;
    PORT
      LAYER Metal4 ;
        RECT 619.800 0.000 619.880 1.000 ;
    END
  END m_o[1546]
  PIN m_o[1547]
    DIRECTION OUTPUT ;
    USE SIGNAL ;
    PORT
      LAYER Metal4 ;
        RECT 620.200 0.000 620.280 1.000 ;
    END
  END m_o[1547]
  PIN m_o[1548]
    DIRECTION OUTPUT ;
    USE SIGNAL ;
    PORT
      LAYER Metal4 ;
        RECT 620.600 0.000 620.680 1.000 ;
    END
  END m_o[1548]
  PIN m_o[1549]
    DIRECTION OUTPUT ;
    USE SIGNAL ;
    PORT
      LAYER Metal4 ;
        RECT 621.000 0.000 621.080 1.000 ;
    END
  END m_o[1549]
  PIN m_o[1550]
    DIRECTION OUTPUT ;
    USE SIGNAL ;
    PORT
      LAYER Metal4 ;
        RECT 621.400 0.000 621.480 1.000 ;
    END
  END m_o[1550]
  PIN m_o[1551]
    DIRECTION OUTPUT ;
    USE SIGNAL ;
    PORT
      LAYER Metal4 ;
        RECT 621.800 0.000 621.880 1.000 ;
    END
  END m_o[1551]
  PIN m_o[1552]
    DIRECTION OUTPUT ;
    USE SIGNAL ;
    PORT
      LAYER Metal4 ;
        RECT 622.200 0.000 622.280 1.000 ;
    END
  END m_o[1552]
  PIN m_o[1553]
    DIRECTION OUTPUT ;
    USE SIGNAL ;
    PORT
      LAYER Metal4 ;
        RECT 622.600 0.000 622.680 1.000 ;
    END
  END m_o[1553]
  PIN m_o[1554]
    DIRECTION OUTPUT ;
    USE SIGNAL ;
    PORT
      LAYER Metal4 ;
        RECT 623.000 0.000 623.080 1.000 ;
    END
  END m_o[1554]
  PIN m_o[1555]
    DIRECTION OUTPUT ;
    USE SIGNAL ;
    PORT
      LAYER Metal4 ;
        RECT 623.400 0.000 623.480 1.000 ;
    END
  END m_o[1555]
  PIN m_o[1556]
    DIRECTION OUTPUT ;
    USE SIGNAL ;
    PORT
      LAYER Metal4 ;
        RECT 623.800 0.000 623.880 1.000 ;
    END
  END m_o[1556]
  PIN m_o[1557]
    DIRECTION OUTPUT ;
    USE SIGNAL ;
    PORT
      LAYER Metal4 ;
        RECT 624.200 0.000 624.280 1.000 ;
    END
  END m_o[1557]
  PIN m_o[1558]
    DIRECTION OUTPUT ;
    USE SIGNAL ;
    PORT
      LAYER Metal4 ;
        RECT 624.600 0.000 624.680 1.000 ;
    END
  END m_o[1558]
  PIN m_o[1559]
    DIRECTION OUTPUT ;
    USE SIGNAL ;
    PORT
      LAYER Metal4 ;
        RECT 625.000 0.000 625.080 1.000 ;
    END
  END m_o[1559]
  PIN m_o[1560]
    DIRECTION OUTPUT ;
    USE SIGNAL ;
    PORT
      LAYER Metal4 ;
        RECT 625.400 0.000 625.480 1.000 ;
    END
  END m_o[1560]
  PIN m_o[1561]
    DIRECTION OUTPUT ;
    USE SIGNAL ;
    PORT
      LAYER Metal4 ;
        RECT 625.800 0.000 625.880 1.000 ;
    END
  END m_o[1561]
  PIN m_o[1562]
    DIRECTION OUTPUT ;
    USE SIGNAL ;
    PORT
      LAYER Metal4 ;
        RECT 626.200 0.000 626.280 1.000 ;
    END
  END m_o[1562]
  PIN m_o[1563]
    DIRECTION OUTPUT ;
    USE SIGNAL ;
    PORT
      LAYER Metal4 ;
        RECT 626.600 0.000 626.680 1.000 ;
    END
  END m_o[1563]
  PIN m_o[1564]
    DIRECTION OUTPUT ;
    USE SIGNAL ;
    PORT
      LAYER Metal4 ;
        RECT 627.000 0.000 627.080 1.000 ;
    END
  END m_o[1564]
  PIN m_o[1565]
    DIRECTION OUTPUT ;
    USE SIGNAL ;
    PORT
      LAYER Metal4 ;
        RECT 627.400 0.000 627.480 1.000 ;
    END
  END m_o[1565]
  PIN m_o[1566]
    DIRECTION OUTPUT ;
    USE SIGNAL ;
    PORT
      LAYER Metal4 ;
        RECT 627.800 0.000 627.880 1.000 ;
    END
  END m_o[1566]
  PIN m_o[1567]
    DIRECTION OUTPUT ;
    USE SIGNAL ;
    PORT
      LAYER Metal4 ;
        RECT 628.200 0.000 628.280 1.000 ;
    END
  END m_o[1567]
  PIN m_o[1568]
    DIRECTION OUTPUT ;
    USE SIGNAL ;
    PORT
      LAYER Metal4 ;
        RECT 628.600 0.000 628.680 1.000 ;
    END
  END m_o[1568]
  PIN m_o[1569]
    DIRECTION OUTPUT ;
    USE SIGNAL ;
    PORT
      LAYER Metal4 ;
        RECT 629.000 0.000 629.080 1.000 ;
    END
  END m_o[1569]
  PIN m_o[1570]
    DIRECTION OUTPUT ;
    USE SIGNAL ;
    PORT
      LAYER Metal4 ;
        RECT 629.400 0.000 629.480 1.000 ;
    END
  END m_o[1570]
  PIN m_o[1571]
    DIRECTION OUTPUT ;
    USE SIGNAL ;
    PORT
      LAYER Metal4 ;
        RECT 629.800 0.000 629.880 1.000 ;
    END
  END m_o[1571]
  PIN m_o[1572]
    DIRECTION OUTPUT ;
    USE SIGNAL ;
    PORT
      LAYER Metal4 ;
        RECT 630.200 0.000 630.280 1.000 ;
    END
  END m_o[1572]
  PIN m_o[1573]
    DIRECTION OUTPUT ;
    USE SIGNAL ;
    PORT
      LAYER Metal4 ;
        RECT 630.600 0.000 630.680 1.000 ;
    END
  END m_o[1573]
  PIN m_o[1574]
    DIRECTION OUTPUT ;
    USE SIGNAL ;
    PORT
      LAYER Metal4 ;
        RECT 631.000 0.000 631.080 1.000 ;
    END
  END m_o[1574]
  PIN m_o[1575]
    DIRECTION OUTPUT ;
    USE SIGNAL ;
    PORT
      LAYER Metal4 ;
        RECT 631.400 0.000 631.480 1.000 ;
    END
  END m_o[1575]
  PIN m_o[1576]
    DIRECTION OUTPUT ;
    USE SIGNAL ;
    PORT
      LAYER Metal4 ;
        RECT 631.800 0.000 631.880 1.000 ;
    END
  END m_o[1576]
  PIN m_o[1577]
    DIRECTION OUTPUT ;
    USE SIGNAL ;
    PORT
      LAYER Metal4 ;
        RECT 632.200 0.000 632.280 1.000 ;
    END
  END m_o[1577]
  PIN m_o[1578]
    DIRECTION OUTPUT ;
    USE SIGNAL ;
    PORT
      LAYER Metal4 ;
        RECT 632.600 0.000 632.680 1.000 ;
    END
  END m_o[1578]
  PIN m_o[1579]
    DIRECTION OUTPUT ;
    USE SIGNAL ;
    PORT
      LAYER Metal4 ;
        RECT 633.000 0.000 633.080 1.000 ;
    END
  END m_o[1579]
  PIN m_o[1580]
    DIRECTION OUTPUT ;
    USE SIGNAL ;
    PORT
      LAYER Metal4 ;
        RECT 633.400 0.000 633.480 1.000 ;
    END
  END m_o[1580]
  PIN m_o[1581]
    DIRECTION OUTPUT ;
    USE SIGNAL ;
    PORT
      LAYER Metal4 ;
        RECT 633.800 0.000 633.880 1.000 ;
    END
  END m_o[1581]
  PIN m_o[1582]
    DIRECTION OUTPUT ;
    USE SIGNAL ;
    PORT
      LAYER Metal4 ;
        RECT 634.200 0.000 634.280 1.000 ;
    END
  END m_o[1582]
  PIN m_o[1583]
    DIRECTION OUTPUT ;
    USE SIGNAL ;
    PORT
      LAYER Metal4 ;
        RECT 634.600 0.000 634.680 1.000 ;
    END
  END m_o[1583]
  PIN m_o[1584]
    DIRECTION OUTPUT ;
    USE SIGNAL ;
    PORT
      LAYER Metal4 ;
        RECT 635.000 0.000 635.080 1.000 ;
    END
  END m_o[1584]
  PIN m_o[1585]
    DIRECTION OUTPUT ;
    USE SIGNAL ;
    PORT
      LAYER Metal4 ;
        RECT 635.400 0.000 635.480 1.000 ;
    END
  END m_o[1585]
  PIN m_o[1586]
    DIRECTION OUTPUT ;
    USE SIGNAL ;
    PORT
      LAYER Metal4 ;
        RECT 635.800 0.000 635.880 1.000 ;
    END
  END m_o[1586]
  PIN m_o[1587]
    DIRECTION OUTPUT ;
    USE SIGNAL ;
    PORT
      LAYER Metal4 ;
        RECT 636.200 0.000 636.280 1.000 ;
    END
  END m_o[1587]
  PIN m_o[1588]
    DIRECTION OUTPUT ;
    USE SIGNAL ;
    PORT
      LAYER Metal4 ;
        RECT 636.600 0.000 636.680 1.000 ;
    END
  END m_o[1588]
  PIN m_o[1589]
    DIRECTION OUTPUT ;
    USE SIGNAL ;
    PORT
      LAYER Metal4 ;
        RECT 637.000 0.000 637.080 1.000 ;
    END
  END m_o[1589]
  PIN m_o[1590]
    DIRECTION OUTPUT ;
    USE SIGNAL ;
    PORT
      LAYER Metal4 ;
        RECT 637.400 0.000 637.480 1.000 ;
    END
  END m_o[1590]
  PIN m_o[1591]
    DIRECTION OUTPUT ;
    USE SIGNAL ;
    PORT
      LAYER Metal4 ;
        RECT 637.800 0.000 637.880 1.000 ;
    END
  END m_o[1591]
  PIN m_o[1592]
    DIRECTION OUTPUT ;
    USE SIGNAL ;
    PORT
      LAYER Metal4 ;
        RECT 638.200 0.000 638.280 1.000 ;
    END
  END m_o[1592]
  PIN m_o[1593]
    DIRECTION OUTPUT ;
    USE SIGNAL ;
    PORT
      LAYER Metal4 ;
        RECT 638.600 0.000 638.680 1.000 ;
    END
  END m_o[1593]
  PIN m_o[1594]
    DIRECTION OUTPUT ;
    USE SIGNAL ;
    PORT
      LAYER Metal4 ;
        RECT 639.000 0.000 639.080 1.000 ;
    END
  END m_o[1594]
  PIN m_o[1595]
    DIRECTION OUTPUT ;
    USE SIGNAL ;
    PORT
      LAYER Metal4 ;
        RECT 639.400 0.000 639.480 1.000 ;
    END
  END m_o[1595]
  PIN m_o[1596]
    DIRECTION OUTPUT ;
    USE SIGNAL ;
    PORT
      LAYER Metal4 ;
        RECT 639.800 0.000 639.880 1.000 ;
    END
  END m_o[1596]
  PIN m_o[1597]
    DIRECTION OUTPUT ;
    USE SIGNAL ;
    PORT
      LAYER Metal4 ;
        RECT 640.200 0.000 640.280 1.000 ;
    END
  END m_o[1597]
  PIN m_o[1598]
    DIRECTION OUTPUT ;
    USE SIGNAL ;
    PORT
      LAYER Metal4 ;
        RECT 640.600 0.000 640.680 1.000 ;
    END
  END m_o[1598]
  PIN m_o[1599]
    DIRECTION OUTPUT ;
    USE SIGNAL ;
    PORT
      LAYER Metal4 ;
        RECT 641.000 0.000 641.080 1.000 ;
    END
  END m_o[1599]
  PIN rst_n_i
    DIRECTION INPUT ;
    USE SIGNAL ;
    PORT
      LAYER Metal6 ;
        RECT 1.200 0.000 1.280 1.000 ;
    END
  END rst_n_i
  PIN wr_en_i
    DIRECTION INPUT ;
    USE SIGNAL ;
    PORT
      LAYER Metal6 ;
        RECT 1.600 0.000 1.680 1.000 ;
    END
  END wr_en_i
  PIN wr_macro_i[0]
    DIRECTION INPUT ;
    USE SIGNAL ;
    PORT
      LAYER Metal6 ;
        RECT 2.000 0.000 2.080 1.000 ;
    END
  END wr_macro_i[0]
  PIN wr_macro_i[1]
    DIRECTION INPUT ;
    USE SIGNAL ;
    PORT
      LAYER Metal6 ;
        RECT 2.400 0.000 2.480 1.000 ;
    END
  END wr_macro_i[1]
  PIN wr_macro_i[2]
    DIRECTION INPUT ;
    USE SIGNAL ;
    PORT
      LAYER Metal6 ;
        RECT 2.800 0.000 2.880 1.000 ;
    END
  END wr_macro_i[2]
  PIN wr_addr_i[0]
    DIRECTION INPUT ;
    USE SIGNAL ;
    PORT
      LAYER Metal6 ;
        RECT 3.200 0.000 3.280 1.000 ;
    END
  END wr_addr_i[0]
  PIN wr_addr_i[1]
    DIRECTION INPUT ;
    USE SIGNAL ;
    PORT
      LAYER Metal6 ;
        RECT 3.600 0.000 3.680 1.000 ;
    END
  END wr_addr_i[1]
  PIN wr_addr_i[2]
    DIRECTION INPUT ;
    USE SIGNAL ;
    PORT
      LAYER Metal6 ;
        RECT 4.000 0.000 4.080 1.000 ;
    END
  END wr_addr_i[2]
  PIN wr_addr_i[3]
    DIRECTION INPUT ;
    USE SIGNAL ;
    PORT
      LAYER Metal6 ;
        RECT 4.400 0.000 4.480 1.000 ;
    END
  END wr_addr_i[3]
  PIN wr_addr_i[4]
    DIRECTION INPUT ;
    USE SIGNAL ;
    PORT
      LAYER Metal6 ;
        RECT 4.800 0.000 4.880 1.000 ;
    END
  END wr_addr_i[4]
  PIN wr_addr_i[5]
    DIRECTION INPUT ;
    USE SIGNAL ;
    PORT
      LAYER Metal6 ;
        RECT 5.200 0.000 5.280 1.000 ;
    END
  END wr_addr_i[5]
  PIN wr_addr_i[6]
    DIRECTION INPUT ;
    USE SIGNAL ;
    PORT
      LAYER Metal6 ;
        RECT 5.600 0.000 5.680 1.000 ;
    END
  END wr_addr_i[6]
  PIN wr_addr_i[7]
    DIRECTION INPUT ;
    USE SIGNAL ;
    PORT
      LAYER Metal6 ;
        RECT 6.000 0.000 6.080 1.000 ;
    END
  END wr_addr_i[7]
  PIN wr_addr_i[8]
    DIRECTION INPUT ;
    USE SIGNAL ;
    PORT
      LAYER Metal6 ;
        RECT 6.400 0.000 6.480 1.000 ;
    END
  END wr_addr_i[8]
  PIN wr_data_i[0]
    DIRECTION INPUT ;
    USE SIGNAL ;
    PORT
      LAYER Metal6 ;
        RECT 6.800 0.000 6.880 1.000 ;
    END
  END wr_data_i[0]
  PIN wr_data_i[1]
    DIRECTION INPUT ;
    USE SIGNAL ;
    PORT
      LAYER Metal6 ;
        RECT 7.200 0.000 7.280 1.000 ;
    END
  END wr_data_i[1]
  PIN wr_data_i[2]
    DIRECTION INPUT ;
    USE SIGNAL ;
    PORT
      LAYER Metal6 ;
        RECT 7.600 0.000 7.680 1.000 ;
    END
  END wr_data_i[2]
  PIN wr_data_i[3]
    DIRECTION INPUT ;
    USE SIGNAL ;
    PORT
      LAYER Metal6 ;
        RECT 8.000 0.000 8.080 1.000 ;
    END
  END wr_data_i[3]
  PIN wr_data_i[4]
    DIRECTION INPUT ;
    USE SIGNAL ;
    PORT
      LAYER Metal6 ;
        RECT 8.400 0.000 8.480 1.000 ;
    END
  END wr_data_i[4]
  PIN wr_data_i[5]
    DIRECTION INPUT ;
    USE SIGNAL ;
    PORT
      LAYER Metal6 ;
        RECT 8.800 0.000 8.880 1.000 ;
    END
  END wr_data_i[5]
  PIN wr_data_i[6]
    DIRECTION INPUT ;
    USE SIGNAL ;
    PORT
      LAYER Metal6 ;
        RECT 9.200 0.000 9.280 1.000 ;
    END
  END wr_data_i[6]
  PIN wr_data_i[7]
    DIRECTION INPUT ;
    USE SIGNAL ;
    PORT
      LAYER Metal6 ;
        RECT 9.600 0.000 9.680 1.000 ;
    END
  END wr_data_i[7]
  PIN wr_data_i[8]
    DIRECTION INPUT ;
    USE SIGNAL ;
    PORT
      LAYER Metal6 ;
        RECT 10.000 0.000 10.080 1.000 ;
    END
  END wr_data_i[8]
  PIN wr_data_i[9]
    DIRECTION INPUT ;
    USE SIGNAL ;
    PORT
      LAYER Metal6 ;
        RECT 10.400 0.000 10.480 1.000 ;
    END
  END wr_data_i[9]
  PIN wr_data_i[10]
    DIRECTION INPUT ;
    USE SIGNAL ;
    PORT
      LAYER Metal6 ;
        RECT 10.800 0.000 10.880 1.000 ;
    END
  END wr_data_i[10]
  PIN wr_data_i[11]
    DIRECTION INPUT ;
    USE SIGNAL ;
    PORT
      LAYER Metal6 ;
        RECT 11.200 0.000 11.280 1.000 ;
    END
  END wr_data_i[11]
  PIN wr_data_i[12]
    DIRECTION INPUT ;
    USE SIGNAL ;
    PORT
      LAYER Metal6 ;
        RECT 11.600 0.000 11.680 1.000 ;
    END
  END wr_data_i[12]
  PIN wr_data_i[13]
    DIRECTION INPUT ;
    USE SIGNAL ;
    PORT
      LAYER Metal6 ;
        RECT 12.000 0.000 12.080 1.000 ;
    END
  END wr_data_i[13]
  PIN wr_data_i[14]
    DIRECTION INPUT ;
    USE SIGNAL ;
    PORT
      LAYER Metal6 ;
        RECT 12.400 0.000 12.480 1.000 ;
    END
  END wr_data_i[14]
  PIN wr_data_i[15]
    DIRECTION INPUT ;
    USE SIGNAL ;
    PORT
      LAYER Metal6 ;
        RECT 12.800 0.000 12.880 1.000 ;
    END
  END wr_data_i[15]
  PIN wr_data_i[16]
    DIRECTION INPUT ;
    USE SIGNAL ;
    PORT
      LAYER Metal6 ;
        RECT 13.200 0.000 13.280 1.000 ;
    END
  END wr_data_i[16]
  PIN wr_data_i[17]
    DIRECTION INPUT ;
    USE SIGNAL ;
    PORT
      LAYER Metal6 ;
        RECT 13.600 0.000 13.680 1.000 ;
    END
  END wr_data_i[17]
  PIN wr_data_i[18]
    DIRECTION INPUT ;
    USE SIGNAL ;
    PORT
      LAYER Metal6 ;
        RECT 14.000 0.000 14.080 1.000 ;
    END
  END wr_data_i[18]
  PIN wr_data_i[19]
    DIRECTION INPUT ;
    USE SIGNAL ;
    PORT
      LAYER Metal6 ;
        RECT 14.400 0.000 14.480 1.000 ;
    END
  END wr_data_i[19]
  PIN wr_data_i[20]
    DIRECTION INPUT ;
    USE SIGNAL ;
    PORT
      LAYER Metal6 ;
        RECT 14.800 0.000 14.880 1.000 ;
    END
  END wr_data_i[20]
  PIN wr_data_i[21]
    DIRECTION INPUT ;
    USE SIGNAL ;
    PORT
      LAYER Metal6 ;
        RECT 15.200 0.000 15.280 1.000 ;
    END
  END wr_data_i[21]
  PIN wr_data_i[22]
    DIRECTION INPUT ;
    USE SIGNAL ;
    PORT
      LAYER Metal6 ;
        RECT 15.600 0.000 15.680 1.000 ;
    END
  END wr_data_i[22]
  PIN wr_data_i[23]
    DIRECTION INPUT ;
    USE SIGNAL ;
    PORT
      LAYER Metal6 ;
        RECT 16.000 0.000 16.080 1.000 ;
    END
  END wr_data_i[23]
  PIN wr_data_i[24]
    DIRECTION INPUT ;
    USE SIGNAL ;
    PORT
      LAYER Metal6 ;
        RECT 16.400 0.000 16.480 1.000 ;
    END
  END wr_data_i[24]
  PIN wr_data_i[25]
    DIRECTION INPUT ;
    USE SIGNAL ;
    PORT
      LAYER Metal6 ;
        RECT 16.800 0.000 16.880 1.000 ;
    END
  END wr_data_i[25]
  PIN wr_data_i[26]
    DIRECTION INPUT ;
    USE SIGNAL ;
    PORT
      LAYER Metal6 ;
        RECT 17.200 0.000 17.280 1.000 ;
    END
  END wr_data_i[26]
  PIN wr_data_i[27]
    DIRECTION INPUT ;
    USE SIGNAL ;
    PORT
      LAYER Metal6 ;
        RECT 17.600 0.000 17.680 1.000 ;
    END
  END wr_data_i[27]
  PIN wr_data_i[28]
    DIRECTION INPUT ;
    USE SIGNAL ;
    PORT
      LAYER Metal6 ;
        RECT 18.000 0.000 18.080 1.000 ;
    END
  END wr_data_i[28]
  PIN wr_data_i[29]
    DIRECTION INPUT ;
    USE SIGNAL ;
    PORT
      LAYER Metal6 ;
        RECT 18.400 0.000 18.480 1.000 ;
    END
  END wr_data_i[29]
  PIN wr_data_i[30]
    DIRECTION INPUT ;
    USE SIGNAL ;
    PORT
      LAYER Metal6 ;
        RECT 18.800 0.000 18.880 1.000 ;
    END
  END wr_data_i[30]
  PIN wr_data_i[31]
    DIRECTION INPUT ;
    USE SIGNAL ;
    PORT
      LAYER Metal6 ;
        RECT 19.200 0.000 19.280 1.000 ;
    END
  END wr_data_i[31]
  PIN rd_valid_i
    DIRECTION INPUT ;
    USE SIGNAL ;
    PORT
      LAYER Metal6 ;
        RECT 19.600 0.000 19.680 1.000 ;
    END
  END rd_valid_i
  PIN rd_bitrow_i[0]
    DIRECTION INPUT ;
    USE SIGNAL ;
    PORT
      LAYER Metal6 ;
        RECT 20.000 0.000 20.080 1.000 ;
    END
  END rd_bitrow_i[0]
  PIN rd_bitrow_i[1]
    DIRECTION INPUT ;
    USE SIGNAL ;
    PORT
      LAYER Metal6 ;
        RECT 20.400 0.000 20.480 1.000 ;
    END
  END rd_bitrow_i[1]
  PIN rd_bitrow_i[2]
    DIRECTION INPUT ;
    USE SIGNAL ;
    PORT
      LAYER Metal6 ;
        RECT 20.800 0.000 20.880 1.000 ;
    END
  END rd_bitrow_i[2]
  PIN rd_bitrow_i[3]
    DIRECTION INPUT ;
    USE SIGNAL ;
    PORT
      LAYER Metal6 ;
        RECT 21.200 0.000 21.280 1.000 ;
    END
  END rd_bitrow_i[3]
  PIN rd_bitrow_i[4]
    DIRECTION INPUT ;
    USE SIGNAL ;
    PORT
      LAYER Metal6 ;
        RECT 21.600 0.000 21.680 1.000 ;
    END
  END rd_bitrow_i[4]
  PIN rd_bitrow_i[5]
    DIRECTION INPUT ;
    USE SIGNAL ;
    PORT
      LAYER Metal6 ;
        RECT 22.000 0.000 22.080 1.000 ;
    END
  END rd_bitrow_i[5]
  PIN rd_bitrow_i[6]
    DIRECTION INPUT ;
    USE SIGNAL ;
    PORT
      LAYER Metal6 ;
        RECT 22.400 0.000 22.480 1.000 ;
    END
  END rd_bitrow_i[6]
  PIN rd_bitrow_i[7]
    DIRECTION INPUT ;
    USE SIGNAL ;
    PORT
      LAYER Metal6 ;
        RECT 22.800 0.000 22.880 1.000 ;
    END
  END rd_bitrow_i[7]
  PIN rd_bitrow_i[8]
    DIRECTION INPUT ;
    USE SIGNAL ;
    PORT
      LAYER Metal6 ;
        RECT 23.200 0.000 23.280 1.000 ;
    END
  END rd_bitrow_i[8]
  PIN rd_bitrow_i[9]
    DIRECTION INPUT ;
    USE SIGNAL ;
    PORT
      LAYER Metal6 ;
        RECT 23.600 0.000 23.680 1.000 ;
    END
  END rd_bitrow_i[9]
  PIN rd_bitrow_i[10]
    DIRECTION INPUT ;
    USE SIGNAL ;
    PORT
      LAYER Metal6 ;
        RECT 24.000 0.000 24.080 1.000 ;
    END
  END rd_bitrow_i[10]
  PIN rd_bitrow_i[11]
    DIRECTION INPUT ;
    USE SIGNAL ;
    PORT
      LAYER Metal6 ;
        RECT 24.400 0.000 24.480 1.000 ;
    END
  END rd_bitrow_i[11]
  PIN rd_bitrow_i[12]
    DIRECTION INPUT ;
    USE SIGNAL ;
    PORT
      LAYER Metal6 ;
        RECT 24.800 0.000 24.880 1.000 ;
    END
  END rd_bitrow_i[12]
  PIN rd_bitrow_i[13]
    DIRECTION INPUT ;
    USE SIGNAL ;
    PORT
      LAYER Metal6 ;
        RECT 25.200 0.000 25.280 1.000 ;
    END
  END rd_bitrow_i[13]
  PIN rd_bitrow_i[14]
    DIRECTION INPUT ;
    USE SIGNAL ;
    PORT
      LAYER Metal6 ;
        RECT 25.600 0.000 25.680 1.000 ;
    END
  END rd_bitrow_i[14]
  PIN rd_bitrow_i[15]
    DIRECTION INPUT ;
    USE SIGNAL ;
    PORT
      LAYER Metal6 ;
        RECT 26.000 0.000 26.080 1.000 ;
    END
  END rd_bitrow_i[15]
  PIN rd_bitrow_i[16]
    DIRECTION INPUT ;
    USE SIGNAL ;
    PORT
      LAYER Metal6 ;
        RECT 26.400 0.000 26.480 1.000 ;
    END
  END rd_bitrow_i[16]
  PIN rd_bitrow_i[17]
    DIRECTION INPUT ;
    USE SIGNAL ;
    PORT
      LAYER Metal6 ;
        RECT 26.800 0.000 26.880 1.000 ;
    END
  END rd_bitrow_i[17]
  PIN rd_bitrow_i[18]
    DIRECTION INPUT ;
    USE SIGNAL ;
    PORT
      LAYER Metal6 ;
        RECT 27.200 0.000 27.280 1.000 ;
    END
  END rd_bitrow_i[18]
  PIN rd_bitrow_i[19]
    DIRECTION INPUT ;
    USE SIGNAL ;
    PORT
      LAYER Metal6 ;
        RECT 27.600 0.000 27.680 1.000 ;
    END
  END rd_bitrow_i[19]
  PIN rd_bitrow_i[20]
    DIRECTION INPUT ;
    USE SIGNAL ;
    PORT
      LAYER Metal6 ;
        RECT 28.000 0.000 28.080 1.000 ;
    END
  END rd_bitrow_i[20]
  PIN rd_bitrow_i[21]
    DIRECTION INPUT ;
    USE SIGNAL ;
    PORT
      LAYER Metal6 ;
        RECT 28.400 0.000 28.480 1.000 ;
    END
  END rd_bitrow_i[21]
  PIN rd_bitrow_i[22]
    DIRECTION INPUT ;
    USE SIGNAL ;
    PORT
      LAYER Metal6 ;
        RECT 28.800 0.000 28.880 1.000 ;
    END
  END rd_bitrow_i[22]
  PIN rd_bitrow_i[23]
    DIRECTION INPUT ;
    USE SIGNAL ;
    PORT
      LAYER Metal6 ;
        RECT 29.200 0.000 29.280 1.000 ;
    END
  END rd_bitrow_i[23]
  PIN rd_bitrow_i[24]
    DIRECTION INPUT ;
    USE SIGNAL ;
    PORT
      LAYER Metal6 ;
        RECT 29.600 0.000 29.680 1.000 ;
    END
  END rd_bitrow_i[24]
  PIN rd_bitrow_i[25]
    DIRECTION INPUT ;
    USE SIGNAL ;
    PORT
      LAYER Metal6 ;
        RECT 30.000 0.000 30.080 1.000 ;
    END
  END rd_bitrow_i[25]
  PIN rd_bitrow_i[26]
    DIRECTION INPUT ;
    USE SIGNAL ;
    PORT
      LAYER Metal6 ;
        RECT 30.400 0.000 30.480 1.000 ;
    END
  END rd_bitrow_i[26]
  PIN rd_bitrow_i[27]
    DIRECTION INPUT ;
    USE SIGNAL ;
    PORT
      LAYER Metal6 ;
        RECT 30.800 0.000 30.880 1.000 ;
    END
  END rd_bitrow_i[27]
  PIN rd_bitrow_i[28]
    DIRECTION INPUT ;
    USE SIGNAL ;
    PORT
      LAYER Metal6 ;
        RECT 31.200 0.000 31.280 1.000 ;
    END
  END rd_bitrow_i[28]
  PIN rd_bitrow_i[29]
    DIRECTION INPUT ;
    USE SIGNAL ;
    PORT
      LAYER Metal6 ;
        RECT 31.600 0.000 31.680 1.000 ;
    END
  END rd_bitrow_i[29]
  PIN rd_bitrow_i[30]
    DIRECTION INPUT ;
    USE SIGNAL ;
    PORT
      LAYER Metal6 ;
        RECT 32.000 0.000 32.080 1.000 ;
    END
  END rd_bitrow_i[30]
  PIN rd_bitrow_i[31]
    DIRECTION INPUT ;
    USE SIGNAL ;
    PORT
      LAYER Metal6 ;
        RECT 32.400 0.000 32.480 1.000 ;
    END
  END rd_bitrow_i[31]
  PIN rd_bitrow_i[32]
    DIRECTION INPUT ;
    USE SIGNAL ;
    PORT
      LAYER Metal6 ;
        RECT 32.800 0.000 32.880 1.000 ;
    END
  END rd_bitrow_i[32]
  PIN rd_bitrow_i[33]
    DIRECTION INPUT ;
    USE SIGNAL ;
    PORT
      LAYER Metal6 ;
        RECT 33.200 0.000 33.280 1.000 ;
    END
  END rd_bitrow_i[33]
  PIN rd_bitrow_i[34]
    DIRECTION INPUT ;
    USE SIGNAL ;
    PORT
      LAYER Metal6 ;
        RECT 33.600 0.000 33.680 1.000 ;
    END
  END rd_bitrow_i[34]
  PIN rd_bitrow_i[35]
    DIRECTION INPUT ;
    USE SIGNAL ;
    PORT
      LAYER Metal6 ;
        RECT 34.000 0.000 34.080 1.000 ;
    END
  END rd_bitrow_i[35]
  PIN rd_bitrow_i[36]
    DIRECTION INPUT ;
    USE SIGNAL ;
    PORT
      LAYER Metal6 ;
        RECT 34.400 0.000 34.480 1.000 ;
    END
  END rd_bitrow_i[36]
  PIN rd_bitrow_i[37]
    DIRECTION INPUT ;
    USE SIGNAL ;
    PORT
      LAYER Metal6 ;
        RECT 34.800 0.000 34.880 1.000 ;
    END
  END rd_bitrow_i[37]
  PIN rd_bitrow_i[38]
    DIRECTION INPUT ;
    USE SIGNAL ;
    PORT
      LAYER Metal6 ;
        RECT 35.200 0.000 35.280 1.000 ;
    END
  END rd_bitrow_i[38]
  PIN rd_bitrow_i[39]
    DIRECTION INPUT ;
    USE SIGNAL ;
    PORT
      LAYER Metal6 ;
        RECT 35.600 0.000 35.680 1.000 ;
    END
  END rd_bitrow_i[39]
  PIN rd_bitrow_i[40]
    DIRECTION INPUT ;
    USE SIGNAL ;
    PORT
      LAYER Metal6 ;
        RECT 36.000 0.000 36.080 1.000 ;
    END
  END rd_bitrow_i[40]
  PIN rd_bitrow_i[41]
    DIRECTION INPUT ;
    USE SIGNAL ;
    PORT
      LAYER Metal6 ;
        RECT 36.400 0.000 36.480 1.000 ;
    END
  END rd_bitrow_i[41]
  PIN rd_bitrow_i[42]
    DIRECTION INPUT ;
    USE SIGNAL ;
    PORT
      LAYER Metal6 ;
        RECT 36.800 0.000 36.880 1.000 ;
    END
  END rd_bitrow_i[42]
  PIN rd_bitrow_i[43]
    DIRECTION INPUT ;
    USE SIGNAL ;
    PORT
      LAYER Metal6 ;
        RECT 37.200 0.000 37.280 1.000 ;
    END
  END rd_bitrow_i[43]
  PIN rd_bitrow_i[44]
    DIRECTION INPUT ;
    USE SIGNAL ;
    PORT
      LAYER Metal6 ;
        RECT 37.600 0.000 37.680 1.000 ;
    END
  END rd_bitrow_i[44]
  PIN rd_bitrow_i[45]
    DIRECTION INPUT ;
    USE SIGNAL ;
    PORT
      LAYER Metal6 ;
        RECT 38.000 0.000 38.080 1.000 ;
    END
  END rd_bitrow_i[45]
  PIN rd_bitrow_i[46]
    DIRECTION INPUT ;
    USE SIGNAL ;
    PORT
      LAYER Metal6 ;
        RECT 38.400 0.000 38.480 1.000 ;
    END
  END rd_bitrow_i[46]
  PIN rd_bitrow_i[47]
    DIRECTION INPUT ;
    USE SIGNAL ;
    PORT
      LAYER Metal6 ;
        RECT 38.800 0.000 38.880 1.000 ;
    END
  END rd_bitrow_i[47]
  PIN rd_bitrow_i[48]
    DIRECTION INPUT ;
    USE SIGNAL ;
    PORT
      LAYER Metal6 ;
        RECT 39.200 0.000 39.280 1.000 ;
    END
  END rd_bitrow_i[48]
  PIN rd_bitrow_i[49]
    DIRECTION INPUT ;
    USE SIGNAL ;
    PORT
      LAYER Metal6 ;
        RECT 39.600 0.000 39.680 1.000 ;
    END
  END rd_bitrow_i[49]
  PIN rd_bitrow_i[50]
    DIRECTION INPUT ;
    USE SIGNAL ;
    PORT
      LAYER Metal6 ;
        RECT 40.000 0.000 40.080 1.000 ;
    END
  END rd_bitrow_i[50]
  PIN rd_bitrow_i[51]
    DIRECTION INPUT ;
    USE SIGNAL ;
    PORT
      LAYER Metal6 ;
        RECT 40.400 0.000 40.480 1.000 ;
    END
  END rd_bitrow_i[51]
  PIN rd_bitrow_i[52]
    DIRECTION INPUT ;
    USE SIGNAL ;
    PORT
      LAYER Metal6 ;
        RECT 40.800 0.000 40.880 1.000 ;
    END
  END rd_bitrow_i[52]
  PIN rd_bitrow_i[53]
    DIRECTION INPUT ;
    USE SIGNAL ;
    PORT
      LAYER Metal6 ;
        RECT 41.200 0.000 41.280 1.000 ;
    END
  END rd_bitrow_i[53]
  PIN rd_bitrow_i[54]
    DIRECTION INPUT ;
    USE SIGNAL ;
    PORT
      LAYER Metal6 ;
        RECT 41.600 0.000 41.680 1.000 ;
    END
  END rd_bitrow_i[54]
  PIN rd_bitrow_i[55]
    DIRECTION INPUT ;
    USE SIGNAL ;
    PORT
      LAYER Metal6 ;
        RECT 42.000 0.000 42.080 1.000 ;
    END
  END rd_bitrow_i[55]
  PIN rd_bitrow_i[56]
    DIRECTION INPUT ;
    USE SIGNAL ;
    PORT
      LAYER Metal6 ;
        RECT 42.400 0.000 42.480 1.000 ;
    END
  END rd_bitrow_i[56]
  PIN rd_bitrow_i[57]
    DIRECTION INPUT ;
    USE SIGNAL ;
    PORT
      LAYER Metal6 ;
        RECT 42.800 0.000 42.880 1.000 ;
    END
  END rd_bitrow_i[57]
  PIN rd_bitrow_i[58]
    DIRECTION INPUT ;
    USE SIGNAL ;
    PORT
      LAYER Metal6 ;
        RECT 43.200 0.000 43.280 1.000 ;
    END
  END rd_bitrow_i[58]
  PIN rd_bitrow_i[59]
    DIRECTION INPUT ;
    USE SIGNAL ;
    PORT
      LAYER Metal6 ;
        RECT 43.600 0.000 43.680 1.000 ;
    END
  END rd_bitrow_i[59]
  PIN rd_bitrow_i[60]
    DIRECTION INPUT ;
    USE SIGNAL ;
    PORT
      LAYER Metal6 ;
        RECT 44.000 0.000 44.080 1.000 ;
    END
  END rd_bitrow_i[60]
  PIN rd_bitrow_i[61]
    DIRECTION INPUT ;
    USE SIGNAL ;
    PORT
      LAYER Metal6 ;
        RECT 44.400 0.000 44.480 1.000 ;
    END
  END rd_bitrow_i[61]
  PIN rd_bitrow_i[62]
    DIRECTION INPUT ;
    USE SIGNAL ;
    PORT
      LAYER Metal6 ;
        RECT 44.800 0.000 44.880 1.000 ;
    END
  END rd_bitrow_i[62]
  PIN rd_bitrow_i[63]
    DIRECTION INPUT ;
    USE SIGNAL ;
    PORT
      LAYER Metal6 ;
        RECT 45.200 0.000 45.280 1.000 ;
    END
  END rd_bitrow_i[63]
  PIN rd_bitrow_i[64]
    DIRECTION INPUT ;
    USE SIGNAL ;
    PORT
      LAYER Metal6 ;
        RECT 45.600 0.000 45.680 1.000 ;
    END
  END rd_bitrow_i[64]
  PIN rd_bitrow_i[65]
    DIRECTION INPUT ;
    USE SIGNAL ;
    PORT
      LAYER Metal6 ;
        RECT 46.000 0.000 46.080 1.000 ;
    END
  END rd_bitrow_i[65]
  PIN rd_bitrow_i[66]
    DIRECTION INPUT ;
    USE SIGNAL ;
    PORT
      LAYER Metal6 ;
        RECT 46.400 0.000 46.480 1.000 ;
    END
  END rd_bitrow_i[66]
  PIN rd_bitrow_i[67]
    DIRECTION INPUT ;
    USE SIGNAL ;
    PORT
      LAYER Metal6 ;
        RECT 46.800 0.000 46.880 1.000 ;
    END
  END rd_bitrow_i[67]
  PIN rd_bitrow_i[68]
    DIRECTION INPUT ;
    USE SIGNAL ;
    PORT
      LAYER Metal6 ;
        RECT 47.200 0.000 47.280 1.000 ;
    END
  END rd_bitrow_i[68]
  PIN rd_bitrow_i[69]
    DIRECTION INPUT ;
    USE SIGNAL ;
    PORT
      LAYER Metal6 ;
        RECT 47.600 0.000 47.680 1.000 ;
    END
  END rd_bitrow_i[69]
  PIN rd_bitrow_i[70]
    DIRECTION INPUT ;
    USE SIGNAL ;
    PORT
      LAYER Metal6 ;
        RECT 48.000 0.000 48.080 1.000 ;
    END
  END rd_bitrow_i[70]
  PIN rd_bitrow_i[71]
    DIRECTION INPUT ;
    USE SIGNAL ;
    PORT
      LAYER Metal6 ;
        RECT 48.400 0.000 48.480 1.000 ;
    END
  END rd_bitrow_i[71]
  PIN rd_bitrow_i[72]
    DIRECTION INPUT ;
    USE SIGNAL ;
    PORT
      LAYER Metal6 ;
        RECT 48.800 0.000 48.880 1.000 ;
    END
  END rd_bitrow_i[72]
  PIN rd_bitrow_i[73]
    DIRECTION INPUT ;
    USE SIGNAL ;
    PORT
      LAYER Metal6 ;
        RECT 49.200 0.000 49.280 1.000 ;
    END
  END rd_bitrow_i[73]
  PIN rd_bitrow_i[74]
    DIRECTION INPUT ;
    USE SIGNAL ;
    PORT
      LAYER Metal6 ;
        RECT 49.600 0.000 49.680 1.000 ;
    END
  END rd_bitrow_i[74]
  PIN rd_bitrow_i[75]
    DIRECTION INPUT ;
    USE SIGNAL ;
    PORT
      LAYER Metal6 ;
        RECT 50.000 0.000 50.080 1.000 ;
    END
  END rd_bitrow_i[75]
  PIN rd_bitrow_i[76]
    DIRECTION INPUT ;
    USE SIGNAL ;
    PORT
      LAYER Metal6 ;
        RECT 50.400 0.000 50.480 1.000 ;
    END
  END rd_bitrow_i[76]
  PIN rd_bitrow_i[77]
    DIRECTION INPUT ;
    USE SIGNAL ;
    PORT
      LAYER Metal6 ;
        RECT 50.800 0.000 50.880 1.000 ;
    END
  END rd_bitrow_i[77]
  PIN rd_bitrow_i[78]
    DIRECTION INPUT ;
    USE SIGNAL ;
    PORT
      LAYER Metal6 ;
        RECT 51.200 0.000 51.280 1.000 ;
    END
  END rd_bitrow_i[78]
  PIN rd_bitrow_i[79]
    DIRECTION INPUT ;
    USE SIGNAL ;
    PORT
      LAYER Metal6 ;
        RECT 51.600 0.000 51.680 1.000 ;
    END
  END rd_bitrow_i[79]
  PIN rd_bitrow_i[80]
    DIRECTION INPUT ;
    USE SIGNAL ;
    PORT
      LAYER Metal6 ;
        RECT 52.000 0.000 52.080 1.000 ;
    END
  END rd_bitrow_i[80]
  PIN rd_bitrow_i[81]
    DIRECTION INPUT ;
    USE SIGNAL ;
    PORT
      LAYER Metal6 ;
        RECT 52.400 0.000 52.480 1.000 ;
    END
  END rd_bitrow_i[81]
  PIN rd_bitrow_i[82]
    DIRECTION INPUT ;
    USE SIGNAL ;
    PORT
      LAYER Metal6 ;
        RECT 52.800 0.000 52.880 1.000 ;
    END
  END rd_bitrow_i[82]
  PIN rd_bitrow_i[83]
    DIRECTION INPUT ;
    USE SIGNAL ;
    PORT
      LAYER Metal6 ;
        RECT 53.200 0.000 53.280 1.000 ;
    END
  END rd_bitrow_i[83]
  PIN rd_bitrow_i[84]
    DIRECTION INPUT ;
    USE SIGNAL ;
    PORT
      LAYER Metal6 ;
        RECT 53.600 0.000 53.680 1.000 ;
    END
  END rd_bitrow_i[84]
  PIN rd_bitrow_i[85]
    DIRECTION INPUT ;
    USE SIGNAL ;
    PORT
      LAYER Metal6 ;
        RECT 54.000 0.000 54.080 1.000 ;
    END
  END rd_bitrow_i[85]
  PIN rd_bitrow_i[86]
    DIRECTION INPUT ;
    USE SIGNAL ;
    PORT
      LAYER Metal6 ;
        RECT 54.400 0.000 54.480 1.000 ;
    END
  END rd_bitrow_i[86]
  PIN rd_bitrow_i[87]
    DIRECTION INPUT ;
    USE SIGNAL ;
    PORT
      LAYER Metal6 ;
        RECT 54.800 0.000 54.880 1.000 ;
    END
  END rd_bitrow_i[87]
  PIN rd_bitrow_i[88]
    DIRECTION INPUT ;
    USE SIGNAL ;
    PORT
      LAYER Metal6 ;
        RECT 55.200 0.000 55.280 1.000 ;
    END
  END rd_bitrow_i[88]
  PIN rd_bitrow_i[89]
    DIRECTION INPUT ;
    USE SIGNAL ;
    PORT
      LAYER Metal6 ;
        RECT 55.600 0.000 55.680 1.000 ;
    END
  END rd_bitrow_i[89]
  PIN rd_bitrow_i[90]
    DIRECTION INPUT ;
    USE SIGNAL ;
    PORT
      LAYER Metal6 ;
        RECT 56.000 0.000 56.080 1.000 ;
    END
  END rd_bitrow_i[90]
  PIN rd_bitrow_i[91]
    DIRECTION INPUT ;
    USE SIGNAL ;
    PORT
      LAYER Metal6 ;
        RECT 56.400 0.000 56.480 1.000 ;
    END
  END rd_bitrow_i[91]
  PIN rd_bitrow_i[92]
    DIRECTION INPUT ;
    USE SIGNAL ;
    PORT
      LAYER Metal6 ;
        RECT 56.800 0.000 56.880 1.000 ;
    END
  END rd_bitrow_i[92]
  PIN rd_bitrow_i[93]
    DIRECTION INPUT ;
    USE SIGNAL ;
    PORT
      LAYER Metal6 ;
        RECT 57.200 0.000 57.280 1.000 ;
    END
  END rd_bitrow_i[93]
  PIN rd_bitrow_i[94]
    DIRECTION INPUT ;
    USE SIGNAL ;
    PORT
      LAYER Metal6 ;
        RECT 57.600 0.000 57.680 1.000 ;
    END
  END rd_bitrow_i[94]
  PIN rd_bitrow_i[95]
    DIRECTION INPUT ;
    USE SIGNAL ;
    PORT
      LAYER Metal6 ;
        RECT 58.000 0.000 58.080 1.000 ;
    END
  END rd_bitrow_i[95]
  PIN rd_bitrow_i[96]
    DIRECTION INPUT ;
    USE SIGNAL ;
    PORT
      LAYER Metal6 ;
        RECT 58.400 0.000 58.480 1.000 ;
    END
  END rd_bitrow_i[96]
  PIN rd_bitrow_i[97]
    DIRECTION INPUT ;
    USE SIGNAL ;
    PORT
      LAYER Metal6 ;
        RECT 58.800 0.000 58.880 1.000 ;
    END
  END rd_bitrow_i[97]
  PIN rd_bitrow_i[98]
    DIRECTION INPUT ;
    USE SIGNAL ;
    PORT
      LAYER Metal6 ;
        RECT 59.200 0.000 59.280 1.000 ;
    END
  END rd_bitrow_i[98]
  PIN rd_bitrow_i[99]
    DIRECTION INPUT ;
    USE SIGNAL ;
    PORT
      LAYER Metal6 ;
        RECT 59.600 0.000 59.680 1.000 ;
    END
  END rd_bitrow_i[99]
  PIN rd_bitrow_i[100]
    DIRECTION INPUT ;
    USE SIGNAL ;
    PORT
      LAYER Metal6 ;
        RECT 60.000 0.000 60.080 1.000 ;
    END
  END rd_bitrow_i[100]
  PIN rd_bitrow_i[101]
    DIRECTION INPUT ;
    USE SIGNAL ;
    PORT
      LAYER Metal6 ;
        RECT 60.400 0.000 60.480 1.000 ;
    END
  END rd_bitrow_i[101]
  PIN rd_bitrow_i[102]
    DIRECTION INPUT ;
    USE SIGNAL ;
    PORT
      LAYER Metal6 ;
        RECT 60.800 0.000 60.880 1.000 ;
    END
  END rd_bitrow_i[102]
  PIN rd_bitrow_i[103]
    DIRECTION INPUT ;
    USE SIGNAL ;
    PORT
      LAYER Metal6 ;
        RECT 61.200 0.000 61.280 1.000 ;
    END
  END rd_bitrow_i[103]
  PIN rd_bitrow_i[104]
    DIRECTION INPUT ;
    USE SIGNAL ;
    PORT
      LAYER Metal6 ;
        RECT 61.600 0.000 61.680 1.000 ;
    END
  END rd_bitrow_i[104]
  PIN rd_bitrow_i[105]
    DIRECTION INPUT ;
    USE SIGNAL ;
    PORT
      LAYER Metal6 ;
        RECT 62.000 0.000 62.080 1.000 ;
    END
  END rd_bitrow_i[105]
  PIN rd_bitrow_i[106]
    DIRECTION INPUT ;
    USE SIGNAL ;
    PORT
      LAYER Metal6 ;
        RECT 62.400 0.000 62.480 1.000 ;
    END
  END rd_bitrow_i[106]
  PIN rd_bitrow_i[107]
    DIRECTION INPUT ;
    USE SIGNAL ;
    PORT
      LAYER Metal6 ;
        RECT 62.800 0.000 62.880 1.000 ;
    END
  END rd_bitrow_i[107]
  PIN rd_bitrow_i[108]
    DIRECTION INPUT ;
    USE SIGNAL ;
    PORT
      LAYER Metal6 ;
        RECT 63.200 0.000 63.280 1.000 ;
    END
  END rd_bitrow_i[108]
  PIN rd_bitrow_i[109]
    DIRECTION INPUT ;
    USE SIGNAL ;
    PORT
      LAYER Metal6 ;
        RECT 63.600 0.000 63.680 1.000 ;
    END
  END rd_bitrow_i[109]
  PIN rd_bitrow_i[110]
    DIRECTION INPUT ;
    USE SIGNAL ;
    PORT
      LAYER Metal6 ;
        RECT 64.000 0.000 64.080 1.000 ;
    END
  END rd_bitrow_i[110]
  PIN rd_bitrow_i[111]
    DIRECTION INPUT ;
    USE SIGNAL ;
    PORT
      LAYER Metal6 ;
        RECT 64.400 0.000 64.480 1.000 ;
    END
  END rd_bitrow_i[111]
  PIN rd_bitrow_i[112]
    DIRECTION INPUT ;
    USE SIGNAL ;
    PORT
      LAYER Metal6 ;
        RECT 64.800 0.000 64.880 1.000 ;
    END
  END rd_bitrow_i[112]
  PIN rd_bitrow_i[113]
    DIRECTION INPUT ;
    USE SIGNAL ;
    PORT
      LAYER Metal6 ;
        RECT 65.200 0.000 65.280 1.000 ;
    END
  END rd_bitrow_i[113]
  PIN rd_bitrow_i[114]
    DIRECTION INPUT ;
    USE SIGNAL ;
    PORT
      LAYER Metal6 ;
        RECT 65.600 0.000 65.680 1.000 ;
    END
  END rd_bitrow_i[114]
  PIN rd_bitrow_i[115]
    DIRECTION INPUT ;
    USE SIGNAL ;
    PORT
      LAYER Metal6 ;
        RECT 66.000 0.000 66.080 1.000 ;
    END
  END rd_bitrow_i[115]
  PIN rd_bitrow_i[116]
    DIRECTION INPUT ;
    USE SIGNAL ;
    PORT
      LAYER Metal6 ;
        RECT 66.400 0.000 66.480 1.000 ;
    END
  END rd_bitrow_i[116]
  PIN rd_bitrow_i[117]
    DIRECTION INPUT ;
    USE SIGNAL ;
    PORT
      LAYER Metal6 ;
        RECT 66.800 0.000 66.880 1.000 ;
    END
  END rd_bitrow_i[117]
  PIN rd_bitrow_i[118]
    DIRECTION INPUT ;
    USE SIGNAL ;
    PORT
      LAYER Metal6 ;
        RECT 67.200 0.000 67.280 1.000 ;
    END
  END rd_bitrow_i[118]
  PIN rd_bitrow_i[119]
    DIRECTION INPUT ;
    USE SIGNAL ;
    PORT
      LAYER Metal6 ;
        RECT 67.600 0.000 67.680 1.000 ;
    END
  END rd_bitrow_i[119]
  PIN rd_bitrow_i[120]
    DIRECTION INPUT ;
    USE SIGNAL ;
    PORT
      LAYER Metal6 ;
        RECT 68.000 0.000 68.080 1.000 ;
    END
  END rd_bitrow_i[120]
  PIN rd_bitrow_i[121]
    DIRECTION INPUT ;
    USE SIGNAL ;
    PORT
      LAYER Metal6 ;
        RECT 68.400 0.000 68.480 1.000 ;
    END
  END rd_bitrow_i[121]
  PIN rd_bitrow_i[122]
    DIRECTION INPUT ;
    USE SIGNAL ;
    PORT
      LAYER Metal6 ;
        RECT 68.800 0.000 68.880 1.000 ;
    END
  END rd_bitrow_i[122]
  PIN rd_bitrow_i[123]
    DIRECTION INPUT ;
    USE SIGNAL ;
    PORT
      LAYER Metal6 ;
        RECT 69.200 0.000 69.280 1.000 ;
    END
  END rd_bitrow_i[123]
  PIN rd_bitrow_i[124]
    DIRECTION INPUT ;
    USE SIGNAL ;
    PORT
      LAYER Metal6 ;
        RECT 69.600 0.000 69.680 1.000 ;
    END
  END rd_bitrow_i[124]
  PIN rd_bitrow_i[125]
    DIRECTION INPUT ;
    USE SIGNAL ;
    PORT
      LAYER Metal6 ;
        RECT 70.000 0.000 70.080 1.000 ;
    END
  END rd_bitrow_i[125]
  PIN rd_bitrow_i[126]
    DIRECTION INPUT ;
    USE SIGNAL ;
    PORT
      LAYER Metal6 ;
        RECT 70.400 0.000 70.480 1.000 ;
    END
  END rd_bitrow_i[126]
  PIN rd_bitrow_i[127]
    DIRECTION INPUT ;
    USE SIGNAL ;
    PORT
      LAYER Metal6 ;
        RECT 70.800 0.000 70.880 1.000 ;
    END
  END rd_bitrow_i[127]
  PIN rd_bitrow_i[128]
    DIRECTION INPUT ;
    USE SIGNAL ;
    PORT
      LAYER Metal6 ;
        RECT 71.200 0.000 71.280 1.000 ;
    END
  END rd_bitrow_i[128]
  PIN rd_bitrow_i[129]
    DIRECTION INPUT ;
    USE SIGNAL ;
    PORT
      LAYER Metal6 ;
        RECT 71.600 0.000 71.680 1.000 ;
    END
  END rd_bitrow_i[129]
  PIN rd_bitrow_i[130]
    DIRECTION INPUT ;
    USE SIGNAL ;
    PORT
      LAYER Metal6 ;
        RECT 72.000 0.000 72.080 1.000 ;
    END
  END rd_bitrow_i[130]
  PIN rd_bitrow_i[131]
    DIRECTION INPUT ;
    USE SIGNAL ;
    PORT
      LAYER Metal6 ;
        RECT 72.400 0.000 72.480 1.000 ;
    END
  END rd_bitrow_i[131]
  PIN rd_bitrow_i[132]
    DIRECTION INPUT ;
    USE SIGNAL ;
    PORT
      LAYER Metal6 ;
        RECT 72.800 0.000 72.880 1.000 ;
    END
  END rd_bitrow_i[132]
  PIN rd_bitrow_i[133]
    DIRECTION INPUT ;
    USE SIGNAL ;
    PORT
      LAYER Metal6 ;
        RECT 73.200 0.000 73.280 1.000 ;
    END
  END rd_bitrow_i[133]
  PIN rd_bitrow_i[134]
    DIRECTION INPUT ;
    USE SIGNAL ;
    PORT
      LAYER Metal6 ;
        RECT 73.600 0.000 73.680 1.000 ;
    END
  END rd_bitrow_i[134]
  PIN rd_bitrow_i[135]
    DIRECTION INPUT ;
    USE SIGNAL ;
    PORT
      LAYER Metal6 ;
        RECT 74.000 0.000 74.080 1.000 ;
    END
  END rd_bitrow_i[135]
  PIN rd_bitrow_i[136]
    DIRECTION INPUT ;
    USE SIGNAL ;
    PORT
      LAYER Metal6 ;
        RECT 74.400 0.000 74.480 1.000 ;
    END
  END rd_bitrow_i[136]
  PIN rd_bitrow_i[137]
    DIRECTION INPUT ;
    USE SIGNAL ;
    PORT
      LAYER Metal6 ;
        RECT 74.800 0.000 74.880 1.000 ;
    END
  END rd_bitrow_i[137]
  PIN rd_bitrow_i[138]
    DIRECTION INPUT ;
    USE SIGNAL ;
    PORT
      LAYER Metal6 ;
        RECT 75.200 0.000 75.280 1.000 ;
    END
  END rd_bitrow_i[138]
  PIN rd_bitrow_i[139]
    DIRECTION INPUT ;
    USE SIGNAL ;
    PORT
      LAYER Metal6 ;
        RECT 75.600 0.000 75.680 1.000 ;
    END
  END rd_bitrow_i[139]
  PIN rd_bitrow_i[140]
    DIRECTION INPUT ;
    USE SIGNAL ;
    PORT
      LAYER Metal6 ;
        RECT 76.000 0.000 76.080 1.000 ;
    END
  END rd_bitrow_i[140]
  PIN rd_bitrow_i[141]
    DIRECTION INPUT ;
    USE SIGNAL ;
    PORT
      LAYER Metal6 ;
        RECT 76.400 0.000 76.480 1.000 ;
    END
  END rd_bitrow_i[141]
  PIN rd_bitrow_i[142]
    DIRECTION INPUT ;
    USE SIGNAL ;
    PORT
      LAYER Metal6 ;
        RECT 76.800 0.000 76.880 1.000 ;
    END
  END rd_bitrow_i[142]
  PIN rd_bitrow_i[143]
    DIRECTION INPUT ;
    USE SIGNAL ;
    PORT
      LAYER Metal6 ;
        RECT 77.200 0.000 77.280 1.000 ;
    END
  END rd_bitrow_i[143]
  PIN rd_bitrow_i[144]
    DIRECTION INPUT ;
    USE SIGNAL ;
    PORT
      LAYER Metal6 ;
        RECT 77.600 0.000 77.680 1.000 ;
    END
  END rd_bitrow_i[144]
  PIN rd_bitrow_i[145]
    DIRECTION INPUT ;
    USE SIGNAL ;
    PORT
      LAYER Metal6 ;
        RECT 78.000 0.000 78.080 1.000 ;
    END
  END rd_bitrow_i[145]
  PIN rd_bitrow_i[146]
    DIRECTION INPUT ;
    USE SIGNAL ;
    PORT
      LAYER Metal6 ;
        RECT 78.400 0.000 78.480 1.000 ;
    END
  END rd_bitrow_i[146]
  PIN rd_bitrow_i[147]
    DIRECTION INPUT ;
    USE SIGNAL ;
    PORT
      LAYER Metal6 ;
        RECT 78.800 0.000 78.880 1.000 ;
    END
  END rd_bitrow_i[147]
  PIN rd_bitrow_i[148]
    DIRECTION INPUT ;
    USE SIGNAL ;
    PORT
      LAYER Metal6 ;
        RECT 79.200 0.000 79.280 1.000 ;
    END
  END rd_bitrow_i[148]
  PIN rd_bitrow_i[149]
    DIRECTION INPUT ;
    USE SIGNAL ;
    PORT
      LAYER Metal6 ;
        RECT 79.600 0.000 79.680 1.000 ;
    END
  END rd_bitrow_i[149]
  PIN rd_bitrow_i[150]
    DIRECTION INPUT ;
    USE SIGNAL ;
    PORT
      LAYER Metal6 ;
        RECT 80.000 0.000 80.080 1.000 ;
    END
  END rd_bitrow_i[150]
  PIN rd_bitrow_i[151]
    DIRECTION INPUT ;
    USE SIGNAL ;
    PORT
      LAYER Metal6 ;
        RECT 80.400 0.000 80.480 1.000 ;
    END
  END rd_bitrow_i[151]
  PIN rd_bitrow_i[152]
    DIRECTION INPUT ;
    USE SIGNAL ;
    PORT
      LAYER Metal6 ;
        RECT 80.800 0.000 80.880 1.000 ;
    END
  END rd_bitrow_i[152]
  PIN rd_bitrow_i[153]
    DIRECTION INPUT ;
    USE SIGNAL ;
    PORT
      LAYER Metal6 ;
        RECT 81.200 0.000 81.280 1.000 ;
    END
  END rd_bitrow_i[153]
  PIN rd_bitrow_i[154]
    DIRECTION INPUT ;
    USE SIGNAL ;
    PORT
      LAYER Metal6 ;
        RECT 81.600 0.000 81.680 1.000 ;
    END
  END rd_bitrow_i[154]
  PIN rd_bitrow_i[155]
    DIRECTION INPUT ;
    USE SIGNAL ;
    PORT
      LAYER Metal6 ;
        RECT 82.000 0.000 82.080 1.000 ;
    END
  END rd_bitrow_i[155]
  PIN rd_bitrow_i[156]
    DIRECTION INPUT ;
    USE SIGNAL ;
    PORT
      LAYER Metal6 ;
        RECT 82.400 0.000 82.480 1.000 ;
    END
  END rd_bitrow_i[156]
  PIN rd_bitrow_i[157]
    DIRECTION INPUT ;
    USE SIGNAL ;
    PORT
      LAYER Metal6 ;
        RECT 82.800 0.000 82.880 1.000 ;
    END
  END rd_bitrow_i[157]
  PIN rd_bitrow_i[158]
    DIRECTION INPUT ;
    USE SIGNAL ;
    PORT
      LAYER Metal6 ;
        RECT 83.200 0.000 83.280 1.000 ;
    END
  END rd_bitrow_i[158]
  PIN rd_bitrow_i[159]
    DIRECTION INPUT ;
    USE SIGNAL ;
    PORT
      LAYER Metal6 ;
        RECT 83.600 0.000 83.680 1.000 ;
    END
  END rd_bitrow_i[159]
  PIN rd_bitrow_i[160]
    DIRECTION INPUT ;
    USE SIGNAL ;
    PORT
      LAYER Metal6 ;
        RECT 84.000 0.000 84.080 1.000 ;
    END
  END rd_bitrow_i[160]
  PIN rd_bitrow_i[161]
    DIRECTION INPUT ;
    USE SIGNAL ;
    PORT
      LAYER Metal6 ;
        RECT 84.400 0.000 84.480 1.000 ;
    END
  END rd_bitrow_i[161]
  PIN rd_bitrow_i[162]
    DIRECTION INPUT ;
    USE SIGNAL ;
    PORT
      LAYER Metal6 ;
        RECT 84.800 0.000 84.880 1.000 ;
    END
  END rd_bitrow_i[162]
  PIN rd_bitrow_i[163]
    DIRECTION INPUT ;
    USE SIGNAL ;
    PORT
      LAYER Metal6 ;
        RECT 85.200 0.000 85.280 1.000 ;
    END
  END rd_bitrow_i[163]
  PIN rd_bitrow_i[164]
    DIRECTION INPUT ;
    USE SIGNAL ;
    PORT
      LAYER Metal6 ;
        RECT 85.600 0.000 85.680 1.000 ;
    END
  END rd_bitrow_i[164]
  PIN rd_bitrow_i[165]
    DIRECTION INPUT ;
    USE SIGNAL ;
    PORT
      LAYER Metal6 ;
        RECT 86.000 0.000 86.080 1.000 ;
    END
  END rd_bitrow_i[165]
  PIN rd_bitrow_i[166]
    DIRECTION INPUT ;
    USE SIGNAL ;
    PORT
      LAYER Metal6 ;
        RECT 86.400 0.000 86.480 1.000 ;
    END
  END rd_bitrow_i[166]
  PIN rd_bitrow_i[167]
    DIRECTION INPUT ;
    USE SIGNAL ;
    PORT
      LAYER Metal6 ;
        RECT 86.800 0.000 86.880 1.000 ;
    END
  END rd_bitrow_i[167]
  PIN rd_bitrow_i[168]
    DIRECTION INPUT ;
    USE SIGNAL ;
    PORT
      LAYER Metal6 ;
        RECT 87.200 0.000 87.280 1.000 ;
    END
  END rd_bitrow_i[168]
  PIN rd_bitrow_i[169]
    DIRECTION INPUT ;
    USE SIGNAL ;
    PORT
      LAYER Metal6 ;
        RECT 87.600 0.000 87.680 1.000 ;
    END
  END rd_bitrow_i[169]
  PIN rd_bitrow_i[170]
    DIRECTION INPUT ;
    USE SIGNAL ;
    PORT
      LAYER Metal6 ;
        RECT 88.000 0.000 88.080 1.000 ;
    END
  END rd_bitrow_i[170]
  PIN rd_bitrow_i[171]
    DIRECTION INPUT ;
    USE SIGNAL ;
    PORT
      LAYER Metal6 ;
        RECT 88.400 0.000 88.480 1.000 ;
    END
  END rd_bitrow_i[171]
  PIN rd_bitrow_i[172]
    DIRECTION INPUT ;
    USE SIGNAL ;
    PORT
      LAYER Metal6 ;
        RECT 88.800 0.000 88.880 1.000 ;
    END
  END rd_bitrow_i[172]
  PIN rd_bitrow_i[173]
    DIRECTION INPUT ;
    USE SIGNAL ;
    PORT
      LAYER Metal6 ;
        RECT 89.200 0.000 89.280 1.000 ;
    END
  END rd_bitrow_i[173]
  PIN rd_bitrow_i[174]
    DIRECTION INPUT ;
    USE SIGNAL ;
    PORT
      LAYER Metal6 ;
        RECT 89.600 0.000 89.680 1.000 ;
    END
  END rd_bitrow_i[174]
  PIN rd_bitrow_i[175]
    DIRECTION INPUT ;
    USE SIGNAL ;
    PORT
      LAYER Metal6 ;
        RECT 90.000 0.000 90.080 1.000 ;
    END
  END rd_bitrow_i[175]
  PIN rd_bitrow_i[176]
    DIRECTION INPUT ;
    USE SIGNAL ;
    PORT
      LAYER Metal6 ;
        RECT 90.400 0.000 90.480 1.000 ;
    END
  END rd_bitrow_i[176]
  PIN rd_bitrow_i[177]
    DIRECTION INPUT ;
    USE SIGNAL ;
    PORT
      LAYER Metal6 ;
        RECT 90.800 0.000 90.880 1.000 ;
    END
  END rd_bitrow_i[177]
  PIN rd_bitrow_i[178]
    DIRECTION INPUT ;
    USE SIGNAL ;
    PORT
      LAYER Metal6 ;
        RECT 91.200 0.000 91.280 1.000 ;
    END
  END rd_bitrow_i[178]
  PIN rd_bitrow_i[179]
    DIRECTION INPUT ;
    USE SIGNAL ;
    PORT
      LAYER Metal6 ;
        RECT 91.600 0.000 91.680 1.000 ;
    END
  END rd_bitrow_i[179]
  PIN rd_bitrow_i[180]
    DIRECTION INPUT ;
    USE SIGNAL ;
    PORT
      LAYER Metal6 ;
        RECT 92.000 0.000 92.080 1.000 ;
    END
  END rd_bitrow_i[180]
  PIN rd_bitrow_i[181]
    DIRECTION INPUT ;
    USE SIGNAL ;
    PORT
      LAYER Metal6 ;
        RECT 92.400 0.000 92.480 1.000 ;
    END
  END rd_bitrow_i[181]
  PIN rd_bitrow_i[182]
    DIRECTION INPUT ;
    USE SIGNAL ;
    PORT
      LAYER Metal6 ;
        RECT 92.800 0.000 92.880 1.000 ;
    END
  END rd_bitrow_i[182]
  PIN rd_bitrow_i[183]
    DIRECTION INPUT ;
    USE SIGNAL ;
    PORT
      LAYER Metal6 ;
        RECT 93.200 0.000 93.280 1.000 ;
    END
  END rd_bitrow_i[183]
  PIN rd_bitrow_i[184]
    DIRECTION INPUT ;
    USE SIGNAL ;
    PORT
      LAYER Metal6 ;
        RECT 93.600 0.000 93.680 1.000 ;
    END
  END rd_bitrow_i[184]
  PIN rd_bitrow_i[185]
    DIRECTION INPUT ;
    USE SIGNAL ;
    PORT
      LAYER Metal6 ;
        RECT 94.000 0.000 94.080 1.000 ;
    END
  END rd_bitrow_i[185]
  PIN rd_bitrow_i[186]
    DIRECTION INPUT ;
    USE SIGNAL ;
    PORT
      LAYER Metal6 ;
        RECT 94.400 0.000 94.480 1.000 ;
    END
  END rd_bitrow_i[186]
  PIN rd_bitrow_i[187]
    DIRECTION INPUT ;
    USE SIGNAL ;
    PORT
      LAYER Metal6 ;
        RECT 94.800 0.000 94.880 1.000 ;
    END
  END rd_bitrow_i[187]
  PIN rd_bitrow_i[188]
    DIRECTION INPUT ;
    USE SIGNAL ;
    PORT
      LAYER Metal6 ;
        RECT 95.200 0.000 95.280 1.000 ;
    END
  END rd_bitrow_i[188]
  PIN rd_bitrow_i[189]
    DIRECTION INPUT ;
    USE SIGNAL ;
    PORT
      LAYER Metal6 ;
        RECT 95.600 0.000 95.680 1.000 ;
    END
  END rd_bitrow_i[189]
  PIN rd_bitrow_i[190]
    DIRECTION INPUT ;
    USE SIGNAL ;
    PORT
      LAYER Metal6 ;
        RECT 96.000 0.000 96.080 1.000 ;
    END
  END rd_bitrow_i[190]
  PIN rd_bitrow_i[191]
    DIRECTION INPUT ;
    USE SIGNAL ;
    PORT
      LAYER Metal6 ;
        RECT 96.400 0.000 96.480 1.000 ;
    END
  END rd_bitrow_i[191]
  PIN rd_bitrow_i[192]
    DIRECTION INPUT ;
    USE SIGNAL ;
    PORT
      LAYER Metal6 ;
        RECT 96.800 0.000 96.880 1.000 ;
    END
  END rd_bitrow_i[192]
  PIN rd_bitrow_i[193]
    DIRECTION INPUT ;
    USE SIGNAL ;
    PORT
      LAYER Metal6 ;
        RECT 97.200 0.000 97.280 1.000 ;
    END
  END rd_bitrow_i[193]
  PIN rd_bitrow_i[194]
    DIRECTION INPUT ;
    USE SIGNAL ;
    PORT
      LAYER Metal6 ;
        RECT 97.600 0.000 97.680 1.000 ;
    END
  END rd_bitrow_i[194]
  PIN rd_bitrow_i[195]
    DIRECTION INPUT ;
    USE SIGNAL ;
    PORT
      LAYER Metal6 ;
        RECT 98.000 0.000 98.080 1.000 ;
    END
  END rd_bitrow_i[195]
  PIN rd_bitrow_i[196]
    DIRECTION INPUT ;
    USE SIGNAL ;
    PORT
      LAYER Metal6 ;
        RECT 98.400 0.000 98.480 1.000 ;
    END
  END rd_bitrow_i[196]
  PIN rd_bitrow_i[197]
    DIRECTION INPUT ;
    USE SIGNAL ;
    PORT
      LAYER Metal6 ;
        RECT 98.800 0.000 98.880 1.000 ;
    END
  END rd_bitrow_i[197]
  PIN rd_bitrow_i[198]
    DIRECTION INPUT ;
    USE SIGNAL ;
    PORT
      LAYER Metal6 ;
        RECT 99.200 0.000 99.280 1.000 ;
    END
  END rd_bitrow_i[198]
  PIN rd_bitrow_i[199]
    DIRECTION INPUT ;
    USE SIGNAL ;
    PORT
      LAYER Metal6 ;
        RECT 99.600 0.000 99.680 1.000 ;
    END
  END rd_bitrow_i[199]
  PIN rd_bitrow_i[200]
    DIRECTION INPUT ;
    USE SIGNAL ;
    PORT
      LAYER Metal6 ;
        RECT 100.000 0.000 100.080 1.000 ;
    END
  END rd_bitrow_i[200]
  PIN rd_bitrow_i[201]
    DIRECTION INPUT ;
    USE SIGNAL ;
    PORT
      LAYER Metal6 ;
        RECT 100.400 0.000 100.480 1.000 ;
    END
  END rd_bitrow_i[201]
  PIN rd_bitrow_i[202]
    DIRECTION INPUT ;
    USE SIGNAL ;
    PORT
      LAYER Metal6 ;
        RECT 100.800 0.000 100.880 1.000 ;
    END
  END rd_bitrow_i[202]
  PIN rd_bitrow_i[203]
    DIRECTION INPUT ;
    USE SIGNAL ;
    PORT
      LAYER Metal6 ;
        RECT 101.200 0.000 101.280 1.000 ;
    END
  END rd_bitrow_i[203]
  PIN rd_bitrow_i[204]
    DIRECTION INPUT ;
    USE SIGNAL ;
    PORT
      LAYER Metal6 ;
        RECT 101.600 0.000 101.680 1.000 ;
    END
  END rd_bitrow_i[204]
  PIN rd_bitrow_i[205]
    DIRECTION INPUT ;
    USE SIGNAL ;
    PORT
      LAYER Metal6 ;
        RECT 102.000 0.000 102.080 1.000 ;
    END
  END rd_bitrow_i[205]
  PIN rd_bitrow_i[206]
    DIRECTION INPUT ;
    USE SIGNAL ;
    PORT
      LAYER Metal6 ;
        RECT 102.400 0.000 102.480 1.000 ;
    END
  END rd_bitrow_i[206]
  PIN rd_bitrow_i[207]
    DIRECTION INPUT ;
    USE SIGNAL ;
    PORT
      LAYER Metal6 ;
        RECT 102.800 0.000 102.880 1.000 ;
    END
  END rd_bitrow_i[207]
  PIN rd_bitrow_i[208]
    DIRECTION INPUT ;
    USE SIGNAL ;
    PORT
      LAYER Metal6 ;
        RECT 103.200 0.000 103.280 1.000 ;
    END
  END rd_bitrow_i[208]
  PIN rd_bitrow_i[209]
    DIRECTION INPUT ;
    USE SIGNAL ;
    PORT
      LAYER Metal6 ;
        RECT 103.600 0.000 103.680 1.000 ;
    END
  END rd_bitrow_i[209]
  PIN rd_bitrow_i[210]
    DIRECTION INPUT ;
    USE SIGNAL ;
    PORT
      LAYER Metal6 ;
        RECT 104.000 0.000 104.080 1.000 ;
    END
  END rd_bitrow_i[210]
  PIN rd_bitrow_i[211]
    DIRECTION INPUT ;
    USE SIGNAL ;
    PORT
      LAYER Metal6 ;
        RECT 104.400 0.000 104.480 1.000 ;
    END
  END rd_bitrow_i[211]
  PIN rd_bitrow_i[212]
    DIRECTION INPUT ;
    USE SIGNAL ;
    PORT
      LAYER Metal6 ;
        RECT 104.800 0.000 104.880 1.000 ;
    END
  END rd_bitrow_i[212]
  PIN rd_bitrow_i[213]
    DIRECTION INPUT ;
    USE SIGNAL ;
    PORT
      LAYER Metal6 ;
        RECT 105.200 0.000 105.280 1.000 ;
    END
  END rd_bitrow_i[213]
  PIN rd_bitrow_i[214]
    DIRECTION INPUT ;
    USE SIGNAL ;
    PORT
      LAYER Metal6 ;
        RECT 105.600 0.000 105.680 1.000 ;
    END
  END rd_bitrow_i[214]
  PIN rd_bitrow_i[215]
    DIRECTION INPUT ;
    USE SIGNAL ;
    PORT
      LAYER Metal6 ;
        RECT 106.000 0.000 106.080 1.000 ;
    END
  END rd_bitrow_i[215]
  PIN rd_bitrow_i[216]
    DIRECTION INPUT ;
    USE SIGNAL ;
    PORT
      LAYER Metal6 ;
        RECT 106.400 0.000 106.480 1.000 ;
    END
  END rd_bitrow_i[216]
  PIN rd_bitrow_i[217]
    DIRECTION INPUT ;
    USE SIGNAL ;
    PORT
      LAYER Metal6 ;
        RECT 106.800 0.000 106.880 1.000 ;
    END
  END rd_bitrow_i[217]
  PIN rd_bitrow_i[218]
    DIRECTION INPUT ;
    USE SIGNAL ;
    PORT
      LAYER Metal6 ;
        RECT 107.200 0.000 107.280 1.000 ;
    END
  END rd_bitrow_i[218]
  PIN rd_bitrow_i[219]
    DIRECTION INPUT ;
    USE SIGNAL ;
    PORT
      LAYER Metal6 ;
        RECT 107.600 0.000 107.680 1.000 ;
    END
  END rd_bitrow_i[219]
  PIN rd_bitrow_i[220]
    DIRECTION INPUT ;
    USE SIGNAL ;
    PORT
      LAYER Metal6 ;
        RECT 108.000 0.000 108.080 1.000 ;
    END
  END rd_bitrow_i[220]
  PIN rd_bitrow_i[221]
    DIRECTION INPUT ;
    USE SIGNAL ;
    PORT
      LAYER Metal6 ;
        RECT 108.400 0.000 108.480 1.000 ;
    END
  END rd_bitrow_i[221]
  PIN rd_bitrow_i[222]
    DIRECTION INPUT ;
    USE SIGNAL ;
    PORT
      LAYER Metal6 ;
        RECT 108.800 0.000 108.880 1.000 ;
    END
  END rd_bitrow_i[222]
  PIN rd_bitrow_i[223]
    DIRECTION INPUT ;
    USE SIGNAL ;
    PORT
      LAYER Metal6 ;
        RECT 109.200 0.000 109.280 1.000 ;
    END
  END rd_bitrow_i[223]
  PIN rd_bitrow_i[224]
    DIRECTION INPUT ;
    USE SIGNAL ;
    PORT
      LAYER Metal6 ;
        RECT 109.600 0.000 109.680 1.000 ;
    END
  END rd_bitrow_i[224]
  PIN rd_bitrow_i[225]
    DIRECTION INPUT ;
    USE SIGNAL ;
    PORT
      LAYER Metal6 ;
        RECT 110.000 0.000 110.080 1.000 ;
    END
  END rd_bitrow_i[225]
  PIN rd_bitrow_i[226]
    DIRECTION INPUT ;
    USE SIGNAL ;
    PORT
      LAYER Metal6 ;
        RECT 110.400 0.000 110.480 1.000 ;
    END
  END rd_bitrow_i[226]
  PIN rd_bitrow_i[227]
    DIRECTION INPUT ;
    USE SIGNAL ;
    PORT
      LAYER Metal6 ;
        RECT 110.800 0.000 110.880 1.000 ;
    END
  END rd_bitrow_i[227]
  PIN rd_bitrow_i[228]
    DIRECTION INPUT ;
    USE SIGNAL ;
    PORT
      LAYER Metal6 ;
        RECT 111.200 0.000 111.280 1.000 ;
    END
  END rd_bitrow_i[228]
  PIN rd_bitrow_i[229]
    DIRECTION INPUT ;
    USE SIGNAL ;
    PORT
      LAYER Metal6 ;
        RECT 111.600 0.000 111.680 1.000 ;
    END
  END rd_bitrow_i[229]
  PIN rd_bitrow_i[230]
    DIRECTION INPUT ;
    USE SIGNAL ;
    PORT
      LAYER Metal6 ;
        RECT 112.000 0.000 112.080 1.000 ;
    END
  END rd_bitrow_i[230]
  PIN rd_bitrow_i[231]
    DIRECTION INPUT ;
    USE SIGNAL ;
    PORT
      LAYER Metal6 ;
        RECT 112.400 0.000 112.480 1.000 ;
    END
  END rd_bitrow_i[231]
  PIN rd_bitrow_i[232]
    DIRECTION INPUT ;
    USE SIGNAL ;
    PORT
      LAYER Metal6 ;
        RECT 112.800 0.000 112.880 1.000 ;
    END
  END rd_bitrow_i[232]
  PIN rd_bitrow_i[233]
    DIRECTION INPUT ;
    USE SIGNAL ;
    PORT
      LAYER Metal6 ;
        RECT 113.200 0.000 113.280 1.000 ;
    END
  END rd_bitrow_i[233]
  PIN rd_bitrow_i[234]
    DIRECTION INPUT ;
    USE SIGNAL ;
    PORT
      LAYER Metal6 ;
        RECT 113.600 0.000 113.680 1.000 ;
    END
  END rd_bitrow_i[234]
  PIN rd_bitrow_i[235]
    DIRECTION INPUT ;
    USE SIGNAL ;
    PORT
      LAYER Metal6 ;
        RECT 114.000 0.000 114.080 1.000 ;
    END
  END rd_bitrow_i[235]
  PIN rd_bitrow_i[236]
    DIRECTION INPUT ;
    USE SIGNAL ;
    PORT
      LAYER Metal6 ;
        RECT 114.400 0.000 114.480 1.000 ;
    END
  END rd_bitrow_i[236]
  PIN rd_bitrow_i[237]
    DIRECTION INPUT ;
    USE SIGNAL ;
    PORT
      LAYER Metal6 ;
        RECT 114.800 0.000 114.880 1.000 ;
    END
  END rd_bitrow_i[237]
  PIN rd_bitrow_i[238]
    DIRECTION INPUT ;
    USE SIGNAL ;
    PORT
      LAYER Metal6 ;
        RECT 115.200 0.000 115.280 1.000 ;
    END
  END rd_bitrow_i[238]
  PIN rd_bitrow_i[239]
    DIRECTION INPUT ;
    USE SIGNAL ;
    PORT
      LAYER Metal6 ;
        RECT 115.600 0.000 115.680 1.000 ;
    END
  END rd_bitrow_i[239]
  PIN rd_bitrow_i[240]
    DIRECTION INPUT ;
    USE SIGNAL ;
    PORT
      LAYER Metal6 ;
        RECT 116.000 0.000 116.080 1.000 ;
    END
  END rd_bitrow_i[240]
  PIN rd_bitrow_i[241]
    DIRECTION INPUT ;
    USE SIGNAL ;
    PORT
      LAYER Metal6 ;
        RECT 116.400 0.000 116.480 1.000 ;
    END
  END rd_bitrow_i[241]
  PIN rd_bitrow_i[242]
    DIRECTION INPUT ;
    USE SIGNAL ;
    PORT
      LAYER Metal6 ;
        RECT 116.800 0.000 116.880 1.000 ;
    END
  END rd_bitrow_i[242]
  PIN rd_bitrow_i[243]
    DIRECTION INPUT ;
    USE SIGNAL ;
    PORT
      LAYER Metal6 ;
        RECT 117.200 0.000 117.280 1.000 ;
    END
  END rd_bitrow_i[243]
  PIN rd_bitrow_i[244]
    DIRECTION INPUT ;
    USE SIGNAL ;
    PORT
      LAYER Metal6 ;
        RECT 117.600 0.000 117.680 1.000 ;
    END
  END rd_bitrow_i[244]
  PIN rd_bitrow_i[245]
    DIRECTION INPUT ;
    USE SIGNAL ;
    PORT
      LAYER Metal6 ;
        RECT 118.000 0.000 118.080 1.000 ;
    END
  END rd_bitrow_i[245]
  PIN rd_bitrow_i[246]
    DIRECTION INPUT ;
    USE SIGNAL ;
    PORT
      LAYER Metal6 ;
        RECT 118.400 0.000 118.480 1.000 ;
    END
  END rd_bitrow_i[246]
  PIN rd_bitrow_i[247]
    DIRECTION INPUT ;
    USE SIGNAL ;
    PORT
      LAYER Metal6 ;
        RECT 118.800 0.000 118.880 1.000 ;
    END
  END rd_bitrow_i[247]
  PIN rd_bitrow_i[248]
    DIRECTION INPUT ;
    USE SIGNAL ;
    PORT
      LAYER Metal6 ;
        RECT 119.200 0.000 119.280 1.000 ;
    END
  END rd_bitrow_i[248]
  PIN rd_bitrow_i[249]
    DIRECTION INPUT ;
    USE SIGNAL ;
    PORT
      LAYER Metal6 ;
        RECT 119.600 0.000 119.680 1.000 ;
    END
  END rd_bitrow_i[249]
  PIN rd_bitrow_i[250]
    DIRECTION INPUT ;
    USE SIGNAL ;
    PORT
      LAYER Metal6 ;
        RECT 120.000 0.000 120.080 1.000 ;
    END
  END rd_bitrow_i[250]
  PIN rd_bitrow_i[251]
    DIRECTION INPUT ;
    USE SIGNAL ;
    PORT
      LAYER Metal6 ;
        RECT 120.400 0.000 120.480 1.000 ;
    END
  END rd_bitrow_i[251]
  PIN rd_bitrow_i[252]
    DIRECTION INPUT ;
    USE SIGNAL ;
    PORT
      LAYER Metal6 ;
        RECT 120.800 0.000 120.880 1.000 ;
    END
  END rd_bitrow_i[252]
  PIN rd_bitrow_i[253]
    DIRECTION INPUT ;
    USE SIGNAL ;
    PORT
      LAYER Metal6 ;
        RECT 121.200 0.000 121.280 1.000 ;
    END
  END rd_bitrow_i[253]
  PIN rd_bitrow_i[254]
    DIRECTION INPUT ;
    USE SIGNAL ;
    PORT
      LAYER Metal6 ;
        RECT 121.600 0.000 121.680 1.000 ;
    END
  END rd_bitrow_i[254]
  PIN rd_bitrow_i[255]
    DIRECTION INPUT ;
    USE SIGNAL ;
    PORT
      LAYER Metal6 ;
        RECT 122.000 0.000 122.080 1.000 ;
    END
  END rd_bitrow_i[255]
  PIN rd_bitrow_i[256]
    DIRECTION INPUT ;
    USE SIGNAL ;
    PORT
      LAYER Metal6 ;
        RECT 122.400 0.000 122.480 1.000 ;
    END
  END rd_bitrow_i[256]
  PIN rd_bitrow_i[257]
    DIRECTION INPUT ;
    USE SIGNAL ;
    PORT
      LAYER Metal6 ;
        RECT 122.800 0.000 122.880 1.000 ;
    END
  END rd_bitrow_i[257]
  PIN rd_bitrow_i[258]
    DIRECTION INPUT ;
    USE SIGNAL ;
    PORT
      LAYER Metal6 ;
        RECT 123.200 0.000 123.280 1.000 ;
    END
  END rd_bitrow_i[258]
  PIN rd_bitrow_i[259]
    DIRECTION INPUT ;
    USE SIGNAL ;
    PORT
      LAYER Metal6 ;
        RECT 123.600 0.000 123.680 1.000 ;
    END
  END rd_bitrow_i[259]
  PIN rd_bitrow_i[260]
    DIRECTION INPUT ;
    USE SIGNAL ;
    PORT
      LAYER Metal6 ;
        RECT 124.000 0.000 124.080 1.000 ;
    END
  END rd_bitrow_i[260]
  PIN rd_bitrow_i[261]
    DIRECTION INPUT ;
    USE SIGNAL ;
    PORT
      LAYER Metal6 ;
        RECT 124.400 0.000 124.480 1.000 ;
    END
  END rd_bitrow_i[261]
  PIN rd_bitrow_i[262]
    DIRECTION INPUT ;
    USE SIGNAL ;
    PORT
      LAYER Metal6 ;
        RECT 124.800 0.000 124.880 1.000 ;
    END
  END rd_bitrow_i[262]
  PIN rd_bitrow_i[263]
    DIRECTION INPUT ;
    USE SIGNAL ;
    PORT
      LAYER Metal6 ;
        RECT 125.200 0.000 125.280 1.000 ;
    END
  END rd_bitrow_i[263]
  PIN rd_bitrow_i[264]
    DIRECTION INPUT ;
    USE SIGNAL ;
    PORT
      LAYER Metal6 ;
        RECT 125.600 0.000 125.680 1.000 ;
    END
  END rd_bitrow_i[264]
  PIN rd_bitrow_i[265]
    DIRECTION INPUT ;
    USE SIGNAL ;
    PORT
      LAYER Metal6 ;
        RECT 126.000 0.000 126.080 1.000 ;
    END
  END rd_bitrow_i[265]
  PIN rd_bitrow_i[266]
    DIRECTION INPUT ;
    USE SIGNAL ;
    PORT
      LAYER Metal6 ;
        RECT 126.400 0.000 126.480 1.000 ;
    END
  END rd_bitrow_i[266]
  PIN rd_bitrow_i[267]
    DIRECTION INPUT ;
    USE SIGNAL ;
    PORT
      LAYER Metal6 ;
        RECT 126.800 0.000 126.880 1.000 ;
    END
  END rd_bitrow_i[267]
  PIN rd_bitrow_i[268]
    DIRECTION INPUT ;
    USE SIGNAL ;
    PORT
      LAYER Metal6 ;
        RECT 127.200 0.000 127.280 1.000 ;
    END
  END rd_bitrow_i[268]
  PIN rd_bitrow_i[269]
    DIRECTION INPUT ;
    USE SIGNAL ;
    PORT
      LAYER Metal6 ;
        RECT 127.600 0.000 127.680 1.000 ;
    END
  END rd_bitrow_i[269]
  PIN rd_bitrow_i[270]
    DIRECTION INPUT ;
    USE SIGNAL ;
    PORT
      LAYER Metal6 ;
        RECT 128.000 0.000 128.080 1.000 ;
    END
  END rd_bitrow_i[270]
  PIN rd_bitrow_i[271]
    DIRECTION INPUT ;
    USE SIGNAL ;
    PORT
      LAYER Metal6 ;
        RECT 128.400 0.000 128.480 1.000 ;
    END
  END rd_bitrow_i[271]
  PIN rd_bitrow_i[272]
    DIRECTION INPUT ;
    USE SIGNAL ;
    PORT
      LAYER Metal6 ;
        RECT 128.800 0.000 128.880 1.000 ;
    END
  END rd_bitrow_i[272]
  PIN rd_bitrow_i[273]
    DIRECTION INPUT ;
    USE SIGNAL ;
    PORT
      LAYER Metal6 ;
        RECT 129.200 0.000 129.280 1.000 ;
    END
  END rd_bitrow_i[273]
  PIN rd_bitrow_i[274]
    DIRECTION INPUT ;
    USE SIGNAL ;
    PORT
      LAYER Metal6 ;
        RECT 129.600 0.000 129.680 1.000 ;
    END
  END rd_bitrow_i[274]
  PIN rd_bitrow_i[275]
    DIRECTION INPUT ;
    USE SIGNAL ;
    PORT
      LAYER Metal6 ;
        RECT 130.000 0.000 130.080 1.000 ;
    END
  END rd_bitrow_i[275]
  PIN rd_bitrow_i[276]
    DIRECTION INPUT ;
    USE SIGNAL ;
    PORT
      LAYER Metal6 ;
        RECT 130.400 0.000 130.480 1.000 ;
    END
  END rd_bitrow_i[276]
  PIN rd_bitrow_i[277]
    DIRECTION INPUT ;
    USE SIGNAL ;
    PORT
      LAYER Metal6 ;
        RECT 130.800 0.000 130.880 1.000 ;
    END
  END rd_bitrow_i[277]
  PIN rd_bitrow_i[278]
    DIRECTION INPUT ;
    USE SIGNAL ;
    PORT
      LAYER Metal6 ;
        RECT 131.200 0.000 131.280 1.000 ;
    END
  END rd_bitrow_i[278]
  PIN rd_bitrow_i[279]
    DIRECTION INPUT ;
    USE SIGNAL ;
    PORT
      LAYER Metal6 ;
        RECT 131.600 0.000 131.680 1.000 ;
    END
  END rd_bitrow_i[279]
  PIN rd_bitrow_i[280]
    DIRECTION INPUT ;
    USE SIGNAL ;
    PORT
      LAYER Metal6 ;
        RECT 132.000 0.000 132.080 1.000 ;
    END
  END rd_bitrow_i[280]
  PIN rd_bitrow_i[281]
    DIRECTION INPUT ;
    USE SIGNAL ;
    PORT
      LAYER Metal6 ;
        RECT 132.400 0.000 132.480 1.000 ;
    END
  END rd_bitrow_i[281]
  PIN rd_bitrow_i[282]
    DIRECTION INPUT ;
    USE SIGNAL ;
    PORT
      LAYER Metal6 ;
        RECT 132.800 0.000 132.880 1.000 ;
    END
  END rd_bitrow_i[282]
  PIN rd_bitrow_i[283]
    DIRECTION INPUT ;
    USE SIGNAL ;
    PORT
      LAYER Metal6 ;
        RECT 133.200 0.000 133.280 1.000 ;
    END
  END rd_bitrow_i[283]
  PIN rd_bitrow_i[284]
    DIRECTION INPUT ;
    USE SIGNAL ;
    PORT
      LAYER Metal6 ;
        RECT 133.600 0.000 133.680 1.000 ;
    END
  END rd_bitrow_i[284]
  PIN rd_bitrow_i[285]
    DIRECTION INPUT ;
    USE SIGNAL ;
    PORT
      LAYER Metal6 ;
        RECT 134.000 0.000 134.080 1.000 ;
    END
  END rd_bitrow_i[285]
  PIN rd_bitrow_i[286]
    DIRECTION INPUT ;
    USE SIGNAL ;
    PORT
      LAYER Metal6 ;
        RECT 134.400 0.000 134.480 1.000 ;
    END
  END rd_bitrow_i[286]
  PIN rd_bitrow_i[287]
    DIRECTION INPUT ;
    USE SIGNAL ;
    PORT
      LAYER Metal6 ;
        RECT 134.800 0.000 134.880 1.000 ;
    END
  END rd_bitrow_i[287]
  PIN rd_bitrow_i[288]
    DIRECTION INPUT ;
    USE SIGNAL ;
    PORT
      LAYER Metal6 ;
        RECT 135.200 0.000 135.280 1.000 ;
    END
  END rd_bitrow_i[288]
  PIN rd_bitrow_i[289]
    DIRECTION INPUT ;
    USE SIGNAL ;
    PORT
      LAYER Metal6 ;
        RECT 135.600 0.000 135.680 1.000 ;
    END
  END rd_bitrow_i[289]
  PIN rd_bitrow_i[290]
    DIRECTION INPUT ;
    USE SIGNAL ;
    PORT
      LAYER Metal6 ;
        RECT 136.000 0.000 136.080 1.000 ;
    END
  END rd_bitrow_i[290]
  PIN rd_bitrow_i[291]
    DIRECTION INPUT ;
    USE SIGNAL ;
    PORT
      LAYER Metal6 ;
        RECT 136.400 0.000 136.480 1.000 ;
    END
  END rd_bitrow_i[291]
  PIN rd_bitrow_i[292]
    DIRECTION INPUT ;
    USE SIGNAL ;
    PORT
      LAYER Metal6 ;
        RECT 136.800 0.000 136.880 1.000 ;
    END
  END rd_bitrow_i[292]
  PIN rd_bitrow_i[293]
    DIRECTION INPUT ;
    USE SIGNAL ;
    PORT
      LAYER Metal6 ;
        RECT 137.200 0.000 137.280 1.000 ;
    END
  END rd_bitrow_i[293]
  PIN rd_bitrow_i[294]
    DIRECTION INPUT ;
    USE SIGNAL ;
    PORT
      LAYER Metal6 ;
        RECT 137.600 0.000 137.680 1.000 ;
    END
  END rd_bitrow_i[294]
  PIN rd_bitrow_i[295]
    DIRECTION INPUT ;
    USE SIGNAL ;
    PORT
      LAYER Metal6 ;
        RECT 138.000 0.000 138.080 1.000 ;
    END
  END rd_bitrow_i[295]
  PIN rd_bitrow_i[296]
    DIRECTION INPUT ;
    USE SIGNAL ;
    PORT
      LAYER Metal6 ;
        RECT 138.400 0.000 138.480 1.000 ;
    END
  END rd_bitrow_i[296]
  PIN rd_bitrow_i[297]
    DIRECTION INPUT ;
    USE SIGNAL ;
    PORT
      LAYER Metal6 ;
        RECT 138.800 0.000 138.880 1.000 ;
    END
  END rd_bitrow_i[297]
  PIN rd_bitrow_i[298]
    DIRECTION INPUT ;
    USE SIGNAL ;
    PORT
      LAYER Metal6 ;
        RECT 139.200 0.000 139.280 1.000 ;
    END
  END rd_bitrow_i[298]
  PIN rd_bitrow_i[299]
    DIRECTION INPUT ;
    USE SIGNAL ;
    PORT
      LAYER Metal6 ;
        RECT 139.600 0.000 139.680 1.000 ;
    END
  END rd_bitrow_i[299]
  PIN rd_bitrow_i[300]
    DIRECTION INPUT ;
    USE SIGNAL ;
    PORT
      LAYER Metal6 ;
        RECT 140.000 0.000 140.080 1.000 ;
    END
  END rd_bitrow_i[300]
  PIN rd_bitrow_i[301]
    DIRECTION INPUT ;
    USE SIGNAL ;
    PORT
      LAYER Metal6 ;
        RECT 140.400 0.000 140.480 1.000 ;
    END
  END rd_bitrow_i[301]
  PIN rd_bitrow_i[302]
    DIRECTION INPUT ;
    USE SIGNAL ;
    PORT
      LAYER Metal6 ;
        RECT 140.800 0.000 140.880 1.000 ;
    END
  END rd_bitrow_i[302]
  PIN rd_bitrow_i[303]
    DIRECTION INPUT ;
    USE SIGNAL ;
    PORT
      LAYER Metal6 ;
        RECT 141.200 0.000 141.280 1.000 ;
    END
  END rd_bitrow_i[303]
  PIN rd_bitrow_i[304]
    DIRECTION INPUT ;
    USE SIGNAL ;
    PORT
      LAYER Metal6 ;
        RECT 141.600 0.000 141.680 1.000 ;
    END
  END rd_bitrow_i[304]
  PIN rd_bitrow_i[305]
    DIRECTION INPUT ;
    USE SIGNAL ;
    PORT
      LAYER Metal6 ;
        RECT 142.000 0.000 142.080 1.000 ;
    END
  END rd_bitrow_i[305]
  PIN rd_bitrow_i[306]
    DIRECTION INPUT ;
    USE SIGNAL ;
    PORT
      LAYER Metal6 ;
        RECT 142.400 0.000 142.480 1.000 ;
    END
  END rd_bitrow_i[306]
  PIN rd_bitrow_i[307]
    DIRECTION INPUT ;
    USE SIGNAL ;
    PORT
      LAYER Metal6 ;
        RECT 142.800 0.000 142.880 1.000 ;
    END
  END rd_bitrow_i[307]
  PIN rd_bitrow_i[308]
    DIRECTION INPUT ;
    USE SIGNAL ;
    PORT
      LAYER Metal6 ;
        RECT 143.200 0.000 143.280 1.000 ;
    END
  END rd_bitrow_i[308]
  PIN rd_bitrow_i[309]
    DIRECTION INPUT ;
    USE SIGNAL ;
    PORT
      LAYER Metal6 ;
        RECT 143.600 0.000 143.680 1.000 ;
    END
  END rd_bitrow_i[309]
  PIN rd_bitrow_i[310]
    DIRECTION INPUT ;
    USE SIGNAL ;
    PORT
      LAYER Metal6 ;
        RECT 144.000 0.000 144.080 1.000 ;
    END
  END rd_bitrow_i[310]
  PIN rd_bitrow_i[311]
    DIRECTION INPUT ;
    USE SIGNAL ;
    PORT
      LAYER Metal6 ;
        RECT 144.400 0.000 144.480 1.000 ;
    END
  END rd_bitrow_i[311]
  PIN rd_bitrow_i[312]
    DIRECTION INPUT ;
    USE SIGNAL ;
    PORT
      LAYER Metal6 ;
        RECT 144.800 0.000 144.880 1.000 ;
    END
  END rd_bitrow_i[312]
  PIN rd_bitrow_i[313]
    DIRECTION INPUT ;
    USE SIGNAL ;
    PORT
      LAYER Metal6 ;
        RECT 145.200 0.000 145.280 1.000 ;
    END
  END rd_bitrow_i[313]
  PIN rd_bitrow_i[314]
    DIRECTION INPUT ;
    USE SIGNAL ;
    PORT
      LAYER Metal6 ;
        RECT 145.600 0.000 145.680 1.000 ;
    END
  END rd_bitrow_i[314]
  PIN rd_bitrow_i[315]
    DIRECTION INPUT ;
    USE SIGNAL ;
    PORT
      LAYER Metal6 ;
        RECT 146.000 0.000 146.080 1.000 ;
    END
  END rd_bitrow_i[315]
  PIN rd_bitrow_i[316]
    DIRECTION INPUT ;
    USE SIGNAL ;
    PORT
      LAYER Metal6 ;
        RECT 146.400 0.000 146.480 1.000 ;
    END
  END rd_bitrow_i[316]
  PIN rd_bitrow_i[317]
    DIRECTION INPUT ;
    USE SIGNAL ;
    PORT
      LAYER Metal6 ;
        RECT 146.800 0.000 146.880 1.000 ;
    END
  END rd_bitrow_i[317]
  PIN rd_bitrow_i[318]
    DIRECTION INPUT ;
    USE SIGNAL ;
    PORT
      LAYER Metal6 ;
        RECT 147.200 0.000 147.280 1.000 ;
    END
  END rd_bitrow_i[318]
  PIN rd_bitrow_i[319]
    DIRECTION INPUT ;
    USE SIGNAL ;
    PORT
      LAYER Metal6 ;
        RECT 147.600 0.000 147.680 1.000 ;
    END
  END rd_bitrow_i[319]
  PIN rd_bitrow_i[320]
    DIRECTION INPUT ;
    USE SIGNAL ;
    PORT
      LAYER Metal6 ;
        RECT 148.000 0.000 148.080 1.000 ;
    END
  END rd_bitrow_i[320]
  PIN rd_bitrow_i[321]
    DIRECTION INPUT ;
    USE SIGNAL ;
    PORT
      LAYER Metal6 ;
        RECT 148.400 0.000 148.480 1.000 ;
    END
  END rd_bitrow_i[321]
  PIN rd_bitrow_i[322]
    DIRECTION INPUT ;
    USE SIGNAL ;
    PORT
      LAYER Metal6 ;
        RECT 148.800 0.000 148.880 1.000 ;
    END
  END rd_bitrow_i[322]
  PIN rd_bitrow_i[323]
    DIRECTION INPUT ;
    USE SIGNAL ;
    PORT
      LAYER Metal6 ;
        RECT 149.200 0.000 149.280 1.000 ;
    END
  END rd_bitrow_i[323]
  PIN rd_bitrow_i[324]
    DIRECTION INPUT ;
    USE SIGNAL ;
    PORT
      LAYER Metal6 ;
        RECT 149.600 0.000 149.680 1.000 ;
    END
  END rd_bitrow_i[324]
  PIN rd_bitrow_i[325]
    DIRECTION INPUT ;
    USE SIGNAL ;
    PORT
      LAYER Metal6 ;
        RECT 150.000 0.000 150.080 1.000 ;
    END
  END rd_bitrow_i[325]
  PIN rd_bitrow_i[326]
    DIRECTION INPUT ;
    USE SIGNAL ;
    PORT
      LAYER Metal6 ;
        RECT 150.400 0.000 150.480 1.000 ;
    END
  END rd_bitrow_i[326]
  PIN rd_bitrow_i[327]
    DIRECTION INPUT ;
    USE SIGNAL ;
    PORT
      LAYER Metal6 ;
        RECT 150.800 0.000 150.880 1.000 ;
    END
  END rd_bitrow_i[327]
  PIN rd_bitrow_i[328]
    DIRECTION INPUT ;
    USE SIGNAL ;
    PORT
      LAYER Metal6 ;
        RECT 151.200 0.000 151.280 1.000 ;
    END
  END rd_bitrow_i[328]
  PIN rd_bitrow_i[329]
    DIRECTION INPUT ;
    USE SIGNAL ;
    PORT
      LAYER Metal6 ;
        RECT 151.600 0.000 151.680 1.000 ;
    END
  END rd_bitrow_i[329]
  PIN rd_bitrow_i[330]
    DIRECTION INPUT ;
    USE SIGNAL ;
    PORT
      LAYER Metal6 ;
        RECT 152.000 0.000 152.080 1.000 ;
    END
  END rd_bitrow_i[330]
  PIN rd_bitrow_i[331]
    DIRECTION INPUT ;
    USE SIGNAL ;
    PORT
      LAYER Metal6 ;
        RECT 152.400 0.000 152.480 1.000 ;
    END
  END rd_bitrow_i[331]
  PIN rd_bitrow_i[332]
    DIRECTION INPUT ;
    USE SIGNAL ;
    PORT
      LAYER Metal6 ;
        RECT 152.800 0.000 152.880 1.000 ;
    END
  END rd_bitrow_i[332]
  PIN rd_bitrow_i[333]
    DIRECTION INPUT ;
    USE SIGNAL ;
    PORT
      LAYER Metal6 ;
        RECT 153.200 0.000 153.280 1.000 ;
    END
  END rd_bitrow_i[333]
  PIN rd_bitrow_i[334]
    DIRECTION INPUT ;
    USE SIGNAL ;
    PORT
      LAYER Metal6 ;
        RECT 153.600 0.000 153.680 1.000 ;
    END
  END rd_bitrow_i[334]
  PIN rd_bitrow_i[335]
    DIRECTION INPUT ;
    USE SIGNAL ;
    PORT
      LAYER Metal6 ;
        RECT 154.000 0.000 154.080 1.000 ;
    END
  END rd_bitrow_i[335]
  PIN rd_bitrow_i[336]
    DIRECTION INPUT ;
    USE SIGNAL ;
    PORT
      LAYER Metal6 ;
        RECT 154.400 0.000 154.480 1.000 ;
    END
  END rd_bitrow_i[336]
  PIN rd_bitrow_i[337]
    DIRECTION INPUT ;
    USE SIGNAL ;
    PORT
      LAYER Metal6 ;
        RECT 154.800 0.000 154.880 1.000 ;
    END
  END rd_bitrow_i[337]
  PIN rd_bitrow_i[338]
    DIRECTION INPUT ;
    USE SIGNAL ;
    PORT
      LAYER Metal6 ;
        RECT 155.200 0.000 155.280 1.000 ;
    END
  END rd_bitrow_i[338]
  PIN rd_bitrow_i[339]
    DIRECTION INPUT ;
    USE SIGNAL ;
    PORT
      LAYER Metal6 ;
        RECT 155.600 0.000 155.680 1.000 ;
    END
  END rd_bitrow_i[339]
  PIN rd_bitrow_i[340]
    DIRECTION INPUT ;
    USE SIGNAL ;
    PORT
      LAYER Metal6 ;
        RECT 156.000 0.000 156.080 1.000 ;
    END
  END rd_bitrow_i[340]
  PIN rd_bitrow_i[341]
    DIRECTION INPUT ;
    USE SIGNAL ;
    PORT
      LAYER Metal6 ;
        RECT 156.400 0.000 156.480 1.000 ;
    END
  END rd_bitrow_i[341]
  PIN rd_bitrow_i[342]
    DIRECTION INPUT ;
    USE SIGNAL ;
    PORT
      LAYER Metal6 ;
        RECT 156.800 0.000 156.880 1.000 ;
    END
  END rd_bitrow_i[342]
  PIN rd_bitrow_i[343]
    DIRECTION INPUT ;
    USE SIGNAL ;
    PORT
      LAYER Metal6 ;
        RECT 157.200 0.000 157.280 1.000 ;
    END
  END rd_bitrow_i[343]
  PIN rd_bitrow_i[344]
    DIRECTION INPUT ;
    USE SIGNAL ;
    PORT
      LAYER Metal6 ;
        RECT 157.600 0.000 157.680 1.000 ;
    END
  END rd_bitrow_i[344]
  PIN rd_bitrow_i[345]
    DIRECTION INPUT ;
    USE SIGNAL ;
    PORT
      LAYER Metal6 ;
        RECT 158.000 0.000 158.080 1.000 ;
    END
  END rd_bitrow_i[345]
  PIN rd_bitrow_i[346]
    DIRECTION INPUT ;
    USE SIGNAL ;
    PORT
      LAYER Metal6 ;
        RECT 158.400 0.000 158.480 1.000 ;
    END
  END rd_bitrow_i[346]
  PIN rd_bitrow_i[347]
    DIRECTION INPUT ;
    USE SIGNAL ;
    PORT
      LAYER Metal6 ;
        RECT 158.800 0.000 158.880 1.000 ;
    END
  END rd_bitrow_i[347]
  PIN rd_bitrow_i[348]
    DIRECTION INPUT ;
    USE SIGNAL ;
    PORT
      LAYER Metal6 ;
        RECT 159.200 0.000 159.280 1.000 ;
    END
  END rd_bitrow_i[348]
  PIN rd_bitrow_i[349]
    DIRECTION INPUT ;
    USE SIGNAL ;
    PORT
      LAYER Metal6 ;
        RECT 159.600 0.000 159.680 1.000 ;
    END
  END rd_bitrow_i[349]
  PIN rd_bitrow_i[350]
    DIRECTION INPUT ;
    USE SIGNAL ;
    PORT
      LAYER Metal6 ;
        RECT 160.000 0.000 160.080 1.000 ;
    END
  END rd_bitrow_i[350]
  PIN rd_bitrow_i[351]
    DIRECTION INPUT ;
    USE SIGNAL ;
    PORT
      LAYER Metal6 ;
        RECT 160.400 0.000 160.480 1.000 ;
    END
  END rd_bitrow_i[351]
  PIN rd_bitrow_i[352]
    DIRECTION INPUT ;
    USE SIGNAL ;
    PORT
      LAYER Metal6 ;
        RECT 160.800 0.000 160.880 1.000 ;
    END
  END rd_bitrow_i[352]
  PIN rd_bitrow_i[353]
    DIRECTION INPUT ;
    USE SIGNAL ;
    PORT
      LAYER Metal6 ;
        RECT 161.200 0.000 161.280 1.000 ;
    END
  END rd_bitrow_i[353]
  PIN rd_bitrow_i[354]
    DIRECTION INPUT ;
    USE SIGNAL ;
    PORT
      LAYER Metal6 ;
        RECT 161.600 0.000 161.680 1.000 ;
    END
  END rd_bitrow_i[354]
  PIN rd_bitrow_i[355]
    DIRECTION INPUT ;
    USE SIGNAL ;
    PORT
      LAYER Metal6 ;
        RECT 162.000 0.000 162.080 1.000 ;
    END
  END rd_bitrow_i[355]
  PIN rd_bitrow_i[356]
    DIRECTION INPUT ;
    USE SIGNAL ;
    PORT
      LAYER Metal6 ;
        RECT 162.400 0.000 162.480 1.000 ;
    END
  END rd_bitrow_i[356]
  PIN rd_bitrow_i[357]
    DIRECTION INPUT ;
    USE SIGNAL ;
    PORT
      LAYER Metal6 ;
        RECT 162.800 0.000 162.880 1.000 ;
    END
  END rd_bitrow_i[357]
  PIN rd_bitrow_i[358]
    DIRECTION INPUT ;
    USE SIGNAL ;
    PORT
      LAYER Metal6 ;
        RECT 163.200 0.000 163.280 1.000 ;
    END
  END rd_bitrow_i[358]
  PIN rd_bitrow_i[359]
    DIRECTION INPUT ;
    USE SIGNAL ;
    PORT
      LAYER Metal6 ;
        RECT 163.600 0.000 163.680 1.000 ;
    END
  END rd_bitrow_i[359]
  PIN rd_bitrow_i[360]
    DIRECTION INPUT ;
    USE SIGNAL ;
    PORT
      LAYER Metal6 ;
        RECT 164.000 0.000 164.080 1.000 ;
    END
  END rd_bitrow_i[360]
  PIN rd_bitrow_i[361]
    DIRECTION INPUT ;
    USE SIGNAL ;
    PORT
      LAYER Metal6 ;
        RECT 164.400 0.000 164.480 1.000 ;
    END
  END rd_bitrow_i[361]
  PIN rd_bitrow_i[362]
    DIRECTION INPUT ;
    USE SIGNAL ;
    PORT
      LAYER Metal6 ;
        RECT 164.800 0.000 164.880 1.000 ;
    END
  END rd_bitrow_i[362]
  PIN rd_bitrow_i[363]
    DIRECTION INPUT ;
    USE SIGNAL ;
    PORT
      LAYER Metal6 ;
        RECT 165.200 0.000 165.280 1.000 ;
    END
  END rd_bitrow_i[363]
  PIN rd_bitrow_i[364]
    DIRECTION INPUT ;
    USE SIGNAL ;
    PORT
      LAYER Metal6 ;
        RECT 165.600 0.000 165.680 1.000 ;
    END
  END rd_bitrow_i[364]
  PIN rd_bitrow_i[365]
    DIRECTION INPUT ;
    USE SIGNAL ;
    PORT
      LAYER Metal6 ;
        RECT 166.000 0.000 166.080 1.000 ;
    END
  END rd_bitrow_i[365]
  PIN rd_bitrow_i[366]
    DIRECTION INPUT ;
    USE SIGNAL ;
    PORT
      LAYER Metal6 ;
        RECT 166.400 0.000 166.480 1.000 ;
    END
  END rd_bitrow_i[366]
  PIN rd_bitrow_i[367]
    DIRECTION INPUT ;
    USE SIGNAL ;
    PORT
      LAYER Metal6 ;
        RECT 166.800 0.000 166.880 1.000 ;
    END
  END rd_bitrow_i[367]
  PIN rd_bitrow_i[368]
    DIRECTION INPUT ;
    USE SIGNAL ;
    PORT
      LAYER Metal6 ;
        RECT 167.200 0.000 167.280 1.000 ;
    END
  END rd_bitrow_i[368]
  PIN rd_bitrow_i[369]
    DIRECTION INPUT ;
    USE SIGNAL ;
    PORT
      LAYER Metal6 ;
        RECT 167.600 0.000 167.680 1.000 ;
    END
  END rd_bitrow_i[369]
  PIN rd_bitrow_i[370]
    DIRECTION INPUT ;
    USE SIGNAL ;
    PORT
      LAYER Metal6 ;
        RECT 168.000 0.000 168.080 1.000 ;
    END
  END rd_bitrow_i[370]
  PIN rd_bitrow_i[371]
    DIRECTION INPUT ;
    USE SIGNAL ;
    PORT
      LAYER Metal6 ;
        RECT 168.400 0.000 168.480 1.000 ;
    END
  END rd_bitrow_i[371]
  PIN rd_bitrow_i[372]
    DIRECTION INPUT ;
    USE SIGNAL ;
    PORT
      LAYER Metal6 ;
        RECT 168.800 0.000 168.880 1.000 ;
    END
  END rd_bitrow_i[372]
  PIN rd_bitrow_i[373]
    DIRECTION INPUT ;
    USE SIGNAL ;
    PORT
      LAYER Metal6 ;
        RECT 169.200 0.000 169.280 1.000 ;
    END
  END rd_bitrow_i[373]
  PIN rd_bitrow_i[374]
    DIRECTION INPUT ;
    USE SIGNAL ;
    PORT
      LAYER Metal6 ;
        RECT 169.600 0.000 169.680 1.000 ;
    END
  END rd_bitrow_i[374]
  PIN rd_bitrow_i[375]
    DIRECTION INPUT ;
    USE SIGNAL ;
    PORT
      LAYER Metal6 ;
        RECT 170.000 0.000 170.080 1.000 ;
    END
  END rd_bitrow_i[375]
  PIN rd_bitrow_i[376]
    DIRECTION INPUT ;
    USE SIGNAL ;
    PORT
      LAYER Metal6 ;
        RECT 170.400 0.000 170.480 1.000 ;
    END
  END rd_bitrow_i[376]
  PIN rd_bitrow_i[377]
    DIRECTION INPUT ;
    USE SIGNAL ;
    PORT
      LAYER Metal6 ;
        RECT 170.800 0.000 170.880 1.000 ;
    END
  END rd_bitrow_i[377]
  PIN rd_bitrow_i[378]
    DIRECTION INPUT ;
    USE SIGNAL ;
    PORT
      LAYER Metal6 ;
        RECT 171.200 0.000 171.280 1.000 ;
    END
  END rd_bitrow_i[378]
  PIN rd_bitrow_i[379]
    DIRECTION INPUT ;
    USE SIGNAL ;
    PORT
      LAYER Metal6 ;
        RECT 171.600 0.000 171.680 1.000 ;
    END
  END rd_bitrow_i[379]
  PIN rd_bitrow_i[380]
    DIRECTION INPUT ;
    USE SIGNAL ;
    PORT
      LAYER Metal6 ;
        RECT 172.000 0.000 172.080 1.000 ;
    END
  END rd_bitrow_i[380]
  PIN rd_bitrow_i[381]
    DIRECTION INPUT ;
    USE SIGNAL ;
    PORT
      LAYER Metal6 ;
        RECT 172.400 0.000 172.480 1.000 ;
    END
  END rd_bitrow_i[381]
  PIN rd_bitrow_i[382]
    DIRECTION INPUT ;
    USE SIGNAL ;
    PORT
      LAYER Metal6 ;
        RECT 172.800 0.000 172.880 1.000 ;
    END
  END rd_bitrow_i[382]
  PIN rd_bitrow_i[383]
    DIRECTION INPUT ;
    USE SIGNAL ;
    PORT
      LAYER Metal6 ;
        RECT 173.200 0.000 173.280 1.000 ;
    END
  END rd_bitrow_i[383]
  PIN rd_bitrow_i[384]
    DIRECTION INPUT ;
    USE SIGNAL ;
    PORT
      LAYER Metal6 ;
        RECT 173.600 0.000 173.680 1.000 ;
    END
  END rd_bitrow_i[384]
  PIN rd_bitrow_i[385]
    DIRECTION INPUT ;
    USE SIGNAL ;
    PORT
      LAYER Metal6 ;
        RECT 174.000 0.000 174.080 1.000 ;
    END
  END rd_bitrow_i[385]
  PIN rd_bitrow_i[386]
    DIRECTION INPUT ;
    USE SIGNAL ;
    PORT
      LAYER Metal6 ;
        RECT 174.400 0.000 174.480 1.000 ;
    END
  END rd_bitrow_i[386]
  PIN rd_bitrow_i[387]
    DIRECTION INPUT ;
    USE SIGNAL ;
    PORT
      LAYER Metal6 ;
        RECT 174.800 0.000 174.880 1.000 ;
    END
  END rd_bitrow_i[387]
  PIN rd_bitrow_i[388]
    DIRECTION INPUT ;
    USE SIGNAL ;
    PORT
      LAYER Metal6 ;
        RECT 175.200 0.000 175.280 1.000 ;
    END
  END rd_bitrow_i[388]
  PIN rd_bitrow_i[389]
    DIRECTION INPUT ;
    USE SIGNAL ;
    PORT
      LAYER Metal6 ;
        RECT 175.600 0.000 175.680 1.000 ;
    END
  END rd_bitrow_i[389]
  PIN rd_bitrow_i[390]
    DIRECTION INPUT ;
    USE SIGNAL ;
    PORT
      LAYER Metal6 ;
        RECT 176.000 0.000 176.080 1.000 ;
    END
  END rd_bitrow_i[390]
  PIN rd_bitrow_i[391]
    DIRECTION INPUT ;
    USE SIGNAL ;
    PORT
      LAYER Metal6 ;
        RECT 176.400 0.000 176.480 1.000 ;
    END
  END rd_bitrow_i[391]
  PIN rd_bitrow_i[392]
    DIRECTION INPUT ;
    USE SIGNAL ;
    PORT
      LAYER Metal6 ;
        RECT 176.800 0.000 176.880 1.000 ;
    END
  END rd_bitrow_i[392]
  PIN rd_bitrow_i[393]
    DIRECTION INPUT ;
    USE SIGNAL ;
    PORT
      LAYER Metal6 ;
        RECT 177.200 0.000 177.280 1.000 ;
    END
  END rd_bitrow_i[393]
  PIN rd_bitrow_i[394]
    DIRECTION INPUT ;
    USE SIGNAL ;
    PORT
      LAYER Metal6 ;
        RECT 177.600 0.000 177.680 1.000 ;
    END
  END rd_bitrow_i[394]
  PIN rd_bitrow_i[395]
    DIRECTION INPUT ;
    USE SIGNAL ;
    PORT
      LAYER Metal6 ;
        RECT 178.000 0.000 178.080 1.000 ;
    END
  END rd_bitrow_i[395]
  PIN rd_bitrow_i[396]
    DIRECTION INPUT ;
    USE SIGNAL ;
    PORT
      LAYER Metal6 ;
        RECT 178.400 0.000 178.480 1.000 ;
    END
  END rd_bitrow_i[396]
  PIN rd_bitrow_i[397]
    DIRECTION INPUT ;
    USE SIGNAL ;
    PORT
      LAYER Metal6 ;
        RECT 178.800 0.000 178.880 1.000 ;
    END
  END rd_bitrow_i[397]
  PIN rd_bitrow_i[398]
    DIRECTION INPUT ;
    USE SIGNAL ;
    PORT
      LAYER Metal6 ;
        RECT 179.200 0.000 179.280 1.000 ;
    END
  END rd_bitrow_i[398]
  PIN rd_bitrow_i[399]
    DIRECTION INPUT ;
    USE SIGNAL ;
    PORT
      LAYER Metal6 ;
        RECT 179.600 0.000 179.680 1.000 ;
    END
  END rd_bitrow_i[399]
  PIN rd_bitrow_i[400]
    DIRECTION INPUT ;
    USE SIGNAL ;
    PORT
      LAYER Metal6 ;
        RECT 180.000 0.000 180.080 1.000 ;
    END
  END rd_bitrow_i[400]
  PIN rd_bitrow_i[401]
    DIRECTION INPUT ;
    USE SIGNAL ;
    PORT
      LAYER Metal6 ;
        RECT 180.400 0.000 180.480 1.000 ;
    END
  END rd_bitrow_i[401]
  PIN rd_bitrow_i[402]
    DIRECTION INPUT ;
    USE SIGNAL ;
    PORT
      LAYER Metal6 ;
        RECT 180.800 0.000 180.880 1.000 ;
    END
  END rd_bitrow_i[402]
  PIN rd_bitrow_i[403]
    DIRECTION INPUT ;
    USE SIGNAL ;
    PORT
      LAYER Metal6 ;
        RECT 181.200 0.000 181.280 1.000 ;
    END
  END rd_bitrow_i[403]
  PIN rd_bitrow_i[404]
    DIRECTION INPUT ;
    USE SIGNAL ;
    PORT
      LAYER Metal6 ;
        RECT 181.600 0.000 181.680 1.000 ;
    END
  END rd_bitrow_i[404]
  PIN rd_bitrow_i[405]
    DIRECTION INPUT ;
    USE SIGNAL ;
    PORT
      LAYER Metal6 ;
        RECT 182.000 0.000 182.080 1.000 ;
    END
  END rd_bitrow_i[405]
  PIN rd_bitrow_i[406]
    DIRECTION INPUT ;
    USE SIGNAL ;
    PORT
      LAYER Metal6 ;
        RECT 182.400 0.000 182.480 1.000 ;
    END
  END rd_bitrow_i[406]
  PIN rd_bitrow_i[407]
    DIRECTION INPUT ;
    USE SIGNAL ;
    PORT
      LAYER Metal6 ;
        RECT 182.800 0.000 182.880 1.000 ;
    END
  END rd_bitrow_i[407]
  PIN rd_bitrow_i[408]
    DIRECTION INPUT ;
    USE SIGNAL ;
    PORT
      LAYER Metal6 ;
        RECT 183.200 0.000 183.280 1.000 ;
    END
  END rd_bitrow_i[408]
  PIN rd_bitrow_i[409]
    DIRECTION INPUT ;
    USE SIGNAL ;
    PORT
      LAYER Metal6 ;
        RECT 183.600 0.000 183.680 1.000 ;
    END
  END rd_bitrow_i[409]
  PIN rd_bitrow_i[410]
    DIRECTION INPUT ;
    USE SIGNAL ;
    PORT
      LAYER Metal6 ;
        RECT 184.000 0.000 184.080 1.000 ;
    END
  END rd_bitrow_i[410]
  PIN rd_bitrow_i[411]
    DIRECTION INPUT ;
    USE SIGNAL ;
    PORT
      LAYER Metal6 ;
        RECT 184.400 0.000 184.480 1.000 ;
    END
  END rd_bitrow_i[411]
  PIN rd_bitrow_i[412]
    DIRECTION INPUT ;
    USE SIGNAL ;
    PORT
      LAYER Metal6 ;
        RECT 184.800 0.000 184.880 1.000 ;
    END
  END rd_bitrow_i[412]
  PIN rd_bitrow_i[413]
    DIRECTION INPUT ;
    USE SIGNAL ;
    PORT
      LAYER Metal6 ;
        RECT 185.200 0.000 185.280 1.000 ;
    END
  END rd_bitrow_i[413]
  PIN rd_bitrow_i[414]
    DIRECTION INPUT ;
    USE SIGNAL ;
    PORT
      LAYER Metal6 ;
        RECT 185.600 0.000 185.680 1.000 ;
    END
  END rd_bitrow_i[414]
  PIN rd_bitrow_i[415]
    DIRECTION INPUT ;
    USE SIGNAL ;
    PORT
      LAYER Metal6 ;
        RECT 186.000 0.000 186.080 1.000 ;
    END
  END rd_bitrow_i[415]
  PIN rd_bitrow_i[416]
    DIRECTION INPUT ;
    USE SIGNAL ;
    PORT
      LAYER Metal6 ;
        RECT 186.400 0.000 186.480 1.000 ;
    END
  END rd_bitrow_i[416]
  PIN rd_bitrow_i[417]
    DIRECTION INPUT ;
    USE SIGNAL ;
    PORT
      LAYER Metal6 ;
        RECT 186.800 0.000 186.880 1.000 ;
    END
  END rd_bitrow_i[417]
  PIN rd_bitrow_i[418]
    DIRECTION INPUT ;
    USE SIGNAL ;
    PORT
      LAYER Metal6 ;
        RECT 187.200 0.000 187.280 1.000 ;
    END
  END rd_bitrow_i[418]
  PIN rd_bitrow_i[419]
    DIRECTION INPUT ;
    USE SIGNAL ;
    PORT
      LAYER Metal6 ;
        RECT 187.600 0.000 187.680 1.000 ;
    END
  END rd_bitrow_i[419]
  PIN rd_bitrow_i[420]
    DIRECTION INPUT ;
    USE SIGNAL ;
    PORT
      LAYER Metal6 ;
        RECT 188.000 0.000 188.080 1.000 ;
    END
  END rd_bitrow_i[420]
  PIN rd_bitrow_i[421]
    DIRECTION INPUT ;
    USE SIGNAL ;
    PORT
      LAYER Metal6 ;
        RECT 188.400 0.000 188.480 1.000 ;
    END
  END rd_bitrow_i[421]
  PIN rd_bitrow_i[422]
    DIRECTION INPUT ;
    USE SIGNAL ;
    PORT
      LAYER Metal6 ;
        RECT 188.800 0.000 188.880 1.000 ;
    END
  END rd_bitrow_i[422]
  PIN rd_bitrow_i[423]
    DIRECTION INPUT ;
    USE SIGNAL ;
    PORT
      LAYER Metal6 ;
        RECT 189.200 0.000 189.280 1.000 ;
    END
  END rd_bitrow_i[423]
  PIN rd_bitrow_i[424]
    DIRECTION INPUT ;
    USE SIGNAL ;
    PORT
      LAYER Metal6 ;
        RECT 189.600 0.000 189.680 1.000 ;
    END
  END rd_bitrow_i[424]
  PIN rd_bitrow_i[425]
    DIRECTION INPUT ;
    USE SIGNAL ;
    PORT
      LAYER Metal6 ;
        RECT 190.000 0.000 190.080 1.000 ;
    END
  END rd_bitrow_i[425]
  PIN rd_bitrow_i[426]
    DIRECTION INPUT ;
    USE SIGNAL ;
    PORT
      LAYER Metal6 ;
        RECT 190.400 0.000 190.480 1.000 ;
    END
  END rd_bitrow_i[426]
  PIN rd_bitrow_i[427]
    DIRECTION INPUT ;
    USE SIGNAL ;
    PORT
      LAYER Metal6 ;
        RECT 190.800 0.000 190.880 1.000 ;
    END
  END rd_bitrow_i[427]
  PIN rd_bitrow_i[428]
    DIRECTION INPUT ;
    USE SIGNAL ;
    PORT
      LAYER Metal6 ;
        RECT 191.200 0.000 191.280 1.000 ;
    END
  END rd_bitrow_i[428]
  PIN rd_bitrow_i[429]
    DIRECTION INPUT ;
    USE SIGNAL ;
    PORT
      LAYER Metal6 ;
        RECT 191.600 0.000 191.680 1.000 ;
    END
  END rd_bitrow_i[429]
  PIN rd_bitrow_i[430]
    DIRECTION INPUT ;
    USE SIGNAL ;
    PORT
      LAYER Metal6 ;
        RECT 192.000 0.000 192.080 1.000 ;
    END
  END rd_bitrow_i[430]
  PIN rd_bitrow_i[431]
    DIRECTION INPUT ;
    USE SIGNAL ;
    PORT
      LAYER Metal6 ;
        RECT 192.400 0.000 192.480 1.000 ;
    END
  END rd_bitrow_i[431]
  PIN rd_bitrow_i[432]
    DIRECTION INPUT ;
    USE SIGNAL ;
    PORT
      LAYER Metal6 ;
        RECT 192.800 0.000 192.880 1.000 ;
    END
  END rd_bitrow_i[432]
  PIN rd_bitrow_i[433]
    DIRECTION INPUT ;
    USE SIGNAL ;
    PORT
      LAYER Metal6 ;
        RECT 193.200 0.000 193.280 1.000 ;
    END
  END rd_bitrow_i[433]
  PIN rd_bitrow_i[434]
    DIRECTION INPUT ;
    USE SIGNAL ;
    PORT
      LAYER Metal6 ;
        RECT 193.600 0.000 193.680 1.000 ;
    END
  END rd_bitrow_i[434]
  PIN rd_bitrow_i[435]
    DIRECTION INPUT ;
    USE SIGNAL ;
    PORT
      LAYER Metal6 ;
        RECT 194.000 0.000 194.080 1.000 ;
    END
  END rd_bitrow_i[435]
  PIN rd_bitrow_i[436]
    DIRECTION INPUT ;
    USE SIGNAL ;
    PORT
      LAYER Metal6 ;
        RECT 194.400 0.000 194.480 1.000 ;
    END
  END rd_bitrow_i[436]
  PIN rd_bitrow_i[437]
    DIRECTION INPUT ;
    USE SIGNAL ;
    PORT
      LAYER Metal6 ;
        RECT 194.800 0.000 194.880 1.000 ;
    END
  END rd_bitrow_i[437]
  PIN rd_bitrow_i[438]
    DIRECTION INPUT ;
    USE SIGNAL ;
    PORT
      LAYER Metal6 ;
        RECT 195.200 0.000 195.280 1.000 ;
    END
  END rd_bitrow_i[438]
  PIN rd_bitrow_i[439]
    DIRECTION INPUT ;
    USE SIGNAL ;
    PORT
      LAYER Metal6 ;
        RECT 195.600 0.000 195.680 1.000 ;
    END
  END rd_bitrow_i[439]
  PIN rd_bitrow_i[440]
    DIRECTION INPUT ;
    USE SIGNAL ;
    PORT
      LAYER Metal6 ;
        RECT 196.000 0.000 196.080 1.000 ;
    END
  END rd_bitrow_i[440]
  PIN rd_bitrow_i[441]
    DIRECTION INPUT ;
    USE SIGNAL ;
    PORT
      LAYER Metal6 ;
        RECT 196.400 0.000 196.480 1.000 ;
    END
  END rd_bitrow_i[441]
  PIN rd_bitrow_i[442]
    DIRECTION INPUT ;
    USE SIGNAL ;
    PORT
      LAYER Metal6 ;
        RECT 196.800 0.000 196.880 1.000 ;
    END
  END rd_bitrow_i[442]
  PIN rd_bitrow_i[443]
    DIRECTION INPUT ;
    USE SIGNAL ;
    PORT
      LAYER Metal6 ;
        RECT 197.200 0.000 197.280 1.000 ;
    END
  END rd_bitrow_i[443]
  PIN rd_bitrow_i[444]
    DIRECTION INPUT ;
    USE SIGNAL ;
    PORT
      LAYER Metal6 ;
        RECT 197.600 0.000 197.680 1.000 ;
    END
  END rd_bitrow_i[444]
  PIN rd_bitrow_i[445]
    DIRECTION INPUT ;
    USE SIGNAL ;
    PORT
      LAYER Metal6 ;
        RECT 198.000 0.000 198.080 1.000 ;
    END
  END rd_bitrow_i[445]
  PIN rd_bitrow_i[446]
    DIRECTION INPUT ;
    USE SIGNAL ;
    PORT
      LAYER Metal6 ;
        RECT 198.400 0.000 198.480 1.000 ;
    END
  END rd_bitrow_i[446]
  PIN rd_bitrow_i[447]
    DIRECTION INPUT ;
    USE SIGNAL ;
    PORT
      LAYER Metal6 ;
        RECT 198.800 0.000 198.880 1.000 ;
    END
  END rd_bitrow_i[447]
  PIN rd_bitrow_i[448]
    DIRECTION INPUT ;
    USE SIGNAL ;
    PORT
      LAYER Metal6 ;
        RECT 199.200 0.000 199.280 1.000 ;
    END
  END rd_bitrow_i[448]
  PIN rd_bitrow_i[449]
    DIRECTION INPUT ;
    USE SIGNAL ;
    PORT
      LAYER Metal6 ;
        RECT 199.600 0.000 199.680 1.000 ;
    END
  END rd_bitrow_i[449]
  PIN rd_bitrow_i[450]
    DIRECTION INPUT ;
    USE SIGNAL ;
    PORT
      LAYER Metal6 ;
        RECT 200.000 0.000 200.080 1.000 ;
    END
  END rd_bitrow_i[450]
  PIN rd_bitrow_i[451]
    DIRECTION INPUT ;
    USE SIGNAL ;
    PORT
      LAYER Metal6 ;
        RECT 200.400 0.000 200.480 1.000 ;
    END
  END rd_bitrow_i[451]
  PIN rd_bitrow_i[452]
    DIRECTION INPUT ;
    USE SIGNAL ;
    PORT
      LAYER Metal6 ;
        RECT 200.800 0.000 200.880 1.000 ;
    END
  END rd_bitrow_i[452]
  PIN rd_bitrow_i[453]
    DIRECTION INPUT ;
    USE SIGNAL ;
    PORT
      LAYER Metal6 ;
        RECT 201.200 0.000 201.280 1.000 ;
    END
  END rd_bitrow_i[453]
  PIN rd_bitrow_i[454]
    DIRECTION INPUT ;
    USE SIGNAL ;
    PORT
      LAYER Metal6 ;
        RECT 201.600 0.000 201.680 1.000 ;
    END
  END rd_bitrow_i[454]
  PIN rd_bitrow_i[455]
    DIRECTION INPUT ;
    USE SIGNAL ;
    PORT
      LAYER Metal6 ;
        RECT 202.000 0.000 202.080 1.000 ;
    END
  END rd_bitrow_i[455]
  PIN rd_bitrow_i[456]
    DIRECTION INPUT ;
    USE SIGNAL ;
    PORT
      LAYER Metal6 ;
        RECT 202.400 0.000 202.480 1.000 ;
    END
  END rd_bitrow_i[456]
  PIN rd_bitrow_i[457]
    DIRECTION INPUT ;
    USE SIGNAL ;
    PORT
      LAYER Metal6 ;
        RECT 202.800 0.000 202.880 1.000 ;
    END
  END rd_bitrow_i[457]
  PIN rd_bitrow_i[458]
    DIRECTION INPUT ;
    USE SIGNAL ;
    PORT
      LAYER Metal6 ;
        RECT 203.200 0.000 203.280 1.000 ;
    END
  END rd_bitrow_i[458]
  PIN rd_bitrow_i[459]
    DIRECTION INPUT ;
    USE SIGNAL ;
    PORT
      LAYER Metal6 ;
        RECT 203.600 0.000 203.680 1.000 ;
    END
  END rd_bitrow_i[459]
  PIN rd_bitrow_i[460]
    DIRECTION INPUT ;
    USE SIGNAL ;
    PORT
      LAYER Metal6 ;
        RECT 204.000 0.000 204.080 1.000 ;
    END
  END rd_bitrow_i[460]
  PIN rd_bitrow_i[461]
    DIRECTION INPUT ;
    USE SIGNAL ;
    PORT
      LAYER Metal6 ;
        RECT 204.400 0.000 204.480 1.000 ;
    END
  END rd_bitrow_i[461]
  PIN rd_bitrow_i[462]
    DIRECTION INPUT ;
    USE SIGNAL ;
    PORT
      LAYER Metal6 ;
        RECT 204.800 0.000 204.880 1.000 ;
    END
  END rd_bitrow_i[462]
  PIN rd_bitrow_i[463]
    DIRECTION INPUT ;
    USE SIGNAL ;
    PORT
      LAYER Metal6 ;
        RECT 205.200 0.000 205.280 1.000 ;
    END
  END rd_bitrow_i[463]
  PIN rd_bitrow_i[464]
    DIRECTION INPUT ;
    USE SIGNAL ;
    PORT
      LAYER Metal6 ;
        RECT 205.600 0.000 205.680 1.000 ;
    END
  END rd_bitrow_i[464]
  PIN rd_bitrow_i[465]
    DIRECTION INPUT ;
    USE SIGNAL ;
    PORT
      LAYER Metal6 ;
        RECT 206.000 0.000 206.080 1.000 ;
    END
  END rd_bitrow_i[465]
  PIN rd_bitrow_i[466]
    DIRECTION INPUT ;
    USE SIGNAL ;
    PORT
      LAYER Metal6 ;
        RECT 206.400 0.000 206.480 1.000 ;
    END
  END rd_bitrow_i[466]
  PIN rd_bitrow_i[467]
    DIRECTION INPUT ;
    USE SIGNAL ;
    PORT
      LAYER Metal6 ;
        RECT 206.800 0.000 206.880 1.000 ;
    END
  END rd_bitrow_i[467]
  PIN rd_bitrow_i[468]
    DIRECTION INPUT ;
    USE SIGNAL ;
    PORT
      LAYER Metal6 ;
        RECT 207.200 0.000 207.280 1.000 ;
    END
  END rd_bitrow_i[468]
  PIN rd_bitrow_i[469]
    DIRECTION INPUT ;
    USE SIGNAL ;
    PORT
      LAYER Metal6 ;
        RECT 207.600 0.000 207.680 1.000 ;
    END
  END rd_bitrow_i[469]
  PIN rd_bitrow_i[470]
    DIRECTION INPUT ;
    USE SIGNAL ;
    PORT
      LAYER Metal6 ;
        RECT 208.000 0.000 208.080 1.000 ;
    END
  END rd_bitrow_i[470]
  PIN rd_bitrow_i[471]
    DIRECTION INPUT ;
    USE SIGNAL ;
    PORT
      LAYER Metal6 ;
        RECT 208.400 0.000 208.480 1.000 ;
    END
  END rd_bitrow_i[471]
  PIN rd_bitrow_i[472]
    DIRECTION INPUT ;
    USE SIGNAL ;
    PORT
      LAYER Metal6 ;
        RECT 208.800 0.000 208.880 1.000 ;
    END
  END rd_bitrow_i[472]
  PIN rd_bitrow_i[473]
    DIRECTION INPUT ;
    USE SIGNAL ;
    PORT
      LAYER Metal6 ;
        RECT 209.200 0.000 209.280 1.000 ;
    END
  END rd_bitrow_i[473]
  PIN rd_bitrow_i[474]
    DIRECTION INPUT ;
    USE SIGNAL ;
    PORT
      LAYER Metal6 ;
        RECT 209.600 0.000 209.680 1.000 ;
    END
  END rd_bitrow_i[474]
  PIN rd_bitrow_i[475]
    DIRECTION INPUT ;
    USE SIGNAL ;
    PORT
      LAYER Metal6 ;
        RECT 210.000 0.000 210.080 1.000 ;
    END
  END rd_bitrow_i[475]
  PIN rd_bitrow_i[476]
    DIRECTION INPUT ;
    USE SIGNAL ;
    PORT
      LAYER Metal6 ;
        RECT 210.400 0.000 210.480 1.000 ;
    END
  END rd_bitrow_i[476]
  PIN rd_bitrow_i[477]
    DIRECTION INPUT ;
    USE SIGNAL ;
    PORT
      LAYER Metal6 ;
        RECT 210.800 0.000 210.880 1.000 ;
    END
  END rd_bitrow_i[477]
  PIN rd_bitrow_i[478]
    DIRECTION INPUT ;
    USE SIGNAL ;
    PORT
      LAYER Metal6 ;
        RECT 211.200 0.000 211.280 1.000 ;
    END
  END rd_bitrow_i[478]
  PIN rd_bitrow_i[479]
    DIRECTION INPUT ;
    USE SIGNAL ;
    PORT
      LAYER Metal6 ;
        RECT 211.600 0.000 211.680 1.000 ;
    END
  END rd_bitrow_i[479]
  PIN rd_bitrow_i[480]
    DIRECTION INPUT ;
    USE SIGNAL ;
    PORT
      LAYER Metal6 ;
        RECT 212.000 0.000 212.080 1.000 ;
    END
  END rd_bitrow_i[480]
  PIN rd_bitrow_i[481]
    DIRECTION INPUT ;
    USE SIGNAL ;
    PORT
      LAYER Metal6 ;
        RECT 212.400 0.000 212.480 1.000 ;
    END
  END rd_bitrow_i[481]
  PIN rd_bitrow_i[482]
    DIRECTION INPUT ;
    USE SIGNAL ;
    PORT
      LAYER Metal6 ;
        RECT 212.800 0.000 212.880 1.000 ;
    END
  END rd_bitrow_i[482]
  PIN rd_bitrow_i[483]
    DIRECTION INPUT ;
    USE SIGNAL ;
    PORT
      LAYER Metal6 ;
        RECT 213.200 0.000 213.280 1.000 ;
    END
  END rd_bitrow_i[483]
  PIN rd_bitrow_i[484]
    DIRECTION INPUT ;
    USE SIGNAL ;
    PORT
      LAYER Metal6 ;
        RECT 213.600 0.000 213.680 1.000 ;
    END
  END rd_bitrow_i[484]
  PIN rd_bitrow_i[485]
    DIRECTION INPUT ;
    USE SIGNAL ;
    PORT
      LAYER Metal6 ;
        RECT 214.000 0.000 214.080 1.000 ;
    END
  END rd_bitrow_i[485]
  PIN rd_bitrow_i[486]
    DIRECTION INPUT ;
    USE SIGNAL ;
    PORT
      LAYER Metal6 ;
        RECT 214.400 0.000 214.480 1.000 ;
    END
  END rd_bitrow_i[486]
  PIN rd_bitrow_i[487]
    DIRECTION INPUT ;
    USE SIGNAL ;
    PORT
      LAYER Metal6 ;
        RECT 214.800 0.000 214.880 1.000 ;
    END
  END rd_bitrow_i[487]
  PIN rd_bitrow_i[488]
    DIRECTION INPUT ;
    USE SIGNAL ;
    PORT
      LAYER Metal6 ;
        RECT 215.200 0.000 215.280 1.000 ;
    END
  END rd_bitrow_i[488]
  PIN rd_bitrow_i[489]
    DIRECTION INPUT ;
    USE SIGNAL ;
    PORT
      LAYER Metal6 ;
        RECT 215.600 0.000 215.680 1.000 ;
    END
  END rd_bitrow_i[489]
  PIN rd_bitrow_i[490]
    DIRECTION INPUT ;
    USE SIGNAL ;
    PORT
      LAYER Metal6 ;
        RECT 216.000 0.000 216.080 1.000 ;
    END
  END rd_bitrow_i[490]
  PIN rd_bitrow_i[491]
    DIRECTION INPUT ;
    USE SIGNAL ;
    PORT
      LAYER Metal6 ;
        RECT 216.400 0.000 216.480 1.000 ;
    END
  END rd_bitrow_i[491]
  PIN rd_bitrow_i[492]
    DIRECTION INPUT ;
    USE SIGNAL ;
    PORT
      LAYER Metal6 ;
        RECT 216.800 0.000 216.880 1.000 ;
    END
  END rd_bitrow_i[492]
  PIN rd_bitrow_i[493]
    DIRECTION INPUT ;
    USE SIGNAL ;
    PORT
      LAYER Metal6 ;
        RECT 217.200 0.000 217.280 1.000 ;
    END
  END rd_bitrow_i[493]
  PIN rd_bitrow_i[494]
    DIRECTION INPUT ;
    USE SIGNAL ;
    PORT
      LAYER Metal6 ;
        RECT 217.600 0.000 217.680 1.000 ;
    END
  END rd_bitrow_i[494]
  PIN rd_bitrow_i[495]
    DIRECTION INPUT ;
    USE SIGNAL ;
    PORT
      LAYER Metal6 ;
        RECT 218.000 0.000 218.080 1.000 ;
    END
  END rd_bitrow_i[495]
  PIN rd_bitrow_i[496]
    DIRECTION INPUT ;
    USE SIGNAL ;
    PORT
      LAYER Metal6 ;
        RECT 218.400 0.000 218.480 1.000 ;
    END
  END rd_bitrow_i[496]
  PIN rd_bitrow_i[497]
    DIRECTION INPUT ;
    USE SIGNAL ;
    PORT
      LAYER Metal6 ;
        RECT 218.800 0.000 218.880 1.000 ;
    END
  END rd_bitrow_i[497]
  PIN rd_bitrow_i[498]
    DIRECTION INPUT ;
    USE SIGNAL ;
    PORT
      LAYER Metal6 ;
        RECT 219.200 0.000 219.280 1.000 ;
    END
  END rd_bitrow_i[498]
  PIN rd_bitrow_i[499]
    DIRECTION INPUT ;
    USE SIGNAL ;
    PORT
      LAYER Metal6 ;
        RECT 219.600 0.000 219.680 1.000 ;
    END
  END rd_bitrow_i[499]
  PIN rd_bitrow_i[500]
    DIRECTION INPUT ;
    USE SIGNAL ;
    PORT
      LAYER Metal6 ;
        RECT 220.000 0.000 220.080 1.000 ;
    END
  END rd_bitrow_i[500]
  PIN rd_bitrow_i[501]
    DIRECTION INPUT ;
    USE SIGNAL ;
    PORT
      LAYER Metal6 ;
        RECT 220.400 0.000 220.480 1.000 ;
    END
  END rd_bitrow_i[501]
  PIN rd_bitrow_i[502]
    DIRECTION INPUT ;
    USE SIGNAL ;
    PORT
      LAYER Metal6 ;
        RECT 220.800 0.000 220.880 1.000 ;
    END
  END rd_bitrow_i[502]
  PIN rd_bitrow_i[503]
    DIRECTION INPUT ;
    USE SIGNAL ;
    PORT
      LAYER Metal6 ;
        RECT 221.200 0.000 221.280 1.000 ;
    END
  END rd_bitrow_i[503]
  PIN rd_bitrow_i[504]
    DIRECTION INPUT ;
    USE SIGNAL ;
    PORT
      LAYER Metal6 ;
        RECT 221.600 0.000 221.680 1.000 ;
    END
  END rd_bitrow_i[504]
  PIN rd_bitrow_i[505]
    DIRECTION INPUT ;
    USE SIGNAL ;
    PORT
      LAYER Metal6 ;
        RECT 222.000 0.000 222.080 1.000 ;
    END
  END rd_bitrow_i[505]
  PIN rd_bitrow_i[506]
    DIRECTION INPUT ;
    USE SIGNAL ;
    PORT
      LAYER Metal6 ;
        RECT 222.400 0.000 222.480 1.000 ;
    END
  END rd_bitrow_i[506]
  PIN rd_bitrow_i[507]
    DIRECTION INPUT ;
    USE SIGNAL ;
    PORT
      LAYER Metal6 ;
        RECT 222.800 0.000 222.880 1.000 ;
    END
  END rd_bitrow_i[507]
  PIN rd_bitrow_i[508]
    DIRECTION INPUT ;
    USE SIGNAL ;
    PORT
      LAYER Metal6 ;
        RECT 223.200 0.000 223.280 1.000 ;
    END
  END rd_bitrow_i[508]
  PIN rd_bitrow_i[509]
    DIRECTION INPUT ;
    USE SIGNAL ;
    PORT
      LAYER Metal6 ;
        RECT 223.600 0.000 223.680 1.000 ;
    END
  END rd_bitrow_i[509]
  PIN rd_bitrow_i[510]
    DIRECTION INPUT ;
    USE SIGNAL ;
    PORT
      LAYER Metal6 ;
        RECT 224.000 0.000 224.080 1.000 ;
    END
  END rd_bitrow_i[510]
  PIN rd_bitrow_i[511]
    DIRECTION INPUT ;
    USE SIGNAL ;
    PORT
      LAYER Metal6 ;
        RECT 224.400 0.000 224.480 1.000 ;
    END
  END rd_bitrow_i[511]
  PIN rd_grp_i[0]
    DIRECTION INPUT ;
    USE SIGNAL ;
    PORT
      LAYER Metal6 ;
        RECT 224.800 0.000 224.880 1.000 ;
    END
  END rd_grp_i[0]
  PIN rd_grp_i[1]
    DIRECTION INPUT ;
    USE SIGNAL ;
    PORT
      LAYER Metal6 ;
        RECT 225.200 0.000 225.280 1.000 ;
    END
  END rd_grp_i[1]
  PIN rd_grp_i[2]
    DIRECTION INPUT ;
    USE SIGNAL ;
    PORT
      LAYER Metal6 ;
        RECT 225.600 0.000 225.680 1.000 ;
    END
  END rd_grp_i[2]
  PIN rd_grp_i[3]
    DIRECTION INPUT ;
    USE SIGNAL ;
    PORT
      LAYER Metal6 ;
        RECT 226.000 0.000 226.080 1.000 ;
    END
  END rd_grp_i[3]
  PIN rd_grp_i[4]
    DIRECTION INPUT ;
    USE SIGNAL ;
    PORT
      LAYER Metal6 ;
        RECT 226.400 0.000 226.480 1.000 ;
    END
  END rd_grp_i[4]
  PIN rd_grp_i[5]
    DIRECTION INPUT ;
    USE SIGNAL ;
    PORT
      LAYER Metal6 ;
        RECT 226.800 0.000 226.880 1.000 ;
    END
  END rd_grp_i[5]
  PIN rd_grp_i[6]
    DIRECTION INPUT ;
    USE SIGNAL ;
    PORT
      LAYER Metal6 ;
        RECT 227.200 0.000 227.280 1.000 ;
    END
  END rd_grp_i[6]
  PIN rd_grp_i[7]
    DIRECTION INPUT ;
    USE SIGNAL ;
    PORT
      LAYER Metal6 ;
        RECT 227.600 0.000 227.680 1.000 ;
    END
  END rd_grp_i[7]
  PIN rd_grp_i[8]
    DIRECTION INPUT ;
    USE SIGNAL ;
    PORT
      LAYER Metal6 ;
        RECT 228.000 0.000 228.080 1.000 ;
    END
  END rd_grp_i[8]
  PIN rd_plane_mask_i[0]
    DIRECTION INPUT ;
    USE SIGNAL ;
    PORT
      LAYER Metal6 ;
        RECT 228.400 0.000 228.480 1.000 ;
    END
  END rd_plane_mask_i[0]
  PIN rd_plane_mask_i[1]
    DIRECTION INPUT ;
    USE SIGNAL ;
    PORT
      LAYER Metal6 ;
        RECT 228.800 0.000 228.880 1.000 ;
    END
  END rd_plane_mask_i[1]
  PIN rd_plane_mask_i[2]
    DIRECTION INPUT ;
    USE SIGNAL ;
    PORT
      LAYER Metal6 ;
        RECT 229.200 0.000 229.280 1.000 ;
    END
  END rd_plane_mask_i[2]
  PIN rd_plane_mask_i[3]
    DIRECTION INPUT ;
    USE SIGNAL ;
    PORT
      LAYER Metal6 ;
        RECT 229.600 0.000 229.680 1.000 ;
    END
  END rd_plane_mask_i[3]
  PIN rd_plane_mask_i[4]
    DIRECTION INPUT ;
    USE SIGNAL ;
    PORT
      LAYER Metal6 ;
        RECT 230.000 0.000 230.080 1.000 ;
    END
  END rd_plane_mask_i[4]
  PIN rd_plane_mask_i[5]
    DIRECTION INPUT ;
    USE SIGNAL ;
    PORT
      LAYER Metal6 ;
        RECT 230.400 0.000 230.480 1.000 ;
    END
  END rd_plane_mask_i[5]
  PIN rd_plane_mask_i[6]
    DIRECTION INPUT ;
    USE SIGNAL ;
    PORT
      LAYER Metal6 ;
        RECT 230.800 0.000 230.880 1.000 ;
    END
  END rd_plane_mask_i[6]
  PIN rd_plane_mask_i[7]
    DIRECTION INPUT ;
    USE SIGNAL ;
    PORT
      LAYER Metal6 ;
        RECT 231.200 0.000 231.280 1.000 ;
    END
  END rd_plane_mask_i[7]
  PIN VDD
    DIRECTION INOUT ;
    USE POWER ;
    PORT
      LAYER Metal10 ;
        RECT 5.000 2.000 6.000 763.370 ;
      LAYER Metal10 ;
        RECT 21.000 2.000 22.000 763.370 ;
      LAYER Metal10 ;
        RECT 37.000 2.000 38.000 763.370 ;
      LAYER Metal10 ;
        RECT 53.000 2.000 54.000 763.370 ;
      LAYER Metal10 ;
        RECT 69.000 2.000 70.000 763.370 ;
      LAYER Metal10 ;
        RECT 85.000 2.000 86.000 763.370 ;
      LAYER Metal10 ;
        RECT 101.000 2.000 102.000 763.370 ;
      LAYER Metal10 ;
        RECT 117.000 2.000 118.000 763.370 ;
      LAYER Metal10 ;
        RECT 133.000 2.000 134.000 763.370 ;
      LAYER Metal10 ;
        RECT 149.000 2.000 150.000 763.370 ;
      LAYER Metal10 ;
        RECT 165.000 2.000 166.000 763.370 ;
      LAYER Metal10 ;
        RECT 181.000 2.000 182.000 763.370 ;
      LAYER Metal10 ;
        RECT 197.000 2.000 198.000 763.370 ;
      LAYER Metal10 ;
        RECT 213.000 2.000 214.000 763.370 ;
      LAYER Metal10 ;
        RECT 229.000 2.000 230.000 763.370 ;
      LAYER Metal10 ;
        RECT 245.000 2.000 246.000 763.370 ;
      LAYER Metal10 ;
        RECT 261.000 2.000 262.000 763.370 ;
      LAYER Metal10 ;
        RECT 277.000 2.000 278.000 763.370 ;
      LAYER Metal10 ;
        RECT 293.000 2.000 294.000 763.370 ;
      LAYER Metal10 ;
        RECT 309.000 2.000 310.000 763.370 ;
      LAYER Metal10 ;
        RECT 325.000 2.000 326.000 763.370 ;
      LAYER Metal10 ;
        RECT 341.000 2.000 342.000 763.370 ;
      LAYER Metal10 ;
        RECT 357.000 2.000 358.000 763.370 ;
      LAYER Metal10 ;
        RECT 373.000 2.000 374.000 763.370 ;
      LAYER Metal10 ;
        RECT 389.000 2.000 390.000 763.370 ;
      LAYER Metal10 ;
        RECT 405.000 2.000 406.000 763.370 ;
      LAYER Metal10 ;
        RECT 421.000 2.000 422.000 763.370 ;
      LAYER Metal10 ;
        RECT 437.000 2.000 438.000 763.370 ;
      LAYER Metal10 ;
        RECT 453.000 2.000 454.000 763.370 ;
      LAYER Metal10 ;
        RECT 469.000 2.000 470.000 763.370 ;
      LAYER Metal10 ;
        RECT 485.000 2.000 486.000 763.370 ;
      LAYER Metal10 ;
        RECT 501.000 2.000 502.000 763.370 ;
      LAYER Metal10 ;
        RECT 517.000 2.000 518.000 763.370 ;
      LAYER Metal10 ;
        RECT 533.000 2.000 534.000 763.370 ;
      LAYER Metal10 ;
        RECT 549.000 2.000 550.000 763.370 ;
      LAYER Metal10 ;
        RECT 565.000 2.000 566.000 763.370 ;
      LAYER Metal10 ;
        RECT 581.000 2.000 582.000 763.370 ;
      LAYER Metal10 ;
        RECT 597.000 2.000 598.000 763.370 ;
      LAYER Metal10 ;
        RECT 613.000 2.000 614.000 763.370 ;
      LAYER Metal10 ;
        RECT 629.000 2.000 630.000 763.370 ;
      LAYER Metal10 ;
        RECT 645.000 2.000 646.000 763.370 ;
      LAYER Metal10 ;
        RECT 661.000 2.000 662.000 763.370 ;
      LAYER Metal10 ;
        RECT 677.000 2.000 678.000 763.370 ;
      LAYER Metal10 ;
        RECT 693.000 2.000 694.000 763.370 ;
      LAYER Metal10 ;
        RECT 709.000 2.000 710.000 763.370 ;
      LAYER Metal10 ;
        RECT 725.000 2.000 726.000 763.370 ;
      LAYER Metal10 ;
        RECT 741.000 2.000 742.000 763.370 ;
      LAYER Metal10 ;
        RECT 757.000 2.000 758.000 763.370 ;
    END
  END VDD
  PIN VSS
    DIRECTION INOUT ;
    USE GROUND ;
    PORT
      LAYER Metal10 ;
        RECT 9.000 2.000 10.000 763.370 ;
      LAYER Metal10 ;
        RECT 25.000 2.000 26.000 763.370 ;
      LAYER Metal10 ;
        RECT 41.000 2.000 42.000 763.370 ;
      LAYER Metal10 ;
        RECT 57.000 2.000 58.000 763.370 ;
      LAYER Metal10 ;
        RECT 73.000 2.000 74.000 763.370 ;
      LAYER Metal10 ;
        RECT 89.000 2.000 90.000 763.370 ;
      LAYER Metal10 ;
        RECT 105.000 2.000 106.000 763.370 ;
      LAYER Metal10 ;
        RECT 121.000 2.000 122.000 763.370 ;
      LAYER Metal10 ;
        RECT 137.000 2.000 138.000 763.370 ;
      LAYER Metal10 ;
        RECT 153.000 2.000 154.000 763.370 ;
      LAYER Metal10 ;
        RECT 169.000 2.000 170.000 763.370 ;
      LAYER Metal10 ;
        RECT 185.000 2.000 186.000 763.370 ;
      LAYER Metal10 ;
        RECT 201.000 2.000 202.000 763.370 ;
      LAYER Metal10 ;
        RECT 217.000 2.000 218.000 763.370 ;
      LAYER Metal10 ;
        RECT 233.000 2.000 234.000 763.370 ;
      LAYER Metal10 ;
        RECT 249.000 2.000 250.000 763.370 ;
      LAYER Metal10 ;
        RECT 265.000 2.000 266.000 763.370 ;
      LAYER Metal10 ;
        RECT 281.000 2.000 282.000 763.370 ;
      LAYER Metal10 ;
        RECT 297.000 2.000 298.000 763.370 ;
      LAYER Metal10 ;
        RECT 313.000 2.000 314.000 763.370 ;
      LAYER Metal10 ;
        RECT 329.000 2.000 330.000 763.370 ;
      LAYER Metal10 ;
        RECT 345.000 2.000 346.000 763.370 ;
      LAYER Metal10 ;
        RECT 361.000 2.000 362.000 763.370 ;
      LAYER Metal10 ;
        RECT 377.000 2.000 378.000 763.370 ;
      LAYER Metal10 ;
        RECT 393.000 2.000 394.000 763.370 ;
      LAYER Metal10 ;
        RECT 409.000 2.000 410.000 763.370 ;
      LAYER Metal10 ;
        RECT 425.000 2.000 426.000 763.370 ;
      LAYER Metal10 ;
        RECT 441.000 2.000 442.000 763.370 ;
      LAYER Metal10 ;
        RECT 457.000 2.000 458.000 763.370 ;
      LAYER Metal10 ;
        RECT 473.000 2.000 474.000 763.370 ;
      LAYER Metal10 ;
        RECT 489.000 2.000 490.000 763.370 ;
      LAYER Metal10 ;
        RECT 505.000 2.000 506.000 763.370 ;
      LAYER Metal10 ;
        RECT 521.000 2.000 522.000 763.370 ;
      LAYER Metal10 ;
        RECT 537.000 2.000 538.000 763.370 ;
      LAYER Metal10 ;
        RECT 553.000 2.000 554.000 763.370 ;
      LAYER Metal10 ;
        RECT 569.000 2.000 570.000 763.370 ;
      LAYER Metal10 ;
        RECT 585.000 2.000 586.000 763.370 ;
      LAYER Metal10 ;
        RECT 601.000 2.000 602.000 763.370 ;
      LAYER Metal10 ;
        RECT 617.000 2.000 618.000 763.370 ;
      LAYER Metal10 ;
        RECT 633.000 2.000 634.000 763.370 ;
      LAYER Metal10 ;
        RECT 649.000 2.000 650.000 763.370 ;
      LAYER Metal10 ;
        RECT 665.000 2.000 666.000 763.370 ;
      LAYER Metal10 ;
        RECT 681.000 2.000 682.000 763.370 ;
      LAYER Metal10 ;
        RECT 697.000 2.000 698.000 763.370 ;
      LAYER Metal10 ;
        RECT 713.000 2.000 714.000 763.370 ;
      LAYER Metal10 ;
        RECT 729.000 2.000 730.000 763.370 ;
      LAYER Metal10 ;
        RECT 745.000 2.000 746.000 763.370 ;
      LAYER Metal10 ;
        RECT 761.000 2.000 762.000 763.370 ;
    END
  END VSS
  OBS
    LAYER Metal1 ;
      RECT 0 1.200 763.2 764.37 ;
    LAYER Metal2 ;
      RECT 0 1.200 763.2 764.37 ;
    LAYER Metal3 ;
      RECT 0 1.200 763.2 764.37 ;
    LAYER Metal4 ;
      RECT 0 1.200 763.2 764.37 ;
    LAYER Metal5 ;
      RECT 0 1.200 763.2 764.37 ;
    LAYER Metal6 ;
      RECT 0 1.200 763.2 764.37 ;
    LAYER Metal7 ;
      RECT 0 1.200 763.2 764.37 ;
    LAYER Metal8 ;
      RECT 0 1.200 763.2 764.37 ;
    LAYER Metal9 ;
      RECT 0 1.200 763.2 764.37 ;
    LAYER Metal10 ;
      RECT 0 1.200 763.2 764.37 ;
  END
END cim_macro

END LIBRARY
